VERSION 5.7 ;
  NOWIREEXTENSIONATPIN ON ;
  DIVIDERCHAR "/" ;
  BUSBITCHARS "[]" ;
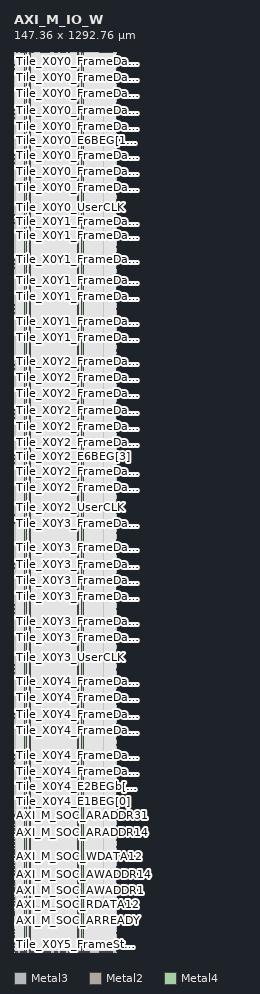
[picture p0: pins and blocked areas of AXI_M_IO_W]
MACRO AXI_M_IO_W
  CLASS BLOCK ;
  FOREIGN AXI_M_IO_W ;
  ORIGIN 0.000 0.000 ;
  SIZE 147.360 BY 1292.760 ;
  PIN AXI_M_SOC_ARADDR0
    DIRECTION OUTPUT ;
    USE SIGNAL ;
    ANTENNADIFFAREA 2.647800 ;
    PORT
      LAYER Metal3 ;
        RECT 0.000 158.980 0.400 159.380 ;
    END
  END AXI_M_SOC_ARADDR0
  PIN AXI_M_SOC_ARADDR1
    DIRECTION OUTPUT ;
    USE SIGNAL ;
    ANTENNADIFFAREA 2.647800 ;
    PORT
      LAYER Metal3 ;
        RECT 0.000 159.820 0.400 160.220 ;
    END
  END AXI_M_SOC_ARADDR1
  PIN AXI_M_SOC_ARADDR10
    DIRECTION OUTPUT ;
    USE SIGNAL ;
    ANTENNADIFFAREA 2.647800 ;
    PORT
      LAYER Metal3 ;
        RECT 0.000 167.380 0.400 167.780 ;
    END
  END AXI_M_SOC_ARADDR10
  PIN AXI_M_SOC_ARADDR11
    DIRECTION OUTPUT ;
    USE SIGNAL ;
    ANTENNADIFFAREA 2.647800 ;
    PORT
      LAYER Metal3 ;
        RECT 0.000 168.220 0.400 168.620 ;
    END
  END AXI_M_SOC_ARADDR11
  PIN AXI_M_SOC_ARADDR12
    DIRECTION OUTPUT ;
    USE SIGNAL ;
    ANTENNADIFFAREA 2.647800 ;
    PORT
      LAYER Metal3 ;
        RECT 0.000 169.060 0.400 169.460 ;
    END
  END AXI_M_SOC_ARADDR12
  PIN AXI_M_SOC_ARADDR13
    DIRECTION OUTPUT ;
    USE SIGNAL ;
    ANTENNADIFFAREA 2.647800 ;
    PORT
      LAYER Metal3 ;
        RECT 0.000 169.900 0.400 170.300 ;
    END
  END AXI_M_SOC_ARADDR13
  PIN AXI_M_SOC_ARADDR14
    DIRECTION OUTPUT ;
    USE SIGNAL ;
    ANTENNADIFFAREA 2.647800 ;
    PORT
      LAYER Metal3 ;
        RECT 0.000 170.740 0.400 171.140 ;
    END
  END AXI_M_SOC_ARADDR14
  PIN AXI_M_SOC_ARADDR15
    DIRECTION OUTPUT ;
    USE SIGNAL ;
    ANTENNADIFFAREA 2.647800 ;
    PORT
      LAYER Metal3 ;
        RECT 0.000 171.580 0.400 171.980 ;
    END
  END AXI_M_SOC_ARADDR15
  PIN AXI_M_SOC_ARADDR16
    DIRECTION OUTPUT ;
    USE SIGNAL ;
    ANTENNADIFFAREA 2.647800 ;
    PORT
      LAYER Metal3 ;
        RECT 0.000 172.420 0.400 172.820 ;
    END
  END AXI_M_SOC_ARADDR16
  PIN AXI_M_SOC_ARADDR17
    DIRECTION OUTPUT ;
    USE SIGNAL ;
    ANTENNADIFFAREA 2.647800 ;
    PORT
      LAYER Metal3 ;
        RECT 0.000 173.260 0.400 173.660 ;
    END
  END AXI_M_SOC_ARADDR17
  PIN AXI_M_SOC_ARADDR18
    DIRECTION OUTPUT ;
    USE SIGNAL ;
    ANTENNADIFFAREA 2.647800 ;
    PORT
      LAYER Metal3 ;
        RECT 0.000 174.100 0.400 174.500 ;
    END
  END AXI_M_SOC_ARADDR18
  PIN AXI_M_SOC_ARADDR19
    DIRECTION OUTPUT ;
    USE SIGNAL ;
    ANTENNADIFFAREA 2.647800 ;
    PORT
      LAYER Metal3 ;
        RECT 0.000 174.940 0.400 175.340 ;
    END
  END AXI_M_SOC_ARADDR19
  PIN AXI_M_SOC_ARADDR2
    DIRECTION OUTPUT ;
    USE SIGNAL ;
    ANTENNADIFFAREA 2.647800 ;
    PORT
      LAYER Metal3 ;
        RECT 0.000 160.660 0.400 161.060 ;
    END
  END AXI_M_SOC_ARADDR2
  PIN AXI_M_SOC_ARADDR20
    DIRECTION OUTPUT ;
    USE SIGNAL ;
    ANTENNADIFFAREA 2.647800 ;
    PORT
      LAYER Metal3 ;
        RECT 0.000 175.780 0.400 176.180 ;
    END
  END AXI_M_SOC_ARADDR20
  PIN AXI_M_SOC_ARADDR21
    DIRECTION OUTPUT ;
    USE SIGNAL ;
    ANTENNADIFFAREA 2.647800 ;
    PORT
      LAYER Metal3 ;
        RECT 0.000 176.620 0.400 177.020 ;
    END
  END AXI_M_SOC_ARADDR21
  PIN AXI_M_SOC_ARADDR22
    DIRECTION OUTPUT ;
    USE SIGNAL ;
    ANTENNADIFFAREA 2.647800 ;
    PORT
      LAYER Metal3 ;
        RECT 0.000 177.460 0.400 177.860 ;
    END
  END AXI_M_SOC_ARADDR22
  PIN AXI_M_SOC_ARADDR23
    DIRECTION OUTPUT ;
    USE SIGNAL ;
    ANTENNADIFFAREA 2.647800 ;
    PORT
      LAYER Metal3 ;
        RECT 0.000 178.300 0.400 178.700 ;
    END
  END AXI_M_SOC_ARADDR23
  PIN AXI_M_SOC_ARADDR24
    DIRECTION OUTPUT ;
    USE SIGNAL ;
    ANTENNADIFFAREA 2.647800 ;
    PORT
      LAYER Metal3 ;
        RECT 0.000 179.140 0.400 179.540 ;
    END
  END AXI_M_SOC_ARADDR24
  PIN AXI_M_SOC_ARADDR25
    DIRECTION OUTPUT ;
    USE SIGNAL ;
    ANTENNADIFFAREA 2.647800 ;
    PORT
      LAYER Metal3 ;
        RECT 0.000 179.980 0.400 180.380 ;
    END
  END AXI_M_SOC_ARADDR25
  PIN AXI_M_SOC_ARADDR26
    DIRECTION OUTPUT ;
    USE SIGNAL ;
    ANTENNADIFFAREA 2.647800 ;
    PORT
      LAYER Metal3 ;
        RECT 0.000 180.820 0.400 181.220 ;
    END
  END AXI_M_SOC_ARADDR26
  PIN AXI_M_SOC_ARADDR27
    DIRECTION OUTPUT ;
    USE SIGNAL ;
    ANTENNADIFFAREA 2.647800 ;
    PORT
      LAYER Metal3 ;
        RECT 0.000 181.660 0.400 182.060 ;
    END
  END AXI_M_SOC_ARADDR27
  PIN AXI_M_SOC_ARADDR28
    DIRECTION OUTPUT ;
    USE SIGNAL ;
    ANTENNADIFFAREA 2.647800 ;
    PORT
      LAYER Metal3 ;
        RECT 0.000 182.500 0.400 182.900 ;
    END
  END AXI_M_SOC_ARADDR28
  PIN AXI_M_SOC_ARADDR29
    DIRECTION OUTPUT ;
    USE SIGNAL ;
    ANTENNADIFFAREA 2.647800 ;
    PORT
      LAYER Metal3 ;
        RECT 0.000 183.340 0.400 183.740 ;
    END
  END AXI_M_SOC_ARADDR29
  PIN AXI_M_SOC_ARADDR3
    DIRECTION OUTPUT ;
    USE SIGNAL ;
    ANTENNADIFFAREA 2.647800 ;
    PORT
      LAYER Metal3 ;
        RECT 0.000 161.500 0.400 161.900 ;
    END
  END AXI_M_SOC_ARADDR3
  PIN AXI_M_SOC_ARADDR30
    DIRECTION OUTPUT ;
    USE SIGNAL ;
    ANTENNADIFFAREA 2.647800 ;
    PORT
      LAYER Metal3 ;
        RECT 0.000 184.180 0.400 184.580 ;
    END
  END AXI_M_SOC_ARADDR30
  PIN AXI_M_SOC_ARADDR31
    DIRECTION OUTPUT ;
    USE SIGNAL ;
    ANTENNADIFFAREA 2.647800 ;
    PORT
      LAYER Metal3 ;
        RECT 0.000 185.020 0.400 185.420 ;
    END
  END AXI_M_SOC_ARADDR31
  PIN AXI_M_SOC_ARADDR4
    DIRECTION OUTPUT ;
    USE SIGNAL ;
    ANTENNADIFFAREA 2.647800 ;
    PORT
      LAYER Metal3 ;
        RECT 0.000 162.340 0.400 162.740 ;
    END
  END AXI_M_SOC_ARADDR4
  PIN AXI_M_SOC_ARADDR5
    DIRECTION OUTPUT ;
    USE SIGNAL ;
    ANTENNADIFFAREA 2.647800 ;
    PORT
      LAYER Metal3 ;
        RECT 0.000 163.180 0.400 163.580 ;
    END
  END AXI_M_SOC_ARADDR5
  PIN AXI_M_SOC_ARADDR6
    DIRECTION OUTPUT ;
    USE SIGNAL ;
    ANTENNADIFFAREA 2.647800 ;
    PORT
      LAYER Metal3 ;
        RECT 0.000 164.020 0.400 164.420 ;
    END
  END AXI_M_SOC_ARADDR6
  PIN AXI_M_SOC_ARADDR7
    DIRECTION OUTPUT ;
    USE SIGNAL ;
    ANTENNADIFFAREA 2.647800 ;
    PORT
      LAYER Metal3 ;
        RECT 0.000 164.860 0.400 165.260 ;
    END
  END AXI_M_SOC_ARADDR7
  PIN AXI_M_SOC_ARADDR8
    DIRECTION OUTPUT ;
    USE SIGNAL ;
    ANTENNADIFFAREA 2.647800 ;
    PORT
      LAYER Metal3 ;
        RECT 0.000 165.700 0.400 166.100 ;
    END
  END AXI_M_SOC_ARADDR8
  PIN AXI_M_SOC_ARADDR9
    DIRECTION OUTPUT ;
    USE SIGNAL ;
    ANTENNADIFFAREA 2.647800 ;
    PORT
      LAYER Metal3 ;
        RECT 0.000 166.540 0.400 166.940 ;
    END
  END AXI_M_SOC_ARADDR9
  PIN AXI_M_SOC_ARBURST0
    DIRECTION OUTPUT ;
    USE SIGNAL ;
    ANTENNADIFFAREA 2.664600 ;
    PORT
      LAYER Metal3 ;
        RECT 0.000 195.100 0.400 195.500 ;
    END
  END AXI_M_SOC_ARBURST0
  PIN AXI_M_SOC_ARBURST1
    DIRECTION OUTPUT ;
    USE SIGNAL ;
    ANTENNADIFFAREA 2.677400 ;
    PORT
      LAYER Metal3 ;
        RECT 0.000 195.940 0.400 196.340 ;
    END
  END AXI_M_SOC_ARBURST1
  PIN AXI_M_SOC_ARLEN0
    DIRECTION OUTPUT ;
    USE SIGNAL ;
    ANTENNADIFFAREA 2.677400 ;
    PORT
      LAYER Metal3 ;
        RECT 0.000 185.860 0.400 186.260 ;
    END
  END AXI_M_SOC_ARLEN0
  PIN AXI_M_SOC_ARLEN1
    DIRECTION OUTPUT ;
    USE SIGNAL ;
    ANTENNADIFFAREA 3.151000 ;
    PORT
      LAYER Metal3 ;
        RECT 0.000 186.700 0.400 187.100 ;
    END
  END AXI_M_SOC_ARLEN1
  PIN AXI_M_SOC_ARLEN2
    DIRECTION OUTPUT ;
    USE SIGNAL ;
    ANTENNADIFFAREA 2.677400 ;
    PORT
      LAYER Metal3 ;
        RECT 0.000 187.540 0.400 187.940 ;
    END
  END AXI_M_SOC_ARLEN2
  PIN AXI_M_SOC_ARLEN3
    DIRECTION OUTPUT ;
    USE SIGNAL ;
    ANTENNADIFFAREA 3.151000 ;
    PORT
      LAYER Metal3 ;
        RECT 0.000 188.380 0.400 188.780 ;
    END
  END AXI_M_SOC_ARLEN3
  PIN AXI_M_SOC_ARLEN4
    DIRECTION OUTPUT ;
    USE SIGNAL ;
    ANTENNADIFFAREA 3.151000 ;
    PORT
      LAYER Metal3 ;
        RECT 0.000 189.220 0.400 189.620 ;
    END
  END AXI_M_SOC_ARLEN4
  PIN AXI_M_SOC_ARLEN5
    DIRECTION OUTPUT ;
    USE SIGNAL ;
    ANTENNADIFFAREA 3.151000 ;
    PORT
      LAYER Metal3 ;
        RECT 0.000 190.060 0.400 190.460 ;
    END
  END AXI_M_SOC_ARLEN5
  PIN AXI_M_SOC_ARLEN6
    DIRECTION OUTPUT ;
    USE SIGNAL ;
    ANTENNADIFFAREA 3.151000 ;
    PORT
      LAYER Metal3 ;
        RECT 0.000 190.900 0.400 191.300 ;
    END
  END AXI_M_SOC_ARLEN6
  PIN AXI_M_SOC_ARLEN7
    DIRECTION OUTPUT ;
    USE SIGNAL ;
    ANTENNADIFFAREA 3.151000 ;
    PORT
      LAYER Metal3 ;
        RECT 0.000 191.740 0.400 192.140 ;
    END
  END AXI_M_SOC_ARLEN7
  PIN AXI_M_SOC_ARREADY
    DIRECTION INPUT ;
    USE SIGNAL ;
    ANTENNAGATEAREA 1.279200 ;
    ANTENNADIFFAREA 12.092400 ;
    PORT
      LAYER Metal3 ;
        RECT 0.000 56.500 0.400 56.900 ;
    END
  END AXI_M_SOC_ARREADY
  PIN AXI_M_SOC_ARSIZE0
    DIRECTION OUTPUT ;
    USE SIGNAL ;
    ANTENNADIFFAREA 2.677400 ;
    PORT
      LAYER Metal3 ;
        RECT 0.000 192.580 0.400 192.980 ;
    END
  END AXI_M_SOC_ARSIZE0
  PIN AXI_M_SOC_ARSIZE1
    DIRECTION OUTPUT ;
    USE SIGNAL ;
    ANTENNADIFFAREA 2.664600 ;
    PORT
      LAYER Metal3 ;
        RECT 0.000 193.420 0.400 193.820 ;
    END
  END AXI_M_SOC_ARSIZE1
  PIN AXI_M_SOC_ARSIZE2
    DIRECTION OUTPUT ;
    USE SIGNAL ;
    ANTENNADIFFAREA 2.677400 ;
    PORT
      LAYER Metal3 ;
        RECT 0.000 194.260 0.400 194.660 ;
    END
  END AXI_M_SOC_ARSIZE2
  PIN AXI_M_SOC_ARVALID
    DIRECTION OUTPUT ;
    USE SIGNAL ;
    ANTENNADIFFAREA 2.647800 ;
    PORT
      LAYER Metal3 ;
        RECT 0.000 196.780 0.400 197.180 ;
    END
  END AXI_M_SOC_ARVALID
  PIN AXI_M_SOC_AWADDR0
    DIRECTION OUTPUT ;
    USE SIGNAL ;
    ANTENNADIFFAREA 2.647800 ;
    PORT
      LAYER Metal3 ;
        RECT 0.000 87.580 0.400 87.980 ;
    END
  END AXI_M_SOC_AWADDR0
  PIN AXI_M_SOC_AWADDR1
    DIRECTION OUTPUT ;
    USE SIGNAL ;
    ANTENNADIFFAREA 2.647800 ;
    PORT
      LAYER Metal3 ;
        RECT 0.000 88.420 0.400 88.820 ;
    END
  END AXI_M_SOC_AWADDR1
  PIN AXI_M_SOC_AWADDR10
    DIRECTION OUTPUT ;
    USE SIGNAL ;
    ANTENNADIFFAREA 2.647800 ;
    PORT
      LAYER Metal3 ;
        RECT 0.000 95.980 0.400 96.380 ;
    END
  END AXI_M_SOC_AWADDR10
  PIN AXI_M_SOC_AWADDR11
    DIRECTION OUTPUT ;
    USE SIGNAL ;
    ANTENNADIFFAREA 2.647800 ;
    PORT
      LAYER Metal3 ;
        RECT 0.000 96.820 0.400 97.220 ;
    END
  END AXI_M_SOC_AWADDR11
  PIN AXI_M_SOC_AWADDR12
    DIRECTION OUTPUT ;
    USE SIGNAL ;
    ANTENNADIFFAREA 2.647800 ;
    PORT
      LAYER Metal3 ;
        RECT 0.000 97.660 0.400 98.060 ;
    END
  END AXI_M_SOC_AWADDR12
  PIN AXI_M_SOC_AWADDR13
    DIRECTION OUTPUT ;
    USE SIGNAL ;
    ANTENNADIFFAREA 2.647800 ;
    PORT
      LAYER Metal3 ;
        RECT 0.000 98.500 0.400 98.900 ;
    END
  END AXI_M_SOC_AWADDR13
  PIN AXI_M_SOC_AWADDR14
    DIRECTION OUTPUT ;
    USE SIGNAL ;
    ANTENNADIFFAREA 2.647800 ;
    PORT
      LAYER Metal3 ;
        RECT 0.000 99.340 0.400 99.740 ;
    END
  END AXI_M_SOC_AWADDR14
  PIN AXI_M_SOC_AWADDR15
    DIRECTION OUTPUT ;
    USE SIGNAL ;
    ANTENNADIFFAREA 2.647800 ;
    PORT
      LAYER Metal3 ;
        RECT 0.000 100.180 0.400 100.580 ;
    END
  END AXI_M_SOC_AWADDR15
  PIN AXI_M_SOC_AWADDR16
    DIRECTION OUTPUT ;
    USE SIGNAL ;
    ANTENNADIFFAREA 2.647800 ;
    PORT
      LAYER Metal3 ;
        RECT 0.000 101.020 0.400 101.420 ;
    END
  END AXI_M_SOC_AWADDR16
  PIN AXI_M_SOC_AWADDR17
    DIRECTION OUTPUT ;
    USE SIGNAL ;
    ANTENNADIFFAREA 2.647800 ;
    PORT
      LAYER Metal3 ;
        RECT 0.000 101.860 0.400 102.260 ;
    END
  END AXI_M_SOC_AWADDR17
  PIN AXI_M_SOC_AWADDR18
    DIRECTION OUTPUT ;
    USE SIGNAL ;
    ANTENNADIFFAREA 2.647800 ;
    PORT
      LAYER Metal3 ;
        RECT 0.000 102.700 0.400 103.100 ;
    END
  END AXI_M_SOC_AWADDR18
  PIN AXI_M_SOC_AWADDR19
    DIRECTION OUTPUT ;
    USE SIGNAL ;
    ANTENNADIFFAREA 2.647800 ;
    PORT
      LAYER Metal3 ;
        RECT 0.000 103.540 0.400 103.940 ;
    END
  END AXI_M_SOC_AWADDR19
  PIN AXI_M_SOC_AWADDR2
    DIRECTION OUTPUT ;
    USE SIGNAL ;
    ANTENNADIFFAREA 2.647800 ;
    PORT
      LAYER Metal3 ;
        RECT 0.000 89.260 0.400 89.660 ;
    END
  END AXI_M_SOC_AWADDR2
  PIN AXI_M_SOC_AWADDR20
    DIRECTION OUTPUT ;
    USE SIGNAL ;
    ANTENNADIFFAREA 2.647800 ;
    PORT
      LAYER Metal3 ;
        RECT 0.000 104.380 0.400 104.780 ;
    END
  END AXI_M_SOC_AWADDR20
  PIN AXI_M_SOC_AWADDR21
    DIRECTION OUTPUT ;
    USE SIGNAL ;
    ANTENNADIFFAREA 2.647800 ;
    PORT
      LAYER Metal3 ;
        RECT 0.000 105.220 0.400 105.620 ;
    END
  END AXI_M_SOC_AWADDR21
  PIN AXI_M_SOC_AWADDR22
    DIRECTION OUTPUT ;
    USE SIGNAL ;
    ANTENNADIFFAREA 2.647800 ;
    PORT
      LAYER Metal3 ;
        RECT 0.000 106.060 0.400 106.460 ;
    END
  END AXI_M_SOC_AWADDR22
  PIN AXI_M_SOC_AWADDR23
    DIRECTION OUTPUT ;
    USE SIGNAL ;
    ANTENNADIFFAREA 2.647800 ;
    PORT
      LAYER Metal3 ;
        RECT 0.000 106.900 0.400 107.300 ;
    END
  END AXI_M_SOC_AWADDR23
  PIN AXI_M_SOC_AWADDR24
    DIRECTION OUTPUT ;
    USE SIGNAL ;
    ANTENNADIFFAREA 2.647800 ;
    PORT
      LAYER Metal3 ;
        RECT 0.000 107.740 0.400 108.140 ;
    END
  END AXI_M_SOC_AWADDR24
  PIN AXI_M_SOC_AWADDR25
    DIRECTION OUTPUT ;
    USE SIGNAL ;
    ANTENNADIFFAREA 2.647800 ;
    PORT
      LAYER Metal3 ;
        RECT 0.000 108.580 0.400 108.980 ;
    END
  END AXI_M_SOC_AWADDR25
  PIN AXI_M_SOC_AWADDR26
    DIRECTION OUTPUT ;
    USE SIGNAL ;
    ANTENNADIFFAREA 2.647800 ;
    PORT
      LAYER Metal3 ;
        RECT 0.000 109.420 0.400 109.820 ;
    END
  END AXI_M_SOC_AWADDR26
  PIN AXI_M_SOC_AWADDR27
    DIRECTION OUTPUT ;
    USE SIGNAL ;
    ANTENNADIFFAREA 2.647800 ;
    PORT
      LAYER Metal3 ;
        RECT 0.000 110.260 0.400 110.660 ;
    END
  END AXI_M_SOC_AWADDR27
  PIN AXI_M_SOC_AWADDR28
    DIRECTION OUTPUT ;
    USE SIGNAL ;
    ANTENNADIFFAREA 2.647800 ;
    PORT
      LAYER Metal3 ;
        RECT 0.000 111.100 0.400 111.500 ;
    END
  END AXI_M_SOC_AWADDR28
  PIN AXI_M_SOC_AWADDR29
    DIRECTION OUTPUT ;
    USE SIGNAL ;
    ANTENNADIFFAREA 2.647800 ;
    PORT
      LAYER Metal3 ;
        RECT 0.000 111.940 0.400 112.340 ;
    END
  END AXI_M_SOC_AWADDR29
  PIN AXI_M_SOC_AWADDR3
    DIRECTION OUTPUT ;
    USE SIGNAL ;
    ANTENNADIFFAREA 2.647800 ;
    PORT
      LAYER Metal3 ;
        RECT 0.000 90.100 0.400 90.500 ;
    END
  END AXI_M_SOC_AWADDR3
  PIN AXI_M_SOC_AWADDR30
    DIRECTION OUTPUT ;
    USE SIGNAL ;
    ANTENNADIFFAREA 2.647800 ;
    PORT
      LAYER Metal3 ;
        RECT 0.000 112.780 0.400 113.180 ;
    END
  END AXI_M_SOC_AWADDR30
  PIN AXI_M_SOC_AWADDR31
    DIRECTION OUTPUT ;
    USE SIGNAL ;
    ANTENNADIFFAREA 2.647800 ;
    PORT
      LAYER Metal3 ;
        RECT 0.000 113.620 0.400 114.020 ;
    END
  END AXI_M_SOC_AWADDR31
  PIN AXI_M_SOC_AWADDR4
    DIRECTION OUTPUT ;
    USE SIGNAL ;
    ANTENNADIFFAREA 2.647800 ;
    PORT
      LAYER Metal3 ;
        RECT 0.000 90.940 0.400 91.340 ;
    END
  END AXI_M_SOC_AWADDR4
  PIN AXI_M_SOC_AWADDR5
    DIRECTION OUTPUT ;
    USE SIGNAL ;
    ANTENNADIFFAREA 2.647800 ;
    PORT
      LAYER Metal3 ;
        RECT 0.000 91.780 0.400 92.180 ;
    END
  END AXI_M_SOC_AWADDR5
  PIN AXI_M_SOC_AWADDR6
    DIRECTION OUTPUT ;
    USE SIGNAL ;
    ANTENNADIFFAREA 2.647800 ;
    PORT
      LAYER Metal3 ;
        RECT 0.000 92.620 0.400 93.020 ;
    END
  END AXI_M_SOC_AWADDR6
  PIN AXI_M_SOC_AWADDR7
    DIRECTION OUTPUT ;
    USE SIGNAL ;
    ANTENNADIFFAREA 2.647800 ;
    PORT
      LAYER Metal3 ;
        RECT 0.000 93.460 0.400 93.860 ;
    END
  END AXI_M_SOC_AWADDR7
  PIN AXI_M_SOC_AWADDR8
    DIRECTION OUTPUT ;
    USE SIGNAL ;
    ANTENNADIFFAREA 2.647800 ;
    PORT
      LAYER Metal3 ;
        RECT 0.000 94.300 0.400 94.700 ;
    END
  END AXI_M_SOC_AWADDR8
  PIN AXI_M_SOC_AWADDR9
    DIRECTION OUTPUT ;
    USE SIGNAL ;
    ANTENNADIFFAREA 2.647800 ;
    PORT
      LAYER Metal3 ;
        RECT 0.000 95.140 0.400 95.540 ;
    END
  END AXI_M_SOC_AWADDR9
  PIN AXI_M_SOC_AWBURST0
    DIRECTION OUTPUT ;
    USE SIGNAL ;
    ANTENNADIFFAREA 2.664600 ;
    PORT
      LAYER Metal3 ;
        RECT 0.000 123.700 0.400 124.100 ;
    END
  END AXI_M_SOC_AWBURST0
  PIN AXI_M_SOC_AWBURST1
    DIRECTION OUTPUT ;
    USE SIGNAL ;
    ANTENNADIFFAREA 2.677400 ;
    PORT
      LAYER Metal3 ;
        RECT 0.000 124.540 0.400 124.940 ;
    END
  END AXI_M_SOC_AWBURST1
  PIN AXI_M_SOC_AWLEN0
    DIRECTION OUTPUT ;
    USE SIGNAL ;
    ANTENNADIFFAREA 2.677400 ;
    PORT
      LAYER Metal3 ;
        RECT 0.000 114.460 0.400 114.860 ;
    END
  END AXI_M_SOC_AWLEN0
  PIN AXI_M_SOC_AWLEN1
    DIRECTION OUTPUT ;
    USE SIGNAL ;
    ANTENNADIFFAREA 2.677400 ;
    PORT
      LAYER Metal3 ;
        RECT 0.000 115.300 0.400 115.700 ;
    END
  END AXI_M_SOC_AWLEN1
  PIN AXI_M_SOC_AWLEN2
    DIRECTION OUTPUT ;
    USE SIGNAL ;
    ANTENNADIFFAREA 2.677400 ;
    PORT
      LAYER Metal3 ;
        RECT 0.000 116.140 0.400 116.540 ;
    END
  END AXI_M_SOC_AWLEN2
  PIN AXI_M_SOC_AWLEN3
    DIRECTION OUTPUT ;
    USE SIGNAL ;
    ANTENNADIFFAREA 2.677400 ;
    PORT
      LAYER Metal3 ;
        RECT 0.000 116.980 0.400 117.380 ;
    END
  END AXI_M_SOC_AWLEN3
  PIN AXI_M_SOC_AWLEN4
    DIRECTION OUTPUT ;
    USE SIGNAL ;
    ANTENNADIFFAREA 2.677400 ;
    PORT
      LAYER Metal3 ;
        RECT 0.000 117.820 0.400 118.220 ;
    END
  END AXI_M_SOC_AWLEN4
  PIN AXI_M_SOC_AWLEN5
    DIRECTION OUTPUT ;
    USE SIGNAL ;
    ANTENNADIFFAREA 2.677400 ;
    PORT
      LAYER Metal3 ;
        RECT 0.000 118.660 0.400 119.060 ;
    END
  END AXI_M_SOC_AWLEN5
  PIN AXI_M_SOC_AWLEN6
    DIRECTION OUTPUT ;
    USE SIGNAL ;
    ANTENNADIFFAREA 2.677400 ;
    PORT
      LAYER Metal3 ;
        RECT 0.000 119.500 0.400 119.900 ;
    END
  END AXI_M_SOC_AWLEN6
  PIN AXI_M_SOC_AWLEN7
    DIRECTION OUTPUT ;
    USE SIGNAL ;
    ANTENNADIFFAREA 2.677400 ;
    PORT
      LAYER Metal3 ;
        RECT 0.000 120.340 0.400 120.740 ;
    END
  END AXI_M_SOC_AWLEN7
  PIN AXI_M_SOC_AWREADY
    DIRECTION INPUT ;
    USE SIGNAL ;
    ANTENNAGATEAREA 1.279200 ;
    ANTENNADIFFAREA 12.092400 ;
    PORT
      LAYER Metal3 ;
        RECT 0.000 52.300 0.400 52.700 ;
    END
  END AXI_M_SOC_AWREADY
  PIN AXI_M_SOC_AWSIZE0
    DIRECTION OUTPUT ;
    USE SIGNAL ;
    ANTENNADIFFAREA 2.677400 ;
    PORT
      LAYER Metal3 ;
        RECT 0.000 121.180 0.400 121.580 ;
    END
  END AXI_M_SOC_AWSIZE0
  PIN AXI_M_SOC_AWSIZE1
    DIRECTION OUTPUT ;
    USE SIGNAL ;
    ANTENNADIFFAREA 2.664600 ;
    PORT
      LAYER Metal3 ;
        RECT 0.000 122.020 0.400 122.420 ;
    END
  END AXI_M_SOC_AWSIZE1
  PIN AXI_M_SOC_AWSIZE2
    DIRECTION OUTPUT ;
    USE SIGNAL ;
    ANTENNADIFFAREA 2.677400 ;
    PORT
      LAYER Metal3 ;
        RECT 0.000 122.860 0.400 123.260 ;
    END
  END AXI_M_SOC_AWSIZE2
  PIN AXI_M_SOC_AWVALID
    DIRECTION OUTPUT ;
    USE SIGNAL ;
    ANTENNAGATEAREA 0.213200 ;
    ANTENNADIFFAREA 4.663200 ;
    PORT
      LAYER Metal3 ;
        RECT 0.000 125.380 0.400 125.780 ;
    END
  END AXI_M_SOC_AWVALID
  PIN AXI_M_SOC_BREADY
    DIRECTION OUTPUT ;
    USE SIGNAL ;
    ANTENNADIFFAREA 2.647800 ;
    PORT
      LAYER Metal3 ;
        RECT 0.000 158.140 0.400 158.540 ;
    END
  END AXI_M_SOC_BREADY
  PIN AXI_M_SOC_BRESP0
    DIRECTION INPUT ;
    USE SIGNAL ;
    ANTENNAGATEAREA 1.279200 ;
    ANTENNADIFFAREA 12.092400 ;
    PORT
      LAYER Metal3 ;
        RECT 0.000 53.980 0.400 54.380 ;
    END
  END AXI_M_SOC_BRESP0
  PIN AXI_M_SOC_BRESP1
    DIRECTION INPUT ;
    USE SIGNAL ;
    ANTENNAGATEAREA 1.279200 ;
    ANTENNADIFFAREA 12.092400 ;
    PORT
      LAYER Metal3 ;
        RECT 0.000 54.820 0.400 55.220 ;
    END
  END AXI_M_SOC_BRESP1
  PIN AXI_M_SOC_BVALID
    DIRECTION INPUT ;
    USE SIGNAL ;
    ANTENNAGATEAREA 1.279200 ;
    ANTENNADIFFAREA 12.092400 ;
    PORT
      LAYER Metal3 ;
        RECT 0.000 55.660 0.400 56.060 ;
    END
  END AXI_M_SOC_BVALID
  PIN AXI_M_SOC_RDATA0
    DIRECTION INPUT ;
    USE SIGNAL ;
    ANTENNAGATEAREA 1.279200 ;
    ANTENNADIFFAREA 12.092400 ;
    PORT
      LAYER Metal3 ;
        RECT 0.000 57.340 0.400 57.740 ;
    END
  END AXI_M_SOC_RDATA0
  PIN AXI_M_SOC_RDATA1
    DIRECTION INPUT ;
    USE SIGNAL ;
    ANTENNAGATEAREA 1.279200 ;
    ANTENNADIFFAREA 12.092400 ;
    PORT
      LAYER Metal3 ;
        RECT 0.000 58.180 0.400 58.580 ;
    END
  END AXI_M_SOC_RDATA1
  PIN AXI_M_SOC_RDATA10
    DIRECTION INPUT ;
    USE SIGNAL ;
    ANTENNAGATEAREA 1.279200 ;
    ANTENNADIFFAREA 12.092400 ;
    PORT
      LAYER Metal3 ;
        RECT 0.000 65.740 0.400 66.140 ;
    END
  END AXI_M_SOC_RDATA10
  PIN AXI_M_SOC_RDATA11
    DIRECTION INPUT ;
    USE SIGNAL ;
    ANTENNAGATEAREA 1.279200 ;
    ANTENNADIFFAREA 12.092400 ;
    PORT
      LAYER Metal3 ;
        RECT 0.000 66.580 0.400 66.980 ;
    END
  END AXI_M_SOC_RDATA11
  PIN AXI_M_SOC_RDATA12
    DIRECTION INPUT ;
    USE SIGNAL ;
    ANTENNAGATEAREA 1.279200 ;
    ANTENNADIFFAREA 12.092400 ;
    PORT
      LAYER Metal3 ;
        RECT 0.000 67.420 0.400 67.820 ;
    END
  END AXI_M_SOC_RDATA12
  PIN AXI_M_SOC_RDATA13
    DIRECTION INPUT ;
    USE SIGNAL ;
    ANTENNAGATEAREA 1.279200 ;
    ANTENNADIFFAREA 12.092400 ;
    PORT
      LAYER Metal3 ;
        RECT 0.000 68.260 0.400 68.660 ;
    END
  END AXI_M_SOC_RDATA13
  PIN AXI_M_SOC_RDATA14
    DIRECTION INPUT ;
    USE SIGNAL ;
    ANTENNAGATEAREA 1.279200 ;
    ANTENNADIFFAREA 12.092400 ;
    PORT
      LAYER Metal3 ;
        RECT 0.000 69.100 0.400 69.500 ;
    END
  END AXI_M_SOC_RDATA14
  PIN AXI_M_SOC_RDATA15
    DIRECTION INPUT ;
    USE SIGNAL ;
    ANTENNAGATEAREA 1.279200 ;
    ANTENNADIFFAREA 12.092400 ;
    PORT
      LAYER Metal3 ;
        RECT 0.000 69.940 0.400 70.340 ;
    END
  END AXI_M_SOC_RDATA15
  PIN AXI_M_SOC_RDATA16
    DIRECTION INPUT ;
    USE SIGNAL ;
    ANTENNAGATEAREA 1.279200 ;
    ANTENNADIFFAREA 12.092400 ;
    PORT
      LAYER Metal3 ;
        RECT 0.000 70.780 0.400 71.180 ;
    END
  END AXI_M_SOC_RDATA16
  PIN AXI_M_SOC_RDATA17
    DIRECTION INPUT ;
    USE SIGNAL ;
    ANTENNAGATEAREA 1.279200 ;
    ANTENNADIFFAREA 12.092400 ;
    PORT
      LAYER Metal3 ;
        RECT 0.000 71.620 0.400 72.020 ;
    END
  END AXI_M_SOC_RDATA17
  PIN AXI_M_SOC_RDATA18
    DIRECTION INPUT ;
    USE SIGNAL ;
    ANTENNAGATEAREA 1.279200 ;
    ANTENNADIFFAREA 12.092400 ;
    PORT
      LAYER Metal3 ;
        RECT 0.000 72.460 0.400 72.860 ;
    END
  END AXI_M_SOC_RDATA18
  PIN AXI_M_SOC_RDATA19
    DIRECTION INPUT ;
    USE SIGNAL ;
    ANTENNAGATEAREA 1.279200 ;
    ANTENNADIFFAREA 12.092400 ;
    PORT
      LAYER Metal3 ;
        RECT 0.000 73.300 0.400 73.700 ;
    END
  END AXI_M_SOC_RDATA19
  PIN AXI_M_SOC_RDATA2
    DIRECTION INPUT ;
    USE SIGNAL ;
    ANTENNAGATEAREA 1.279200 ;
    ANTENNADIFFAREA 12.092400 ;
    PORT
      LAYER Metal3 ;
        RECT 0.000 59.020 0.400 59.420 ;
    END
  END AXI_M_SOC_RDATA2
  PIN AXI_M_SOC_RDATA20
    DIRECTION INPUT ;
    USE SIGNAL ;
    ANTENNAGATEAREA 1.279200 ;
    ANTENNADIFFAREA 12.092400 ;
    PORT
      LAYER Metal3 ;
        RECT 0.000 74.140 0.400 74.540 ;
    END
  END AXI_M_SOC_RDATA20
  PIN AXI_M_SOC_RDATA21
    DIRECTION INPUT ;
    USE SIGNAL ;
    ANTENNAGATEAREA 1.279200 ;
    ANTENNADIFFAREA 12.092400 ;
    PORT
      LAYER Metal3 ;
        RECT 0.000 74.980 0.400 75.380 ;
    END
  END AXI_M_SOC_RDATA21
  PIN AXI_M_SOC_RDATA22
    DIRECTION INPUT ;
    USE SIGNAL ;
    ANTENNAGATEAREA 1.279200 ;
    ANTENNADIFFAREA 12.092400 ;
    PORT
      LAYER Metal3 ;
        RECT 0.000 75.820 0.400 76.220 ;
    END
  END AXI_M_SOC_RDATA22
  PIN AXI_M_SOC_RDATA23
    DIRECTION INPUT ;
    USE SIGNAL ;
    ANTENNAGATEAREA 1.279200 ;
    ANTENNADIFFAREA 12.092400 ;
    PORT
      LAYER Metal3 ;
        RECT 0.000 76.660 0.400 77.060 ;
    END
  END AXI_M_SOC_RDATA23
  PIN AXI_M_SOC_RDATA24
    DIRECTION INPUT ;
    USE SIGNAL ;
    ANTENNAGATEAREA 1.279200 ;
    ANTENNADIFFAREA 12.092400 ;
    PORT
      LAYER Metal3 ;
        RECT 0.000 77.500 0.400 77.900 ;
    END
  END AXI_M_SOC_RDATA24
  PIN AXI_M_SOC_RDATA25
    DIRECTION INPUT ;
    USE SIGNAL ;
    ANTENNAGATEAREA 1.279200 ;
    ANTENNADIFFAREA 12.092400 ;
    PORT
      LAYER Metal3 ;
        RECT 0.000 78.340 0.400 78.740 ;
    END
  END AXI_M_SOC_RDATA25
  PIN AXI_M_SOC_RDATA26
    DIRECTION INPUT ;
    USE SIGNAL ;
    ANTENNAGATEAREA 1.279200 ;
    ANTENNADIFFAREA 12.092400 ;
    PORT
      LAYER Metal3 ;
        RECT 0.000 79.180 0.400 79.580 ;
    END
  END AXI_M_SOC_RDATA26
  PIN AXI_M_SOC_RDATA27
    DIRECTION INPUT ;
    USE SIGNAL ;
    ANTENNAGATEAREA 1.279200 ;
    ANTENNADIFFAREA 12.092400 ;
    PORT
      LAYER Metal3 ;
        RECT 0.000 80.020 0.400 80.420 ;
    END
  END AXI_M_SOC_RDATA27
  PIN AXI_M_SOC_RDATA28
    DIRECTION INPUT ;
    USE SIGNAL ;
    ANTENNAGATEAREA 1.279200 ;
    ANTENNADIFFAREA 12.092400 ;
    PORT
      LAYER Metal3 ;
        RECT 0.000 80.860 0.400 81.260 ;
    END
  END AXI_M_SOC_RDATA28
  PIN AXI_M_SOC_RDATA29
    DIRECTION INPUT ;
    USE SIGNAL ;
    ANTENNAGATEAREA 1.279200 ;
    ANTENNADIFFAREA 12.092400 ;
    PORT
      LAYER Metal3 ;
        RECT 0.000 81.700 0.400 82.100 ;
    END
  END AXI_M_SOC_RDATA29
  PIN AXI_M_SOC_RDATA3
    DIRECTION INPUT ;
    USE SIGNAL ;
    ANTENNAGATEAREA 1.279200 ;
    ANTENNADIFFAREA 12.092400 ;
    PORT
      LAYER Metal3 ;
        RECT 0.000 59.860 0.400 60.260 ;
    END
  END AXI_M_SOC_RDATA3
  PIN AXI_M_SOC_RDATA30
    DIRECTION INPUT ;
    USE SIGNAL ;
    ANTENNAGATEAREA 1.279200 ;
    ANTENNADIFFAREA 12.092400 ;
    PORT
      LAYER Metal3 ;
        RECT 0.000 82.540 0.400 82.940 ;
    END
  END AXI_M_SOC_RDATA30
  PIN AXI_M_SOC_RDATA31
    DIRECTION INPUT ;
    USE SIGNAL ;
    ANTENNAGATEAREA 1.279200 ;
    ANTENNADIFFAREA 12.092400 ;
    PORT
      LAYER Metal3 ;
        RECT 0.000 83.380 0.400 83.780 ;
    END
  END AXI_M_SOC_RDATA31
  PIN AXI_M_SOC_RDATA4
    DIRECTION INPUT ;
    USE SIGNAL ;
    ANTENNAGATEAREA 1.279200 ;
    ANTENNADIFFAREA 12.092400 ;
    PORT
      LAYER Metal3 ;
        RECT 0.000 60.700 0.400 61.100 ;
    END
  END AXI_M_SOC_RDATA4
  PIN AXI_M_SOC_RDATA5
    DIRECTION INPUT ;
    USE SIGNAL ;
    ANTENNAGATEAREA 1.279200 ;
    ANTENNADIFFAREA 12.092400 ;
    PORT
      LAYER Metal3 ;
        RECT 0.000 61.540 0.400 61.940 ;
    END
  END AXI_M_SOC_RDATA5
  PIN AXI_M_SOC_RDATA6
    DIRECTION INPUT ;
    USE SIGNAL ;
    ANTENNAGATEAREA 1.279200 ;
    ANTENNADIFFAREA 12.092400 ;
    PORT
      LAYER Metal3 ;
        RECT 0.000 62.380 0.400 62.780 ;
    END
  END AXI_M_SOC_RDATA6
  PIN AXI_M_SOC_RDATA7
    DIRECTION INPUT ;
    USE SIGNAL ;
    ANTENNAGATEAREA 1.279200 ;
    ANTENNADIFFAREA 12.092400 ;
    PORT
      LAYER Metal3 ;
        RECT 0.000 63.220 0.400 63.620 ;
    END
  END AXI_M_SOC_RDATA7
  PIN AXI_M_SOC_RDATA8
    DIRECTION INPUT ;
    USE SIGNAL ;
    ANTENNAGATEAREA 1.279200 ;
    ANTENNADIFFAREA 12.092400 ;
    PORT
      LAYER Metal3 ;
        RECT 0.000 64.060 0.400 64.460 ;
    END
  END AXI_M_SOC_RDATA8
  PIN AXI_M_SOC_RDATA9
    DIRECTION INPUT ;
    USE SIGNAL ;
    ANTENNAGATEAREA 1.279200 ;
    ANTENNADIFFAREA 12.092400 ;
    PORT
      LAYER Metal3 ;
        RECT 0.000 64.900 0.400 65.300 ;
    END
  END AXI_M_SOC_RDATA9
  PIN AXI_M_SOC_RLAST
    DIRECTION INPUT ;
    USE SIGNAL ;
    ANTENNAGATEAREA 1.279200 ;
    ANTENNADIFFAREA 12.092400 ;
    PORT
      LAYER Metal3 ;
        RECT 0.000 85.900 0.400 86.300 ;
    END
  END AXI_M_SOC_RLAST
  PIN AXI_M_SOC_RREADY
    DIRECTION OUTPUT ;
    USE SIGNAL ;
    ANTENNADIFFAREA 2.647800 ;
    PORT
      LAYER Metal3 ;
        RECT 0.000 197.620 0.400 198.020 ;
    END
  END AXI_M_SOC_RREADY
  PIN AXI_M_SOC_RRESP0
    DIRECTION INPUT ;
    USE SIGNAL ;
    ANTENNAGATEAREA 1.279200 ;
    ANTENNADIFFAREA 12.092400 ;
    PORT
      LAYER Metal3 ;
        RECT 0.000 84.220 0.400 84.620 ;
    END
  END AXI_M_SOC_RRESP0
  PIN AXI_M_SOC_RRESP1
    DIRECTION INPUT ;
    USE SIGNAL ;
    ANTENNAGATEAREA 1.279200 ;
    ANTENNADIFFAREA 12.092400 ;
    PORT
      LAYER Metal3 ;
        RECT 0.000 85.060 0.400 85.460 ;
    END
  END AXI_M_SOC_RRESP1
  PIN AXI_M_SOC_RVALID
    DIRECTION INPUT ;
    USE SIGNAL ;
    ANTENNAGATEAREA 1.279200 ;
    ANTENNADIFFAREA 12.092400 ;
    PORT
      LAYER Metal3 ;
        RECT 0.000 86.740 0.400 87.140 ;
    END
  END AXI_M_SOC_RVALID
  PIN AXI_M_SOC_WDATA0
    DIRECTION OUTPUT ;
    USE SIGNAL ;
    ANTENNADIFFAREA 2.647800 ;
    PORT
      LAYER Metal3 ;
        RECT 0.000 126.220 0.400 126.620 ;
    END
  END AXI_M_SOC_WDATA0
  PIN AXI_M_SOC_WDATA1
    DIRECTION OUTPUT ;
    USE SIGNAL ;
    ANTENNADIFFAREA 2.647800 ;
    PORT
      LAYER Metal3 ;
        RECT 0.000 127.060 0.400 127.460 ;
    END
  END AXI_M_SOC_WDATA1
  PIN AXI_M_SOC_WDATA10
    DIRECTION OUTPUT ;
    USE SIGNAL ;
    ANTENNADIFFAREA 2.647800 ;
    PORT
      LAYER Metal3 ;
        RECT 0.000 134.620 0.400 135.020 ;
    END
  END AXI_M_SOC_WDATA10
  PIN AXI_M_SOC_WDATA11
    DIRECTION OUTPUT ;
    USE SIGNAL ;
    ANTENNADIFFAREA 2.647800 ;
    PORT
      LAYER Metal3 ;
        RECT 0.000 135.460 0.400 135.860 ;
    END
  END AXI_M_SOC_WDATA11
  PIN AXI_M_SOC_WDATA12
    DIRECTION OUTPUT ;
    USE SIGNAL ;
    ANTENNADIFFAREA 2.647800 ;
    PORT
      LAYER Metal3 ;
        RECT 0.000 136.300 0.400 136.700 ;
    END
  END AXI_M_SOC_WDATA12
  PIN AXI_M_SOC_WDATA13
    DIRECTION OUTPUT ;
    USE SIGNAL ;
    ANTENNADIFFAREA 2.647800 ;
    PORT
      LAYER Metal3 ;
        RECT 0.000 137.140 0.400 137.540 ;
    END
  END AXI_M_SOC_WDATA13
  PIN AXI_M_SOC_WDATA14
    DIRECTION OUTPUT ;
    USE SIGNAL ;
    ANTENNADIFFAREA 2.647800 ;
    PORT
      LAYER Metal3 ;
        RECT 0.000 137.980 0.400 138.380 ;
    END
  END AXI_M_SOC_WDATA14
  PIN AXI_M_SOC_WDATA15
    DIRECTION OUTPUT ;
    USE SIGNAL ;
    ANTENNADIFFAREA 2.647800 ;
    PORT
      LAYER Metal3 ;
        RECT 0.000 138.820 0.400 139.220 ;
    END
  END AXI_M_SOC_WDATA15
  PIN AXI_M_SOC_WDATA16
    DIRECTION OUTPUT ;
    USE SIGNAL ;
    ANTENNADIFFAREA 2.647800 ;
    PORT
      LAYER Metal3 ;
        RECT 0.000 139.660 0.400 140.060 ;
    END
  END AXI_M_SOC_WDATA16
  PIN AXI_M_SOC_WDATA17
    DIRECTION OUTPUT ;
    USE SIGNAL ;
    ANTENNADIFFAREA 2.647800 ;
    PORT
      LAYER Metal3 ;
        RECT 0.000 140.500 0.400 140.900 ;
    END
  END AXI_M_SOC_WDATA17
  PIN AXI_M_SOC_WDATA18
    DIRECTION OUTPUT ;
    USE SIGNAL ;
    ANTENNADIFFAREA 2.647800 ;
    PORT
      LAYER Metal3 ;
        RECT 0.000 141.340 0.400 141.740 ;
    END
  END AXI_M_SOC_WDATA18
  PIN AXI_M_SOC_WDATA19
    DIRECTION OUTPUT ;
    USE SIGNAL ;
    ANTENNADIFFAREA 2.647800 ;
    PORT
      LAYER Metal3 ;
        RECT 0.000 142.180 0.400 142.580 ;
    END
  END AXI_M_SOC_WDATA19
  PIN AXI_M_SOC_WDATA2
    DIRECTION OUTPUT ;
    USE SIGNAL ;
    ANTENNADIFFAREA 2.647800 ;
    PORT
      LAYER Metal3 ;
        RECT 0.000 127.900 0.400 128.300 ;
    END
  END AXI_M_SOC_WDATA2
  PIN AXI_M_SOC_WDATA20
    DIRECTION OUTPUT ;
    USE SIGNAL ;
    ANTENNADIFFAREA 2.647800 ;
    PORT
      LAYER Metal3 ;
        RECT 0.000 143.020 0.400 143.420 ;
    END
  END AXI_M_SOC_WDATA20
  PIN AXI_M_SOC_WDATA21
    DIRECTION OUTPUT ;
    USE SIGNAL ;
    ANTENNADIFFAREA 2.647800 ;
    PORT
      LAYER Metal3 ;
        RECT 0.000 143.860 0.400 144.260 ;
    END
  END AXI_M_SOC_WDATA21
  PIN AXI_M_SOC_WDATA22
    DIRECTION OUTPUT ;
    USE SIGNAL ;
    ANTENNADIFFAREA 2.647800 ;
    PORT
      LAYER Metal3 ;
        RECT 0.000 144.700 0.400 145.100 ;
    END
  END AXI_M_SOC_WDATA22
  PIN AXI_M_SOC_WDATA23
    DIRECTION OUTPUT ;
    USE SIGNAL ;
    ANTENNADIFFAREA 2.647800 ;
    PORT
      LAYER Metal3 ;
        RECT 0.000 145.540 0.400 145.940 ;
    END
  END AXI_M_SOC_WDATA23
  PIN AXI_M_SOC_WDATA24
    DIRECTION OUTPUT ;
    USE SIGNAL ;
    ANTENNADIFFAREA 2.647800 ;
    PORT
      LAYER Metal3 ;
        RECT 0.000 146.380 0.400 146.780 ;
    END
  END AXI_M_SOC_WDATA24
  PIN AXI_M_SOC_WDATA25
    DIRECTION OUTPUT ;
    USE SIGNAL ;
    ANTENNADIFFAREA 2.647800 ;
    PORT
      LAYER Metal3 ;
        RECT 0.000 147.220 0.400 147.620 ;
    END
  END AXI_M_SOC_WDATA25
  PIN AXI_M_SOC_WDATA26
    DIRECTION OUTPUT ;
    USE SIGNAL ;
    ANTENNADIFFAREA 2.647800 ;
    PORT
      LAYER Metal3 ;
        RECT 0.000 148.060 0.400 148.460 ;
    END
  END AXI_M_SOC_WDATA26
  PIN AXI_M_SOC_WDATA27
    DIRECTION OUTPUT ;
    USE SIGNAL ;
    ANTENNADIFFAREA 2.647800 ;
    PORT
      LAYER Metal3 ;
        RECT 0.000 148.900 0.400 149.300 ;
    END
  END AXI_M_SOC_WDATA27
  PIN AXI_M_SOC_WDATA28
    DIRECTION OUTPUT ;
    USE SIGNAL ;
    ANTENNADIFFAREA 2.647800 ;
    PORT
      LAYER Metal3 ;
        RECT 0.000 149.740 0.400 150.140 ;
    END
  END AXI_M_SOC_WDATA28
  PIN AXI_M_SOC_WDATA29
    DIRECTION OUTPUT ;
    USE SIGNAL ;
    ANTENNADIFFAREA 2.647800 ;
    PORT
      LAYER Metal3 ;
        RECT 0.000 150.580 0.400 150.980 ;
    END
  END AXI_M_SOC_WDATA29
  PIN AXI_M_SOC_WDATA3
    DIRECTION OUTPUT ;
    USE SIGNAL ;
    ANTENNADIFFAREA 2.647800 ;
    PORT
      LAYER Metal3 ;
        RECT 0.000 128.740 0.400 129.140 ;
    END
  END AXI_M_SOC_WDATA3
  PIN AXI_M_SOC_WDATA30
    DIRECTION OUTPUT ;
    USE SIGNAL ;
    ANTENNADIFFAREA 2.647800 ;
    PORT
      LAYER Metal3 ;
        RECT 0.000 151.420 0.400 151.820 ;
    END
  END AXI_M_SOC_WDATA30
  PIN AXI_M_SOC_WDATA31
    DIRECTION OUTPUT ;
    USE SIGNAL ;
    ANTENNADIFFAREA 2.647800 ;
    PORT
      LAYER Metal3 ;
        RECT 0.000 152.260 0.400 152.660 ;
    END
  END AXI_M_SOC_WDATA31
  PIN AXI_M_SOC_WDATA4
    DIRECTION OUTPUT ;
    USE SIGNAL ;
    ANTENNADIFFAREA 2.647800 ;
    PORT
      LAYER Metal3 ;
        RECT 0.000 129.580 0.400 129.980 ;
    END
  END AXI_M_SOC_WDATA4
  PIN AXI_M_SOC_WDATA5
    DIRECTION OUTPUT ;
    USE SIGNAL ;
    ANTENNADIFFAREA 2.647800 ;
    PORT
      LAYER Metal3 ;
        RECT 0.000 130.420 0.400 130.820 ;
    END
  END AXI_M_SOC_WDATA5
  PIN AXI_M_SOC_WDATA6
    DIRECTION OUTPUT ;
    USE SIGNAL ;
    ANTENNADIFFAREA 2.647800 ;
    PORT
      LAYER Metal3 ;
        RECT 0.000 131.260 0.400 131.660 ;
    END
  END AXI_M_SOC_WDATA6
  PIN AXI_M_SOC_WDATA7
    DIRECTION OUTPUT ;
    USE SIGNAL ;
    ANTENNADIFFAREA 2.647800 ;
    PORT
      LAYER Metal3 ;
        RECT 0.000 132.100 0.400 132.500 ;
    END
  END AXI_M_SOC_WDATA7
  PIN AXI_M_SOC_WDATA8
    DIRECTION OUTPUT ;
    USE SIGNAL ;
    ANTENNADIFFAREA 2.647800 ;
    PORT
      LAYER Metal3 ;
        RECT 0.000 132.940 0.400 133.340 ;
    END
  END AXI_M_SOC_WDATA8
  PIN AXI_M_SOC_WDATA9
    DIRECTION OUTPUT ;
    USE SIGNAL ;
    ANTENNADIFFAREA 2.647800 ;
    PORT
      LAYER Metal3 ;
        RECT 0.000 133.780 0.400 134.180 ;
    END
  END AXI_M_SOC_WDATA9
  PIN AXI_M_SOC_WLAST
    DIRECTION OUTPUT ;
    USE SIGNAL ;
    ANTENNADIFFAREA 2.664600 ;
    PORT
      LAYER Metal3 ;
        RECT 0.000 156.460 0.400 156.860 ;
    END
  END AXI_M_SOC_WLAST
  PIN AXI_M_SOC_WREADY
    DIRECTION INPUT ;
    USE SIGNAL ;
    ANTENNAGATEAREA 1.279200 ;
    ANTENNADIFFAREA 12.092400 ;
    PORT
      LAYER Metal3 ;
        RECT 0.000 53.140 0.400 53.540 ;
    END
  END AXI_M_SOC_WREADY
  PIN AXI_M_SOC_WSTRB0
    DIRECTION OUTPUT ;
    USE SIGNAL ;
    ANTENNADIFFAREA 2.664600 ;
    PORT
      LAYER Metal3 ;
        RECT 0.000 153.100 0.400 153.500 ;
    END
  END AXI_M_SOC_WSTRB0
  PIN AXI_M_SOC_WSTRB1
    DIRECTION OUTPUT ;
    USE SIGNAL ;
    ANTENNADIFFAREA 2.664600 ;
    PORT
      LAYER Metal3 ;
        RECT 0.000 153.940 0.400 154.340 ;
    END
  END AXI_M_SOC_WSTRB1
  PIN AXI_M_SOC_WSTRB2
    DIRECTION OUTPUT ;
    USE SIGNAL ;
    ANTENNADIFFAREA 2.664600 ;
    PORT
      LAYER Metal3 ;
        RECT 0.000 154.780 0.400 155.180 ;
    END
  END AXI_M_SOC_WSTRB2
  PIN AXI_M_SOC_WSTRB3
    DIRECTION OUTPUT ;
    USE SIGNAL ;
    ANTENNADIFFAREA 2.664600 ;
    PORT
      LAYER Metal3 ;
        RECT 0.000 155.620 0.400 156.020 ;
    END
  END AXI_M_SOC_WSTRB3
  PIN AXI_M_SOC_WVALID
    DIRECTION OUTPUT ;
    USE SIGNAL ;
    ANTENNADIFFAREA 2.647800 ;
    PORT
      LAYER Metal3 ;
        RECT 0.000 157.300 0.400 157.700 ;
    END
  END AXI_M_SOC_WVALID
  PIN Tile_X0Y0_E1BEG[0]
    DIRECTION OUTPUT ;
    USE SIGNAL ;
    ANTENNADIFFAREA 2.724000 ;
    PORT
      LAYER Metal3 ;
        RECT 146.960 1078.360 147.360 1078.760 ;
    END
  END Tile_X0Y0_E1BEG[0]
  PIN Tile_X0Y0_E1BEG[1]
    DIRECTION OUTPUT ;
    USE SIGNAL ;
    ANTENNADIFFAREA 2.724000 ;
    PORT
      LAYER Metal3 ;
        RECT 146.960 1080.040 147.360 1080.440 ;
    END
  END Tile_X0Y0_E1BEG[1]
  PIN Tile_X0Y0_E1BEG[2]
    DIRECTION OUTPUT ;
    USE SIGNAL ;
    ANTENNADIFFAREA 2.724000 ;
    PORT
      LAYER Metal3 ;
        RECT 146.960 1081.720 147.360 1082.120 ;
    END
  END Tile_X0Y0_E1BEG[2]
  PIN Tile_X0Y0_E1BEG[3]
    DIRECTION OUTPUT ;
    USE SIGNAL ;
    ANTENNADIFFAREA 2.724000 ;
    PORT
      LAYER Metal3 ;
        RECT 146.960 1083.400 147.360 1083.800 ;
    END
  END Tile_X0Y0_E1BEG[3]
  PIN Tile_X0Y0_E2BEG[0]
    DIRECTION OUTPUT ;
    USE SIGNAL ;
    ANTENNADIFFAREA 2.724000 ;
    PORT
      LAYER Metal3 ;
        RECT 146.960 1087.600 147.360 1088.000 ;
    END
  END Tile_X0Y0_E2BEG[0]
  PIN Tile_X0Y0_E2BEG[1]
    DIRECTION OUTPUT ;
    USE SIGNAL ;
    ANTENNADIFFAREA 2.724000 ;
    PORT
      LAYER Metal3 ;
        RECT 146.960 1088.440 147.360 1088.840 ;
    END
  END Tile_X0Y0_E2BEG[1]
  PIN Tile_X0Y0_E2BEG[2]
    DIRECTION OUTPUT ;
    USE SIGNAL ;
    ANTENNADIFFAREA 2.724000 ;
    PORT
      LAYER Metal3 ;
        RECT 146.960 1089.280 147.360 1089.680 ;
    END
  END Tile_X0Y0_E2BEG[2]
  PIN Tile_X0Y0_E2BEG[3]
    DIRECTION OUTPUT ;
    USE SIGNAL ;
    ANTENNADIFFAREA 2.724000 ;
    PORT
      LAYER Metal3 ;
        RECT 146.960 1090.120 147.360 1090.520 ;
    END
  END Tile_X0Y0_E2BEG[3]
  PIN Tile_X0Y0_E2BEG[4]
    DIRECTION OUTPUT ;
    USE SIGNAL ;
    ANTENNADIFFAREA 2.724000 ;
    PORT
      LAYER Metal3 ;
        RECT 146.960 1090.960 147.360 1091.360 ;
    END
  END Tile_X0Y0_E2BEG[4]
  PIN Tile_X0Y0_E2BEG[5]
    DIRECTION OUTPUT ;
    USE SIGNAL ;
    ANTENNADIFFAREA 2.724000 ;
    PORT
      LAYER Metal3 ;
        RECT 146.960 1091.800 147.360 1092.200 ;
    END
  END Tile_X0Y0_E2BEG[5]
  PIN Tile_X0Y0_E2BEG[6]
    DIRECTION OUTPUT ;
    USE SIGNAL ;
    ANTENNADIFFAREA 2.724000 ;
    PORT
      LAYER Metal3 ;
        RECT 146.960 1092.640 147.360 1093.040 ;
    END
  END Tile_X0Y0_E2BEG[6]
  PIN Tile_X0Y0_E2BEG[7]
    DIRECTION OUTPUT ;
    USE SIGNAL ;
    ANTENNADIFFAREA 2.724000 ;
    PORT
      LAYER Metal3 ;
        RECT 146.960 1093.480 147.360 1093.880 ;
    END
  END Tile_X0Y0_E2BEG[7]
  PIN Tile_X0Y0_E2BEGb[0]
    DIRECTION OUTPUT ;
    USE SIGNAL ;
    ANTENNADIFFAREA 2.724000 ;
    PORT
      LAYER Metal3 ;
        RECT 146.960 1097.680 147.360 1098.080 ;
    END
  END Tile_X0Y0_E2BEGb[0]
  PIN Tile_X0Y0_E2BEGb[1]
    DIRECTION OUTPUT ;
    USE SIGNAL ;
    ANTENNADIFFAREA 2.724000 ;
    PORT
      LAYER Metal3 ;
        RECT 146.960 1099.360 147.360 1099.760 ;
    END
  END Tile_X0Y0_E2BEGb[1]
  PIN Tile_X0Y0_E2BEGb[2]
    DIRECTION OUTPUT ;
    USE SIGNAL ;
    ANTENNADIFFAREA 2.724000 ;
    PORT
      LAYER Metal3 ;
        RECT 146.960 1101.040 147.360 1101.440 ;
    END
  END Tile_X0Y0_E2BEGb[2]
  PIN Tile_X0Y0_E2BEGb[3]
    DIRECTION OUTPUT ;
    USE SIGNAL ;
    ANTENNADIFFAREA 2.724000 ;
    PORT
      LAYER Metal3 ;
        RECT 146.960 1102.720 147.360 1103.120 ;
    END
  END Tile_X0Y0_E2BEGb[3]
  PIN Tile_X0Y0_E2BEGb[4]
    DIRECTION OUTPUT ;
    USE SIGNAL ;
    ANTENNADIFFAREA 2.724000 ;
    PORT
      LAYER Metal3 ;
        RECT 146.960 1104.400 147.360 1104.800 ;
    END
  END Tile_X0Y0_E2BEGb[4]
  PIN Tile_X0Y0_E2BEGb[5]
    DIRECTION OUTPUT ;
    USE SIGNAL ;
    ANTENNADIFFAREA 2.724000 ;
    PORT
      LAYER Metal3 ;
        RECT 146.960 1106.080 147.360 1106.480 ;
    END
  END Tile_X0Y0_E2BEGb[5]
  PIN Tile_X0Y0_E2BEGb[6]
    DIRECTION OUTPUT ;
    USE SIGNAL ;
    ANTENNADIFFAREA 2.724000 ;
    PORT
      LAYER Metal3 ;
        RECT 146.960 1107.760 147.360 1108.160 ;
    END
  END Tile_X0Y0_E2BEGb[6]
  PIN Tile_X0Y0_E2BEGb[7]
    DIRECTION OUTPUT ;
    USE SIGNAL ;
    ANTENNADIFFAREA 2.724000 ;
    PORT
      LAYER Metal3 ;
        RECT 146.960 1109.440 147.360 1109.840 ;
    END
  END Tile_X0Y0_E2BEGb[7]
  PIN Tile_X0Y0_E6BEG[0]
    DIRECTION OUTPUT ;
    USE SIGNAL ;
    ANTENNADIFFAREA 2.724000 ;
    PORT
      LAYER Metal3 ;
        RECT 146.960 1137.160 147.360 1137.560 ;
    END
  END Tile_X0Y0_E6BEG[0]
  PIN Tile_X0Y0_E6BEG[10]
    DIRECTION OUTPUT ;
    USE SIGNAL ;
    ANTENNADIFFAREA 2.724000 ;
    PORT
      LAYER Metal3 ;
        RECT 146.960 1153.960 147.360 1154.360 ;
    END
  END Tile_X0Y0_E6BEG[10]
  PIN Tile_X0Y0_E6BEG[11]
    DIRECTION OUTPUT ;
    USE SIGNAL ;
    ANTENNADIFFAREA 2.724000 ;
    PORT
      LAYER Metal3 ;
        RECT 146.960 1155.640 147.360 1156.040 ;
    END
  END Tile_X0Y0_E6BEG[11]
  PIN Tile_X0Y0_E6BEG[1]
    DIRECTION OUTPUT ;
    USE SIGNAL ;
    ANTENNADIFFAREA 2.724000 ;
    PORT
      LAYER Metal3 ;
        RECT 146.960 1138.840 147.360 1139.240 ;
    END
  END Tile_X0Y0_E6BEG[1]
  PIN Tile_X0Y0_E6BEG[2]
    DIRECTION OUTPUT ;
    USE SIGNAL ;
    ANTENNADIFFAREA 2.724000 ;
    PORT
      LAYER Metal3 ;
        RECT 146.960 1140.520 147.360 1140.920 ;
    END
  END Tile_X0Y0_E6BEG[2]
  PIN Tile_X0Y0_E6BEG[3]
    DIRECTION OUTPUT ;
    USE SIGNAL ;
    ANTENNADIFFAREA 2.724000 ;
    PORT
      LAYER Metal3 ;
        RECT 146.960 1142.200 147.360 1142.600 ;
    END
  END Tile_X0Y0_E6BEG[3]
  PIN Tile_X0Y0_E6BEG[4]
    DIRECTION OUTPUT ;
    USE SIGNAL ;
    ANTENNADIFFAREA 2.724000 ;
    PORT
      LAYER Metal3 ;
        RECT 146.960 1143.880 147.360 1144.280 ;
    END
  END Tile_X0Y0_E6BEG[4]
  PIN Tile_X0Y0_E6BEG[5]
    DIRECTION OUTPUT ;
    USE SIGNAL ;
    ANTENNADIFFAREA 2.724000 ;
    PORT
      LAYER Metal3 ;
        RECT 146.960 1145.560 147.360 1145.960 ;
    END
  END Tile_X0Y0_E6BEG[5]
  PIN Tile_X0Y0_E6BEG[6]
    DIRECTION OUTPUT ;
    USE SIGNAL ;
    ANTENNADIFFAREA 2.724000 ;
    PORT
      LAYER Metal3 ;
        RECT 146.960 1147.240 147.360 1147.640 ;
    END
  END Tile_X0Y0_E6BEG[6]
  PIN Tile_X0Y0_E6BEG[7]
    DIRECTION OUTPUT ;
    USE SIGNAL ;
    ANTENNADIFFAREA 2.724000 ;
    PORT
      LAYER Metal3 ;
        RECT 146.960 1148.920 147.360 1149.320 ;
    END
  END Tile_X0Y0_E6BEG[7]
  PIN Tile_X0Y0_E6BEG[8]
    DIRECTION OUTPUT ;
    USE SIGNAL ;
    ANTENNADIFFAREA 2.724000 ;
    PORT
      LAYER Metal3 ;
        RECT 146.960 1150.600 147.360 1151.000 ;
    END
  END Tile_X0Y0_E6BEG[8]
  PIN Tile_X0Y0_E6BEG[9]
    DIRECTION OUTPUT ;
    USE SIGNAL ;
    ANTENNADIFFAREA 2.724000 ;
    PORT
      LAYER Metal3 ;
        RECT 146.960 1152.280 147.360 1152.680 ;
    END
  END Tile_X0Y0_E6BEG[9]
  PIN Tile_X0Y0_EE4BEG[0]
    DIRECTION OUTPUT ;
    USE SIGNAL ;
    ANTENNADIFFAREA 2.724000 ;
    PORT
      LAYER Metal3 ;
        RECT 146.960 1117.000 147.360 1117.400 ;
    END
  END Tile_X0Y0_EE4BEG[0]
  PIN Tile_X0Y0_EE4BEG[10]
    DIRECTION OUTPUT ;
    USE SIGNAL ;
    ANTENNADIFFAREA 2.724000 ;
    PORT
      LAYER Metal3 ;
        RECT 146.960 1125.400 147.360 1125.800 ;
    END
  END Tile_X0Y0_EE4BEG[10]
  PIN Tile_X0Y0_EE4BEG[11]
    DIRECTION OUTPUT ;
    USE SIGNAL ;
    ANTENNADIFFAREA 2.724000 ;
    PORT
      LAYER Metal3 ;
        RECT 146.960 1126.240 147.360 1126.640 ;
    END
  END Tile_X0Y0_EE4BEG[11]
  PIN Tile_X0Y0_EE4BEG[12]
    DIRECTION OUTPUT ;
    USE SIGNAL ;
    ANTENNADIFFAREA 2.724000 ;
    PORT
      LAYER Metal3 ;
        RECT 146.960 1127.080 147.360 1127.480 ;
    END
  END Tile_X0Y0_EE4BEG[12]
  PIN Tile_X0Y0_EE4BEG[13]
    DIRECTION OUTPUT ;
    USE SIGNAL ;
    ANTENNADIFFAREA 2.724000 ;
    PORT
      LAYER Metal3 ;
        RECT 146.960 1127.920 147.360 1128.320 ;
    END
  END Tile_X0Y0_EE4BEG[13]
  PIN Tile_X0Y0_EE4BEG[14]
    DIRECTION OUTPUT ;
    USE SIGNAL ;
    ANTENNADIFFAREA 2.724000 ;
    PORT
      LAYER Metal3 ;
        RECT 146.960 1128.760 147.360 1129.160 ;
    END
  END Tile_X0Y0_EE4BEG[14]
  PIN Tile_X0Y0_EE4BEG[15]
    DIRECTION OUTPUT ;
    USE SIGNAL ;
    ANTENNADIFFAREA 2.724000 ;
    PORT
      LAYER Metal3 ;
        RECT 146.960 1129.600 147.360 1130.000 ;
    END
  END Tile_X0Y0_EE4BEG[15]
  PIN Tile_X0Y0_EE4BEG[1]
    DIRECTION OUTPUT ;
    USE SIGNAL ;
    ANTENNADIFFAREA 2.724000 ;
    PORT
      LAYER Metal3 ;
        RECT 146.960 1117.840 147.360 1118.240 ;
    END
  END Tile_X0Y0_EE4BEG[1]
  PIN Tile_X0Y0_EE4BEG[2]
    DIRECTION OUTPUT ;
    USE SIGNAL ;
    ANTENNADIFFAREA 2.724000 ;
    PORT
      LAYER Metal3 ;
        RECT 146.960 1118.680 147.360 1119.080 ;
    END
  END Tile_X0Y0_EE4BEG[2]
  PIN Tile_X0Y0_EE4BEG[3]
    DIRECTION OUTPUT ;
    USE SIGNAL ;
    ANTENNADIFFAREA 2.724000 ;
    PORT
      LAYER Metal3 ;
        RECT 146.960 1119.520 147.360 1119.920 ;
    END
  END Tile_X0Y0_EE4BEG[3]
  PIN Tile_X0Y0_EE4BEG[4]
    DIRECTION OUTPUT ;
    USE SIGNAL ;
    ANTENNADIFFAREA 2.724000 ;
    PORT
      LAYER Metal3 ;
        RECT 146.960 1120.360 147.360 1120.760 ;
    END
  END Tile_X0Y0_EE4BEG[4]
  PIN Tile_X0Y0_EE4BEG[5]
    DIRECTION OUTPUT ;
    USE SIGNAL ;
    ANTENNADIFFAREA 2.724000 ;
    PORT
      LAYER Metal3 ;
        RECT 146.960 1121.200 147.360 1121.600 ;
    END
  END Tile_X0Y0_EE4BEG[5]
  PIN Tile_X0Y0_EE4BEG[6]
    DIRECTION OUTPUT ;
    USE SIGNAL ;
    ANTENNADIFFAREA 2.724000 ;
    PORT
      LAYER Metal3 ;
        RECT 146.960 1122.040 147.360 1122.440 ;
    END
  END Tile_X0Y0_EE4BEG[6]
  PIN Tile_X0Y0_EE4BEG[7]
    DIRECTION OUTPUT ;
    USE SIGNAL ;
    ANTENNADIFFAREA 2.724000 ;
    PORT
      LAYER Metal3 ;
        RECT 146.960 1122.880 147.360 1123.280 ;
    END
  END Tile_X0Y0_EE4BEG[7]
  PIN Tile_X0Y0_EE4BEG[8]
    DIRECTION OUTPUT ;
    USE SIGNAL ;
    ANTENNADIFFAREA 2.724000 ;
    PORT
      LAYER Metal3 ;
        RECT 146.960 1123.720 147.360 1124.120 ;
    END
  END Tile_X0Y0_EE4BEG[8]
  PIN Tile_X0Y0_EE4BEG[9]
    DIRECTION OUTPUT ;
    USE SIGNAL ;
    ANTENNADIFFAREA 2.724000 ;
    PORT
      LAYER Metal3 ;
        RECT 146.960 1124.560 147.360 1124.960 ;
    END
  END Tile_X0Y0_EE4BEG[9]
  PIN Tile_X0Y0_FrameData[0]
    DIRECTION INPUT ;
    USE SIGNAL ;
    ANTENNAGATEAREA 1.626300 ;
    ANTENNADIFFAREA 18.138599 ;
    PORT
      LAYER Metal3 ;
        RECT 0.000 1097.680 0.400 1098.080 ;
    END
  END Tile_X0Y0_FrameData[0]
  PIN Tile_X0Y0_FrameData[10]
    DIRECTION INPUT ;
    USE SIGNAL ;
    ANTENNAGATEAREA 1.626300 ;
    ANTENNADIFFAREA 18.138599 ;
    PORT
      LAYER Metal3 ;
        RECT 0.000 1156.480 0.400 1156.880 ;
    END
  END Tile_X0Y0_FrameData[10]
  PIN Tile_X0Y0_FrameData[11]
    DIRECTION INPUT ;
    USE SIGNAL ;
    ANTENNAGATEAREA 1.626300 ;
    ANTENNADIFFAREA 18.138599 ;
    PORT
      LAYER Metal3 ;
        RECT 0.000 1162.360 0.400 1162.760 ;
    END
  END Tile_X0Y0_FrameData[11]
  PIN Tile_X0Y0_FrameData[12]
    DIRECTION INPUT ;
    USE SIGNAL ;
    ANTENNAGATEAREA 1.626300 ;
    ANTENNADIFFAREA 18.138599 ;
    PORT
      LAYER Metal3 ;
        RECT 0.000 1168.240 0.400 1168.640 ;
    END
  END Tile_X0Y0_FrameData[12]
  PIN Tile_X0Y0_FrameData[13]
    DIRECTION INPUT ;
    USE SIGNAL ;
    ANTENNAGATEAREA 1.626300 ;
    ANTENNADIFFAREA 18.138599 ;
    PORT
      LAYER Metal3 ;
        RECT 0.000 1174.120 0.400 1174.520 ;
    END
  END Tile_X0Y0_FrameData[13]
  PIN Tile_X0Y0_FrameData[14]
    DIRECTION INPUT ;
    USE SIGNAL ;
    ANTENNAGATEAREA 1.626300 ;
    ANTENNADIFFAREA 18.138599 ;
    PORT
      LAYER Metal3 ;
        RECT 0.000 1180.000 0.400 1180.400 ;
    END
  END Tile_X0Y0_FrameData[14]
  PIN Tile_X0Y0_FrameData[15]
    DIRECTION INPUT ;
    USE SIGNAL ;
    ANTENNAGATEAREA 1.626300 ;
    ANTENNADIFFAREA 18.138599 ;
    PORT
      LAYER Metal3 ;
        RECT 0.000 1185.880 0.400 1186.280 ;
    END
  END Tile_X0Y0_FrameData[15]
  PIN Tile_X0Y0_FrameData[16]
    DIRECTION INPUT ;
    USE SIGNAL ;
    ANTENNAGATEAREA 1.807000 ;
    ANTENNADIFFAREA 20.153999 ;
    PORT
      LAYER Metal3 ;
        RECT 0.000 1191.760 0.400 1192.160 ;
    END
  END Tile_X0Y0_FrameData[16]
  PIN Tile_X0Y0_FrameData[17]
    DIRECTION INPUT ;
    USE SIGNAL ;
    ANTENNAGATEAREA 1.807000 ;
    ANTENNADIFFAREA 20.153999 ;
    PORT
      LAYER Metal3 ;
        RECT 0.000 1197.640 0.400 1198.040 ;
    END
  END Tile_X0Y0_FrameData[17]
  PIN Tile_X0Y0_FrameData[18]
    DIRECTION INPUT ;
    USE SIGNAL ;
    ANTENNAGATEAREA 1.807000 ;
    ANTENNADIFFAREA 20.153999 ;
    PORT
      LAYER Metal3 ;
        RECT 0.000 1203.520 0.400 1203.920 ;
    END
  END Tile_X0Y0_FrameData[18]
  PIN Tile_X0Y0_FrameData[19]
    DIRECTION INPUT ;
    USE SIGNAL ;
    ANTENNAGATEAREA 1.807000 ;
    ANTENNADIFFAREA 20.153999 ;
    PORT
      LAYER Metal3 ;
        RECT 0.000 1209.400 0.400 1209.800 ;
    END
  END Tile_X0Y0_FrameData[19]
  PIN Tile_X0Y0_FrameData[1]
    DIRECTION INPUT ;
    USE SIGNAL ;
    ANTENNAGATEAREA 1.626300 ;
    ANTENNADIFFAREA 18.138599 ;
    PORT
      LAYER Metal3 ;
        RECT 0.000 1103.560 0.400 1103.960 ;
    END
  END Tile_X0Y0_FrameData[1]
  PIN Tile_X0Y0_FrameData[20]
    DIRECTION INPUT ;
    USE SIGNAL ;
    ANTENNAGATEAREA 1.807000 ;
    ANTENNADIFFAREA 20.153999 ;
    PORT
      LAYER Metal3 ;
        RECT 0.000 1215.280 0.400 1215.680 ;
    END
  END Tile_X0Y0_FrameData[20]
  PIN Tile_X0Y0_FrameData[21]
    DIRECTION INPUT ;
    USE SIGNAL ;
    ANTENNAGATEAREA 1.807000 ;
    ANTENNADIFFAREA 20.153999 ;
    PORT
      LAYER Metal3 ;
        RECT 0.000 1221.160 0.400 1221.560 ;
    END
  END Tile_X0Y0_FrameData[21]
  PIN Tile_X0Y0_FrameData[22]
    DIRECTION INPUT ;
    USE SIGNAL ;
    ANTENNAGATEAREA 1.807000 ;
    ANTENNADIFFAREA 20.153999 ;
    PORT
      LAYER Metal3 ;
        RECT 0.000 1227.040 0.400 1227.440 ;
    END
  END Tile_X0Y0_FrameData[22]
  PIN Tile_X0Y0_FrameData[23]
    DIRECTION INPUT ;
    USE SIGNAL ;
    ANTENNAGATEAREA 1.807000 ;
    ANTENNADIFFAREA 20.153999 ;
    PORT
      LAYER Metal3 ;
        RECT 0.000 1232.920 0.400 1233.320 ;
    END
  END Tile_X0Y0_FrameData[23]
  PIN Tile_X0Y0_FrameData[24]
    DIRECTION INPUT ;
    USE SIGNAL ;
    ANTENNAGATEAREA 1.807000 ;
    ANTENNADIFFAREA 20.153999 ;
    PORT
      LAYER Metal3 ;
        RECT 0.000 1238.800 0.400 1239.200 ;
    END
  END Tile_X0Y0_FrameData[24]
  PIN Tile_X0Y0_FrameData[25]
    DIRECTION INPUT ;
    USE SIGNAL ;
    ANTENNAGATEAREA 1.807000 ;
    ANTENNADIFFAREA 20.153999 ;
    PORT
      LAYER Metal3 ;
        RECT 0.000 1244.680 0.400 1245.080 ;
    END
  END Tile_X0Y0_FrameData[25]
  PIN Tile_X0Y0_FrameData[26]
    DIRECTION INPUT ;
    USE SIGNAL ;
    ANTENNAGATEAREA 1.807000 ;
    ANTENNADIFFAREA 20.153999 ;
    PORT
      LAYER Metal3 ;
        RECT 0.000 1250.560 0.400 1250.960 ;
    END
  END Tile_X0Y0_FrameData[26]
  PIN Tile_X0Y0_FrameData[27]
    DIRECTION INPUT ;
    USE SIGNAL ;
    ANTENNAGATEAREA 1.807000 ;
    ANTENNADIFFAREA 20.153999 ;
    PORT
      LAYER Metal3 ;
        RECT 0.000 1256.440 0.400 1256.840 ;
    END
  END Tile_X0Y0_FrameData[27]
  PIN Tile_X0Y0_FrameData[28]
    DIRECTION INPUT ;
    USE SIGNAL ;
    ANTENNAGATEAREA 1.807000 ;
    ANTENNADIFFAREA 20.153999 ;
    PORT
      LAYER Metal3 ;
        RECT 0.000 1262.320 0.400 1262.720 ;
    END
  END Tile_X0Y0_FrameData[28]
  PIN Tile_X0Y0_FrameData[29]
    DIRECTION INPUT ;
    USE SIGNAL ;
    ANTENNAGATEAREA 1.807000 ;
    ANTENNADIFFAREA 20.153999 ;
    PORT
      LAYER Metal3 ;
        RECT 0.000 1268.200 0.400 1268.600 ;
    END
  END Tile_X0Y0_FrameData[29]
  PIN Tile_X0Y0_FrameData[2]
    DIRECTION INPUT ;
    USE SIGNAL ;
    ANTENNAGATEAREA 1.626300 ;
    ANTENNADIFFAREA 18.138599 ;
    PORT
      LAYER Metal3 ;
        RECT 0.000 1109.440 0.400 1109.840 ;
    END
  END Tile_X0Y0_FrameData[2]
  PIN Tile_X0Y0_FrameData[30]
    DIRECTION INPUT ;
    USE SIGNAL ;
    ANTENNAGATEAREA 1.807000 ;
    ANTENNADIFFAREA 20.153999 ;
    PORT
      LAYER Metal3 ;
        RECT 0.000 1274.080 0.400 1274.480 ;
    END
  END Tile_X0Y0_FrameData[30]
  PIN Tile_X0Y0_FrameData[31]
    DIRECTION INPUT ;
    USE SIGNAL ;
    ANTENNAGATEAREA 1.807000 ;
    ANTENNADIFFAREA 20.153999 ;
    PORT
      LAYER Metal3 ;
        RECT 0.000 1279.960 0.400 1280.360 ;
    END
  END Tile_X0Y0_FrameData[31]
  PIN Tile_X0Y0_FrameData[3]
    DIRECTION INPUT ;
    USE SIGNAL ;
    ANTENNAGATEAREA 1.626300 ;
    ANTENNADIFFAREA 18.138599 ;
    PORT
      LAYER Metal3 ;
        RECT 0.000 1115.320 0.400 1115.720 ;
    END
  END Tile_X0Y0_FrameData[3]
  PIN Tile_X0Y0_FrameData[4]
    DIRECTION INPUT ;
    USE SIGNAL ;
    ANTENNAGATEAREA 1.626300 ;
    ANTENNADIFFAREA 18.138599 ;
    PORT
      LAYER Metal3 ;
        RECT 0.000 1121.200 0.400 1121.600 ;
    END
  END Tile_X0Y0_FrameData[4]
  PIN Tile_X0Y0_FrameData[5]
    DIRECTION INPUT ;
    USE SIGNAL ;
    ANTENNAGATEAREA 1.626300 ;
    ANTENNADIFFAREA 18.138599 ;
    PORT
      LAYER Metal3 ;
        RECT 0.000 1127.080 0.400 1127.480 ;
    END
  END Tile_X0Y0_FrameData[5]
  PIN Tile_X0Y0_FrameData[6]
    DIRECTION INPUT ;
    USE SIGNAL ;
    ANTENNAGATEAREA 1.626300 ;
    ANTENNADIFFAREA 18.138599 ;
    PORT
      LAYER Metal3 ;
        RECT 0.000 1132.960 0.400 1133.360 ;
    END
  END Tile_X0Y0_FrameData[6]
  PIN Tile_X0Y0_FrameData[7]
    DIRECTION INPUT ;
    USE SIGNAL ;
    ANTENNAGATEAREA 1.626300 ;
    ANTENNADIFFAREA 18.138599 ;
    PORT
      LAYER Metal3 ;
        RECT 0.000 1138.840 0.400 1139.240 ;
    END
  END Tile_X0Y0_FrameData[7]
  PIN Tile_X0Y0_FrameData[8]
    DIRECTION INPUT ;
    USE SIGNAL ;
    ANTENNAGATEAREA 1.626300 ;
    ANTENNADIFFAREA 18.138599 ;
    PORT
      LAYER Metal3 ;
        RECT 0.000 1144.720 0.400 1145.120 ;
    END
  END Tile_X0Y0_FrameData[8]
  PIN Tile_X0Y0_FrameData[9]
    DIRECTION INPUT ;
    USE SIGNAL ;
    ANTENNAGATEAREA 1.626300 ;
    ANTENNADIFFAREA 18.138599 ;
    PORT
      LAYER Metal3 ;
        RECT 0.000 1150.600 0.400 1151.000 ;
    END
  END Tile_X0Y0_FrameData[9]
  PIN Tile_X0Y0_FrameData_O[0]
    DIRECTION OUTPUT ;
    USE SIGNAL ;
    ANTENNADIFFAREA 2.724000 ;
    PORT
      LAYER Metal3 ;
        RECT 146.960 1239.640 147.360 1240.040 ;
    END
  END Tile_X0Y0_FrameData_O[0]
  PIN Tile_X0Y0_FrameData_O[10]
    DIRECTION OUTPUT ;
    USE SIGNAL ;
    ANTENNADIFFAREA 2.724000 ;
    PORT
      LAYER Metal3 ;
        RECT 146.960 1256.440 147.360 1256.840 ;
    END
  END Tile_X0Y0_FrameData_O[10]
  PIN Tile_X0Y0_FrameData_O[11]
    DIRECTION OUTPUT ;
    USE SIGNAL ;
    ANTENNADIFFAREA 2.724000 ;
    PORT
      LAYER Metal3 ;
        RECT 146.960 1258.120 147.360 1258.520 ;
    END
  END Tile_X0Y0_FrameData_O[11]
  PIN Tile_X0Y0_FrameData_O[12]
    DIRECTION OUTPUT ;
    USE SIGNAL ;
    ANTENNADIFFAREA 2.724000 ;
    PORT
      LAYER Metal3 ;
        RECT 146.960 1259.800 147.360 1260.200 ;
    END
  END Tile_X0Y0_FrameData_O[12]
  PIN Tile_X0Y0_FrameData_O[13]
    DIRECTION OUTPUT ;
    USE SIGNAL ;
    ANTENNADIFFAREA 2.724000 ;
    PORT
      LAYER Metal3 ;
        RECT 146.960 1261.480 147.360 1261.880 ;
    END
  END Tile_X0Y0_FrameData_O[13]
  PIN Tile_X0Y0_FrameData_O[14]
    DIRECTION OUTPUT ;
    USE SIGNAL ;
    ANTENNADIFFAREA 2.724000 ;
    PORT
      LAYER Metal3 ;
        RECT 146.960 1263.160 147.360 1263.560 ;
    END
  END Tile_X0Y0_FrameData_O[14]
  PIN Tile_X0Y0_FrameData_O[15]
    DIRECTION OUTPUT ;
    USE SIGNAL ;
    ANTENNADIFFAREA 2.724000 ;
    PORT
      LAYER Metal3 ;
        RECT 146.960 1264.840 147.360 1265.240 ;
    END
  END Tile_X0Y0_FrameData_O[15]
  PIN Tile_X0Y0_FrameData_O[16]
    DIRECTION OUTPUT ;
    USE SIGNAL ;
    ANTENNADIFFAREA 2.724000 ;
    PORT
      LAYER Metal3 ;
        RECT 146.960 1266.520 147.360 1266.920 ;
    END
  END Tile_X0Y0_FrameData_O[16]
  PIN Tile_X0Y0_FrameData_O[17]
    DIRECTION OUTPUT ;
    USE SIGNAL ;
    ANTENNADIFFAREA 2.724000 ;
    PORT
      LAYER Metal3 ;
        RECT 146.960 1268.200 147.360 1268.600 ;
    END
  END Tile_X0Y0_FrameData_O[17]
  PIN Tile_X0Y0_FrameData_O[18]
    DIRECTION OUTPUT ;
    USE SIGNAL ;
    ANTENNADIFFAREA 2.724000 ;
    PORT
      LAYER Metal3 ;
        RECT 146.960 1269.880 147.360 1270.280 ;
    END
  END Tile_X0Y0_FrameData_O[18]
  PIN Tile_X0Y0_FrameData_O[19]
    DIRECTION OUTPUT ;
    USE SIGNAL ;
    ANTENNADIFFAREA 2.724000 ;
    PORT
      LAYER Metal3 ;
        RECT 146.960 1271.560 147.360 1271.960 ;
    END
  END Tile_X0Y0_FrameData_O[19]
  PIN Tile_X0Y0_FrameData_O[1]
    DIRECTION OUTPUT ;
    USE SIGNAL ;
    ANTENNADIFFAREA 2.724000 ;
    PORT
      LAYER Metal3 ;
        RECT 146.960 1241.320 147.360 1241.720 ;
    END
  END Tile_X0Y0_FrameData_O[1]
  PIN Tile_X0Y0_FrameData_O[20]
    DIRECTION OUTPUT ;
    USE SIGNAL ;
    ANTENNADIFFAREA 2.724000 ;
    PORT
      LAYER Metal3 ;
        RECT 146.960 1273.240 147.360 1273.640 ;
    END
  END Tile_X0Y0_FrameData_O[20]
  PIN Tile_X0Y0_FrameData_O[21]
    DIRECTION OUTPUT ;
    USE SIGNAL ;
    ANTENNADIFFAREA 2.724000 ;
    PORT
      LAYER Metal3 ;
        RECT 146.960 1274.920 147.360 1275.320 ;
    END
  END Tile_X0Y0_FrameData_O[21]
  PIN Tile_X0Y0_FrameData_O[22]
    DIRECTION OUTPUT ;
    USE SIGNAL ;
    ANTENNADIFFAREA 2.724000 ;
    PORT
      LAYER Metal3 ;
        RECT 146.960 1276.600 147.360 1277.000 ;
    END
  END Tile_X0Y0_FrameData_O[22]
  PIN Tile_X0Y0_FrameData_O[23]
    DIRECTION OUTPUT ;
    USE SIGNAL ;
    ANTENNADIFFAREA 2.724000 ;
    PORT
      LAYER Metal3 ;
        RECT 146.960 1278.280 147.360 1278.680 ;
    END
  END Tile_X0Y0_FrameData_O[23]
  PIN Tile_X0Y0_FrameData_O[24]
    DIRECTION OUTPUT ;
    USE SIGNAL ;
    ANTENNADIFFAREA 2.724000 ;
    PORT
      LAYER Metal3 ;
        RECT 146.960 1279.960 147.360 1280.360 ;
    END
  END Tile_X0Y0_FrameData_O[24]
  PIN Tile_X0Y0_FrameData_O[25]
    DIRECTION OUTPUT ;
    USE SIGNAL ;
    ANTENNADIFFAREA 2.724000 ;
    PORT
      LAYER Metal3 ;
        RECT 146.960 1281.640 147.360 1282.040 ;
    END
  END Tile_X0Y0_FrameData_O[25]
  PIN Tile_X0Y0_FrameData_O[26]
    DIRECTION OUTPUT ;
    USE SIGNAL ;
    ANTENNADIFFAREA 2.724000 ;
    PORT
      LAYER Metal3 ;
        RECT 146.960 1283.320 147.360 1283.720 ;
    END
  END Tile_X0Y0_FrameData_O[26]
  PIN Tile_X0Y0_FrameData_O[27]
    DIRECTION OUTPUT ;
    USE SIGNAL ;
    ANTENNADIFFAREA 2.724000 ;
    PORT
      LAYER Metal3 ;
        RECT 146.960 1285.000 147.360 1285.400 ;
    END
  END Tile_X0Y0_FrameData_O[27]
  PIN Tile_X0Y0_FrameData_O[28]
    DIRECTION OUTPUT ;
    USE SIGNAL ;
    ANTENNADIFFAREA 2.724000 ;
    PORT
      LAYER Metal3 ;
        RECT 146.960 1286.680 147.360 1287.080 ;
    END
  END Tile_X0Y0_FrameData_O[28]
  PIN Tile_X0Y0_FrameData_O[29]
    DIRECTION OUTPUT ;
    USE SIGNAL ;
    ANTENNADIFFAREA 2.724000 ;
    PORT
      LAYER Metal3 ;
        RECT 146.960 1288.360 147.360 1288.760 ;
    END
  END Tile_X0Y0_FrameData_O[29]
  PIN Tile_X0Y0_FrameData_O[2]
    DIRECTION OUTPUT ;
    USE SIGNAL ;
    ANTENNADIFFAREA 2.724000 ;
    PORT
      LAYER Metal3 ;
        RECT 146.960 1243.000 147.360 1243.400 ;
    END
  END Tile_X0Y0_FrameData_O[2]
  PIN Tile_X0Y0_FrameData_O[30]
    DIRECTION OUTPUT ;
    USE SIGNAL ;
    ANTENNADIFFAREA 2.724000 ;
    PORT
      LAYER Metal3 ;
        RECT 146.960 1290.040 147.360 1290.440 ;
    END
  END Tile_X0Y0_FrameData_O[30]
  PIN Tile_X0Y0_FrameData_O[31]
    DIRECTION OUTPUT ;
    USE SIGNAL ;
    ANTENNADIFFAREA 2.724000 ;
    PORT
      LAYER Metal3 ;
        RECT 146.960 1291.720 147.360 1292.120 ;
    END
  END Tile_X0Y0_FrameData_O[31]
  PIN Tile_X0Y0_FrameData_O[3]
    DIRECTION OUTPUT ;
    USE SIGNAL ;
    ANTENNADIFFAREA 2.724000 ;
    PORT
      LAYER Metal3 ;
        RECT 146.960 1244.680 147.360 1245.080 ;
    END
  END Tile_X0Y0_FrameData_O[3]
  PIN Tile_X0Y0_FrameData_O[4]
    DIRECTION OUTPUT ;
    USE SIGNAL ;
    ANTENNADIFFAREA 2.724000 ;
    PORT
      LAYER Metal3 ;
        RECT 146.960 1246.360 147.360 1246.760 ;
    END
  END Tile_X0Y0_FrameData_O[4]
  PIN Tile_X0Y0_FrameData_O[5]
    DIRECTION OUTPUT ;
    USE SIGNAL ;
    ANTENNADIFFAREA 2.724000 ;
    PORT
      LAYER Metal3 ;
        RECT 146.960 1248.040 147.360 1248.440 ;
    END
  END Tile_X0Y0_FrameData_O[5]
  PIN Tile_X0Y0_FrameData_O[6]
    DIRECTION OUTPUT ;
    USE SIGNAL ;
    ANTENNADIFFAREA 2.724000 ;
    PORT
      LAYER Metal3 ;
        RECT 146.960 1249.720 147.360 1250.120 ;
    END
  END Tile_X0Y0_FrameData_O[6]
  PIN Tile_X0Y0_FrameData_O[7]
    DIRECTION OUTPUT ;
    USE SIGNAL ;
    ANTENNADIFFAREA 2.724000 ;
    PORT
      LAYER Metal3 ;
        RECT 146.960 1251.400 147.360 1251.800 ;
    END
  END Tile_X0Y0_FrameData_O[7]
  PIN Tile_X0Y0_FrameData_O[8]
    DIRECTION OUTPUT ;
    USE SIGNAL ;
    ANTENNADIFFAREA 2.724000 ;
    PORT
      LAYER Metal3 ;
        RECT 146.960 1253.080 147.360 1253.480 ;
    END
  END Tile_X0Y0_FrameData_O[8]
  PIN Tile_X0Y0_FrameData_O[9]
    DIRECTION OUTPUT ;
    USE SIGNAL ;
    ANTENNADIFFAREA 2.724000 ;
    PORT
      LAYER Metal3 ;
        RECT 146.960 1254.760 147.360 1255.160 ;
    END
  END Tile_X0Y0_FrameData_O[9]
  PIN Tile_X0Y0_FrameStrobe_O[0]
    DIRECTION OUTPUT ;
    USE SIGNAL ;
    ANTENNADIFFAREA 2.724000 ;
    PORT
      LAYER Metal2 ;
        RECT 122.200 1292.360 122.600 1292.760 ;
    END
  END Tile_X0Y0_FrameStrobe_O[0]
  PIN Tile_X0Y0_FrameStrobe_O[10]
    DIRECTION OUTPUT ;
    USE SIGNAL ;
    ANTENNADIFFAREA 2.724000 ;
    PORT
      LAYER Metal2 ;
        RECT 131.800 1292.360 132.200 1292.760 ;
    END
  END Tile_X0Y0_FrameStrobe_O[10]
  PIN Tile_X0Y0_FrameStrobe_O[11]
    DIRECTION OUTPUT ;
    USE SIGNAL ;
    ANTENNADIFFAREA 2.724000 ;
    PORT
      LAYER Metal2 ;
        RECT 132.760 1292.360 133.160 1292.760 ;
    END
  END Tile_X0Y0_FrameStrobe_O[11]
  PIN Tile_X0Y0_FrameStrobe_O[12]
    DIRECTION OUTPUT ;
    USE SIGNAL ;
    ANTENNADIFFAREA 2.724000 ;
    PORT
      LAYER Metal2 ;
        RECT 133.720 1292.360 134.120 1292.760 ;
    END
  END Tile_X0Y0_FrameStrobe_O[12]
  PIN Tile_X0Y0_FrameStrobe_O[13]
    DIRECTION OUTPUT ;
    USE SIGNAL ;
    ANTENNADIFFAREA 2.724000 ;
    PORT
      LAYER Metal2 ;
        RECT 134.680 1292.360 135.080 1292.760 ;
    END
  END Tile_X0Y0_FrameStrobe_O[13]
  PIN Tile_X0Y0_FrameStrobe_O[14]
    DIRECTION OUTPUT ;
    USE SIGNAL ;
    ANTENNADIFFAREA 2.724000 ;
    PORT
      LAYER Metal2 ;
        RECT 135.640 1292.360 136.040 1292.760 ;
    END
  END Tile_X0Y0_FrameStrobe_O[14]
  PIN Tile_X0Y0_FrameStrobe_O[15]
    DIRECTION OUTPUT ;
    USE SIGNAL ;
    ANTENNADIFFAREA 2.724000 ;
    PORT
      LAYER Metal2 ;
        RECT 136.600 1292.360 137.000 1292.760 ;
    END
  END Tile_X0Y0_FrameStrobe_O[15]
  PIN Tile_X0Y0_FrameStrobe_O[16]
    DIRECTION OUTPUT ;
    USE SIGNAL ;
    ANTENNADIFFAREA 2.724000 ;
    PORT
      LAYER Metal2 ;
        RECT 137.560 1292.360 137.960 1292.760 ;
    END
  END Tile_X0Y0_FrameStrobe_O[16]
  PIN Tile_X0Y0_FrameStrobe_O[17]
    DIRECTION OUTPUT ;
    USE SIGNAL ;
    ANTENNADIFFAREA 2.724000 ;
    PORT
      LAYER Metal2 ;
        RECT 138.520 1292.360 138.920 1292.760 ;
    END
  END Tile_X0Y0_FrameStrobe_O[17]
  PIN Tile_X0Y0_FrameStrobe_O[18]
    DIRECTION OUTPUT ;
    USE SIGNAL ;
    ANTENNADIFFAREA 2.724000 ;
    PORT
      LAYER Metal2 ;
        RECT 139.480 1292.360 139.880 1292.760 ;
    END
  END Tile_X0Y0_FrameStrobe_O[18]
  PIN Tile_X0Y0_FrameStrobe_O[19]
    DIRECTION OUTPUT ;
    USE SIGNAL ;
    ANTENNADIFFAREA 2.724000 ;
    PORT
      LAYER Metal2 ;
        RECT 140.440 1292.360 140.840 1292.760 ;
    END
  END Tile_X0Y0_FrameStrobe_O[19]
  PIN Tile_X0Y0_FrameStrobe_O[1]
    DIRECTION OUTPUT ;
    USE SIGNAL ;
    ANTENNADIFFAREA 2.724000 ;
    PORT
      LAYER Metal2 ;
        RECT 123.160 1292.360 123.560 1292.760 ;
    END
  END Tile_X0Y0_FrameStrobe_O[1]
  PIN Tile_X0Y0_FrameStrobe_O[2]
    DIRECTION OUTPUT ;
    USE SIGNAL ;
    ANTENNADIFFAREA 2.724000 ;
    PORT
      LAYER Metal2 ;
        RECT 124.120 1292.360 124.520 1292.760 ;
    END
  END Tile_X0Y0_FrameStrobe_O[2]
  PIN Tile_X0Y0_FrameStrobe_O[3]
    DIRECTION OUTPUT ;
    USE SIGNAL ;
    ANTENNADIFFAREA 2.724000 ;
    PORT
      LAYER Metal2 ;
        RECT 125.080 1292.360 125.480 1292.760 ;
    END
  END Tile_X0Y0_FrameStrobe_O[3]
  PIN Tile_X0Y0_FrameStrobe_O[4]
    DIRECTION OUTPUT ;
    USE SIGNAL ;
    ANTENNADIFFAREA 2.724000 ;
    PORT
      LAYER Metal2 ;
        RECT 126.040 1292.360 126.440 1292.760 ;
    END
  END Tile_X0Y0_FrameStrobe_O[4]
  PIN Tile_X0Y0_FrameStrobe_O[5]
    DIRECTION OUTPUT ;
    USE SIGNAL ;
    ANTENNADIFFAREA 2.724000 ;
    PORT
      LAYER Metal2 ;
        RECT 127.000 1292.360 127.400 1292.760 ;
    END
  END Tile_X0Y0_FrameStrobe_O[5]
  PIN Tile_X0Y0_FrameStrobe_O[6]
    DIRECTION OUTPUT ;
    USE SIGNAL ;
    ANTENNADIFFAREA 2.724000 ;
    PORT
      LAYER Metal2 ;
        RECT 127.960 1292.360 128.360 1292.760 ;
    END
  END Tile_X0Y0_FrameStrobe_O[6]
  PIN Tile_X0Y0_FrameStrobe_O[7]
    DIRECTION OUTPUT ;
    USE SIGNAL ;
    ANTENNADIFFAREA 2.724000 ;
    PORT
      LAYER Metal2 ;
        RECT 128.920 1292.360 129.320 1292.760 ;
    END
  END Tile_X0Y0_FrameStrobe_O[7]
  PIN Tile_X0Y0_FrameStrobe_O[8]
    DIRECTION OUTPUT ;
    USE SIGNAL ;
    ANTENNADIFFAREA 2.724000 ;
    PORT
      LAYER Metal2 ;
        RECT 129.880 1292.360 130.280 1292.760 ;
    END
  END Tile_X0Y0_FrameStrobe_O[8]
  PIN Tile_X0Y0_FrameStrobe_O[9]
    DIRECTION OUTPUT ;
    USE SIGNAL ;
    ANTENNADIFFAREA 2.724000 ;
    PORT
      LAYER Metal2 ;
        RECT 130.840 1292.360 131.240 1292.760 ;
    END
  END Tile_X0Y0_FrameStrobe_O[9]
  PIN Tile_X0Y0_N1BEG[0]
    DIRECTION OUTPUT ;
    USE SIGNAL ;
    ANTENNADIFFAREA 2.724000 ;
    PORT
      LAYER Metal2 ;
        RECT 2.200 1292.360 2.600 1292.760 ;
    END
  END Tile_X0Y0_N1BEG[0]
  PIN Tile_X0Y0_N1BEG[1]
    DIRECTION OUTPUT ;
    USE SIGNAL ;
    ANTENNADIFFAREA 2.724000 ;
    PORT
      LAYER Metal2 ;
        RECT 3.160 1292.360 3.560 1292.760 ;
    END
  END Tile_X0Y0_N1BEG[1]
  PIN Tile_X0Y0_N1BEG[2]
    DIRECTION OUTPUT ;
    USE SIGNAL ;
    ANTENNADIFFAREA 2.724000 ;
    PORT
      LAYER Metal2 ;
        RECT 4.120 1292.360 4.520 1292.760 ;
    END
  END Tile_X0Y0_N1BEG[2]
  PIN Tile_X0Y0_N1BEG[3]
    DIRECTION OUTPUT ;
    USE SIGNAL ;
    ANTENNADIFFAREA 2.724000 ;
    PORT
      LAYER Metal2 ;
        RECT 5.080 1292.360 5.480 1292.760 ;
    END
  END Tile_X0Y0_N1BEG[3]
  PIN Tile_X0Y0_N2BEG[0]
    DIRECTION OUTPUT ;
    USE SIGNAL ;
    ANTENNADIFFAREA 2.724000 ;
    PORT
      LAYER Metal2 ;
        RECT 9.880 1292.360 10.280 1292.760 ;
    END
  END Tile_X0Y0_N2BEG[0]
  PIN Tile_X0Y0_N2BEG[1]
    DIRECTION OUTPUT ;
    USE SIGNAL ;
    ANTENNADIFFAREA 2.724000 ;
    PORT
      LAYER Metal2 ;
        RECT 10.840 1292.360 11.240 1292.760 ;
    END
  END Tile_X0Y0_N2BEG[1]
  PIN Tile_X0Y0_N2BEG[2]
    DIRECTION OUTPUT ;
    USE SIGNAL ;
    ANTENNADIFFAREA 2.724000 ;
    PORT
      LAYER Metal2 ;
        RECT 11.800 1292.360 12.200 1292.760 ;
    END
  END Tile_X0Y0_N2BEG[2]
  PIN Tile_X0Y0_N2BEG[3]
    DIRECTION OUTPUT ;
    USE SIGNAL ;
    ANTENNADIFFAREA 2.724000 ;
    PORT
      LAYER Metal2 ;
        RECT 12.760 1292.360 13.160 1292.760 ;
    END
  END Tile_X0Y0_N2BEG[3]
  PIN Tile_X0Y0_N2BEG[4]
    DIRECTION OUTPUT ;
    USE SIGNAL ;
    ANTENNADIFFAREA 2.724000 ;
    PORT
      LAYER Metal2 ;
        RECT 13.720 1292.360 14.120 1292.760 ;
    END
  END Tile_X0Y0_N2BEG[4]
  PIN Tile_X0Y0_N2BEG[5]
    DIRECTION OUTPUT ;
    USE SIGNAL ;
    ANTENNADIFFAREA 2.724000 ;
    PORT
      LAYER Metal2 ;
        RECT 14.680 1292.360 15.080 1292.760 ;
    END
  END Tile_X0Y0_N2BEG[5]
  PIN Tile_X0Y0_N2BEG[6]
    DIRECTION OUTPUT ;
    USE SIGNAL ;
    ANTENNADIFFAREA 2.724000 ;
    PORT
      LAYER Metal2 ;
        RECT 15.640 1292.360 16.040 1292.760 ;
    END
  END Tile_X0Y0_N2BEG[6]
  PIN Tile_X0Y0_N2BEG[7]
    DIRECTION OUTPUT ;
    USE SIGNAL ;
    ANTENNADIFFAREA 2.724000 ;
    PORT
      LAYER Metal2 ;
        RECT 16.600 1292.360 17.000 1292.760 ;
    END
  END Tile_X0Y0_N2BEG[7]
  PIN Tile_X0Y0_N2BEGb[0]
    DIRECTION OUTPUT ;
    USE SIGNAL ;
    ANTENNADIFFAREA 2.724000 ;
    PORT
      LAYER Metal2 ;
        RECT 22.360 1292.360 22.760 1292.760 ;
    END
  END Tile_X0Y0_N2BEGb[0]
  PIN Tile_X0Y0_N2BEGb[1]
    DIRECTION OUTPUT ;
    USE SIGNAL ;
    ANTENNADIFFAREA 2.724000 ;
    PORT
      LAYER Metal2 ;
        RECT 23.320 1292.360 23.720 1292.760 ;
    END
  END Tile_X0Y0_N2BEGb[1]
  PIN Tile_X0Y0_N2BEGb[2]
    DIRECTION OUTPUT ;
    USE SIGNAL ;
    ANTENNADIFFAREA 2.724000 ;
    PORT
      LAYER Metal2 ;
        RECT 24.280 1292.360 24.680 1292.760 ;
    END
  END Tile_X0Y0_N2BEGb[2]
  PIN Tile_X0Y0_N2BEGb[3]
    DIRECTION OUTPUT ;
    USE SIGNAL ;
    ANTENNADIFFAREA 2.724000 ;
    PORT
      LAYER Metal2 ;
        RECT 25.240 1292.360 25.640 1292.760 ;
    END
  END Tile_X0Y0_N2BEGb[3]
  PIN Tile_X0Y0_N2BEGb[4]
    DIRECTION OUTPUT ;
    USE SIGNAL ;
    ANTENNADIFFAREA 2.724000 ;
    PORT
      LAYER Metal2 ;
        RECT 26.200 1292.360 26.600 1292.760 ;
    END
  END Tile_X0Y0_N2BEGb[4]
  PIN Tile_X0Y0_N2BEGb[5]
    DIRECTION OUTPUT ;
    USE SIGNAL ;
    ANTENNADIFFAREA 2.724000 ;
    PORT
      LAYER Metal2 ;
        RECT 27.160 1292.360 27.560 1292.760 ;
    END
  END Tile_X0Y0_N2BEGb[5]
  PIN Tile_X0Y0_N2BEGb[6]
    DIRECTION OUTPUT ;
    USE SIGNAL ;
    ANTENNADIFFAREA 2.724000 ;
    PORT
      LAYER Metal2 ;
        RECT 28.120 1292.360 28.520 1292.760 ;
    END
  END Tile_X0Y0_N2BEGb[6]
  PIN Tile_X0Y0_N2BEGb[7]
    DIRECTION OUTPUT ;
    USE SIGNAL ;
    ANTENNADIFFAREA 2.724000 ;
    PORT
      LAYER Metal2 ;
        RECT 29.080 1292.360 29.480 1292.760 ;
    END
  END Tile_X0Y0_N2BEGb[7]
  PIN Tile_X0Y0_N4BEG[0]
    DIRECTION OUTPUT ;
    USE SIGNAL ;
    ANTENNADIFFAREA 2.724000 ;
    PORT
      LAYER Metal2 ;
        RECT 37.720 1292.360 38.120 1292.760 ;
    END
  END Tile_X0Y0_N4BEG[0]
  PIN Tile_X0Y0_N4BEG[10]
    DIRECTION OUTPUT ;
    USE SIGNAL ;
    ANTENNADIFFAREA 2.724000 ;
    PORT
      LAYER Metal2 ;
        RECT 47.320 1292.360 47.720 1292.760 ;
    END
  END Tile_X0Y0_N4BEG[10]
  PIN Tile_X0Y0_N4BEG[11]
    DIRECTION OUTPUT ;
    USE SIGNAL ;
    ANTENNADIFFAREA 2.724000 ;
    PORT
      LAYER Metal2 ;
        RECT 48.280 1292.360 48.680 1292.760 ;
    END
  END Tile_X0Y0_N4BEG[11]
  PIN Tile_X0Y0_N4BEG[12]
    DIRECTION OUTPUT ;
    USE SIGNAL ;
    ANTENNADIFFAREA 2.724000 ;
    PORT
      LAYER Metal2 ;
        RECT 49.240 1292.360 49.640 1292.760 ;
    END
  END Tile_X0Y0_N4BEG[12]
  PIN Tile_X0Y0_N4BEG[13]
    DIRECTION OUTPUT ;
    USE SIGNAL ;
    ANTENNADIFFAREA 2.724000 ;
    PORT
      LAYER Metal2 ;
        RECT 50.200 1292.360 50.600 1292.760 ;
    END
  END Tile_X0Y0_N4BEG[13]
  PIN Tile_X0Y0_N4BEG[14]
    DIRECTION OUTPUT ;
    USE SIGNAL ;
    ANTENNADIFFAREA 2.724000 ;
    PORT
      LAYER Metal2 ;
        RECT 51.160 1292.360 51.560 1292.760 ;
    END
  END Tile_X0Y0_N4BEG[14]
  PIN Tile_X0Y0_N4BEG[15]
    DIRECTION OUTPUT ;
    USE SIGNAL ;
    ANTENNADIFFAREA 2.724000 ;
    PORT
      LAYER Metal2 ;
        RECT 52.120 1292.360 52.520 1292.760 ;
    END
  END Tile_X0Y0_N4BEG[15]
  PIN Tile_X0Y0_N4BEG[1]
    DIRECTION OUTPUT ;
    USE SIGNAL ;
    ANTENNADIFFAREA 2.724000 ;
    PORT
      LAYER Metal2 ;
        RECT 38.680 1292.360 39.080 1292.760 ;
    END
  END Tile_X0Y0_N4BEG[1]
  PIN Tile_X0Y0_N4BEG[2]
    DIRECTION OUTPUT ;
    USE SIGNAL ;
    ANTENNADIFFAREA 2.724000 ;
    PORT
      LAYER Metal2 ;
        RECT 39.640 1292.360 40.040 1292.760 ;
    END
  END Tile_X0Y0_N4BEG[2]
  PIN Tile_X0Y0_N4BEG[3]
    DIRECTION OUTPUT ;
    USE SIGNAL ;
    ANTENNADIFFAREA 2.724000 ;
    PORT
      LAYER Metal2 ;
        RECT 40.600 1292.360 41.000 1292.760 ;
    END
  END Tile_X0Y0_N4BEG[3]
  PIN Tile_X0Y0_N4BEG[4]
    DIRECTION OUTPUT ;
    USE SIGNAL ;
    ANTENNADIFFAREA 2.724000 ;
    PORT
      LAYER Metal2 ;
        RECT 41.560 1292.360 41.960 1292.760 ;
    END
  END Tile_X0Y0_N4BEG[4]
  PIN Tile_X0Y0_N4BEG[5]
    DIRECTION OUTPUT ;
    USE SIGNAL ;
    ANTENNADIFFAREA 2.724000 ;
    PORT
      LAYER Metal2 ;
        RECT 42.520 1292.360 42.920 1292.760 ;
    END
  END Tile_X0Y0_N4BEG[5]
  PIN Tile_X0Y0_N4BEG[6]
    DIRECTION OUTPUT ;
    USE SIGNAL ;
    ANTENNADIFFAREA 2.724000 ;
    PORT
      LAYER Metal2 ;
        RECT 43.480 1292.360 43.880 1292.760 ;
    END
  END Tile_X0Y0_N4BEG[6]
  PIN Tile_X0Y0_N4BEG[7]
    DIRECTION OUTPUT ;
    USE SIGNAL ;
    ANTENNADIFFAREA 2.724000 ;
    PORT
      LAYER Metal2 ;
        RECT 44.440 1292.360 44.840 1292.760 ;
    END
  END Tile_X0Y0_N4BEG[7]
  PIN Tile_X0Y0_N4BEG[8]
    DIRECTION OUTPUT ;
    USE SIGNAL ;
    ANTENNADIFFAREA 2.724000 ;
    PORT
      LAYER Metal2 ;
        RECT 45.400 1292.360 45.800 1292.760 ;
    END
  END Tile_X0Y0_N4BEG[8]
  PIN Tile_X0Y0_N4BEG[9]
    DIRECTION OUTPUT ;
    USE SIGNAL ;
    ANTENNADIFFAREA 2.724000 ;
    PORT
      LAYER Metal2 ;
        RECT 46.360 1292.360 46.760 1292.760 ;
    END
  END Tile_X0Y0_N4BEG[9]
  PIN Tile_X0Y0_S1END[0]
    DIRECTION INPUT ;
    USE SIGNAL ;
    ANTENNAGATEAREA 1.307800 ;
    ANTENNADIFFAREA 12.092400 ;
    PORT
      LAYER Metal2 ;
        RECT 58.840 1292.360 59.240 1292.760 ;
    END
  END Tile_X0Y0_S1END[0]
  PIN Tile_X0Y0_S1END[1]
    DIRECTION INPUT ;
    USE SIGNAL ;
    ANTENNAGATEAREA 1.307800 ;
    ANTENNADIFFAREA 12.092400 ;
    PORT
      LAYER Metal2 ;
        RECT 59.800 1292.360 60.200 1292.760 ;
    END
  END Tile_X0Y0_S1END[1]
  PIN Tile_X0Y0_S1END[2]
    DIRECTION INPUT ;
    USE SIGNAL ;
    ANTENNAGATEAREA 1.307800 ;
    ANTENNADIFFAREA 12.092400 ;
    PORT
      LAYER Metal2 ;
        RECT 60.760 1292.360 61.160 1292.760 ;
    END
  END Tile_X0Y0_S1END[2]
  PIN Tile_X0Y0_S1END[3]
    DIRECTION INPUT ;
    USE SIGNAL ;
    ANTENNAGATEAREA 1.307800 ;
    ANTENNADIFFAREA 12.092400 ;
    PORT
      LAYER Metal2 ;
        RECT 61.720 1292.360 62.120 1292.760 ;
    END
  END Tile_X0Y0_S1END[3]
  PIN Tile_X0Y0_S2END[0]
    DIRECTION INPUT ;
    USE SIGNAL ;
    ANTENNAGATEAREA 0.213200 ;
    ANTENNADIFFAREA 2.015400 ;
    PORT
      LAYER Metal2 ;
        RECT 79.000 1292.360 79.400 1292.760 ;
    END
  END Tile_X0Y0_S2END[0]
  PIN Tile_X0Y0_S2END[1]
    DIRECTION INPUT ;
    USE SIGNAL ;
    ANTENNAGATEAREA 0.213200 ;
    ANTENNADIFFAREA 2.015400 ;
    PORT
      LAYER Metal2 ;
        RECT 79.960 1292.360 80.360 1292.760 ;
    END
  END Tile_X0Y0_S2END[1]
  PIN Tile_X0Y0_S2END[2]
    DIRECTION INPUT ;
    USE SIGNAL ;
    ANTENNAGATEAREA 0.213200 ;
    ANTENNADIFFAREA 2.015400 ;
    PORT
      LAYER Metal2 ;
        RECT 80.920 1292.360 81.320 1292.760 ;
    END
  END Tile_X0Y0_S2END[2]
  PIN Tile_X0Y0_S2END[3]
    DIRECTION INPUT ;
    USE SIGNAL ;
    ANTENNAGATEAREA 0.213200 ;
    ANTENNADIFFAREA 2.015400 ;
    PORT
      LAYER Metal2 ;
        RECT 81.880 1292.360 82.280 1292.760 ;
    END
  END Tile_X0Y0_S2END[3]
  PIN Tile_X0Y0_S2END[4]
    DIRECTION INPUT ;
    USE SIGNAL ;
    ANTENNAGATEAREA 0.213200 ;
    ANTENNADIFFAREA 2.015400 ;
    PORT
      LAYER Metal2 ;
        RECT 82.840 1292.360 83.240 1292.760 ;
    END
  END Tile_X0Y0_S2END[4]
  PIN Tile_X0Y0_S2END[5]
    DIRECTION INPUT ;
    USE SIGNAL ;
    ANTENNAGATEAREA 0.213200 ;
    ANTENNADIFFAREA 2.015400 ;
    PORT
      LAYER Metal2 ;
        RECT 83.800 1292.360 84.200 1292.760 ;
    END
  END Tile_X0Y0_S2END[5]
  PIN Tile_X0Y0_S2END[6]
    DIRECTION INPUT ;
    USE SIGNAL ;
    ANTENNAGATEAREA 0.213200 ;
    ANTENNADIFFAREA 2.015400 ;
    PORT
      LAYER Metal2 ;
        RECT 84.760 1292.360 85.160 1292.760 ;
    END
  END Tile_X0Y0_S2END[6]
  PIN Tile_X0Y0_S2END[7]
    DIRECTION INPUT ;
    USE SIGNAL ;
    ANTENNAGATEAREA 0.213200 ;
    ANTENNADIFFAREA 2.015400 ;
    PORT
      LAYER Metal2 ;
        RECT 85.720 1292.360 86.120 1292.760 ;
    END
  END Tile_X0Y0_S2END[7]
  PIN Tile_X0Y0_S2MID[0]
    DIRECTION INPUT ;
    USE SIGNAL ;
    ANTENNAGATEAREA 0.426400 ;
    ANTENNADIFFAREA 4.030800 ;
    PORT
      LAYER Metal2 ;
        RECT 66.520 1292.360 66.920 1292.760 ;
    END
  END Tile_X0Y0_S2MID[0]
  PIN Tile_X0Y0_S2MID[1]
    DIRECTION INPUT ;
    USE SIGNAL ;
    ANTENNAGATEAREA 0.426400 ;
    ANTENNADIFFAREA 4.030800 ;
    PORT
      LAYER Metal2 ;
        RECT 67.480 1292.360 67.880 1292.760 ;
    END
  END Tile_X0Y0_S2MID[1]
  PIN Tile_X0Y0_S2MID[2]
    DIRECTION INPUT ;
    USE SIGNAL ;
    ANTENNAGATEAREA 0.426400 ;
    ANTENNADIFFAREA 4.030800 ;
    PORT
      LAYER Metal2 ;
        RECT 68.440 1292.360 68.840 1292.760 ;
    END
  END Tile_X0Y0_S2MID[2]
  PIN Tile_X0Y0_S2MID[3]
    DIRECTION INPUT ;
    USE SIGNAL ;
    ANTENNAGATEAREA 0.426400 ;
    ANTENNADIFFAREA 4.030800 ;
    PORT
      LAYER Metal2 ;
        RECT 69.400 1292.360 69.800 1292.760 ;
    END
  END Tile_X0Y0_S2MID[3]
  PIN Tile_X0Y0_S2MID[4]
    DIRECTION INPUT ;
    USE SIGNAL ;
    ANTENNAGATEAREA 0.426400 ;
    ANTENNADIFFAREA 4.030800 ;
    PORT
      LAYER Metal2 ;
        RECT 70.360 1292.360 70.760 1292.760 ;
    END
  END Tile_X0Y0_S2MID[4]
  PIN Tile_X0Y0_S2MID[5]
    DIRECTION INPUT ;
    USE SIGNAL ;
    ANTENNAGATEAREA 0.426400 ;
    ANTENNADIFFAREA 4.030800 ;
    PORT
      LAYER Metal2 ;
        RECT 71.320 1292.360 71.720 1292.760 ;
    END
  END Tile_X0Y0_S2MID[5]
  PIN Tile_X0Y0_S2MID[6]
    DIRECTION INPUT ;
    USE SIGNAL ;
    ANTENNAGATEAREA 0.426400 ;
    ANTENNADIFFAREA 4.030800 ;
    PORT
      LAYER Metal2 ;
        RECT 72.280 1292.360 72.680 1292.760 ;
    END
  END Tile_X0Y0_S2MID[6]
  PIN Tile_X0Y0_S2MID[7]
    DIRECTION INPUT ;
    USE SIGNAL ;
    ANTENNAGATEAREA 0.426400 ;
    ANTENNADIFFAREA 4.030800 ;
    PORT
      LAYER Metal2 ;
        RECT 73.240 1292.360 73.640 1292.760 ;
    END
  END Tile_X0Y0_S2MID[7]
  PIN Tile_X0Y0_S4END[0]
    DIRECTION INPUT ;
    USE SIGNAL ;
    ANTENNAGATEAREA 1.066000 ;
    ANTENNADIFFAREA 10.077000 ;
    PORT
      LAYER Metal2 ;
        RECT 94.360 1292.360 94.760 1292.760 ;
    END
  END Tile_X0Y0_S4END[0]
  PIN Tile_X0Y0_S4END[10]
    DIRECTION INPUT ;
    USE SIGNAL ;
    ANTENNAGATEAREA 1.066000 ;
    ANTENNADIFFAREA 10.077000 ;
    PORT
      LAYER Metal2 ;
        RECT 103.960 1292.360 104.360 1292.760 ;
    END
  END Tile_X0Y0_S4END[10]
  PIN Tile_X0Y0_S4END[11]
    DIRECTION INPUT ;
    USE SIGNAL ;
    ANTENNAGATEAREA 1.066000 ;
    ANTENNADIFFAREA 10.077000 ;
    PORT
      LAYER Metal2 ;
        RECT 104.920 1292.360 105.320 1292.760 ;
    END
  END Tile_X0Y0_S4END[11]
  PIN Tile_X0Y0_S4END[12]
    DIRECTION INPUT ;
    USE SIGNAL ;
    ANTENNAGATEAREA 1.066000 ;
    ANTENNADIFFAREA 10.077000 ;
    PORT
      LAYER Metal2 ;
        RECT 105.880 1292.360 106.280 1292.760 ;
    END
  END Tile_X0Y0_S4END[12]
  PIN Tile_X0Y0_S4END[13]
    DIRECTION INPUT ;
    USE SIGNAL ;
    ANTENNAGATEAREA 1.066000 ;
    ANTENNADIFFAREA 10.077000 ;
    PORT
      LAYER Metal2 ;
        RECT 106.840 1292.360 107.240 1292.760 ;
    END
  END Tile_X0Y0_S4END[13]
  PIN Tile_X0Y0_S4END[14]
    DIRECTION INPUT ;
    USE SIGNAL ;
    ANTENNAGATEAREA 1.066000 ;
    ANTENNADIFFAREA 10.077000 ;
    PORT
      LAYER Metal2 ;
        RECT 107.800 1292.360 108.200 1292.760 ;
    END
  END Tile_X0Y0_S4END[14]
  PIN Tile_X0Y0_S4END[15]
    DIRECTION INPUT ;
    USE SIGNAL ;
    ANTENNAGATEAREA 1.066000 ;
    ANTENNADIFFAREA 10.077000 ;
    PORT
      LAYER Metal2 ;
        RECT 108.760 1292.360 109.160 1292.760 ;
    END
  END Tile_X0Y0_S4END[15]
  PIN Tile_X0Y0_S4END[1]
    DIRECTION INPUT ;
    USE SIGNAL ;
    ANTENNAGATEAREA 1.066000 ;
    ANTENNADIFFAREA 10.077000 ;
    PORT
      LAYER Metal2 ;
        RECT 95.320 1292.360 95.720 1292.760 ;
    END
  END Tile_X0Y0_S4END[1]
  PIN Tile_X0Y0_S4END[2]
    DIRECTION INPUT ;
    USE SIGNAL ;
    ANTENNAGATEAREA 1.066000 ;
    ANTENNADIFFAREA 10.077000 ;
    PORT
      LAYER Metal2 ;
        RECT 96.280 1292.360 96.680 1292.760 ;
    END
  END Tile_X0Y0_S4END[2]
  PIN Tile_X0Y0_S4END[3]
    DIRECTION INPUT ;
    USE SIGNAL ;
    ANTENNAGATEAREA 1.066000 ;
    ANTENNADIFFAREA 10.077000 ;
    PORT
      LAYER Metal2 ;
        RECT 97.240 1292.360 97.640 1292.760 ;
    END
  END Tile_X0Y0_S4END[3]
  PIN Tile_X0Y0_S4END[4]
    DIRECTION INPUT ;
    USE SIGNAL ;
    ANTENNAGATEAREA 1.066000 ;
    ANTENNADIFFAREA 10.077000 ;
    PORT
      LAYER Metal2 ;
        RECT 98.200 1292.360 98.600 1292.760 ;
    END
  END Tile_X0Y0_S4END[4]
  PIN Tile_X0Y0_S4END[5]
    DIRECTION INPUT ;
    USE SIGNAL ;
    ANTENNAGATEAREA 1.066000 ;
    ANTENNADIFFAREA 10.077000 ;
    PORT
      LAYER Metal2 ;
        RECT 99.160 1292.360 99.560 1292.760 ;
    END
  END Tile_X0Y0_S4END[5]
  PIN Tile_X0Y0_S4END[6]
    DIRECTION INPUT ;
    USE SIGNAL ;
    ANTENNAGATEAREA 1.066000 ;
    ANTENNADIFFAREA 10.077000 ;
    PORT
      LAYER Metal2 ;
        RECT 100.120 1292.360 100.520 1292.760 ;
    END
  END Tile_X0Y0_S4END[6]
  PIN Tile_X0Y0_S4END[7]
    DIRECTION INPUT ;
    USE SIGNAL ;
    ANTENNAGATEAREA 1.066000 ;
    ANTENNADIFFAREA 10.077000 ;
    PORT
      LAYER Metal2 ;
        RECT 101.080 1292.360 101.480 1292.760 ;
    END
  END Tile_X0Y0_S4END[7]
  PIN Tile_X0Y0_S4END[8]
    DIRECTION INPUT ;
    USE SIGNAL ;
    ANTENNAGATEAREA 1.066000 ;
    ANTENNADIFFAREA 10.077000 ;
    PORT
      LAYER Metal2 ;
        RECT 102.040 1292.360 102.440 1292.760 ;
    END
  END Tile_X0Y0_S4END[8]
  PIN Tile_X0Y0_S4END[9]
    DIRECTION INPUT ;
    USE SIGNAL ;
    ANTENNAGATEAREA 1.066000 ;
    ANTENNADIFFAREA 10.077000 ;
    PORT
      LAYER Metal2 ;
        RECT 103.000 1292.360 103.400 1292.760 ;
    END
  END Tile_X0Y0_S4END[9]
  PIN Tile_X0Y0_UserCLK
    DIRECTION INPUT ;
    USE SIGNAL ;
    ANTENNAGATEAREA 0.180700 ;
    ANTENNADIFFAREA 2.015400 ;
    PORT
      LAYER Metal3 ;
        RECT 0.000 1080.880 0.400 1081.280 ;
    END
  END Tile_X0Y0_UserCLK
  PIN Tile_X0Y0_UserCLKo
    DIRECTION OUTPUT ;
    USE SIGNAL ;
    ANTENNADIFFAREA 2.724000 ;
    PORT
      LAYER Metal3 ;
        RECT 146.960 1237.960 147.360 1238.360 ;
    END
  END Tile_X0Y0_UserCLKo
  PIN Tile_X0Y0_W1END[0]
    DIRECTION INPUT ;
    USE SIGNAL ;
    ANTENNAGATEAREA 1.279200 ;
    ANTENNADIFFAREA 12.092400 ;
    PORT
      LAYER Metal3 ;
        RECT 146.960 1157.320 147.360 1157.720 ;
    END
  END Tile_X0Y0_W1END[0]
  PIN Tile_X0Y0_W1END[1]
    DIRECTION INPUT ;
    USE SIGNAL ;
    ANTENNAGATEAREA 1.279200 ;
    ANTENNADIFFAREA 12.092400 ;
    PORT
      LAYER Metal3 ;
        RECT 146.960 1159.000 147.360 1159.400 ;
    END
  END Tile_X0Y0_W1END[1]
  PIN Tile_X0Y0_W1END[2]
    DIRECTION INPUT ;
    USE SIGNAL ;
    ANTENNAGATEAREA 1.279200 ;
    ANTENNADIFFAREA 12.092400 ;
    PORT
      LAYER Metal3 ;
        RECT 146.960 1160.680 147.360 1161.080 ;
    END
  END Tile_X0Y0_W1END[2]
  PIN Tile_X0Y0_W1END[3]
    DIRECTION INPUT ;
    USE SIGNAL ;
    ANTENNAGATEAREA 1.279200 ;
    ANTENNADIFFAREA 12.092400 ;
    PORT
      LAYER Metal3 ;
        RECT 146.960 1162.360 147.360 1162.760 ;
    END
  END Tile_X0Y0_W1END[3]
  PIN Tile_X0Y0_W2END[0]
    DIRECTION INPUT ;
    USE SIGNAL ;
    ANTENNAGATEAREA 0.852800 ;
    ANTENNADIFFAREA 8.061600 ;
    PORT
      LAYER Metal3 ;
        RECT 146.960 1177.480 147.360 1177.880 ;
    END
  END Tile_X0Y0_W2END[0]
  PIN Tile_X0Y0_W2END[1]
    DIRECTION INPUT ;
    USE SIGNAL ;
    ANTENNAGATEAREA 0.852800 ;
    ANTENNADIFFAREA 8.061600 ;
    PORT
      LAYER Metal3 ;
        RECT 146.960 1179.160 147.360 1179.560 ;
    END
  END Tile_X0Y0_W2END[1]
  PIN Tile_X0Y0_W2END[2]
    DIRECTION INPUT ;
    USE SIGNAL ;
    ANTENNAGATEAREA 0.852800 ;
    ANTENNADIFFAREA 8.061600 ;
    PORT
      LAYER Metal3 ;
        RECT 146.960 1180.840 147.360 1181.240 ;
    END
  END Tile_X0Y0_W2END[2]
  PIN Tile_X0Y0_W2END[3]
    DIRECTION INPUT ;
    USE SIGNAL ;
    ANTENNAGATEAREA 0.852800 ;
    ANTENNADIFFAREA 8.061600 ;
    PORT
      LAYER Metal3 ;
        RECT 146.960 1182.520 147.360 1182.920 ;
    END
  END Tile_X0Y0_W2END[3]
  PIN Tile_X0Y0_W2END[4]
    DIRECTION INPUT ;
    USE SIGNAL ;
    ANTENNAGATEAREA 0.852800 ;
    ANTENNADIFFAREA 8.061600 ;
    PORT
      LAYER Metal3 ;
        RECT 146.960 1184.200 147.360 1184.600 ;
    END
  END Tile_X0Y0_W2END[4]
  PIN Tile_X0Y0_W2END[5]
    DIRECTION INPUT ;
    USE SIGNAL ;
    ANTENNAGATEAREA 0.852800 ;
    ANTENNADIFFAREA 8.061600 ;
    PORT
      LAYER Metal3 ;
        RECT 146.960 1185.880 147.360 1186.280 ;
    END
  END Tile_X0Y0_W2END[5]
  PIN Tile_X0Y0_W2END[6]
    DIRECTION INPUT ;
    USE SIGNAL ;
    ANTENNAGATEAREA 0.852800 ;
    ANTENNADIFFAREA 8.061600 ;
    PORT
      LAYER Metal3 ;
        RECT 146.960 1187.560 147.360 1187.960 ;
    END
  END Tile_X0Y0_W2END[6]
  PIN Tile_X0Y0_W2END[7]
    DIRECTION INPUT ;
    USE SIGNAL ;
    ANTENNAGATEAREA 0.852800 ;
    ANTENNADIFFAREA 8.061600 ;
    PORT
      LAYER Metal3 ;
        RECT 146.960 1189.240 147.360 1189.640 ;
    END
  END Tile_X0Y0_W2END[7]
  PIN Tile_X0Y0_W2MID[0]
    DIRECTION INPUT ;
    USE SIGNAL ;
    ANTENNAGATEAREA 0.852800 ;
    ANTENNADIFFAREA 8.061600 ;
    PORT
      LAYER Metal3 ;
        RECT 146.960 1164.040 147.360 1164.440 ;
    END
  END Tile_X0Y0_W2MID[0]
  PIN Tile_X0Y0_W2MID[1]
    DIRECTION INPUT ;
    USE SIGNAL ;
    ANTENNAGATEAREA 0.852800 ;
    ANTENNADIFFAREA 8.061600 ;
    PORT
      LAYER Metal3 ;
        RECT 146.960 1165.720 147.360 1166.120 ;
    END
  END Tile_X0Y0_W2MID[1]
  PIN Tile_X0Y0_W2MID[2]
    DIRECTION INPUT ;
    USE SIGNAL ;
    ANTENNAGATEAREA 0.852800 ;
    ANTENNADIFFAREA 8.061600 ;
    PORT
      LAYER Metal3 ;
        RECT 146.960 1167.400 147.360 1167.800 ;
    END
  END Tile_X0Y0_W2MID[2]
  PIN Tile_X0Y0_W2MID[3]
    DIRECTION INPUT ;
    USE SIGNAL ;
    ANTENNAGATEAREA 0.852800 ;
    ANTENNADIFFAREA 8.061600 ;
    PORT
      LAYER Metal3 ;
        RECT 146.960 1169.080 147.360 1169.480 ;
    END
  END Tile_X0Y0_W2MID[3]
  PIN Tile_X0Y0_W2MID[4]
    DIRECTION INPUT ;
    USE SIGNAL ;
    ANTENNAGATEAREA 0.852800 ;
    ANTENNADIFFAREA 8.061600 ;
    PORT
      LAYER Metal3 ;
        RECT 146.960 1170.760 147.360 1171.160 ;
    END
  END Tile_X0Y0_W2MID[4]
  PIN Tile_X0Y0_W2MID[5]
    DIRECTION INPUT ;
    USE SIGNAL ;
    ANTENNAGATEAREA 0.852800 ;
    ANTENNADIFFAREA 8.061600 ;
    PORT
      LAYER Metal3 ;
        RECT 146.960 1172.440 147.360 1172.840 ;
    END
  END Tile_X0Y0_W2MID[5]
  PIN Tile_X0Y0_W2MID[6]
    DIRECTION INPUT ;
    USE SIGNAL ;
    ANTENNAGATEAREA 0.852800 ;
    ANTENNADIFFAREA 8.061600 ;
    PORT
      LAYER Metal3 ;
        RECT 146.960 1174.120 147.360 1174.520 ;
    END
  END Tile_X0Y0_W2MID[6]
  PIN Tile_X0Y0_W2MID[7]
    DIRECTION INPUT ;
    USE SIGNAL ;
    ANTENNAGATEAREA 0.852800 ;
    ANTENNADIFFAREA 8.061600 ;
    PORT
      LAYER Metal3 ;
        RECT 146.960 1175.800 147.360 1176.200 ;
    END
  END Tile_X0Y0_W2MID[7]
  PIN Tile_X0Y0_W6END[0]
    DIRECTION INPUT ;
    USE SIGNAL ;
    ANTENNAGATEAREA 0.881400 ;
    ANTENNADIFFAREA 8.061600 ;
    PORT
      LAYER Metal3 ;
        RECT 146.960 1217.800 147.360 1218.200 ;
    END
  END Tile_X0Y0_W6END[0]
  PIN Tile_X0Y0_W6END[10]
    DIRECTION INPUT ;
    USE SIGNAL ;
    ANTENNAGATEAREA 0.852800 ;
    ANTENNADIFFAREA 8.061600 ;
    PORT
      LAYER Metal3 ;
        RECT 146.960 1234.600 147.360 1235.000 ;
    END
  END Tile_X0Y0_W6END[10]
  PIN Tile_X0Y0_W6END[11]
    DIRECTION INPUT ;
    USE SIGNAL ;
    ANTENNAGATEAREA 0.852800 ;
    ANTENNADIFFAREA 8.061600 ;
    PORT
      LAYER Metal3 ;
        RECT 146.960 1236.280 147.360 1236.680 ;
    END
  END Tile_X0Y0_W6END[11]
  PIN Tile_X0Y0_W6END[1]
    DIRECTION INPUT ;
    USE SIGNAL ;
    ANTENNAGATEAREA 0.881400 ;
    ANTENNADIFFAREA 8.061600 ;
    PORT
      LAYER Metal3 ;
        RECT 146.960 1219.480 147.360 1219.880 ;
    END
  END Tile_X0Y0_W6END[1]
  PIN Tile_X0Y0_W6END[2]
    DIRECTION INPUT ;
    USE SIGNAL ;
    ANTENNAGATEAREA 0.881400 ;
    ANTENNADIFFAREA 8.061600 ;
    PORT
      LAYER Metal3 ;
        RECT 146.960 1221.160 147.360 1221.560 ;
    END
  END Tile_X0Y0_W6END[2]
  PIN Tile_X0Y0_W6END[3]
    DIRECTION INPUT ;
    USE SIGNAL ;
    ANTENNAGATEAREA 0.881400 ;
    ANTENNADIFFAREA 8.061600 ;
    PORT
      LAYER Metal3 ;
        RECT 146.960 1222.840 147.360 1223.240 ;
    END
  END Tile_X0Y0_W6END[3]
  PIN Tile_X0Y0_W6END[4]
    DIRECTION INPUT ;
    USE SIGNAL ;
    ANTENNAGATEAREA 1.066000 ;
    ANTENNADIFFAREA 10.077000 ;
    PORT
      LAYER Metal3 ;
        RECT 146.960 1224.520 147.360 1224.920 ;
    END
  END Tile_X0Y0_W6END[4]
  PIN Tile_X0Y0_W6END[5]
    DIRECTION INPUT ;
    USE SIGNAL ;
    ANTENNAGATEAREA 1.066000 ;
    ANTENNADIFFAREA 10.077000 ;
    PORT
      LAYER Metal3 ;
        RECT 146.960 1226.200 147.360 1226.600 ;
    END
  END Tile_X0Y0_W6END[5]
  PIN Tile_X0Y0_W6END[6]
    DIRECTION INPUT ;
    USE SIGNAL ;
    ANTENNAGATEAREA 1.066000 ;
    ANTENNADIFFAREA 10.077000 ;
    PORT
      LAYER Metal3 ;
        RECT 146.960 1227.880 147.360 1228.280 ;
    END
  END Tile_X0Y0_W6END[6]
  PIN Tile_X0Y0_W6END[7]
    DIRECTION INPUT ;
    USE SIGNAL ;
    ANTENNAGATEAREA 1.066000 ;
    ANTENNADIFFAREA 10.077000 ;
    PORT
      LAYER Metal3 ;
        RECT 146.960 1229.560 147.360 1229.960 ;
    END
  END Tile_X0Y0_W6END[7]
  PIN Tile_X0Y0_W6END[8]
    DIRECTION INPUT ;
    USE SIGNAL ;
    ANTENNAGATEAREA 0.852800 ;
    ANTENNADIFFAREA 8.061600 ;
    PORT
      LAYER Metal3 ;
        RECT 146.960 1231.240 147.360 1231.640 ;
    END
  END Tile_X0Y0_W6END[8]
  PIN Tile_X0Y0_W6END[9]
    DIRECTION INPUT ;
    USE SIGNAL ;
    ANTENNAGATEAREA 0.852800 ;
    ANTENNADIFFAREA 8.061600 ;
    PORT
      LAYER Metal3 ;
        RECT 146.960 1232.920 147.360 1233.320 ;
    END
  END Tile_X0Y0_W6END[9]
  PIN Tile_X0Y0_WW4END[0]
    DIRECTION INPUT ;
    USE SIGNAL ;
    ANTENNAGATEAREA 0.852800 ;
    ANTENNADIFFAREA 8.061600 ;
    PORT
      LAYER Metal3 ;
        RECT 146.960 1190.920 147.360 1191.320 ;
    END
  END Tile_X0Y0_WW4END[0]
  PIN Tile_X0Y0_WW4END[10]
    DIRECTION INPUT ;
    USE SIGNAL ;
    ANTENNAGATEAREA 0.639600 ;
    ANTENNADIFFAREA 6.046200 ;
    PORT
      LAYER Metal3 ;
        RECT 146.960 1207.720 147.360 1208.120 ;
    END
  END Tile_X0Y0_WW4END[10]
  PIN Tile_X0Y0_WW4END[11]
    DIRECTION INPUT ;
    USE SIGNAL ;
    ANTENNAGATEAREA 0.639600 ;
    ANTENNADIFFAREA 6.046200 ;
    PORT
      LAYER Metal3 ;
        RECT 146.960 1209.400 147.360 1209.800 ;
    END
  END Tile_X0Y0_WW4END[11]
  PIN Tile_X0Y0_WW4END[12]
    DIRECTION INPUT ;
    USE SIGNAL ;
    ANTENNAGATEAREA 0.852800 ;
    ANTENNADIFFAREA 8.061600 ;
    PORT
      LAYER Metal3 ;
        RECT 146.960 1211.080 147.360 1211.480 ;
    END
  END Tile_X0Y0_WW4END[12]
  PIN Tile_X0Y0_WW4END[13]
    DIRECTION INPUT ;
    USE SIGNAL ;
    ANTENNAGATEAREA 0.852800 ;
    ANTENNADIFFAREA 8.061600 ;
    PORT
      LAYER Metal3 ;
        RECT 146.960 1212.760 147.360 1213.160 ;
    END
  END Tile_X0Y0_WW4END[13]
  PIN Tile_X0Y0_WW4END[14]
    DIRECTION INPUT ;
    USE SIGNAL ;
    ANTENNAGATEAREA 0.852800 ;
    ANTENNADIFFAREA 8.061600 ;
    PORT
      LAYER Metal3 ;
        RECT 146.960 1214.440 147.360 1214.840 ;
    END
  END Tile_X0Y0_WW4END[14]
  PIN Tile_X0Y0_WW4END[15]
    DIRECTION INPUT ;
    USE SIGNAL ;
    ANTENNAGATEAREA 0.852800 ;
    ANTENNADIFFAREA 8.061600 ;
    PORT
      LAYER Metal3 ;
        RECT 146.960 1216.120 147.360 1216.520 ;
    END
  END Tile_X0Y0_WW4END[15]
  PIN Tile_X0Y0_WW4END[1]
    DIRECTION INPUT ;
    USE SIGNAL ;
    ANTENNAGATEAREA 0.852800 ;
    ANTENNADIFFAREA 8.061600 ;
    PORT
      LAYER Metal3 ;
        RECT 146.960 1192.600 147.360 1193.000 ;
    END
  END Tile_X0Y0_WW4END[1]
  PIN Tile_X0Y0_WW4END[2]
    DIRECTION INPUT ;
    USE SIGNAL ;
    ANTENNAGATEAREA 0.852800 ;
    ANTENNADIFFAREA 8.061600 ;
    PORT
      LAYER Metal3 ;
        RECT 146.960 1194.280 147.360 1194.680 ;
    END
  END Tile_X0Y0_WW4END[2]
  PIN Tile_X0Y0_WW4END[3]
    DIRECTION INPUT ;
    USE SIGNAL ;
    ANTENNAGATEAREA 0.852800 ;
    ANTENNADIFFAREA 8.061600 ;
    PORT
      LAYER Metal3 ;
        RECT 146.960 1195.960 147.360 1196.360 ;
    END
  END Tile_X0Y0_WW4END[3]
  PIN Tile_X0Y0_WW4END[4]
    DIRECTION INPUT ;
    USE SIGNAL ;
    ANTENNAGATEAREA 0.639600 ;
    ANTENNADIFFAREA 6.046200 ;
    PORT
      LAYER Metal3 ;
        RECT 146.960 1197.640 147.360 1198.040 ;
    END
  END Tile_X0Y0_WW4END[4]
  PIN Tile_X0Y0_WW4END[5]
    DIRECTION INPUT ;
    USE SIGNAL ;
    ANTENNAGATEAREA 0.639600 ;
    ANTENNADIFFAREA 6.046200 ;
    PORT
      LAYER Metal3 ;
        RECT 146.960 1199.320 147.360 1199.720 ;
    END
  END Tile_X0Y0_WW4END[5]
  PIN Tile_X0Y0_WW4END[6]
    DIRECTION INPUT ;
    USE SIGNAL ;
    ANTENNAGATEAREA 0.639600 ;
    ANTENNADIFFAREA 6.046200 ;
    PORT
      LAYER Metal3 ;
        RECT 146.960 1201.000 147.360 1201.400 ;
    END
  END Tile_X0Y0_WW4END[6]
  PIN Tile_X0Y0_WW4END[7]
    DIRECTION INPUT ;
    USE SIGNAL ;
    ANTENNAGATEAREA 0.639600 ;
    ANTENNADIFFAREA 6.046200 ;
    PORT
      LAYER Metal3 ;
        RECT 146.960 1202.680 147.360 1203.080 ;
    END
  END Tile_X0Y0_WW4END[7]
  PIN Tile_X0Y0_WW4END[8]
    DIRECTION INPUT ;
    USE SIGNAL ;
    ANTENNAGATEAREA 0.639600 ;
    ANTENNADIFFAREA 6.046200 ;
    PORT
      LAYER Metal3 ;
        RECT 146.960 1204.360 147.360 1204.760 ;
    END
  END Tile_X0Y0_WW4END[8]
  PIN Tile_X0Y0_WW4END[9]
    DIRECTION INPUT ;
    USE SIGNAL ;
    ANTENNAGATEAREA 0.639600 ;
    ANTENNADIFFAREA 6.046200 ;
    PORT
      LAYER Metal3 ;
        RECT 146.960 1206.040 147.360 1206.440 ;
    END
  END Tile_X0Y0_WW4END[9]
  PIN Tile_X0Y1_E1BEG[0]
    DIRECTION OUTPUT ;
    USE SIGNAL ;
    ANTENNADIFFAREA 2.724000 ;
    PORT
      LAYER Metal3 ;
        RECT 146.960 862.900 147.360 863.300 ;
    END
  END Tile_X0Y1_E1BEG[0]
  PIN Tile_X0Y1_E1BEG[1]
    DIRECTION OUTPUT ;
    USE SIGNAL ;
    ANTENNADIFFAREA 2.724000 ;
    PORT
      LAYER Metal3 ;
        RECT 146.960 864.580 147.360 864.980 ;
    END
  END Tile_X0Y1_E1BEG[1]
  PIN Tile_X0Y1_E1BEG[2]
    DIRECTION OUTPUT ;
    USE SIGNAL ;
    ANTENNADIFFAREA 2.724000 ;
    PORT
      LAYER Metal3 ;
        RECT 146.960 866.260 147.360 866.660 ;
    END
  END Tile_X0Y1_E1BEG[2]
  PIN Tile_X0Y1_E1BEG[3]
    DIRECTION OUTPUT ;
    USE SIGNAL ;
    ANTENNADIFFAREA 2.724000 ;
    PORT
      LAYER Metal3 ;
        RECT 146.960 867.940 147.360 868.340 ;
    END
  END Tile_X0Y1_E1BEG[3]
  PIN Tile_X0Y1_E2BEG[0]
    DIRECTION OUTPUT ;
    USE SIGNAL ;
    ANTENNADIFFAREA 2.724000 ;
    PORT
      LAYER Metal3 ;
        RECT 146.960 872.140 147.360 872.540 ;
    END
  END Tile_X0Y1_E2BEG[0]
  PIN Tile_X0Y1_E2BEG[1]
    DIRECTION OUTPUT ;
    USE SIGNAL ;
    ANTENNADIFFAREA 2.724000 ;
    PORT
      LAYER Metal3 ;
        RECT 146.960 872.980 147.360 873.380 ;
    END
  END Tile_X0Y1_E2BEG[1]
  PIN Tile_X0Y1_E2BEG[2]
    DIRECTION OUTPUT ;
    USE SIGNAL ;
    ANTENNADIFFAREA 2.724000 ;
    PORT
      LAYER Metal3 ;
        RECT 146.960 873.820 147.360 874.220 ;
    END
  END Tile_X0Y1_E2BEG[2]
  PIN Tile_X0Y1_E2BEG[3]
    DIRECTION OUTPUT ;
    USE SIGNAL ;
    ANTENNADIFFAREA 2.724000 ;
    PORT
      LAYER Metal3 ;
        RECT 146.960 874.660 147.360 875.060 ;
    END
  END Tile_X0Y1_E2BEG[3]
  PIN Tile_X0Y1_E2BEG[4]
    DIRECTION OUTPUT ;
    USE SIGNAL ;
    ANTENNADIFFAREA 2.724000 ;
    PORT
      LAYER Metal3 ;
        RECT 146.960 875.500 147.360 875.900 ;
    END
  END Tile_X0Y1_E2BEG[4]
  PIN Tile_X0Y1_E2BEG[5]
    DIRECTION OUTPUT ;
    USE SIGNAL ;
    ANTENNADIFFAREA 2.724000 ;
    PORT
      LAYER Metal3 ;
        RECT 146.960 876.340 147.360 876.740 ;
    END
  END Tile_X0Y1_E2BEG[5]
  PIN Tile_X0Y1_E2BEG[6]
    DIRECTION OUTPUT ;
    USE SIGNAL ;
    ANTENNADIFFAREA 2.724000 ;
    PORT
      LAYER Metal3 ;
        RECT 146.960 877.180 147.360 877.580 ;
    END
  END Tile_X0Y1_E2BEG[6]
  PIN Tile_X0Y1_E2BEG[7]
    DIRECTION OUTPUT ;
    USE SIGNAL ;
    ANTENNADIFFAREA 2.724000 ;
    PORT
      LAYER Metal3 ;
        RECT 146.960 878.020 147.360 878.420 ;
    END
  END Tile_X0Y1_E2BEG[7]
  PIN Tile_X0Y1_E2BEGb[0]
    DIRECTION OUTPUT ;
    USE SIGNAL ;
    ANTENNADIFFAREA 2.724000 ;
    PORT
      LAYER Metal3 ;
        RECT 146.960 882.220 147.360 882.620 ;
    END
  END Tile_X0Y1_E2BEGb[0]
  PIN Tile_X0Y1_E2BEGb[1]
    DIRECTION OUTPUT ;
    USE SIGNAL ;
    ANTENNADIFFAREA 2.724000 ;
    PORT
      LAYER Metal3 ;
        RECT 146.960 883.900 147.360 884.300 ;
    END
  END Tile_X0Y1_E2BEGb[1]
  PIN Tile_X0Y1_E2BEGb[2]
    DIRECTION OUTPUT ;
    USE SIGNAL ;
    ANTENNADIFFAREA 2.724000 ;
    PORT
      LAYER Metal3 ;
        RECT 146.960 885.580 147.360 885.980 ;
    END
  END Tile_X0Y1_E2BEGb[2]
  PIN Tile_X0Y1_E2BEGb[3]
    DIRECTION OUTPUT ;
    USE SIGNAL ;
    ANTENNADIFFAREA 2.724000 ;
    PORT
      LAYER Metal3 ;
        RECT 146.960 887.260 147.360 887.660 ;
    END
  END Tile_X0Y1_E2BEGb[3]
  PIN Tile_X0Y1_E2BEGb[4]
    DIRECTION OUTPUT ;
    USE SIGNAL ;
    ANTENNADIFFAREA 2.724000 ;
    PORT
      LAYER Metal3 ;
        RECT 146.960 888.940 147.360 889.340 ;
    END
  END Tile_X0Y1_E2BEGb[4]
  PIN Tile_X0Y1_E2BEGb[5]
    DIRECTION OUTPUT ;
    USE SIGNAL ;
    ANTENNADIFFAREA 2.724000 ;
    PORT
      LAYER Metal3 ;
        RECT 146.960 890.620 147.360 891.020 ;
    END
  END Tile_X0Y1_E2BEGb[5]
  PIN Tile_X0Y1_E2BEGb[6]
    DIRECTION OUTPUT ;
    USE SIGNAL ;
    ANTENNADIFFAREA 2.724000 ;
    PORT
      LAYER Metal3 ;
        RECT 146.960 892.300 147.360 892.700 ;
    END
  END Tile_X0Y1_E2BEGb[6]
  PIN Tile_X0Y1_E2BEGb[7]
    DIRECTION OUTPUT ;
    USE SIGNAL ;
    ANTENNADIFFAREA 2.724000 ;
    PORT
      LAYER Metal3 ;
        RECT 146.960 893.980 147.360 894.380 ;
    END
  END Tile_X0Y1_E2BEGb[7]
  PIN Tile_X0Y1_E6BEG[0]
    DIRECTION OUTPUT ;
    USE SIGNAL ;
    ANTENNADIFFAREA 2.724000 ;
    PORT
      LAYER Metal3 ;
        RECT 146.960 921.700 147.360 922.100 ;
    END
  END Tile_X0Y1_E6BEG[0]
  PIN Tile_X0Y1_E6BEG[10]
    DIRECTION OUTPUT ;
    USE SIGNAL ;
    ANTENNADIFFAREA 2.724000 ;
    PORT
      LAYER Metal3 ;
        RECT 146.960 938.500 147.360 938.900 ;
    END
  END Tile_X0Y1_E6BEG[10]
  PIN Tile_X0Y1_E6BEG[11]
    DIRECTION OUTPUT ;
    USE SIGNAL ;
    ANTENNADIFFAREA 2.724000 ;
    PORT
      LAYER Metal3 ;
        RECT 146.960 940.180 147.360 940.580 ;
    END
  END Tile_X0Y1_E6BEG[11]
  PIN Tile_X0Y1_E6BEG[1]
    DIRECTION OUTPUT ;
    USE SIGNAL ;
    ANTENNADIFFAREA 2.724000 ;
    PORT
      LAYER Metal3 ;
        RECT 146.960 923.380 147.360 923.780 ;
    END
  END Tile_X0Y1_E6BEG[1]
  PIN Tile_X0Y1_E6BEG[2]
    DIRECTION OUTPUT ;
    USE SIGNAL ;
    ANTENNADIFFAREA 2.724000 ;
    PORT
      LAYER Metal3 ;
        RECT 146.960 925.060 147.360 925.460 ;
    END
  END Tile_X0Y1_E6BEG[2]
  PIN Tile_X0Y1_E6BEG[3]
    DIRECTION OUTPUT ;
    USE SIGNAL ;
    ANTENNADIFFAREA 2.724000 ;
    PORT
      LAYER Metal3 ;
        RECT 146.960 926.740 147.360 927.140 ;
    END
  END Tile_X0Y1_E6BEG[3]
  PIN Tile_X0Y1_E6BEG[4]
    DIRECTION OUTPUT ;
    USE SIGNAL ;
    ANTENNADIFFAREA 2.724000 ;
    PORT
      LAYER Metal3 ;
        RECT 146.960 928.420 147.360 928.820 ;
    END
  END Tile_X0Y1_E6BEG[4]
  PIN Tile_X0Y1_E6BEG[5]
    DIRECTION OUTPUT ;
    USE SIGNAL ;
    ANTENNADIFFAREA 2.724000 ;
    PORT
      LAYER Metal3 ;
        RECT 146.960 930.100 147.360 930.500 ;
    END
  END Tile_X0Y1_E6BEG[5]
  PIN Tile_X0Y1_E6BEG[6]
    DIRECTION OUTPUT ;
    USE SIGNAL ;
    ANTENNADIFFAREA 2.724000 ;
    PORT
      LAYER Metal3 ;
        RECT 146.960 931.780 147.360 932.180 ;
    END
  END Tile_X0Y1_E6BEG[6]
  PIN Tile_X0Y1_E6BEG[7]
    DIRECTION OUTPUT ;
    USE SIGNAL ;
    ANTENNADIFFAREA 2.724000 ;
    PORT
      LAYER Metal3 ;
        RECT 146.960 933.460 147.360 933.860 ;
    END
  END Tile_X0Y1_E6BEG[7]
  PIN Tile_X0Y1_E6BEG[8]
    DIRECTION OUTPUT ;
    USE SIGNAL ;
    ANTENNADIFFAREA 2.724000 ;
    PORT
      LAYER Metal3 ;
        RECT 146.960 935.140 147.360 935.540 ;
    END
  END Tile_X0Y1_E6BEG[8]
  PIN Tile_X0Y1_E6BEG[9]
    DIRECTION OUTPUT ;
    USE SIGNAL ;
    ANTENNADIFFAREA 2.724000 ;
    PORT
      LAYER Metal3 ;
        RECT 146.960 936.820 147.360 937.220 ;
    END
  END Tile_X0Y1_E6BEG[9]
  PIN Tile_X0Y1_EE4BEG[0]
    DIRECTION OUTPUT ;
    USE SIGNAL ;
    ANTENNADIFFAREA 2.724000 ;
    PORT
      LAYER Metal3 ;
        RECT 146.960 901.540 147.360 901.940 ;
    END
  END Tile_X0Y1_EE4BEG[0]
  PIN Tile_X0Y1_EE4BEG[10]
    DIRECTION OUTPUT ;
    USE SIGNAL ;
    ANTENNADIFFAREA 2.724000 ;
    PORT
      LAYER Metal3 ;
        RECT 146.960 909.940 147.360 910.340 ;
    END
  END Tile_X0Y1_EE4BEG[10]
  PIN Tile_X0Y1_EE4BEG[11]
    DIRECTION OUTPUT ;
    USE SIGNAL ;
    ANTENNADIFFAREA 2.724000 ;
    PORT
      LAYER Metal3 ;
        RECT 146.960 910.780 147.360 911.180 ;
    END
  END Tile_X0Y1_EE4BEG[11]
  PIN Tile_X0Y1_EE4BEG[12]
    DIRECTION OUTPUT ;
    USE SIGNAL ;
    ANTENNADIFFAREA 2.724000 ;
    PORT
      LAYER Metal3 ;
        RECT 146.960 911.620 147.360 912.020 ;
    END
  END Tile_X0Y1_EE4BEG[12]
  PIN Tile_X0Y1_EE4BEG[13]
    DIRECTION OUTPUT ;
    USE SIGNAL ;
    ANTENNADIFFAREA 2.724000 ;
    PORT
      LAYER Metal3 ;
        RECT 146.960 912.460 147.360 912.860 ;
    END
  END Tile_X0Y1_EE4BEG[13]
  PIN Tile_X0Y1_EE4BEG[14]
    DIRECTION OUTPUT ;
    USE SIGNAL ;
    ANTENNADIFFAREA 2.724000 ;
    PORT
      LAYER Metal3 ;
        RECT 146.960 913.300 147.360 913.700 ;
    END
  END Tile_X0Y1_EE4BEG[14]
  PIN Tile_X0Y1_EE4BEG[15]
    DIRECTION OUTPUT ;
    USE SIGNAL ;
    ANTENNADIFFAREA 2.724000 ;
    PORT
      LAYER Metal3 ;
        RECT 146.960 914.140 147.360 914.540 ;
    END
  END Tile_X0Y1_EE4BEG[15]
  PIN Tile_X0Y1_EE4BEG[1]
    DIRECTION OUTPUT ;
    USE SIGNAL ;
    ANTENNADIFFAREA 2.724000 ;
    PORT
      LAYER Metal3 ;
        RECT 146.960 902.380 147.360 902.780 ;
    END
  END Tile_X0Y1_EE4BEG[1]
  PIN Tile_X0Y1_EE4BEG[2]
    DIRECTION OUTPUT ;
    USE SIGNAL ;
    ANTENNADIFFAREA 2.724000 ;
    PORT
      LAYER Metal3 ;
        RECT 146.960 903.220 147.360 903.620 ;
    END
  END Tile_X0Y1_EE4BEG[2]
  PIN Tile_X0Y1_EE4BEG[3]
    DIRECTION OUTPUT ;
    USE SIGNAL ;
    ANTENNADIFFAREA 2.724000 ;
    PORT
      LAYER Metal3 ;
        RECT 146.960 904.060 147.360 904.460 ;
    END
  END Tile_X0Y1_EE4BEG[3]
  PIN Tile_X0Y1_EE4BEG[4]
    DIRECTION OUTPUT ;
    USE SIGNAL ;
    ANTENNADIFFAREA 2.724000 ;
    PORT
      LAYER Metal3 ;
        RECT 146.960 904.900 147.360 905.300 ;
    END
  END Tile_X0Y1_EE4BEG[4]
  PIN Tile_X0Y1_EE4BEG[5]
    DIRECTION OUTPUT ;
    USE SIGNAL ;
    ANTENNADIFFAREA 2.724000 ;
    PORT
      LAYER Metal3 ;
        RECT 146.960 905.740 147.360 906.140 ;
    END
  END Tile_X0Y1_EE4BEG[5]
  PIN Tile_X0Y1_EE4BEG[6]
    DIRECTION OUTPUT ;
    USE SIGNAL ;
    ANTENNADIFFAREA 2.724000 ;
    PORT
      LAYER Metal3 ;
        RECT 146.960 906.580 147.360 906.980 ;
    END
  END Tile_X0Y1_EE4BEG[6]
  PIN Tile_X0Y1_EE4BEG[7]
    DIRECTION OUTPUT ;
    USE SIGNAL ;
    ANTENNADIFFAREA 2.724000 ;
    PORT
      LAYER Metal3 ;
        RECT 146.960 907.420 147.360 907.820 ;
    END
  END Tile_X0Y1_EE4BEG[7]
  PIN Tile_X0Y1_EE4BEG[8]
    DIRECTION OUTPUT ;
    USE SIGNAL ;
    ANTENNADIFFAREA 2.724000 ;
    PORT
      LAYER Metal3 ;
        RECT 146.960 908.260 147.360 908.660 ;
    END
  END Tile_X0Y1_EE4BEG[8]
  PIN Tile_X0Y1_EE4BEG[9]
    DIRECTION OUTPUT ;
    USE SIGNAL ;
    ANTENNADIFFAREA 2.724000 ;
    PORT
      LAYER Metal3 ;
        RECT 146.960 909.100 147.360 909.500 ;
    END
  END Tile_X0Y1_EE4BEG[9]
  PIN Tile_X0Y1_FrameData[0]
    DIRECTION INPUT ;
    USE SIGNAL ;
    ANTENNAGATEAREA 1.626300 ;
    ANTENNADIFFAREA 18.138599 ;
    PORT
      LAYER Metal3 ;
        RECT 0.000 882.220 0.400 882.620 ;
    END
  END Tile_X0Y1_FrameData[0]
  PIN Tile_X0Y1_FrameData[10]
    DIRECTION INPUT ;
    USE SIGNAL ;
    ANTENNAGATEAREA 1.626300 ;
    ANTENNADIFFAREA 18.138599 ;
    PORT
      LAYER Metal3 ;
        RECT 0.000 941.020 0.400 941.420 ;
    END
  END Tile_X0Y1_FrameData[10]
  PIN Tile_X0Y1_FrameData[11]
    DIRECTION INPUT ;
    USE SIGNAL ;
    ANTENNAGATEAREA 1.626300 ;
    ANTENNADIFFAREA 18.138599 ;
    PORT
      LAYER Metal3 ;
        RECT 0.000 946.900 0.400 947.300 ;
    END
  END Tile_X0Y1_FrameData[11]
  PIN Tile_X0Y1_FrameData[12]
    DIRECTION INPUT ;
    USE SIGNAL ;
    ANTENNAGATEAREA 1.626300 ;
    ANTENNADIFFAREA 18.138599 ;
    PORT
      LAYER Metal3 ;
        RECT 0.000 952.780 0.400 953.180 ;
    END
  END Tile_X0Y1_FrameData[12]
  PIN Tile_X0Y1_FrameData[13]
    DIRECTION INPUT ;
    USE SIGNAL ;
    ANTENNAGATEAREA 1.626300 ;
    ANTENNADIFFAREA 18.138599 ;
    PORT
      LAYER Metal3 ;
        RECT 0.000 958.660 0.400 959.060 ;
    END
  END Tile_X0Y1_FrameData[13]
  PIN Tile_X0Y1_FrameData[14]
    DIRECTION INPUT ;
    USE SIGNAL ;
    ANTENNAGATEAREA 1.626300 ;
    ANTENNADIFFAREA 18.138599 ;
    PORT
      LAYER Metal3 ;
        RECT 0.000 964.540 0.400 964.940 ;
    END
  END Tile_X0Y1_FrameData[14]
  PIN Tile_X0Y1_FrameData[15]
    DIRECTION INPUT ;
    USE SIGNAL ;
    ANTENNAGATEAREA 1.626300 ;
    ANTENNADIFFAREA 18.138599 ;
    PORT
      LAYER Metal3 ;
        RECT 0.000 970.420 0.400 970.820 ;
    END
  END Tile_X0Y1_FrameData[15]
  PIN Tile_X0Y1_FrameData[16]
    DIRECTION INPUT ;
    USE SIGNAL ;
    ANTENNAGATEAREA 1.807000 ;
    ANTENNADIFFAREA 20.153999 ;
    PORT
      LAYER Metal3 ;
        RECT 0.000 976.300 0.400 976.700 ;
    END
  END Tile_X0Y1_FrameData[16]
  PIN Tile_X0Y1_FrameData[17]
    DIRECTION INPUT ;
    USE SIGNAL ;
    ANTENNAGATEAREA 1.807000 ;
    ANTENNADIFFAREA 20.153999 ;
    PORT
      LAYER Metal3 ;
        RECT 0.000 982.180 0.400 982.580 ;
    END
  END Tile_X0Y1_FrameData[17]
  PIN Tile_X0Y1_FrameData[18]
    DIRECTION INPUT ;
    USE SIGNAL ;
    ANTENNAGATEAREA 1.807000 ;
    ANTENNADIFFAREA 20.153999 ;
    PORT
      LAYER Metal3 ;
        RECT 0.000 988.060 0.400 988.460 ;
    END
  END Tile_X0Y1_FrameData[18]
  PIN Tile_X0Y1_FrameData[19]
    DIRECTION INPUT ;
    USE SIGNAL ;
    ANTENNAGATEAREA 1.807000 ;
    ANTENNADIFFAREA 20.153999 ;
    PORT
      LAYER Metal3 ;
        RECT 0.000 993.940 0.400 994.340 ;
    END
  END Tile_X0Y1_FrameData[19]
  PIN Tile_X0Y1_FrameData[1]
    DIRECTION INPUT ;
    USE SIGNAL ;
    ANTENNAGATEAREA 1.626300 ;
    ANTENNADIFFAREA 18.138599 ;
    PORT
      LAYER Metal3 ;
        RECT 0.000 888.100 0.400 888.500 ;
    END
  END Tile_X0Y1_FrameData[1]
  PIN Tile_X0Y1_FrameData[20]
    DIRECTION INPUT ;
    USE SIGNAL ;
    ANTENNAGATEAREA 1.807000 ;
    ANTENNADIFFAREA 20.153999 ;
    PORT
      LAYER Metal3 ;
        RECT 0.000 999.820 0.400 1000.220 ;
    END
  END Tile_X0Y1_FrameData[20]
  PIN Tile_X0Y1_FrameData[21]
    DIRECTION INPUT ;
    USE SIGNAL ;
    ANTENNAGATEAREA 1.807000 ;
    ANTENNADIFFAREA 20.153999 ;
    PORT
      LAYER Metal3 ;
        RECT 0.000 1005.700 0.400 1006.100 ;
    END
  END Tile_X0Y1_FrameData[21]
  PIN Tile_X0Y1_FrameData[22]
    DIRECTION INPUT ;
    USE SIGNAL ;
    ANTENNAGATEAREA 1.807000 ;
    ANTENNADIFFAREA 20.153999 ;
    PORT
      LAYER Metal3 ;
        RECT 0.000 1011.580 0.400 1011.980 ;
    END
  END Tile_X0Y1_FrameData[22]
  PIN Tile_X0Y1_FrameData[23]
    DIRECTION INPUT ;
    USE SIGNAL ;
    ANTENNAGATEAREA 1.807000 ;
    ANTENNADIFFAREA 20.153999 ;
    PORT
      LAYER Metal3 ;
        RECT 0.000 1017.460 0.400 1017.860 ;
    END
  END Tile_X0Y1_FrameData[23]
  PIN Tile_X0Y1_FrameData[24]
    DIRECTION INPUT ;
    USE SIGNAL ;
    ANTENNAGATEAREA 1.807000 ;
    ANTENNADIFFAREA 20.153999 ;
    PORT
      LAYER Metal3 ;
        RECT 0.000 1023.340 0.400 1023.740 ;
    END
  END Tile_X0Y1_FrameData[24]
  PIN Tile_X0Y1_FrameData[25]
    DIRECTION INPUT ;
    USE SIGNAL ;
    ANTENNAGATEAREA 1.807000 ;
    ANTENNADIFFAREA 20.153999 ;
    PORT
      LAYER Metal3 ;
        RECT 0.000 1029.220 0.400 1029.620 ;
    END
  END Tile_X0Y1_FrameData[25]
  PIN Tile_X0Y1_FrameData[26]
    DIRECTION INPUT ;
    USE SIGNAL ;
    ANTENNAGATEAREA 1.807000 ;
    ANTENNADIFFAREA 20.153999 ;
    PORT
      LAYER Metal3 ;
        RECT 0.000 1035.100 0.400 1035.500 ;
    END
  END Tile_X0Y1_FrameData[26]
  PIN Tile_X0Y1_FrameData[27]
    DIRECTION INPUT ;
    USE SIGNAL ;
    ANTENNAGATEAREA 1.807000 ;
    ANTENNADIFFAREA 20.153999 ;
    PORT
      LAYER Metal3 ;
        RECT 0.000 1040.980 0.400 1041.380 ;
    END
  END Tile_X0Y1_FrameData[27]
  PIN Tile_X0Y1_FrameData[28]
    DIRECTION INPUT ;
    USE SIGNAL ;
    ANTENNAGATEAREA 1.807000 ;
    ANTENNADIFFAREA 20.153999 ;
    PORT
      LAYER Metal3 ;
        RECT 0.000 1046.860 0.400 1047.260 ;
    END
  END Tile_X0Y1_FrameData[28]
  PIN Tile_X0Y1_FrameData[29]
    DIRECTION INPUT ;
    USE SIGNAL ;
    ANTENNAGATEAREA 1.807000 ;
    ANTENNADIFFAREA 20.153999 ;
    PORT
      LAYER Metal3 ;
        RECT 0.000 1052.740 0.400 1053.140 ;
    END
  END Tile_X0Y1_FrameData[29]
  PIN Tile_X0Y1_FrameData[2]
    DIRECTION INPUT ;
    USE SIGNAL ;
    ANTENNAGATEAREA 1.626300 ;
    ANTENNADIFFAREA 18.138599 ;
    PORT
      LAYER Metal3 ;
        RECT 0.000 893.980 0.400 894.380 ;
    END
  END Tile_X0Y1_FrameData[2]
  PIN Tile_X0Y1_FrameData[30]
    DIRECTION INPUT ;
    USE SIGNAL ;
    ANTENNAGATEAREA 1.807000 ;
    ANTENNADIFFAREA 20.153999 ;
    PORT
      LAYER Metal3 ;
        RECT 0.000 1058.620 0.400 1059.020 ;
    END
  END Tile_X0Y1_FrameData[30]
  PIN Tile_X0Y1_FrameData[31]
    DIRECTION INPUT ;
    USE SIGNAL ;
    ANTENNAGATEAREA 1.807000 ;
    ANTENNADIFFAREA 20.153999 ;
    PORT
      LAYER Metal3 ;
        RECT 0.000 1064.500 0.400 1064.900 ;
    END
  END Tile_X0Y1_FrameData[31]
  PIN Tile_X0Y1_FrameData[3]
    DIRECTION INPUT ;
    USE SIGNAL ;
    ANTENNAGATEAREA 1.626300 ;
    ANTENNADIFFAREA 18.138599 ;
    PORT
      LAYER Metal3 ;
        RECT 0.000 899.860 0.400 900.260 ;
    END
  END Tile_X0Y1_FrameData[3]
  PIN Tile_X0Y1_FrameData[4]
    DIRECTION INPUT ;
    USE SIGNAL ;
    ANTENNAGATEAREA 1.626300 ;
    ANTENNADIFFAREA 18.138599 ;
    PORT
      LAYER Metal3 ;
        RECT 0.000 905.740 0.400 906.140 ;
    END
  END Tile_X0Y1_FrameData[4]
  PIN Tile_X0Y1_FrameData[5]
    DIRECTION INPUT ;
    USE SIGNAL ;
    ANTENNAGATEAREA 1.626300 ;
    ANTENNADIFFAREA 18.138599 ;
    PORT
      LAYER Metal3 ;
        RECT 0.000 911.620 0.400 912.020 ;
    END
  END Tile_X0Y1_FrameData[5]
  PIN Tile_X0Y1_FrameData[6]
    DIRECTION INPUT ;
    USE SIGNAL ;
    ANTENNAGATEAREA 1.626300 ;
    ANTENNADIFFAREA 18.138599 ;
    PORT
      LAYER Metal3 ;
        RECT 0.000 917.500 0.400 917.900 ;
    END
  END Tile_X0Y1_FrameData[6]
  PIN Tile_X0Y1_FrameData[7]
    DIRECTION INPUT ;
    USE SIGNAL ;
    ANTENNAGATEAREA 1.626300 ;
    ANTENNADIFFAREA 18.138599 ;
    PORT
      LAYER Metal3 ;
        RECT 0.000 923.380 0.400 923.780 ;
    END
  END Tile_X0Y1_FrameData[7]
  PIN Tile_X0Y1_FrameData[8]
    DIRECTION INPUT ;
    USE SIGNAL ;
    ANTENNAGATEAREA 1.626300 ;
    ANTENNADIFFAREA 18.138599 ;
    PORT
      LAYER Metal3 ;
        RECT 0.000 929.260 0.400 929.660 ;
    END
  END Tile_X0Y1_FrameData[8]
  PIN Tile_X0Y1_FrameData[9]
    DIRECTION INPUT ;
    USE SIGNAL ;
    ANTENNAGATEAREA 1.626300 ;
    ANTENNADIFFAREA 18.138599 ;
    PORT
      LAYER Metal3 ;
        RECT 0.000 935.140 0.400 935.540 ;
    END
  END Tile_X0Y1_FrameData[9]
  PIN Tile_X0Y1_FrameData_O[0]
    DIRECTION OUTPUT ;
    USE SIGNAL ;
    ANTENNADIFFAREA 2.724000 ;
    PORT
      LAYER Metal3 ;
        RECT 146.960 1024.180 147.360 1024.580 ;
    END
  END Tile_X0Y1_FrameData_O[0]
  PIN Tile_X0Y1_FrameData_O[10]
    DIRECTION OUTPUT ;
    USE SIGNAL ;
    ANTENNADIFFAREA 2.724000 ;
    PORT
      LAYER Metal3 ;
        RECT 146.960 1040.980 147.360 1041.380 ;
    END
  END Tile_X0Y1_FrameData_O[10]
  PIN Tile_X0Y1_FrameData_O[11]
    DIRECTION OUTPUT ;
    USE SIGNAL ;
    ANTENNADIFFAREA 2.724000 ;
    PORT
      LAYER Metal3 ;
        RECT 146.960 1042.660 147.360 1043.060 ;
    END
  END Tile_X0Y1_FrameData_O[11]
  PIN Tile_X0Y1_FrameData_O[12]
    DIRECTION OUTPUT ;
    USE SIGNAL ;
    ANTENNADIFFAREA 2.724000 ;
    PORT
      LAYER Metal3 ;
        RECT 146.960 1044.340 147.360 1044.740 ;
    END
  END Tile_X0Y1_FrameData_O[12]
  PIN Tile_X0Y1_FrameData_O[13]
    DIRECTION OUTPUT ;
    USE SIGNAL ;
    ANTENNADIFFAREA 2.724000 ;
    PORT
      LAYER Metal3 ;
        RECT 146.960 1046.020 147.360 1046.420 ;
    END
  END Tile_X0Y1_FrameData_O[13]
  PIN Tile_X0Y1_FrameData_O[14]
    DIRECTION OUTPUT ;
    USE SIGNAL ;
    ANTENNADIFFAREA 2.724000 ;
    PORT
      LAYER Metal3 ;
        RECT 146.960 1047.700 147.360 1048.100 ;
    END
  END Tile_X0Y1_FrameData_O[14]
  PIN Tile_X0Y1_FrameData_O[15]
    DIRECTION OUTPUT ;
    USE SIGNAL ;
    ANTENNADIFFAREA 2.724000 ;
    PORT
      LAYER Metal3 ;
        RECT 146.960 1049.380 147.360 1049.780 ;
    END
  END Tile_X0Y1_FrameData_O[15]
  PIN Tile_X0Y1_FrameData_O[16]
    DIRECTION OUTPUT ;
    USE SIGNAL ;
    ANTENNADIFFAREA 2.724000 ;
    PORT
      LAYER Metal3 ;
        RECT 146.960 1051.060 147.360 1051.460 ;
    END
  END Tile_X0Y1_FrameData_O[16]
  PIN Tile_X0Y1_FrameData_O[17]
    DIRECTION OUTPUT ;
    USE SIGNAL ;
    ANTENNADIFFAREA 2.724000 ;
    PORT
      LAYER Metal3 ;
        RECT 146.960 1052.740 147.360 1053.140 ;
    END
  END Tile_X0Y1_FrameData_O[17]
  PIN Tile_X0Y1_FrameData_O[18]
    DIRECTION OUTPUT ;
    USE SIGNAL ;
    ANTENNADIFFAREA 2.724000 ;
    PORT
      LAYER Metal3 ;
        RECT 146.960 1054.420 147.360 1054.820 ;
    END
  END Tile_X0Y1_FrameData_O[18]
  PIN Tile_X0Y1_FrameData_O[19]
    DIRECTION OUTPUT ;
    USE SIGNAL ;
    ANTENNADIFFAREA 2.724000 ;
    PORT
      LAYER Metal3 ;
        RECT 146.960 1056.100 147.360 1056.500 ;
    END
  END Tile_X0Y1_FrameData_O[19]
  PIN Tile_X0Y1_FrameData_O[1]
    DIRECTION OUTPUT ;
    USE SIGNAL ;
    ANTENNADIFFAREA 2.724000 ;
    PORT
      LAYER Metal3 ;
        RECT 146.960 1025.860 147.360 1026.260 ;
    END
  END Tile_X0Y1_FrameData_O[1]
  PIN Tile_X0Y1_FrameData_O[20]
    DIRECTION OUTPUT ;
    USE SIGNAL ;
    ANTENNADIFFAREA 2.724000 ;
    PORT
      LAYER Metal3 ;
        RECT 146.960 1057.780 147.360 1058.180 ;
    END
  END Tile_X0Y1_FrameData_O[20]
  PIN Tile_X0Y1_FrameData_O[21]
    DIRECTION OUTPUT ;
    USE SIGNAL ;
    ANTENNADIFFAREA 2.724000 ;
    PORT
      LAYER Metal3 ;
        RECT 146.960 1059.460 147.360 1059.860 ;
    END
  END Tile_X0Y1_FrameData_O[21]
  PIN Tile_X0Y1_FrameData_O[22]
    DIRECTION OUTPUT ;
    USE SIGNAL ;
    ANTENNADIFFAREA 2.724000 ;
    PORT
      LAYER Metal3 ;
        RECT 146.960 1061.140 147.360 1061.540 ;
    END
  END Tile_X0Y1_FrameData_O[22]
  PIN Tile_X0Y1_FrameData_O[23]
    DIRECTION OUTPUT ;
    USE SIGNAL ;
    ANTENNADIFFAREA 2.724000 ;
    PORT
      LAYER Metal3 ;
        RECT 146.960 1062.820 147.360 1063.220 ;
    END
  END Tile_X0Y1_FrameData_O[23]
  PIN Tile_X0Y1_FrameData_O[24]
    DIRECTION OUTPUT ;
    USE SIGNAL ;
    ANTENNADIFFAREA 2.724000 ;
    PORT
      LAYER Metal3 ;
        RECT 146.960 1064.500 147.360 1064.900 ;
    END
  END Tile_X0Y1_FrameData_O[24]
  PIN Tile_X0Y1_FrameData_O[25]
    DIRECTION OUTPUT ;
    USE SIGNAL ;
    ANTENNADIFFAREA 2.724000 ;
    PORT
      LAYER Metal3 ;
        RECT 146.960 1066.180 147.360 1066.580 ;
    END
  END Tile_X0Y1_FrameData_O[25]
  PIN Tile_X0Y1_FrameData_O[26]
    DIRECTION OUTPUT ;
    USE SIGNAL ;
    ANTENNADIFFAREA 2.724000 ;
    PORT
      LAYER Metal3 ;
        RECT 146.960 1067.860 147.360 1068.260 ;
    END
  END Tile_X0Y1_FrameData_O[26]
  PIN Tile_X0Y1_FrameData_O[27]
    DIRECTION OUTPUT ;
    USE SIGNAL ;
    ANTENNADIFFAREA 2.724000 ;
    PORT
      LAYER Metal3 ;
        RECT 146.960 1069.540 147.360 1069.940 ;
    END
  END Tile_X0Y1_FrameData_O[27]
  PIN Tile_X0Y1_FrameData_O[28]
    DIRECTION OUTPUT ;
    USE SIGNAL ;
    ANTENNADIFFAREA 2.724000 ;
    PORT
      LAYER Metal3 ;
        RECT 146.960 1071.220 147.360 1071.620 ;
    END
  END Tile_X0Y1_FrameData_O[28]
  PIN Tile_X0Y1_FrameData_O[29]
    DIRECTION OUTPUT ;
    USE SIGNAL ;
    ANTENNADIFFAREA 2.724000 ;
    PORT
      LAYER Metal3 ;
        RECT 146.960 1072.900 147.360 1073.300 ;
    END
  END Tile_X0Y1_FrameData_O[29]
  PIN Tile_X0Y1_FrameData_O[2]
    DIRECTION OUTPUT ;
    USE SIGNAL ;
    ANTENNADIFFAREA 2.724000 ;
    PORT
      LAYER Metal3 ;
        RECT 146.960 1027.540 147.360 1027.940 ;
    END
  END Tile_X0Y1_FrameData_O[2]
  PIN Tile_X0Y1_FrameData_O[30]
    DIRECTION OUTPUT ;
    USE SIGNAL ;
    ANTENNADIFFAREA 2.724000 ;
    PORT
      LAYER Metal3 ;
        RECT 146.960 1074.580 147.360 1074.980 ;
    END
  END Tile_X0Y1_FrameData_O[30]
  PIN Tile_X0Y1_FrameData_O[31]
    DIRECTION OUTPUT ;
    USE SIGNAL ;
    ANTENNADIFFAREA 2.724000 ;
    PORT
      LAYER Metal3 ;
        RECT 146.960 1076.260 147.360 1076.660 ;
    END
  END Tile_X0Y1_FrameData_O[31]
  PIN Tile_X0Y1_FrameData_O[3]
    DIRECTION OUTPUT ;
    USE SIGNAL ;
    ANTENNADIFFAREA 2.724000 ;
    PORT
      LAYER Metal3 ;
        RECT 146.960 1029.220 147.360 1029.620 ;
    END
  END Tile_X0Y1_FrameData_O[3]
  PIN Tile_X0Y1_FrameData_O[4]
    DIRECTION OUTPUT ;
    USE SIGNAL ;
    ANTENNADIFFAREA 2.724000 ;
    PORT
      LAYER Metal3 ;
        RECT 146.960 1030.900 147.360 1031.300 ;
    END
  END Tile_X0Y1_FrameData_O[4]
  PIN Tile_X0Y1_FrameData_O[5]
    DIRECTION OUTPUT ;
    USE SIGNAL ;
    ANTENNADIFFAREA 2.724000 ;
    PORT
      LAYER Metal3 ;
        RECT 146.960 1032.580 147.360 1032.980 ;
    END
  END Tile_X0Y1_FrameData_O[5]
  PIN Tile_X0Y1_FrameData_O[6]
    DIRECTION OUTPUT ;
    USE SIGNAL ;
    ANTENNADIFFAREA 2.724000 ;
    PORT
      LAYER Metal3 ;
        RECT 146.960 1034.260 147.360 1034.660 ;
    END
  END Tile_X0Y1_FrameData_O[6]
  PIN Tile_X0Y1_FrameData_O[7]
    DIRECTION OUTPUT ;
    USE SIGNAL ;
    ANTENNADIFFAREA 2.724000 ;
    PORT
      LAYER Metal3 ;
        RECT 146.960 1035.940 147.360 1036.340 ;
    END
  END Tile_X0Y1_FrameData_O[7]
  PIN Tile_X0Y1_FrameData_O[8]
    DIRECTION OUTPUT ;
    USE SIGNAL ;
    ANTENNADIFFAREA 2.724000 ;
    PORT
      LAYER Metal3 ;
        RECT 146.960 1037.620 147.360 1038.020 ;
    END
  END Tile_X0Y1_FrameData_O[8]
  PIN Tile_X0Y1_FrameData_O[9]
    DIRECTION OUTPUT ;
    USE SIGNAL ;
    ANTENNADIFFAREA 2.724000 ;
    PORT
      LAYER Metal3 ;
        RECT 146.960 1039.300 147.360 1039.700 ;
    END
  END Tile_X0Y1_FrameData_O[9]
  PIN Tile_X0Y1_UserCLK
    DIRECTION INPUT ;
    USE SIGNAL ;
    ANTENNAGATEAREA 0.180700 ;
    ANTENNADIFFAREA 2.015400 ;
    PORT
      LAYER Metal3 ;
        RECT 0.000 865.420 0.400 865.820 ;
    END
  END Tile_X0Y1_UserCLK
  PIN Tile_X0Y1_UserCLKo
    DIRECTION OUTPUT ;
    USE SIGNAL ;
    ANTENNADIFFAREA 2.724000 ;
    PORT
      LAYER Metal3 ;
        RECT 146.960 1022.500 147.360 1022.900 ;
    END
  END Tile_X0Y1_UserCLKo
  PIN Tile_X0Y1_W1END[0]
    DIRECTION INPUT ;
    USE SIGNAL ;
    ANTENNAGATEAREA 1.279200 ;
    ANTENNADIFFAREA 12.092400 ;
    PORT
      LAYER Metal3 ;
        RECT 146.960 941.860 147.360 942.260 ;
    END
  END Tile_X0Y1_W1END[0]
  PIN Tile_X0Y1_W1END[1]
    DIRECTION INPUT ;
    USE SIGNAL ;
    ANTENNAGATEAREA 1.279200 ;
    ANTENNADIFFAREA 12.092400 ;
    PORT
      LAYER Metal3 ;
        RECT 146.960 943.540 147.360 943.940 ;
    END
  END Tile_X0Y1_W1END[1]
  PIN Tile_X0Y1_W1END[2]
    DIRECTION INPUT ;
    USE SIGNAL ;
    ANTENNAGATEAREA 1.279200 ;
    ANTENNADIFFAREA 12.092400 ;
    PORT
      LAYER Metal3 ;
        RECT 146.960 945.220 147.360 945.620 ;
    END
  END Tile_X0Y1_W1END[2]
  PIN Tile_X0Y1_W1END[3]
    DIRECTION INPUT ;
    USE SIGNAL ;
    ANTENNAGATEAREA 1.279200 ;
    ANTENNADIFFAREA 12.092400 ;
    PORT
      LAYER Metal3 ;
        RECT 146.960 946.900 147.360 947.300 ;
    END
  END Tile_X0Y1_W1END[3]
  PIN Tile_X0Y1_W2END[0]
    DIRECTION INPUT ;
    USE SIGNAL ;
    ANTENNAGATEAREA 0.852800 ;
    ANTENNADIFFAREA 8.061600 ;
    PORT
      LAYER Metal3 ;
        RECT 146.960 962.020 147.360 962.420 ;
    END
  END Tile_X0Y1_W2END[0]
  PIN Tile_X0Y1_W2END[1]
    DIRECTION INPUT ;
    USE SIGNAL ;
    ANTENNAGATEAREA 0.852800 ;
    ANTENNADIFFAREA 8.061600 ;
    PORT
      LAYER Metal3 ;
        RECT 146.960 963.700 147.360 964.100 ;
    END
  END Tile_X0Y1_W2END[1]
  PIN Tile_X0Y1_W2END[2]
    DIRECTION INPUT ;
    USE SIGNAL ;
    ANTENNAGATEAREA 0.852800 ;
    ANTENNADIFFAREA 8.061600 ;
    PORT
      LAYER Metal3 ;
        RECT 146.960 965.380 147.360 965.780 ;
    END
  END Tile_X0Y1_W2END[2]
  PIN Tile_X0Y1_W2END[3]
    DIRECTION INPUT ;
    USE SIGNAL ;
    ANTENNAGATEAREA 0.852800 ;
    ANTENNADIFFAREA 8.061600 ;
    PORT
      LAYER Metal3 ;
        RECT 146.960 967.060 147.360 967.460 ;
    END
  END Tile_X0Y1_W2END[3]
  PIN Tile_X0Y1_W2END[4]
    DIRECTION INPUT ;
    USE SIGNAL ;
    ANTENNAGATEAREA 0.852800 ;
    ANTENNADIFFAREA 8.061600 ;
    PORT
      LAYER Metal3 ;
        RECT 146.960 968.740 147.360 969.140 ;
    END
  END Tile_X0Y1_W2END[4]
  PIN Tile_X0Y1_W2END[5]
    DIRECTION INPUT ;
    USE SIGNAL ;
    ANTENNAGATEAREA 0.852800 ;
    ANTENNADIFFAREA 8.061600 ;
    PORT
      LAYER Metal3 ;
        RECT 146.960 970.420 147.360 970.820 ;
    END
  END Tile_X0Y1_W2END[5]
  PIN Tile_X0Y1_W2END[6]
    DIRECTION INPUT ;
    USE SIGNAL ;
    ANTENNAGATEAREA 0.852800 ;
    ANTENNADIFFAREA 8.061600 ;
    PORT
      LAYER Metal3 ;
        RECT 146.960 972.100 147.360 972.500 ;
    END
  END Tile_X0Y1_W2END[6]
  PIN Tile_X0Y1_W2END[7]
    DIRECTION INPUT ;
    USE SIGNAL ;
    ANTENNAGATEAREA 0.852800 ;
    ANTENNADIFFAREA 8.061600 ;
    PORT
      LAYER Metal3 ;
        RECT 146.960 973.780 147.360 974.180 ;
    END
  END Tile_X0Y1_W2END[7]
  PIN Tile_X0Y1_W2MID[0]
    DIRECTION INPUT ;
    USE SIGNAL ;
    ANTENNAGATEAREA 0.852800 ;
    ANTENNADIFFAREA 8.061600 ;
    PORT
      LAYER Metal3 ;
        RECT 146.960 948.580 147.360 948.980 ;
    END
  END Tile_X0Y1_W2MID[0]
  PIN Tile_X0Y1_W2MID[1]
    DIRECTION INPUT ;
    USE SIGNAL ;
    ANTENNAGATEAREA 0.852800 ;
    ANTENNADIFFAREA 8.061600 ;
    PORT
      LAYER Metal3 ;
        RECT 146.960 950.260 147.360 950.660 ;
    END
  END Tile_X0Y1_W2MID[1]
  PIN Tile_X0Y1_W2MID[2]
    DIRECTION INPUT ;
    USE SIGNAL ;
    ANTENNAGATEAREA 0.852800 ;
    ANTENNADIFFAREA 8.061600 ;
    PORT
      LAYER Metal3 ;
        RECT 146.960 951.940 147.360 952.340 ;
    END
  END Tile_X0Y1_W2MID[2]
  PIN Tile_X0Y1_W2MID[3]
    DIRECTION INPUT ;
    USE SIGNAL ;
    ANTENNAGATEAREA 0.852800 ;
    ANTENNADIFFAREA 8.061600 ;
    PORT
      LAYER Metal3 ;
        RECT 146.960 953.620 147.360 954.020 ;
    END
  END Tile_X0Y1_W2MID[3]
  PIN Tile_X0Y1_W2MID[4]
    DIRECTION INPUT ;
    USE SIGNAL ;
    ANTENNAGATEAREA 0.852800 ;
    ANTENNADIFFAREA 8.061600 ;
    PORT
      LAYER Metal3 ;
        RECT 146.960 955.300 147.360 955.700 ;
    END
  END Tile_X0Y1_W2MID[4]
  PIN Tile_X0Y1_W2MID[5]
    DIRECTION INPUT ;
    USE SIGNAL ;
    ANTENNAGATEAREA 0.852800 ;
    ANTENNADIFFAREA 8.061600 ;
    PORT
      LAYER Metal3 ;
        RECT 146.960 956.980 147.360 957.380 ;
    END
  END Tile_X0Y1_W2MID[5]
  PIN Tile_X0Y1_W2MID[6]
    DIRECTION INPUT ;
    USE SIGNAL ;
    ANTENNAGATEAREA 0.852800 ;
    ANTENNADIFFAREA 8.061600 ;
    PORT
      LAYER Metal3 ;
        RECT 146.960 958.660 147.360 959.060 ;
    END
  END Tile_X0Y1_W2MID[6]
  PIN Tile_X0Y1_W2MID[7]
    DIRECTION INPUT ;
    USE SIGNAL ;
    ANTENNAGATEAREA 0.852800 ;
    ANTENNADIFFAREA 8.061600 ;
    PORT
      LAYER Metal3 ;
        RECT 146.960 960.340 147.360 960.740 ;
    END
  END Tile_X0Y1_W2MID[7]
  PIN Tile_X0Y1_W6END[0]
    DIRECTION INPUT ;
    USE SIGNAL ;
    ANTENNAGATEAREA 0.881400 ;
    ANTENNADIFFAREA 8.061600 ;
    PORT
      LAYER Metal3 ;
        RECT 146.960 1002.340 147.360 1002.740 ;
    END
  END Tile_X0Y1_W6END[0]
  PIN Tile_X0Y1_W6END[10]
    DIRECTION INPUT ;
    USE SIGNAL ;
    ANTENNAGATEAREA 0.852800 ;
    ANTENNADIFFAREA 8.061600 ;
    PORT
      LAYER Metal3 ;
        RECT 146.960 1019.140 147.360 1019.540 ;
    END
  END Tile_X0Y1_W6END[10]
  PIN Tile_X0Y1_W6END[11]
    DIRECTION INPUT ;
    USE SIGNAL ;
    ANTENNAGATEAREA 0.852800 ;
    ANTENNADIFFAREA 8.061600 ;
    PORT
      LAYER Metal3 ;
        RECT 146.960 1020.820 147.360 1021.220 ;
    END
  END Tile_X0Y1_W6END[11]
  PIN Tile_X0Y1_W6END[1]
    DIRECTION INPUT ;
    USE SIGNAL ;
    ANTENNAGATEAREA 0.881400 ;
    ANTENNADIFFAREA 8.061600 ;
    PORT
      LAYER Metal3 ;
        RECT 146.960 1004.020 147.360 1004.420 ;
    END
  END Tile_X0Y1_W6END[1]
  PIN Tile_X0Y1_W6END[2]
    DIRECTION INPUT ;
    USE SIGNAL ;
    ANTENNAGATEAREA 0.881400 ;
    ANTENNADIFFAREA 8.061600 ;
    PORT
      LAYER Metal3 ;
        RECT 146.960 1005.700 147.360 1006.100 ;
    END
  END Tile_X0Y1_W6END[2]
  PIN Tile_X0Y1_W6END[3]
    DIRECTION INPUT ;
    USE SIGNAL ;
    ANTENNAGATEAREA 0.881400 ;
    ANTENNADIFFAREA 8.061600 ;
    PORT
      LAYER Metal3 ;
        RECT 146.960 1007.380 147.360 1007.780 ;
    END
  END Tile_X0Y1_W6END[3]
  PIN Tile_X0Y1_W6END[4]
    DIRECTION INPUT ;
    USE SIGNAL ;
    ANTENNAGATEAREA 1.066000 ;
    ANTENNADIFFAREA 10.077000 ;
    PORT
      LAYER Metal3 ;
        RECT 146.960 1009.060 147.360 1009.460 ;
    END
  END Tile_X0Y1_W6END[4]
  PIN Tile_X0Y1_W6END[5]
    DIRECTION INPUT ;
    USE SIGNAL ;
    ANTENNAGATEAREA 1.066000 ;
    ANTENNADIFFAREA 10.077000 ;
    PORT
      LAYER Metal3 ;
        RECT 146.960 1010.740 147.360 1011.140 ;
    END
  END Tile_X0Y1_W6END[5]
  PIN Tile_X0Y1_W6END[6]
    DIRECTION INPUT ;
    USE SIGNAL ;
    ANTENNAGATEAREA 1.066000 ;
    ANTENNADIFFAREA 10.077000 ;
    PORT
      LAYER Metal3 ;
        RECT 146.960 1012.420 147.360 1012.820 ;
    END
  END Tile_X0Y1_W6END[6]
  PIN Tile_X0Y1_W6END[7]
    DIRECTION INPUT ;
    USE SIGNAL ;
    ANTENNAGATEAREA 1.066000 ;
    ANTENNADIFFAREA 10.077000 ;
    PORT
      LAYER Metal3 ;
        RECT 146.960 1014.100 147.360 1014.500 ;
    END
  END Tile_X0Y1_W6END[7]
  PIN Tile_X0Y1_W6END[8]
    DIRECTION INPUT ;
    USE SIGNAL ;
    ANTENNAGATEAREA 0.852800 ;
    ANTENNADIFFAREA 8.061600 ;
    PORT
      LAYER Metal3 ;
        RECT 146.960 1015.780 147.360 1016.180 ;
    END
  END Tile_X0Y1_W6END[8]
  PIN Tile_X0Y1_W6END[9]
    DIRECTION INPUT ;
    USE SIGNAL ;
    ANTENNAGATEAREA 0.852800 ;
    ANTENNADIFFAREA 8.061600 ;
    PORT
      LAYER Metal3 ;
        RECT 146.960 1017.460 147.360 1017.860 ;
    END
  END Tile_X0Y1_W6END[9]
  PIN Tile_X0Y1_WW4END[0]
    DIRECTION INPUT ;
    USE SIGNAL ;
    ANTENNAGATEAREA 0.852800 ;
    ANTENNADIFFAREA 8.061600 ;
    PORT
      LAYER Metal3 ;
        RECT 146.960 975.460 147.360 975.860 ;
    END
  END Tile_X0Y1_WW4END[0]
  PIN Tile_X0Y1_WW4END[10]
    DIRECTION INPUT ;
    USE SIGNAL ;
    ANTENNAGATEAREA 0.639600 ;
    ANTENNADIFFAREA 6.046200 ;
    PORT
      LAYER Metal3 ;
        RECT 146.960 992.260 147.360 992.660 ;
    END
  END Tile_X0Y1_WW4END[10]
  PIN Tile_X0Y1_WW4END[11]
    DIRECTION INPUT ;
    USE SIGNAL ;
    ANTENNAGATEAREA 0.639600 ;
    ANTENNADIFFAREA 6.046200 ;
    PORT
      LAYER Metal3 ;
        RECT 146.960 993.940 147.360 994.340 ;
    END
  END Tile_X0Y1_WW4END[11]
  PIN Tile_X0Y1_WW4END[12]
    DIRECTION INPUT ;
    USE SIGNAL ;
    ANTENNAGATEAREA 0.852800 ;
    ANTENNADIFFAREA 8.061600 ;
    PORT
      LAYER Metal3 ;
        RECT 146.960 995.620 147.360 996.020 ;
    END
  END Tile_X0Y1_WW4END[12]
  PIN Tile_X0Y1_WW4END[13]
    DIRECTION INPUT ;
    USE SIGNAL ;
    ANTENNAGATEAREA 0.852800 ;
    ANTENNADIFFAREA 8.061600 ;
    PORT
      LAYER Metal3 ;
        RECT 146.960 997.300 147.360 997.700 ;
    END
  END Tile_X0Y1_WW4END[13]
  PIN Tile_X0Y1_WW4END[14]
    DIRECTION INPUT ;
    USE SIGNAL ;
    ANTENNAGATEAREA 0.852800 ;
    ANTENNADIFFAREA 8.061600 ;
    PORT
      LAYER Metal3 ;
        RECT 146.960 998.980 147.360 999.380 ;
    END
  END Tile_X0Y1_WW4END[14]
  PIN Tile_X0Y1_WW4END[15]
    DIRECTION INPUT ;
    USE SIGNAL ;
    ANTENNAGATEAREA 0.852800 ;
    ANTENNADIFFAREA 8.061600 ;
    PORT
      LAYER Metal3 ;
        RECT 146.960 1000.660 147.360 1001.060 ;
    END
  END Tile_X0Y1_WW4END[15]
  PIN Tile_X0Y1_WW4END[1]
    DIRECTION INPUT ;
    USE SIGNAL ;
    ANTENNAGATEAREA 0.852800 ;
    ANTENNADIFFAREA 8.061600 ;
    PORT
      LAYER Metal3 ;
        RECT 146.960 977.140 147.360 977.540 ;
    END
  END Tile_X0Y1_WW4END[1]
  PIN Tile_X0Y1_WW4END[2]
    DIRECTION INPUT ;
    USE SIGNAL ;
    ANTENNAGATEAREA 0.852800 ;
    ANTENNADIFFAREA 8.061600 ;
    PORT
      LAYER Metal3 ;
        RECT 146.960 978.820 147.360 979.220 ;
    END
  END Tile_X0Y1_WW4END[2]
  PIN Tile_X0Y1_WW4END[3]
    DIRECTION INPUT ;
    USE SIGNAL ;
    ANTENNAGATEAREA 0.852800 ;
    ANTENNADIFFAREA 8.061600 ;
    PORT
      LAYER Metal3 ;
        RECT 146.960 980.500 147.360 980.900 ;
    END
  END Tile_X0Y1_WW4END[3]
  PIN Tile_X0Y1_WW4END[4]
    DIRECTION INPUT ;
    USE SIGNAL ;
    ANTENNAGATEAREA 0.639600 ;
    ANTENNADIFFAREA 6.046200 ;
    PORT
      LAYER Metal3 ;
        RECT 146.960 982.180 147.360 982.580 ;
    END
  END Tile_X0Y1_WW4END[4]
  PIN Tile_X0Y1_WW4END[5]
    DIRECTION INPUT ;
    USE SIGNAL ;
    ANTENNAGATEAREA 0.639600 ;
    ANTENNADIFFAREA 6.046200 ;
    PORT
      LAYER Metal3 ;
        RECT 146.960 983.860 147.360 984.260 ;
    END
  END Tile_X0Y1_WW4END[5]
  PIN Tile_X0Y1_WW4END[6]
    DIRECTION INPUT ;
    USE SIGNAL ;
    ANTENNAGATEAREA 0.639600 ;
    ANTENNADIFFAREA 6.046200 ;
    PORT
      LAYER Metal3 ;
        RECT 146.960 985.540 147.360 985.940 ;
    END
  END Tile_X0Y1_WW4END[6]
  PIN Tile_X0Y1_WW4END[7]
    DIRECTION INPUT ;
    USE SIGNAL ;
    ANTENNAGATEAREA 0.639600 ;
    ANTENNADIFFAREA 6.046200 ;
    PORT
      LAYER Metal3 ;
        RECT 146.960 987.220 147.360 987.620 ;
    END
  END Tile_X0Y1_WW4END[7]
  PIN Tile_X0Y1_WW4END[8]
    DIRECTION INPUT ;
    USE SIGNAL ;
    ANTENNAGATEAREA 0.639600 ;
    ANTENNADIFFAREA 6.046200 ;
    PORT
      LAYER Metal3 ;
        RECT 146.960 988.900 147.360 989.300 ;
    END
  END Tile_X0Y1_WW4END[8]
  PIN Tile_X0Y1_WW4END[9]
    DIRECTION INPUT ;
    USE SIGNAL ;
    ANTENNAGATEAREA 0.639600 ;
    ANTENNADIFFAREA 6.046200 ;
    PORT
      LAYER Metal3 ;
        RECT 146.960 990.580 147.360 990.980 ;
    END
  END Tile_X0Y1_WW4END[9]
  PIN Tile_X0Y2_E1BEG[0]
    DIRECTION OUTPUT ;
    USE SIGNAL ;
    ANTENNADIFFAREA 2.724000 ;
    PORT
      LAYER Metal3 ;
        RECT 146.960 647.440 147.360 647.840 ;
    END
  END Tile_X0Y2_E1BEG[0]
  PIN Tile_X0Y2_E1BEG[1]
    DIRECTION OUTPUT ;
    USE SIGNAL ;
    ANTENNADIFFAREA 2.724000 ;
    PORT
      LAYER Metal3 ;
        RECT 146.960 649.120 147.360 649.520 ;
    END
  END Tile_X0Y2_E1BEG[1]
  PIN Tile_X0Y2_E1BEG[2]
    DIRECTION OUTPUT ;
    USE SIGNAL ;
    ANTENNADIFFAREA 2.724000 ;
    PORT
      LAYER Metal3 ;
        RECT 146.960 650.800 147.360 651.200 ;
    END
  END Tile_X0Y2_E1BEG[2]
  PIN Tile_X0Y2_E1BEG[3]
    DIRECTION OUTPUT ;
    USE SIGNAL ;
    ANTENNADIFFAREA 2.724000 ;
    PORT
      LAYER Metal3 ;
        RECT 146.960 652.480 147.360 652.880 ;
    END
  END Tile_X0Y2_E1BEG[3]
  PIN Tile_X0Y2_E2BEG[0]
    DIRECTION OUTPUT ;
    USE SIGNAL ;
    ANTENNADIFFAREA 2.724000 ;
    PORT
      LAYER Metal3 ;
        RECT 146.960 656.680 147.360 657.080 ;
    END
  END Tile_X0Y2_E2BEG[0]
  PIN Tile_X0Y2_E2BEG[1]
    DIRECTION OUTPUT ;
    USE SIGNAL ;
    ANTENNADIFFAREA 2.724000 ;
    PORT
      LAYER Metal3 ;
        RECT 146.960 657.520 147.360 657.920 ;
    END
  END Tile_X0Y2_E2BEG[1]
  PIN Tile_X0Y2_E2BEG[2]
    DIRECTION OUTPUT ;
    USE SIGNAL ;
    ANTENNADIFFAREA 2.724000 ;
    PORT
      LAYER Metal3 ;
        RECT 146.960 658.360 147.360 658.760 ;
    END
  END Tile_X0Y2_E2BEG[2]
  PIN Tile_X0Y2_E2BEG[3]
    DIRECTION OUTPUT ;
    USE SIGNAL ;
    ANTENNADIFFAREA 2.724000 ;
    PORT
      LAYER Metal3 ;
        RECT 146.960 659.200 147.360 659.600 ;
    END
  END Tile_X0Y2_E2BEG[3]
  PIN Tile_X0Y2_E2BEG[4]
    DIRECTION OUTPUT ;
    USE SIGNAL ;
    ANTENNADIFFAREA 2.724000 ;
    PORT
      LAYER Metal3 ;
        RECT 146.960 660.040 147.360 660.440 ;
    END
  END Tile_X0Y2_E2BEG[4]
  PIN Tile_X0Y2_E2BEG[5]
    DIRECTION OUTPUT ;
    USE SIGNAL ;
    ANTENNADIFFAREA 2.724000 ;
    PORT
      LAYER Metal3 ;
        RECT 146.960 660.880 147.360 661.280 ;
    END
  END Tile_X0Y2_E2BEG[5]
  PIN Tile_X0Y2_E2BEG[6]
    DIRECTION OUTPUT ;
    USE SIGNAL ;
    ANTENNADIFFAREA 2.724000 ;
    PORT
      LAYER Metal3 ;
        RECT 146.960 661.720 147.360 662.120 ;
    END
  END Tile_X0Y2_E2BEG[6]
  PIN Tile_X0Y2_E2BEG[7]
    DIRECTION OUTPUT ;
    USE SIGNAL ;
    ANTENNADIFFAREA 2.724000 ;
    PORT
      LAYER Metal3 ;
        RECT 146.960 662.560 147.360 662.960 ;
    END
  END Tile_X0Y2_E2BEG[7]
  PIN Tile_X0Y2_E2BEGb[0]
    DIRECTION OUTPUT ;
    USE SIGNAL ;
    ANTENNADIFFAREA 2.724000 ;
    PORT
      LAYER Metal3 ;
        RECT 146.960 666.760 147.360 667.160 ;
    END
  END Tile_X0Y2_E2BEGb[0]
  PIN Tile_X0Y2_E2BEGb[1]
    DIRECTION OUTPUT ;
    USE SIGNAL ;
    ANTENNADIFFAREA 2.724000 ;
    PORT
      LAYER Metal3 ;
        RECT 146.960 668.440 147.360 668.840 ;
    END
  END Tile_X0Y2_E2BEGb[1]
  PIN Tile_X0Y2_E2BEGb[2]
    DIRECTION OUTPUT ;
    USE SIGNAL ;
    ANTENNADIFFAREA 2.724000 ;
    PORT
      LAYER Metal3 ;
        RECT 146.960 670.120 147.360 670.520 ;
    END
  END Tile_X0Y2_E2BEGb[2]
  PIN Tile_X0Y2_E2BEGb[3]
    DIRECTION OUTPUT ;
    USE SIGNAL ;
    ANTENNADIFFAREA 2.724000 ;
    PORT
      LAYER Metal3 ;
        RECT 146.960 671.800 147.360 672.200 ;
    END
  END Tile_X0Y2_E2BEGb[3]
  PIN Tile_X0Y2_E2BEGb[4]
    DIRECTION OUTPUT ;
    USE SIGNAL ;
    ANTENNADIFFAREA 2.724000 ;
    PORT
      LAYER Metal3 ;
        RECT 146.960 673.480 147.360 673.880 ;
    END
  END Tile_X0Y2_E2BEGb[4]
  PIN Tile_X0Y2_E2BEGb[5]
    DIRECTION OUTPUT ;
    USE SIGNAL ;
    ANTENNADIFFAREA 2.724000 ;
    PORT
      LAYER Metal3 ;
        RECT 146.960 675.160 147.360 675.560 ;
    END
  END Tile_X0Y2_E2BEGb[5]
  PIN Tile_X0Y2_E2BEGb[6]
    DIRECTION OUTPUT ;
    USE SIGNAL ;
    ANTENNADIFFAREA 2.724000 ;
    PORT
      LAYER Metal3 ;
        RECT 146.960 676.840 147.360 677.240 ;
    END
  END Tile_X0Y2_E2BEGb[6]
  PIN Tile_X0Y2_E2BEGb[7]
    DIRECTION OUTPUT ;
    USE SIGNAL ;
    ANTENNADIFFAREA 2.724000 ;
    PORT
      LAYER Metal3 ;
        RECT 146.960 678.520 147.360 678.920 ;
    END
  END Tile_X0Y2_E2BEGb[7]
  PIN Tile_X0Y2_E6BEG[0]
    DIRECTION OUTPUT ;
    USE SIGNAL ;
    ANTENNADIFFAREA 2.724000 ;
    PORT
      LAYER Metal3 ;
        RECT 146.960 706.240 147.360 706.640 ;
    END
  END Tile_X0Y2_E6BEG[0]
  PIN Tile_X0Y2_E6BEG[10]
    DIRECTION OUTPUT ;
    USE SIGNAL ;
    ANTENNADIFFAREA 2.724000 ;
    PORT
      LAYER Metal3 ;
        RECT 146.960 723.040 147.360 723.440 ;
    END
  END Tile_X0Y2_E6BEG[10]
  PIN Tile_X0Y2_E6BEG[11]
    DIRECTION OUTPUT ;
    USE SIGNAL ;
    ANTENNADIFFAREA 2.724000 ;
    PORT
      LAYER Metal3 ;
        RECT 146.960 724.720 147.360 725.120 ;
    END
  END Tile_X0Y2_E6BEG[11]
  PIN Tile_X0Y2_E6BEG[1]
    DIRECTION OUTPUT ;
    USE SIGNAL ;
    ANTENNADIFFAREA 2.724000 ;
    PORT
      LAYER Metal3 ;
        RECT 146.960 707.920 147.360 708.320 ;
    END
  END Tile_X0Y2_E6BEG[1]
  PIN Tile_X0Y2_E6BEG[2]
    DIRECTION OUTPUT ;
    USE SIGNAL ;
    ANTENNADIFFAREA 2.724000 ;
    PORT
      LAYER Metal3 ;
        RECT 146.960 709.600 147.360 710.000 ;
    END
  END Tile_X0Y2_E6BEG[2]
  PIN Tile_X0Y2_E6BEG[3]
    DIRECTION OUTPUT ;
    USE SIGNAL ;
    ANTENNADIFFAREA 2.724000 ;
    PORT
      LAYER Metal3 ;
        RECT 146.960 711.280 147.360 711.680 ;
    END
  END Tile_X0Y2_E6BEG[3]
  PIN Tile_X0Y2_E6BEG[4]
    DIRECTION OUTPUT ;
    USE SIGNAL ;
    ANTENNADIFFAREA 2.724000 ;
    PORT
      LAYER Metal3 ;
        RECT 146.960 712.960 147.360 713.360 ;
    END
  END Tile_X0Y2_E6BEG[4]
  PIN Tile_X0Y2_E6BEG[5]
    DIRECTION OUTPUT ;
    USE SIGNAL ;
    ANTENNADIFFAREA 2.724000 ;
    PORT
      LAYER Metal3 ;
        RECT 146.960 714.640 147.360 715.040 ;
    END
  END Tile_X0Y2_E6BEG[5]
  PIN Tile_X0Y2_E6BEG[6]
    DIRECTION OUTPUT ;
    USE SIGNAL ;
    ANTENNADIFFAREA 2.724000 ;
    PORT
      LAYER Metal3 ;
        RECT 146.960 716.320 147.360 716.720 ;
    END
  END Tile_X0Y2_E6BEG[6]
  PIN Tile_X0Y2_E6BEG[7]
    DIRECTION OUTPUT ;
    USE SIGNAL ;
    ANTENNADIFFAREA 2.724000 ;
    PORT
      LAYER Metal3 ;
        RECT 146.960 718.000 147.360 718.400 ;
    END
  END Tile_X0Y2_E6BEG[7]
  PIN Tile_X0Y2_E6BEG[8]
    DIRECTION OUTPUT ;
    USE SIGNAL ;
    ANTENNADIFFAREA 2.724000 ;
    PORT
      LAYER Metal3 ;
        RECT 146.960 719.680 147.360 720.080 ;
    END
  END Tile_X0Y2_E6BEG[8]
  PIN Tile_X0Y2_E6BEG[9]
    DIRECTION OUTPUT ;
    USE SIGNAL ;
    ANTENNADIFFAREA 2.724000 ;
    PORT
      LAYER Metal3 ;
        RECT 146.960 721.360 147.360 721.760 ;
    END
  END Tile_X0Y2_E6BEG[9]
  PIN Tile_X0Y2_EE4BEG[0]
    DIRECTION OUTPUT ;
    USE SIGNAL ;
    ANTENNADIFFAREA 2.724000 ;
    PORT
      LAYER Metal3 ;
        RECT 146.960 686.080 147.360 686.480 ;
    END
  END Tile_X0Y2_EE4BEG[0]
  PIN Tile_X0Y2_EE4BEG[10]
    DIRECTION OUTPUT ;
    USE SIGNAL ;
    ANTENNADIFFAREA 2.724000 ;
    PORT
      LAYER Metal3 ;
        RECT 146.960 694.480 147.360 694.880 ;
    END
  END Tile_X0Y2_EE4BEG[10]
  PIN Tile_X0Y2_EE4BEG[11]
    DIRECTION OUTPUT ;
    USE SIGNAL ;
    ANTENNADIFFAREA 2.724000 ;
    PORT
      LAYER Metal3 ;
        RECT 146.960 695.320 147.360 695.720 ;
    END
  END Tile_X0Y2_EE4BEG[11]
  PIN Tile_X0Y2_EE4BEG[12]
    DIRECTION OUTPUT ;
    USE SIGNAL ;
    ANTENNADIFFAREA 2.724000 ;
    PORT
      LAYER Metal3 ;
        RECT 146.960 696.160 147.360 696.560 ;
    END
  END Tile_X0Y2_EE4BEG[12]
  PIN Tile_X0Y2_EE4BEG[13]
    DIRECTION OUTPUT ;
    USE SIGNAL ;
    ANTENNADIFFAREA 2.724000 ;
    PORT
      LAYER Metal3 ;
        RECT 146.960 697.000 147.360 697.400 ;
    END
  END Tile_X0Y2_EE4BEG[13]
  PIN Tile_X0Y2_EE4BEG[14]
    DIRECTION OUTPUT ;
    USE SIGNAL ;
    ANTENNADIFFAREA 2.724000 ;
    PORT
      LAYER Metal3 ;
        RECT 146.960 697.840 147.360 698.240 ;
    END
  END Tile_X0Y2_EE4BEG[14]
  PIN Tile_X0Y2_EE4BEG[15]
    DIRECTION OUTPUT ;
    USE SIGNAL ;
    ANTENNADIFFAREA 2.724000 ;
    PORT
      LAYER Metal3 ;
        RECT 146.960 698.680 147.360 699.080 ;
    END
  END Tile_X0Y2_EE4BEG[15]
  PIN Tile_X0Y2_EE4BEG[1]
    DIRECTION OUTPUT ;
    USE SIGNAL ;
    ANTENNADIFFAREA 2.724000 ;
    PORT
      LAYER Metal3 ;
        RECT 146.960 686.920 147.360 687.320 ;
    END
  END Tile_X0Y2_EE4BEG[1]
  PIN Tile_X0Y2_EE4BEG[2]
    DIRECTION OUTPUT ;
    USE SIGNAL ;
    ANTENNADIFFAREA 2.724000 ;
    PORT
      LAYER Metal3 ;
        RECT 146.960 687.760 147.360 688.160 ;
    END
  END Tile_X0Y2_EE4BEG[2]
  PIN Tile_X0Y2_EE4BEG[3]
    DIRECTION OUTPUT ;
    USE SIGNAL ;
    ANTENNADIFFAREA 2.724000 ;
    PORT
      LAYER Metal3 ;
        RECT 146.960 688.600 147.360 689.000 ;
    END
  END Tile_X0Y2_EE4BEG[3]
  PIN Tile_X0Y2_EE4BEG[4]
    DIRECTION OUTPUT ;
    USE SIGNAL ;
    ANTENNADIFFAREA 2.724000 ;
    PORT
      LAYER Metal3 ;
        RECT 146.960 689.440 147.360 689.840 ;
    END
  END Tile_X0Y2_EE4BEG[4]
  PIN Tile_X0Y2_EE4BEG[5]
    DIRECTION OUTPUT ;
    USE SIGNAL ;
    ANTENNADIFFAREA 2.724000 ;
    PORT
      LAYER Metal3 ;
        RECT 146.960 690.280 147.360 690.680 ;
    END
  END Tile_X0Y2_EE4BEG[5]
  PIN Tile_X0Y2_EE4BEG[6]
    DIRECTION OUTPUT ;
    USE SIGNAL ;
    ANTENNADIFFAREA 2.724000 ;
    PORT
      LAYER Metal3 ;
        RECT 146.960 691.120 147.360 691.520 ;
    END
  END Tile_X0Y2_EE4BEG[6]
  PIN Tile_X0Y2_EE4BEG[7]
    DIRECTION OUTPUT ;
    USE SIGNAL ;
    ANTENNADIFFAREA 2.724000 ;
    PORT
      LAYER Metal3 ;
        RECT 146.960 691.960 147.360 692.360 ;
    END
  END Tile_X0Y2_EE4BEG[7]
  PIN Tile_X0Y2_EE4BEG[8]
    DIRECTION OUTPUT ;
    USE SIGNAL ;
    ANTENNADIFFAREA 2.724000 ;
    PORT
      LAYER Metal3 ;
        RECT 146.960 692.800 147.360 693.200 ;
    END
  END Tile_X0Y2_EE4BEG[8]
  PIN Tile_X0Y2_EE4BEG[9]
    DIRECTION OUTPUT ;
    USE SIGNAL ;
    ANTENNADIFFAREA 2.724000 ;
    PORT
      LAYER Metal3 ;
        RECT 146.960 693.640 147.360 694.040 ;
    END
  END Tile_X0Y2_EE4BEG[9]
  PIN Tile_X0Y2_FrameData[0]
    DIRECTION INPUT ;
    USE SIGNAL ;
    ANTENNAGATEAREA 1.626300 ;
    ANTENNADIFFAREA 18.138599 ;
    PORT
      LAYER Metal3 ;
        RECT 0.000 666.760 0.400 667.160 ;
    END
  END Tile_X0Y2_FrameData[0]
  PIN Tile_X0Y2_FrameData[10]
    DIRECTION INPUT ;
    USE SIGNAL ;
    ANTENNAGATEAREA 1.626300 ;
    ANTENNADIFFAREA 18.138599 ;
    PORT
      LAYER Metal3 ;
        RECT 0.000 725.560 0.400 725.960 ;
    END
  END Tile_X0Y2_FrameData[10]
  PIN Tile_X0Y2_FrameData[11]
    DIRECTION INPUT ;
    USE SIGNAL ;
    ANTENNAGATEAREA 1.626300 ;
    ANTENNADIFFAREA 18.138599 ;
    PORT
      LAYER Metal3 ;
        RECT 0.000 731.440 0.400 731.840 ;
    END
  END Tile_X0Y2_FrameData[11]
  PIN Tile_X0Y2_FrameData[12]
    DIRECTION INPUT ;
    USE SIGNAL ;
    ANTENNAGATEAREA 1.626300 ;
    ANTENNADIFFAREA 18.138599 ;
    PORT
      LAYER Metal3 ;
        RECT 0.000 737.320 0.400 737.720 ;
    END
  END Tile_X0Y2_FrameData[12]
  PIN Tile_X0Y2_FrameData[13]
    DIRECTION INPUT ;
    USE SIGNAL ;
    ANTENNAGATEAREA 1.626300 ;
    ANTENNADIFFAREA 18.138599 ;
    PORT
      LAYER Metal3 ;
        RECT 0.000 743.200 0.400 743.600 ;
    END
  END Tile_X0Y2_FrameData[13]
  PIN Tile_X0Y2_FrameData[14]
    DIRECTION INPUT ;
    USE SIGNAL ;
    ANTENNAGATEAREA 1.626300 ;
    ANTENNADIFFAREA 18.138599 ;
    PORT
      LAYER Metal3 ;
        RECT 0.000 749.080 0.400 749.480 ;
    END
  END Tile_X0Y2_FrameData[14]
  PIN Tile_X0Y2_FrameData[15]
    DIRECTION INPUT ;
    USE SIGNAL ;
    ANTENNAGATEAREA 1.626300 ;
    ANTENNADIFFAREA 18.138599 ;
    PORT
      LAYER Metal3 ;
        RECT 0.000 754.960 0.400 755.360 ;
    END
  END Tile_X0Y2_FrameData[15]
  PIN Tile_X0Y2_FrameData[16]
    DIRECTION INPUT ;
    USE SIGNAL ;
    ANTENNAGATEAREA 1.807000 ;
    ANTENNADIFFAREA 20.153999 ;
    PORT
      LAYER Metal3 ;
        RECT 0.000 760.840 0.400 761.240 ;
    END
  END Tile_X0Y2_FrameData[16]
  PIN Tile_X0Y2_FrameData[17]
    DIRECTION INPUT ;
    USE SIGNAL ;
    ANTENNAGATEAREA 1.807000 ;
    ANTENNADIFFAREA 20.153999 ;
    PORT
      LAYER Metal3 ;
        RECT 0.000 766.720 0.400 767.120 ;
    END
  END Tile_X0Y2_FrameData[17]
  PIN Tile_X0Y2_FrameData[18]
    DIRECTION INPUT ;
    USE SIGNAL ;
    ANTENNAGATEAREA 1.807000 ;
    ANTENNADIFFAREA 20.153999 ;
    PORT
      LAYER Metal3 ;
        RECT 0.000 772.600 0.400 773.000 ;
    END
  END Tile_X0Y2_FrameData[18]
  PIN Tile_X0Y2_FrameData[19]
    DIRECTION INPUT ;
    USE SIGNAL ;
    ANTENNAGATEAREA 1.807000 ;
    ANTENNADIFFAREA 20.153999 ;
    PORT
      LAYER Metal3 ;
        RECT 0.000 778.480 0.400 778.880 ;
    END
  END Tile_X0Y2_FrameData[19]
  PIN Tile_X0Y2_FrameData[1]
    DIRECTION INPUT ;
    USE SIGNAL ;
    ANTENNAGATEAREA 1.626300 ;
    ANTENNADIFFAREA 18.138599 ;
    PORT
      LAYER Metal3 ;
        RECT 0.000 672.640 0.400 673.040 ;
    END
  END Tile_X0Y2_FrameData[1]
  PIN Tile_X0Y2_FrameData[20]
    DIRECTION INPUT ;
    USE SIGNAL ;
    ANTENNAGATEAREA 1.807000 ;
    ANTENNADIFFAREA 20.153999 ;
    PORT
      LAYER Metal3 ;
        RECT 0.000 784.360 0.400 784.760 ;
    END
  END Tile_X0Y2_FrameData[20]
  PIN Tile_X0Y2_FrameData[21]
    DIRECTION INPUT ;
    USE SIGNAL ;
    ANTENNAGATEAREA 1.807000 ;
    ANTENNADIFFAREA 20.153999 ;
    PORT
      LAYER Metal3 ;
        RECT 0.000 790.240 0.400 790.640 ;
    END
  END Tile_X0Y2_FrameData[21]
  PIN Tile_X0Y2_FrameData[22]
    DIRECTION INPUT ;
    USE SIGNAL ;
    ANTENNAGATEAREA 1.807000 ;
    ANTENNADIFFAREA 20.153999 ;
    PORT
      LAYER Metal3 ;
        RECT 0.000 796.120 0.400 796.520 ;
    END
  END Tile_X0Y2_FrameData[22]
  PIN Tile_X0Y2_FrameData[23]
    DIRECTION INPUT ;
    USE SIGNAL ;
    ANTENNAGATEAREA 1.807000 ;
    ANTENNADIFFAREA 20.153999 ;
    PORT
      LAYER Metal3 ;
        RECT 0.000 802.000 0.400 802.400 ;
    END
  END Tile_X0Y2_FrameData[23]
  PIN Tile_X0Y2_FrameData[24]
    DIRECTION INPUT ;
    USE SIGNAL ;
    ANTENNAGATEAREA 1.807000 ;
    ANTENNADIFFAREA 20.153999 ;
    PORT
      LAYER Metal3 ;
        RECT 0.000 807.880 0.400 808.280 ;
    END
  END Tile_X0Y2_FrameData[24]
  PIN Tile_X0Y2_FrameData[25]
    DIRECTION INPUT ;
    USE SIGNAL ;
    ANTENNAGATEAREA 1.807000 ;
    ANTENNADIFFAREA 20.153999 ;
    PORT
      LAYER Metal3 ;
        RECT 0.000 813.760 0.400 814.160 ;
    END
  END Tile_X0Y2_FrameData[25]
  PIN Tile_X0Y2_FrameData[26]
    DIRECTION INPUT ;
    USE SIGNAL ;
    ANTENNAGATEAREA 1.807000 ;
    ANTENNADIFFAREA 20.153999 ;
    PORT
      LAYER Metal3 ;
        RECT 0.000 819.640 0.400 820.040 ;
    END
  END Tile_X0Y2_FrameData[26]
  PIN Tile_X0Y2_FrameData[27]
    DIRECTION INPUT ;
    USE SIGNAL ;
    ANTENNAGATEAREA 1.807000 ;
    ANTENNADIFFAREA 20.153999 ;
    PORT
      LAYER Metal3 ;
        RECT 0.000 825.520 0.400 825.920 ;
    END
  END Tile_X0Y2_FrameData[27]
  PIN Tile_X0Y2_FrameData[28]
    DIRECTION INPUT ;
    USE SIGNAL ;
    ANTENNAGATEAREA 1.807000 ;
    ANTENNADIFFAREA 20.153999 ;
    PORT
      LAYER Metal3 ;
        RECT 0.000 831.400 0.400 831.800 ;
    END
  END Tile_X0Y2_FrameData[28]
  PIN Tile_X0Y2_FrameData[29]
    DIRECTION INPUT ;
    USE SIGNAL ;
    ANTENNAGATEAREA 1.807000 ;
    ANTENNADIFFAREA 20.153999 ;
    PORT
      LAYER Metal3 ;
        RECT 0.000 837.280 0.400 837.680 ;
    END
  END Tile_X0Y2_FrameData[29]
  PIN Tile_X0Y2_FrameData[2]
    DIRECTION INPUT ;
    USE SIGNAL ;
    ANTENNAGATEAREA 1.626300 ;
    ANTENNADIFFAREA 18.138599 ;
    PORT
      LAYER Metal3 ;
        RECT 0.000 678.520 0.400 678.920 ;
    END
  END Tile_X0Y2_FrameData[2]
  PIN Tile_X0Y2_FrameData[30]
    DIRECTION INPUT ;
    USE SIGNAL ;
    ANTENNAGATEAREA 1.807000 ;
    ANTENNADIFFAREA 20.153999 ;
    PORT
      LAYER Metal3 ;
        RECT 0.000 843.160 0.400 843.560 ;
    END
  END Tile_X0Y2_FrameData[30]
  PIN Tile_X0Y2_FrameData[31]
    DIRECTION INPUT ;
    USE SIGNAL ;
    ANTENNAGATEAREA 1.807000 ;
    ANTENNADIFFAREA 20.153999 ;
    PORT
      LAYER Metal3 ;
        RECT 0.000 849.040 0.400 849.440 ;
    END
  END Tile_X0Y2_FrameData[31]
  PIN Tile_X0Y2_FrameData[3]
    DIRECTION INPUT ;
    USE SIGNAL ;
    ANTENNAGATEAREA 1.626300 ;
    ANTENNADIFFAREA 18.138599 ;
    PORT
      LAYER Metal3 ;
        RECT 0.000 684.400 0.400 684.800 ;
    END
  END Tile_X0Y2_FrameData[3]
  PIN Tile_X0Y2_FrameData[4]
    DIRECTION INPUT ;
    USE SIGNAL ;
    ANTENNAGATEAREA 1.626300 ;
    ANTENNADIFFAREA 18.138599 ;
    PORT
      LAYER Metal3 ;
        RECT 0.000 690.280 0.400 690.680 ;
    END
  END Tile_X0Y2_FrameData[4]
  PIN Tile_X0Y2_FrameData[5]
    DIRECTION INPUT ;
    USE SIGNAL ;
    ANTENNAGATEAREA 1.626300 ;
    ANTENNADIFFAREA 18.138599 ;
    PORT
      LAYER Metal3 ;
        RECT 0.000 696.160 0.400 696.560 ;
    END
  END Tile_X0Y2_FrameData[5]
  PIN Tile_X0Y2_FrameData[6]
    DIRECTION INPUT ;
    USE SIGNAL ;
    ANTENNAGATEAREA 1.626300 ;
    ANTENNADIFFAREA 18.138599 ;
    PORT
      LAYER Metal3 ;
        RECT 0.000 702.040 0.400 702.440 ;
    END
  END Tile_X0Y2_FrameData[6]
  PIN Tile_X0Y2_FrameData[7]
    DIRECTION INPUT ;
    USE SIGNAL ;
    ANTENNAGATEAREA 1.626300 ;
    ANTENNADIFFAREA 18.138599 ;
    PORT
      LAYER Metal3 ;
        RECT 0.000 707.920 0.400 708.320 ;
    END
  END Tile_X0Y2_FrameData[7]
  PIN Tile_X0Y2_FrameData[8]
    DIRECTION INPUT ;
    USE SIGNAL ;
    ANTENNAGATEAREA 1.626300 ;
    ANTENNADIFFAREA 18.138599 ;
    PORT
      LAYER Metal3 ;
        RECT 0.000 713.800 0.400 714.200 ;
    END
  END Tile_X0Y2_FrameData[8]
  PIN Tile_X0Y2_FrameData[9]
    DIRECTION INPUT ;
    USE SIGNAL ;
    ANTENNAGATEAREA 1.626300 ;
    ANTENNADIFFAREA 18.138599 ;
    PORT
      LAYER Metal3 ;
        RECT 0.000 719.680 0.400 720.080 ;
    END
  END Tile_X0Y2_FrameData[9]
  PIN Tile_X0Y2_FrameData_O[0]
    DIRECTION OUTPUT ;
    USE SIGNAL ;
    ANTENNADIFFAREA 2.724000 ;
    PORT
      LAYER Metal3 ;
        RECT 146.960 808.720 147.360 809.120 ;
    END
  END Tile_X0Y2_FrameData_O[0]
  PIN Tile_X0Y2_FrameData_O[10]
    DIRECTION OUTPUT ;
    USE SIGNAL ;
    ANTENNADIFFAREA 2.724000 ;
    PORT
      LAYER Metal3 ;
        RECT 146.960 825.520 147.360 825.920 ;
    END
  END Tile_X0Y2_FrameData_O[10]
  PIN Tile_X0Y2_FrameData_O[11]
    DIRECTION OUTPUT ;
    USE SIGNAL ;
    ANTENNADIFFAREA 2.724000 ;
    PORT
      LAYER Metal3 ;
        RECT 146.960 827.200 147.360 827.600 ;
    END
  END Tile_X0Y2_FrameData_O[11]
  PIN Tile_X0Y2_FrameData_O[12]
    DIRECTION OUTPUT ;
    USE SIGNAL ;
    ANTENNADIFFAREA 2.724000 ;
    PORT
      LAYER Metal3 ;
        RECT 146.960 828.880 147.360 829.280 ;
    END
  END Tile_X0Y2_FrameData_O[12]
  PIN Tile_X0Y2_FrameData_O[13]
    DIRECTION OUTPUT ;
    USE SIGNAL ;
    ANTENNADIFFAREA 2.724000 ;
    PORT
      LAYER Metal3 ;
        RECT 146.960 830.560 147.360 830.960 ;
    END
  END Tile_X0Y2_FrameData_O[13]
  PIN Tile_X0Y2_FrameData_O[14]
    DIRECTION OUTPUT ;
    USE SIGNAL ;
    ANTENNADIFFAREA 2.724000 ;
    PORT
      LAYER Metal3 ;
        RECT 146.960 832.240 147.360 832.640 ;
    END
  END Tile_X0Y2_FrameData_O[14]
  PIN Tile_X0Y2_FrameData_O[15]
    DIRECTION OUTPUT ;
    USE SIGNAL ;
    ANTENNADIFFAREA 2.724000 ;
    PORT
      LAYER Metal3 ;
        RECT 146.960 833.920 147.360 834.320 ;
    END
  END Tile_X0Y2_FrameData_O[15]
  PIN Tile_X0Y2_FrameData_O[16]
    DIRECTION OUTPUT ;
    USE SIGNAL ;
    ANTENNADIFFAREA 2.724000 ;
    PORT
      LAYER Metal3 ;
        RECT 146.960 835.600 147.360 836.000 ;
    END
  END Tile_X0Y2_FrameData_O[16]
  PIN Tile_X0Y2_FrameData_O[17]
    DIRECTION OUTPUT ;
    USE SIGNAL ;
    ANTENNADIFFAREA 2.724000 ;
    PORT
      LAYER Metal3 ;
        RECT 146.960 837.280 147.360 837.680 ;
    END
  END Tile_X0Y2_FrameData_O[17]
  PIN Tile_X0Y2_FrameData_O[18]
    DIRECTION OUTPUT ;
    USE SIGNAL ;
    ANTENNADIFFAREA 2.724000 ;
    PORT
      LAYER Metal3 ;
        RECT 146.960 838.960 147.360 839.360 ;
    END
  END Tile_X0Y2_FrameData_O[18]
  PIN Tile_X0Y2_FrameData_O[19]
    DIRECTION OUTPUT ;
    USE SIGNAL ;
    ANTENNADIFFAREA 2.724000 ;
    PORT
      LAYER Metal3 ;
        RECT 146.960 840.640 147.360 841.040 ;
    END
  END Tile_X0Y2_FrameData_O[19]
  PIN Tile_X0Y2_FrameData_O[1]
    DIRECTION OUTPUT ;
    USE SIGNAL ;
    ANTENNADIFFAREA 2.724000 ;
    PORT
      LAYER Metal3 ;
        RECT 146.960 810.400 147.360 810.800 ;
    END
  END Tile_X0Y2_FrameData_O[1]
  PIN Tile_X0Y2_FrameData_O[20]
    DIRECTION OUTPUT ;
    USE SIGNAL ;
    ANTENNADIFFAREA 2.724000 ;
    PORT
      LAYER Metal3 ;
        RECT 146.960 842.320 147.360 842.720 ;
    END
  END Tile_X0Y2_FrameData_O[20]
  PIN Tile_X0Y2_FrameData_O[21]
    DIRECTION OUTPUT ;
    USE SIGNAL ;
    ANTENNADIFFAREA 2.724000 ;
    PORT
      LAYER Metal3 ;
        RECT 146.960 844.000 147.360 844.400 ;
    END
  END Tile_X0Y2_FrameData_O[21]
  PIN Tile_X0Y2_FrameData_O[22]
    DIRECTION OUTPUT ;
    USE SIGNAL ;
    ANTENNADIFFAREA 2.724000 ;
    PORT
      LAYER Metal3 ;
        RECT 146.960 845.680 147.360 846.080 ;
    END
  END Tile_X0Y2_FrameData_O[22]
  PIN Tile_X0Y2_FrameData_O[23]
    DIRECTION OUTPUT ;
    USE SIGNAL ;
    ANTENNADIFFAREA 2.724000 ;
    PORT
      LAYER Metal3 ;
        RECT 146.960 847.360 147.360 847.760 ;
    END
  END Tile_X0Y2_FrameData_O[23]
  PIN Tile_X0Y2_FrameData_O[24]
    DIRECTION OUTPUT ;
    USE SIGNAL ;
    ANTENNADIFFAREA 2.724000 ;
    PORT
      LAYER Metal3 ;
        RECT 146.960 849.040 147.360 849.440 ;
    END
  END Tile_X0Y2_FrameData_O[24]
  PIN Tile_X0Y2_FrameData_O[25]
    DIRECTION OUTPUT ;
    USE SIGNAL ;
    ANTENNADIFFAREA 2.724000 ;
    PORT
      LAYER Metal3 ;
        RECT 146.960 850.720 147.360 851.120 ;
    END
  END Tile_X0Y2_FrameData_O[25]
  PIN Tile_X0Y2_FrameData_O[26]
    DIRECTION OUTPUT ;
    USE SIGNAL ;
    ANTENNADIFFAREA 2.724000 ;
    PORT
      LAYER Metal3 ;
        RECT 146.960 852.400 147.360 852.800 ;
    END
  END Tile_X0Y2_FrameData_O[26]
  PIN Tile_X0Y2_FrameData_O[27]
    DIRECTION OUTPUT ;
    USE SIGNAL ;
    ANTENNADIFFAREA 2.724000 ;
    PORT
      LAYER Metal3 ;
        RECT 146.960 854.080 147.360 854.480 ;
    END
  END Tile_X0Y2_FrameData_O[27]
  PIN Tile_X0Y2_FrameData_O[28]
    DIRECTION OUTPUT ;
    USE SIGNAL ;
    ANTENNADIFFAREA 2.724000 ;
    PORT
      LAYER Metal3 ;
        RECT 146.960 855.760 147.360 856.160 ;
    END
  END Tile_X0Y2_FrameData_O[28]
  PIN Tile_X0Y2_FrameData_O[29]
    DIRECTION OUTPUT ;
    USE SIGNAL ;
    ANTENNADIFFAREA 2.724000 ;
    PORT
      LAYER Metal3 ;
        RECT 146.960 857.440 147.360 857.840 ;
    END
  END Tile_X0Y2_FrameData_O[29]
  PIN Tile_X0Y2_FrameData_O[2]
    DIRECTION OUTPUT ;
    USE SIGNAL ;
    ANTENNADIFFAREA 2.724000 ;
    PORT
      LAYER Metal3 ;
        RECT 146.960 812.080 147.360 812.480 ;
    END
  END Tile_X0Y2_FrameData_O[2]
  PIN Tile_X0Y2_FrameData_O[30]
    DIRECTION OUTPUT ;
    USE SIGNAL ;
    ANTENNADIFFAREA 2.724000 ;
    PORT
      LAYER Metal3 ;
        RECT 146.960 859.120 147.360 859.520 ;
    END
  END Tile_X0Y2_FrameData_O[30]
  PIN Tile_X0Y2_FrameData_O[31]
    DIRECTION OUTPUT ;
    USE SIGNAL ;
    ANTENNADIFFAREA 2.724000 ;
    PORT
      LAYER Metal3 ;
        RECT 146.960 860.800 147.360 861.200 ;
    END
  END Tile_X0Y2_FrameData_O[31]
  PIN Tile_X0Y2_FrameData_O[3]
    DIRECTION OUTPUT ;
    USE SIGNAL ;
    ANTENNADIFFAREA 2.724000 ;
    PORT
      LAYER Metal3 ;
        RECT 146.960 813.760 147.360 814.160 ;
    END
  END Tile_X0Y2_FrameData_O[3]
  PIN Tile_X0Y2_FrameData_O[4]
    DIRECTION OUTPUT ;
    USE SIGNAL ;
    ANTENNADIFFAREA 2.724000 ;
    PORT
      LAYER Metal3 ;
        RECT 146.960 815.440 147.360 815.840 ;
    END
  END Tile_X0Y2_FrameData_O[4]
  PIN Tile_X0Y2_FrameData_O[5]
    DIRECTION OUTPUT ;
    USE SIGNAL ;
    ANTENNADIFFAREA 2.724000 ;
    PORT
      LAYER Metal3 ;
        RECT 146.960 817.120 147.360 817.520 ;
    END
  END Tile_X0Y2_FrameData_O[5]
  PIN Tile_X0Y2_FrameData_O[6]
    DIRECTION OUTPUT ;
    USE SIGNAL ;
    ANTENNADIFFAREA 2.724000 ;
    PORT
      LAYER Metal3 ;
        RECT 146.960 818.800 147.360 819.200 ;
    END
  END Tile_X0Y2_FrameData_O[6]
  PIN Tile_X0Y2_FrameData_O[7]
    DIRECTION OUTPUT ;
    USE SIGNAL ;
    ANTENNADIFFAREA 2.724000 ;
    PORT
      LAYER Metal3 ;
        RECT 146.960 820.480 147.360 820.880 ;
    END
  END Tile_X0Y2_FrameData_O[7]
  PIN Tile_X0Y2_FrameData_O[8]
    DIRECTION OUTPUT ;
    USE SIGNAL ;
    ANTENNADIFFAREA 2.724000 ;
    PORT
      LAYER Metal3 ;
        RECT 146.960 822.160 147.360 822.560 ;
    END
  END Tile_X0Y2_FrameData_O[8]
  PIN Tile_X0Y2_FrameData_O[9]
    DIRECTION OUTPUT ;
    USE SIGNAL ;
    ANTENNADIFFAREA 2.724000 ;
    PORT
      LAYER Metal3 ;
        RECT 146.960 823.840 147.360 824.240 ;
    END
  END Tile_X0Y2_FrameData_O[9]
  PIN Tile_X0Y2_UserCLK
    DIRECTION INPUT ;
    USE SIGNAL ;
    ANTENNAGATEAREA 0.180700 ;
    ANTENNADIFFAREA 2.015400 ;
    PORT
      LAYER Metal3 ;
        RECT 0.000 649.960 0.400 650.360 ;
    END
  END Tile_X0Y2_UserCLK
  PIN Tile_X0Y2_UserCLKo
    DIRECTION OUTPUT ;
    USE SIGNAL ;
    ANTENNADIFFAREA 2.724000 ;
    PORT
      LAYER Metal3 ;
        RECT 146.960 807.040 147.360 807.440 ;
    END
  END Tile_X0Y2_UserCLKo
  PIN Tile_X0Y2_W1END[0]
    DIRECTION INPUT ;
    USE SIGNAL ;
    ANTENNAGATEAREA 1.279200 ;
    ANTENNADIFFAREA 12.092400 ;
    PORT
      LAYER Metal3 ;
        RECT 146.960 726.400 147.360 726.800 ;
    END
  END Tile_X0Y2_W1END[0]
  PIN Tile_X0Y2_W1END[1]
    DIRECTION INPUT ;
    USE SIGNAL ;
    ANTENNAGATEAREA 1.279200 ;
    ANTENNADIFFAREA 12.092400 ;
    PORT
      LAYER Metal3 ;
        RECT 146.960 728.080 147.360 728.480 ;
    END
  END Tile_X0Y2_W1END[1]
  PIN Tile_X0Y2_W1END[2]
    DIRECTION INPUT ;
    USE SIGNAL ;
    ANTENNAGATEAREA 1.279200 ;
    ANTENNADIFFAREA 12.092400 ;
    PORT
      LAYER Metal3 ;
        RECT 146.960 729.760 147.360 730.160 ;
    END
  END Tile_X0Y2_W1END[2]
  PIN Tile_X0Y2_W1END[3]
    DIRECTION INPUT ;
    USE SIGNAL ;
    ANTENNAGATEAREA 1.279200 ;
    ANTENNADIFFAREA 12.092400 ;
    PORT
      LAYER Metal3 ;
        RECT 146.960 731.440 147.360 731.840 ;
    END
  END Tile_X0Y2_W1END[3]
  PIN Tile_X0Y2_W2END[0]
    DIRECTION INPUT ;
    USE SIGNAL ;
    ANTENNAGATEAREA 0.852800 ;
    ANTENNADIFFAREA 8.061600 ;
    PORT
      LAYER Metal3 ;
        RECT 146.960 746.560 147.360 746.960 ;
    END
  END Tile_X0Y2_W2END[0]
  PIN Tile_X0Y2_W2END[1]
    DIRECTION INPUT ;
    USE SIGNAL ;
    ANTENNAGATEAREA 0.852800 ;
    ANTENNADIFFAREA 8.061600 ;
    PORT
      LAYER Metal3 ;
        RECT 146.960 748.240 147.360 748.640 ;
    END
  END Tile_X0Y2_W2END[1]
  PIN Tile_X0Y2_W2END[2]
    DIRECTION INPUT ;
    USE SIGNAL ;
    ANTENNAGATEAREA 0.852800 ;
    ANTENNADIFFAREA 8.061600 ;
    PORT
      LAYER Metal3 ;
        RECT 146.960 749.920 147.360 750.320 ;
    END
  END Tile_X0Y2_W2END[2]
  PIN Tile_X0Y2_W2END[3]
    DIRECTION INPUT ;
    USE SIGNAL ;
    ANTENNAGATEAREA 0.852800 ;
    ANTENNADIFFAREA 8.061600 ;
    PORT
      LAYER Metal3 ;
        RECT 146.960 751.600 147.360 752.000 ;
    END
  END Tile_X0Y2_W2END[3]
  PIN Tile_X0Y2_W2END[4]
    DIRECTION INPUT ;
    USE SIGNAL ;
    ANTENNAGATEAREA 0.852800 ;
    ANTENNADIFFAREA 8.061600 ;
    PORT
      LAYER Metal3 ;
        RECT 146.960 753.280 147.360 753.680 ;
    END
  END Tile_X0Y2_W2END[4]
  PIN Tile_X0Y2_W2END[5]
    DIRECTION INPUT ;
    USE SIGNAL ;
    ANTENNAGATEAREA 0.852800 ;
    ANTENNADIFFAREA 8.061600 ;
    PORT
      LAYER Metal3 ;
        RECT 146.960 754.960 147.360 755.360 ;
    END
  END Tile_X0Y2_W2END[5]
  PIN Tile_X0Y2_W2END[6]
    DIRECTION INPUT ;
    USE SIGNAL ;
    ANTENNAGATEAREA 0.852800 ;
    ANTENNADIFFAREA 8.061600 ;
    PORT
      LAYER Metal3 ;
        RECT 146.960 756.640 147.360 757.040 ;
    END
  END Tile_X0Y2_W2END[6]
  PIN Tile_X0Y2_W2END[7]
    DIRECTION INPUT ;
    USE SIGNAL ;
    ANTENNAGATEAREA 0.852800 ;
    ANTENNADIFFAREA 8.061600 ;
    PORT
      LAYER Metal3 ;
        RECT 146.960 758.320 147.360 758.720 ;
    END
  END Tile_X0Y2_W2END[7]
  PIN Tile_X0Y2_W2MID[0]
    DIRECTION INPUT ;
    USE SIGNAL ;
    ANTENNAGATEAREA 0.852800 ;
    ANTENNADIFFAREA 8.061600 ;
    PORT
      LAYER Metal3 ;
        RECT 146.960 733.120 147.360 733.520 ;
    END
  END Tile_X0Y2_W2MID[0]
  PIN Tile_X0Y2_W2MID[1]
    DIRECTION INPUT ;
    USE SIGNAL ;
    ANTENNAGATEAREA 0.852800 ;
    ANTENNADIFFAREA 8.061600 ;
    PORT
      LAYER Metal3 ;
        RECT 146.960 734.800 147.360 735.200 ;
    END
  END Tile_X0Y2_W2MID[1]
  PIN Tile_X0Y2_W2MID[2]
    DIRECTION INPUT ;
    USE SIGNAL ;
    ANTENNAGATEAREA 0.852800 ;
    ANTENNADIFFAREA 8.061600 ;
    PORT
      LAYER Metal3 ;
        RECT 146.960 736.480 147.360 736.880 ;
    END
  END Tile_X0Y2_W2MID[2]
  PIN Tile_X0Y2_W2MID[3]
    DIRECTION INPUT ;
    USE SIGNAL ;
    ANTENNAGATEAREA 0.852800 ;
    ANTENNADIFFAREA 8.061600 ;
    PORT
      LAYER Metal3 ;
        RECT 146.960 738.160 147.360 738.560 ;
    END
  END Tile_X0Y2_W2MID[3]
  PIN Tile_X0Y2_W2MID[4]
    DIRECTION INPUT ;
    USE SIGNAL ;
    ANTENNAGATEAREA 0.852800 ;
    ANTENNADIFFAREA 8.061600 ;
    PORT
      LAYER Metal3 ;
        RECT 146.960 739.840 147.360 740.240 ;
    END
  END Tile_X0Y2_W2MID[4]
  PIN Tile_X0Y2_W2MID[5]
    DIRECTION INPUT ;
    USE SIGNAL ;
    ANTENNAGATEAREA 0.852800 ;
    ANTENNADIFFAREA 8.061600 ;
    PORT
      LAYER Metal3 ;
        RECT 146.960 741.520 147.360 741.920 ;
    END
  END Tile_X0Y2_W2MID[5]
  PIN Tile_X0Y2_W2MID[6]
    DIRECTION INPUT ;
    USE SIGNAL ;
    ANTENNAGATEAREA 0.852800 ;
    ANTENNADIFFAREA 8.061600 ;
    PORT
      LAYER Metal3 ;
        RECT 146.960 743.200 147.360 743.600 ;
    END
  END Tile_X0Y2_W2MID[6]
  PIN Tile_X0Y2_W2MID[7]
    DIRECTION INPUT ;
    USE SIGNAL ;
    ANTENNAGATEAREA 0.852800 ;
    ANTENNADIFFAREA 8.061600 ;
    PORT
      LAYER Metal3 ;
        RECT 146.960 744.880 147.360 745.280 ;
    END
  END Tile_X0Y2_W2MID[7]
  PIN Tile_X0Y2_W6END[0]
    DIRECTION INPUT ;
    USE SIGNAL ;
    ANTENNAGATEAREA 0.881400 ;
    ANTENNADIFFAREA 8.061600 ;
    PORT
      LAYER Metal3 ;
        RECT 146.960 786.880 147.360 787.280 ;
    END
  END Tile_X0Y2_W6END[0]
  PIN Tile_X0Y2_W6END[10]
    DIRECTION INPUT ;
    USE SIGNAL ;
    ANTENNAGATEAREA 0.852800 ;
    ANTENNADIFFAREA 8.061600 ;
    PORT
      LAYER Metal3 ;
        RECT 146.960 803.680 147.360 804.080 ;
    END
  END Tile_X0Y2_W6END[10]
  PIN Tile_X0Y2_W6END[11]
    DIRECTION INPUT ;
    USE SIGNAL ;
    ANTENNAGATEAREA 0.852800 ;
    ANTENNADIFFAREA 8.061600 ;
    PORT
      LAYER Metal3 ;
        RECT 146.960 805.360 147.360 805.760 ;
    END
  END Tile_X0Y2_W6END[11]
  PIN Tile_X0Y2_W6END[1]
    DIRECTION INPUT ;
    USE SIGNAL ;
    ANTENNAGATEAREA 0.881400 ;
    ANTENNADIFFAREA 8.061600 ;
    PORT
      LAYER Metal3 ;
        RECT 146.960 788.560 147.360 788.960 ;
    END
  END Tile_X0Y2_W6END[1]
  PIN Tile_X0Y2_W6END[2]
    DIRECTION INPUT ;
    USE SIGNAL ;
    ANTENNAGATEAREA 0.881400 ;
    ANTENNADIFFAREA 8.061600 ;
    PORT
      LAYER Metal3 ;
        RECT 146.960 790.240 147.360 790.640 ;
    END
  END Tile_X0Y2_W6END[2]
  PIN Tile_X0Y2_W6END[3]
    DIRECTION INPUT ;
    USE SIGNAL ;
    ANTENNAGATEAREA 0.881400 ;
    ANTENNADIFFAREA 8.061600 ;
    PORT
      LAYER Metal3 ;
        RECT 146.960 791.920 147.360 792.320 ;
    END
  END Tile_X0Y2_W6END[3]
  PIN Tile_X0Y2_W6END[4]
    DIRECTION INPUT ;
    USE SIGNAL ;
    ANTENNAGATEAREA 1.066000 ;
    ANTENNADIFFAREA 10.077000 ;
    PORT
      LAYER Metal3 ;
        RECT 146.960 793.600 147.360 794.000 ;
    END
  END Tile_X0Y2_W6END[4]
  PIN Tile_X0Y2_W6END[5]
    DIRECTION INPUT ;
    USE SIGNAL ;
    ANTENNAGATEAREA 1.066000 ;
    ANTENNADIFFAREA 10.077000 ;
    PORT
      LAYER Metal3 ;
        RECT 146.960 795.280 147.360 795.680 ;
    END
  END Tile_X0Y2_W6END[5]
  PIN Tile_X0Y2_W6END[6]
    DIRECTION INPUT ;
    USE SIGNAL ;
    ANTENNAGATEAREA 1.066000 ;
    ANTENNADIFFAREA 10.077000 ;
    PORT
      LAYER Metal3 ;
        RECT 146.960 796.960 147.360 797.360 ;
    END
  END Tile_X0Y2_W6END[6]
  PIN Tile_X0Y2_W6END[7]
    DIRECTION INPUT ;
    USE SIGNAL ;
    ANTENNAGATEAREA 1.066000 ;
    ANTENNADIFFAREA 10.077000 ;
    PORT
      LAYER Metal3 ;
        RECT 146.960 798.640 147.360 799.040 ;
    END
  END Tile_X0Y2_W6END[7]
  PIN Tile_X0Y2_W6END[8]
    DIRECTION INPUT ;
    USE SIGNAL ;
    ANTENNAGATEAREA 0.852800 ;
    ANTENNADIFFAREA 8.061600 ;
    PORT
      LAYER Metal3 ;
        RECT 146.960 800.320 147.360 800.720 ;
    END
  END Tile_X0Y2_W6END[8]
  PIN Tile_X0Y2_W6END[9]
    DIRECTION INPUT ;
    USE SIGNAL ;
    ANTENNAGATEAREA 0.852800 ;
    ANTENNADIFFAREA 8.061600 ;
    PORT
      LAYER Metal3 ;
        RECT 146.960 802.000 147.360 802.400 ;
    END
  END Tile_X0Y2_W6END[9]
  PIN Tile_X0Y2_WW4END[0]
    DIRECTION INPUT ;
    USE SIGNAL ;
    ANTENNAGATEAREA 0.852800 ;
    ANTENNADIFFAREA 8.061600 ;
    PORT
      LAYER Metal3 ;
        RECT 146.960 760.000 147.360 760.400 ;
    END
  END Tile_X0Y2_WW4END[0]
  PIN Tile_X0Y2_WW4END[10]
    DIRECTION INPUT ;
    USE SIGNAL ;
    ANTENNAGATEAREA 0.639600 ;
    ANTENNADIFFAREA 6.046200 ;
    PORT
      LAYER Metal3 ;
        RECT 146.960 776.800 147.360 777.200 ;
    END
  END Tile_X0Y2_WW4END[10]
  PIN Tile_X0Y2_WW4END[11]
    DIRECTION INPUT ;
    USE SIGNAL ;
    ANTENNAGATEAREA 0.639600 ;
    ANTENNADIFFAREA 6.046200 ;
    PORT
      LAYER Metal3 ;
        RECT 146.960 778.480 147.360 778.880 ;
    END
  END Tile_X0Y2_WW4END[11]
  PIN Tile_X0Y2_WW4END[12]
    DIRECTION INPUT ;
    USE SIGNAL ;
    ANTENNAGATEAREA 0.852800 ;
    ANTENNADIFFAREA 8.061600 ;
    PORT
      LAYER Metal3 ;
        RECT 146.960 780.160 147.360 780.560 ;
    END
  END Tile_X0Y2_WW4END[12]
  PIN Tile_X0Y2_WW4END[13]
    DIRECTION INPUT ;
    USE SIGNAL ;
    ANTENNAGATEAREA 0.852800 ;
    ANTENNADIFFAREA 8.061600 ;
    PORT
      LAYER Metal3 ;
        RECT 146.960 781.840 147.360 782.240 ;
    END
  END Tile_X0Y2_WW4END[13]
  PIN Tile_X0Y2_WW4END[14]
    DIRECTION INPUT ;
    USE SIGNAL ;
    ANTENNAGATEAREA 0.852800 ;
    ANTENNADIFFAREA 8.061600 ;
    PORT
      LAYER Metal3 ;
        RECT 146.960 783.520 147.360 783.920 ;
    END
  END Tile_X0Y2_WW4END[14]
  PIN Tile_X0Y2_WW4END[15]
    DIRECTION INPUT ;
    USE SIGNAL ;
    ANTENNAGATEAREA 0.852800 ;
    ANTENNADIFFAREA 8.061600 ;
    PORT
      LAYER Metal3 ;
        RECT 146.960 785.200 147.360 785.600 ;
    END
  END Tile_X0Y2_WW4END[15]
  PIN Tile_X0Y2_WW4END[1]
    DIRECTION INPUT ;
    USE SIGNAL ;
    ANTENNAGATEAREA 0.852800 ;
    ANTENNADIFFAREA 8.061600 ;
    PORT
      LAYER Metal3 ;
        RECT 146.960 761.680 147.360 762.080 ;
    END
  END Tile_X0Y2_WW4END[1]
  PIN Tile_X0Y2_WW4END[2]
    DIRECTION INPUT ;
    USE SIGNAL ;
    ANTENNAGATEAREA 0.852800 ;
    ANTENNADIFFAREA 8.061600 ;
    PORT
      LAYER Metal3 ;
        RECT 146.960 763.360 147.360 763.760 ;
    END
  END Tile_X0Y2_WW4END[2]
  PIN Tile_X0Y2_WW4END[3]
    DIRECTION INPUT ;
    USE SIGNAL ;
    ANTENNAGATEAREA 0.852800 ;
    ANTENNADIFFAREA 8.061600 ;
    PORT
      LAYER Metal3 ;
        RECT 146.960 765.040 147.360 765.440 ;
    END
  END Tile_X0Y2_WW4END[3]
  PIN Tile_X0Y2_WW4END[4]
    DIRECTION INPUT ;
    USE SIGNAL ;
    ANTENNAGATEAREA 0.639600 ;
    ANTENNADIFFAREA 6.046200 ;
    PORT
      LAYER Metal3 ;
        RECT 146.960 766.720 147.360 767.120 ;
    END
  END Tile_X0Y2_WW4END[4]
  PIN Tile_X0Y2_WW4END[5]
    DIRECTION INPUT ;
    USE SIGNAL ;
    ANTENNAGATEAREA 0.639600 ;
    ANTENNADIFFAREA 6.046200 ;
    PORT
      LAYER Metal3 ;
        RECT 146.960 768.400 147.360 768.800 ;
    END
  END Tile_X0Y2_WW4END[5]
  PIN Tile_X0Y2_WW4END[6]
    DIRECTION INPUT ;
    USE SIGNAL ;
    ANTENNAGATEAREA 0.639600 ;
    ANTENNADIFFAREA 6.046200 ;
    PORT
      LAYER Metal3 ;
        RECT 146.960 770.080 147.360 770.480 ;
    END
  END Tile_X0Y2_WW4END[6]
  PIN Tile_X0Y2_WW4END[7]
    DIRECTION INPUT ;
    USE SIGNAL ;
    ANTENNAGATEAREA 0.639600 ;
    ANTENNADIFFAREA 6.046200 ;
    PORT
      LAYER Metal3 ;
        RECT 146.960 771.760 147.360 772.160 ;
    END
  END Tile_X0Y2_WW4END[7]
  PIN Tile_X0Y2_WW4END[8]
    DIRECTION INPUT ;
    USE SIGNAL ;
    ANTENNAGATEAREA 0.639600 ;
    ANTENNADIFFAREA 6.046200 ;
    PORT
      LAYER Metal3 ;
        RECT 146.960 773.440 147.360 773.840 ;
    END
  END Tile_X0Y2_WW4END[8]
  PIN Tile_X0Y2_WW4END[9]
    DIRECTION INPUT ;
    USE SIGNAL ;
    ANTENNAGATEAREA 0.639600 ;
    ANTENNADIFFAREA 6.046200 ;
    PORT
      LAYER Metal3 ;
        RECT 146.960 775.120 147.360 775.520 ;
    END
  END Tile_X0Y2_WW4END[9]
  PIN Tile_X0Y3_E1BEG[0]
    DIRECTION OUTPUT ;
    USE SIGNAL ;
    ANTENNADIFFAREA 2.724000 ;
    PORT
      LAYER Metal3 ;
        RECT 146.960 431.980 147.360 432.380 ;
    END
  END Tile_X0Y3_E1BEG[0]
  PIN Tile_X0Y3_E1BEG[1]
    DIRECTION OUTPUT ;
    USE SIGNAL ;
    ANTENNADIFFAREA 2.724000 ;
    PORT
      LAYER Metal3 ;
        RECT 146.960 433.660 147.360 434.060 ;
    END
  END Tile_X0Y3_E1BEG[1]
  PIN Tile_X0Y3_E1BEG[2]
    DIRECTION OUTPUT ;
    USE SIGNAL ;
    ANTENNADIFFAREA 2.724000 ;
    PORT
      LAYER Metal3 ;
        RECT 146.960 435.340 147.360 435.740 ;
    END
  END Tile_X0Y3_E1BEG[2]
  PIN Tile_X0Y3_E1BEG[3]
    DIRECTION OUTPUT ;
    USE SIGNAL ;
    ANTENNADIFFAREA 2.724000 ;
    PORT
      LAYER Metal3 ;
        RECT 146.960 437.020 147.360 437.420 ;
    END
  END Tile_X0Y3_E1BEG[3]
  PIN Tile_X0Y3_E2BEG[0]
    DIRECTION OUTPUT ;
    USE SIGNAL ;
    ANTENNADIFFAREA 2.724000 ;
    PORT
      LAYER Metal3 ;
        RECT 146.960 441.220 147.360 441.620 ;
    END
  END Tile_X0Y3_E2BEG[0]
  PIN Tile_X0Y3_E2BEG[1]
    DIRECTION OUTPUT ;
    USE SIGNAL ;
    ANTENNADIFFAREA 2.724000 ;
    PORT
      LAYER Metal3 ;
        RECT 146.960 442.060 147.360 442.460 ;
    END
  END Tile_X0Y3_E2BEG[1]
  PIN Tile_X0Y3_E2BEG[2]
    DIRECTION OUTPUT ;
    USE SIGNAL ;
    ANTENNADIFFAREA 2.724000 ;
    PORT
      LAYER Metal3 ;
        RECT 146.960 442.900 147.360 443.300 ;
    END
  END Tile_X0Y3_E2BEG[2]
  PIN Tile_X0Y3_E2BEG[3]
    DIRECTION OUTPUT ;
    USE SIGNAL ;
    ANTENNADIFFAREA 2.724000 ;
    PORT
      LAYER Metal3 ;
        RECT 146.960 443.740 147.360 444.140 ;
    END
  END Tile_X0Y3_E2BEG[3]
  PIN Tile_X0Y3_E2BEG[4]
    DIRECTION OUTPUT ;
    USE SIGNAL ;
    ANTENNADIFFAREA 2.724000 ;
    PORT
      LAYER Metal3 ;
        RECT 146.960 444.580 147.360 444.980 ;
    END
  END Tile_X0Y3_E2BEG[4]
  PIN Tile_X0Y3_E2BEG[5]
    DIRECTION OUTPUT ;
    USE SIGNAL ;
    ANTENNADIFFAREA 2.724000 ;
    PORT
      LAYER Metal3 ;
        RECT 146.960 445.420 147.360 445.820 ;
    END
  END Tile_X0Y3_E2BEG[5]
  PIN Tile_X0Y3_E2BEG[6]
    DIRECTION OUTPUT ;
    USE SIGNAL ;
    ANTENNADIFFAREA 2.724000 ;
    PORT
      LAYER Metal3 ;
        RECT 146.960 446.260 147.360 446.660 ;
    END
  END Tile_X0Y3_E2BEG[6]
  PIN Tile_X0Y3_E2BEG[7]
    DIRECTION OUTPUT ;
    USE SIGNAL ;
    ANTENNADIFFAREA 2.724000 ;
    PORT
      LAYER Metal3 ;
        RECT 146.960 447.100 147.360 447.500 ;
    END
  END Tile_X0Y3_E2BEG[7]
  PIN Tile_X0Y3_E2BEGb[0]
    DIRECTION OUTPUT ;
    USE SIGNAL ;
    ANTENNADIFFAREA 2.724000 ;
    PORT
      LAYER Metal3 ;
        RECT 146.960 451.300 147.360 451.700 ;
    END
  END Tile_X0Y3_E2BEGb[0]
  PIN Tile_X0Y3_E2BEGb[1]
    DIRECTION OUTPUT ;
    USE SIGNAL ;
    ANTENNADIFFAREA 2.724000 ;
    PORT
      LAYER Metal3 ;
        RECT 146.960 452.980 147.360 453.380 ;
    END
  END Tile_X0Y3_E2BEGb[1]
  PIN Tile_X0Y3_E2BEGb[2]
    DIRECTION OUTPUT ;
    USE SIGNAL ;
    ANTENNADIFFAREA 2.724000 ;
    PORT
      LAYER Metal3 ;
        RECT 146.960 454.660 147.360 455.060 ;
    END
  END Tile_X0Y3_E2BEGb[2]
  PIN Tile_X0Y3_E2BEGb[3]
    DIRECTION OUTPUT ;
    USE SIGNAL ;
    ANTENNADIFFAREA 2.724000 ;
    PORT
      LAYER Metal3 ;
        RECT 146.960 456.340 147.360 456.740 ;
    END
  END Tile_X0Y3_E2BEGb[3]
  PIN Tile_X0Y3_E2BEGb[4]
    DIRECTION OUTPUT ;
    USE SIGNAL ;
    ANTENNADIFFAREA 2.724000 ;
    PORT
      LAYER Metal3 ;
        RECT 146.960 458.020 147.360 458.420 ;
    END
  END Tile_X0Y3_E2BEGb[4]
  PIN Tile_X0Y3_E2BEGb[5]
    DIRECTION OUTPUT ;
    USE SIGNAL ;
    ANTENNADIFFAREA 2.724000 ;
    PORT
      LAYER Metal3 ;
        RECT 146.960 459.700 147.360 460.100 ;
    END
  END Tile_X0Y3_E2BEGb[5]
  PIN Tile_X0Y3_E2BEGb[6]
    DIRECTION OUTPUT ;
    USE SIGNAL ;
    ANTENNADIFFAREA 2.724000 ;
    PORT
      LAYER Metal3 ;
        RECT 146.960 461.380 147.360 461.780 ;
    END
  END Tile_X0Y3_E2BEGb[6]
  PIN Tile_X0Y3_E2BEGb[7]
    DIRECTION OUTPUT ;
    USE SIGNAL ;
    ANTENNADIFFAREA 2.724000 ;
    PORT
      LAYER Metal3 ;
        RECT 146.960 463.060 147.360 463.460 ;
    END
  END Tile_X0Y3_E2BEGb[7]
  PIN Tile_X0Y3_E6BEG[0]
    DIRECTION OUTPUT ;
    USE SIGNAL ;
    ANTENNADIFFAREA 2.724000 ;
    PORT
      LAYER Metal3 ;
        RECT 146.960 490.780 147.360 491.180 ;
    END
  END Tile_X0Y3_E6BEG[0]
  PIN Tile_X0Y3_E6BEG[10]
    DIRECTION OUTPUT ;
    USE SIGNAL ;
    ANTENNADIFFAREA 2.724000 ;
    PORT
      LAYER Metal3 ;
        RECT 146.960 507.580 147.360 507.980 ;
    END
  END Tile_X0Y3_E6BEG[10]
  PIN Tile_X0Y3_E6BEG[11]
    DIRECTION OUTPUT ;
    USE SIGNAL ;
    ANTENNADIFFAREA 2.724000 ;
    PORT
      LAYER Metal3 ;
        RECT 146.960 509.260 147.360 509.660 ;
    END
  END Tile_X0Y3_E6BEG[11]
  PIN Tile_X0Y3_E6BEG[1]
    DIRECTION OUTPUT ;
    USE SIGNAL ;
    ANTENNADIFFAREA 2.724000 ;
    PORT
      LAYER Metal3 ;
        RECT 146.960 492.460 147.360 492.860 ;
    END
  END Tile_X0Y3_E6BEG[1]
  PIN Tile_X0Y3_E6BEG[2]
    DIRECTION OUTPUT ;
    USE SIGNAL ;
    ANTENNADIFFAREA 2.724000 ;
    PORT
      LAYER Metal3 ;
        RECT 146.960 494.140 147.360 494.540 ;
    END
  END Tile_X0Y3_E6BEG[2]
  PIN Tile_X0Y3_E6BEG[3]
    DIRECTION OUTPUT ;
    USE SIGNAL ;
    ANTENNADIFFAREA 2.724000 ;
    PORT
      LAYER Metal3 ;
        RECT 146.960 495.820 147.360 496.220 ;
    END
  END Tile_X0Y3_E6BEG[3]
  PIN Tile_X0Y3_E6BEG[4]
    DIRECTION OUTPUT ;
    USE SIGNAL ;
    ANTENNADIFFAREA 2.724000 ;
    PORT
      LAYER Metal3 ;
        RECT 146.960 497.500 147.360 497.900 ;
    END
  END Tile_X0Y3_E6BEG[4]
  PIN Tile_X0Y3_E6BEG[5]
    DIRECTION OUTPUT ;
    USE SIGNAL ;
    ANTENNADIFFAREA 2.724000 ;
    PORT
      LAYER Metal3 ;
        RECT 146.960 499.180 147.360 499.580 ;
    END
  END Tile_X0Y3_E6BEG[5]
  PIN Tile_X0Y3_E6BEG[6]
    DIRECTION OUTPUT ;
    USE SIGNAL ;
    ANTENNADIFFAREA 2.724000 ;
    PORT
      LAYER Metal3 ;
        RECT 146.960 500.860 147.360 501.260 ;
    END
  END Tile_X0Y3_E6BEG[6]
  PIN Tile_X0Y3_E6BEG[7]
    DIRECTION OUTPUT ;
    USE SIGNAL ;
    ANTENNADIFFAREA 2.724000 ;
    PORT
      LAYER Metal3 ;
        RECT 146.960 502.540 147.360 502.940 ;
    END
  END Tile_X0Y3_E6BEG[7]
  PIN Tile_X0Y3_E6BEG[8]
    DIRECTION OUTPUT ;
    USE SIGNAL ;
    ANTENNADIFFAREA 2.724000 ;
    PORT
      LAYER Metal3 ;
        RECT 146.960 504.220 147.360 504.620 ;
    END
  END Tile_X0Y3_E6BEG[8]
  PIN Tile_X0Y3_E6BEG[9]
    DIRECTION OUTPUT ;
    USE SIGNAL ;
    ANTENNADIFFAREA 2.724000 ;
    PORT
      LAYER Metal3 ;
        RECT 146.960 505.900 147.360 506.300 ;
    END
  END Tile_X0Y3_E6BEG[9]
  PIN Tile_X0Y3_EE4BEG[0]
    DIRECTION OUTPUT ;
    USE SIGNAL ;
    ANTENNADIFFAREA 2.724000 ;
    PORT
      LAYER Metal3 ;
        RECT 146.960 470.620 147.360 471.020 ;
    END
  END Tile_X0Y3_EE4BEG[0]
  PIN Tile_X0Y3_EE4BEG[10]
    DIRECTION OUTPUT ;
    USE SIGNAL ;
    ANTENNADIFFAREA 2.724000 ;
    PORT
      LAYER Metal3 ;
        RECT 146.960 479.020 147.360 479.420 ;
    END
  END Tile_X0Y3_EE4BEG[10]
  PIN Tile_X0Y3_EE4BEG[11]
    DIRECTION OUTPUT ;
    USE SIGNAL ;
    ANTENNADIFFAREA 2.724000 ;
    PORT
      LAYER Metal3 ;
        RECT 146.960 479.860 147.360 480.260 ;
    END
  END Tile_X0Y3_EE4BEG[11]
  PIN Tile_X0Y3_EE4BEG[12]
    DIRECTION OUTPUT ;
    USE SIGNAL ;
    ANTENNADIFFAREA 2.724000 ;
    PORT
      LAYER Metal3 ;
        RECT 146.960 480.700 147.360 481.100 ;
    END
  END Tile_X0Y3_EE4BEG[12]
  PIN Tile_X0Y3_EE4BEG[13]
    DIRECTION OUTPUT ;
    USE SIGNAL ;
    ANTENNADIFFAREA 2.724000 ;
    PORT
      LAYER Metal3 ;
        RECT 146.960 481.540 147.360 481.940 ;
    END
  END Tile_X0Y3_EE4BEG[13]
  PIN Tile_X0Y3_EE4BEG[14]
    DIRECTION OUTPUT ;
    USE SIGNAL ;
    ANTENNADIFFAREA 2.724000 ;
    PORT
      LAYER Metal3 ;
        RECT 146.960 482.380 147.360 482.780 ;
    END
  END Tile_X0Y3_EE4BEG[14]
  PIN Tile_X0Y3_EE4BEG[15]
    DIRECTION OUTPUT ;
    USE SIGNAL ;
    ANTENNADIFFAREA 2.724000 ;
    PORT
      LAYER Metal3 ;
        RECT 146.960 483.220 147.360 483.620 ;
    END
  END Tile_X0Y3_EE4BEG[15]
  PIN Tile_X0Y3_EE4BEG[1]
    DIRECTION OUTPUT ;
    USE SIGNAL ;
    ANTENNADIFFAREA 2.724000 ;
    PORT
      LAYER Metal3 ;
        RECT 146.960 471.460 147.360 471.860 ;
    END
  END Tile_X0Y3_EE4BEG[1]
  PIN Tile_X0Y3_EE4BEG[2]
    DIRECTION OUTPUT ;
    USE SIGNAL ;
    ANTENNADIFFAREA 2.724000 ;
    PORT
      LAYER Metal3 ;
        RECT 146.960 472.300 147.360 472.700 ;
    END
  END Tile_X0Y3_EE4BEG[2]
  PIN Tile_X0Y3_EE4BEG[3]
    DIRECTION OUTPUT ;
    USE SIGNAL ;
    ANTENNADIFFAREA 2.724000 ;
    PORT
      LAYER Metal3 ;
        RECT 146.960 473.140 147.360 473.540 ;
    END
  END Tile_X0Y3_EE4BEG[3]
  PIN Tile_X0Y3_EE4BEG[4]
    DIRECTION OUTPUT ;
    USE SIGNAL ;
    ANTENNADIFFAREA 2.724000 ;
    PORT
      LAYER Metal3 ;
        RECT 146.960 473.980 147.360 474.380 ;
    END
  END Tile_X0Y3_EE4BEG[4]
  PIN Tile_X0Y3_EE4BEG[5]
    DIRECTION OUTPUT ;
    USE SIGNAL ;
    ANTENNADIFFAREA 2.724000 ;
    PORT
      LAYER Metal3 ;
        RECT 146.960 474.820 147.360 475.220 ;
    END
  END Tile_X0Y3_EE4BEG[5]
  PIN Tile_X0Y3_EE4BEG[6]
    DIRECTION OUTPUT ;
    USE SIGNAL ;
    ANTENNADIFFAREA 2.724000 ;
    PORT
      LAYER Metal3 ;
        RECT 146.960 475.660 147.360 476.060 ;
    END
  END Tile_X0Y3_EE4BEG[6]
  PIN Tile_X0Y3_EE4BEG[7]
    DIRECTION OUTPUT ;
    USE SIGNAL ;
    ANTENNADIFFAREA 2.724000 ;
    PORT
      LAYER Metal3 ;
        RECT 146.960 476.500 147.360 476.900 ;
    END
  END Tile_X0Y3_EE4BEG[7]
  PIN Tile_X0Y3_EE4BEG[8]
    DIRECTION OUTPUT ;
    USE SIGNAL ;
    ANTENNADIFFAREA 2.724000 ;
    PORT
      LAYER Metal3 ;
        RECT 146.960 477.340 147.360 477.740 ;
    END
  END Tile_X0Y3_EE4BEG[8]
  PIN Tile_X0Y3_EE4BEG[9]
    DIRECTION OUTPUT ;
    USE SIGNAL ;
    ANTENNADIFFAREA 2.724000 ;
    PORT
      LAYER Metal3 ;
        RECT 146.960 478.180 147.360 478.580 ;
    END
  END Tile_X0Y3_EE4BEG[9]
  PIN Tile_X0Y3_FrameData[0]
    DIRECTION INPUT ;
    USE SIGNAL ;
    ANTENNAGATEAREA 1.626300 ;
    ANTENNADIFFAREA 18.138599 ;
    PORT
      LAYER Metal3 ;
        RECT 0.000 451.300 0.400 451.700 ;
    END
  END Tile_X0Y3_FrameData[0]
  PIN Tile_X0Y3_FrameData[10]
    DIRECTION INPUT ;
    USE SIGNAL ;
    ANTENNAGATEAREA 1.626300 ;
    ANTENNADIFFAREA 18.138599 ;
    PORT
      LAYER Metal3 ;
        RECT 0.000 510.100 0.400 510.500 ;
    END
  END Tile_X0Y3_FrameData[10]
  PIN Tile_X0Y3_FrameData[11]
    DIRECTION INPUT ;
    USE SIGNAL ;
    ANTENNAGATEAREA 1.626300 ;
    ANTENNADIFFAREA 18.138599 ;
    PORT
      LAYER Metal3 ;
        RECT 0.000 515.980 0.400 516.380 ;
    END
  END Tile_X0Y3_FrameData[11]
  PIN Tile_X0Y3_FrameData[12]
    DIRECTION INPUT ;
    USE SIGNAL ;
    ANTENNAGATEAREA 1.626300 ;
    ANTENNADIFFAREA 18.138599 ;
    PORT
      LAYER Metal3 ;
        RECT 0.000 521.860 0.400 522.260 ;
    END
  END Tile_X0Y3_FrameData[12]
  PIN Tile_X0Y3_FrameData[13]
    DIRECTION INPUT ;
    USE SIGNAL ;
    ANTENNAGATEAREA 1.626300 ;
    ANTENNADIFFAREA 18.138599 ;
    PORT
      LAYER Metal3 ;
        RECT 0.000 527.740 0.400 528.140 ;
    END
  END Tile_X0Y3_FrameData[13]
  PIN Tile_X0Y3_FrameData[14]
    DIRECTION INPUT ;
    USE SIGNAL ;
    ANTENNAGATEAREA 1.626300 ;
    ANTENNADIFFAREA 18.138599 ;
    PORT
      LAYER Metal3 ;
        RECT 0.000 533.620 0.400 534.020 ;
    END
  END Tile_X0Y3_FrameData[14]
  PIN Tile_X0Y3_FrameData[15]
    DIRECTION INPUT ;
    USE SIGNAL ;
    ANTENNAGATEAREA 1.626300 ;
    ANTENNADIFFAREA 18.138599 ;
    PORT
      LAYER Metal3 ;
        RECT 0.000 539.500 0.400 539.900 ;
    END
  END Tile_X0Y3_FrameData[15]
  PIN Tile_X0Y3_FrameData[16]
    DIRECTION INPUT ;
    USE SIGNAL ;
    ANTENNAGATEAREA 1.807000 ;
    ANTENNADIFFAREA 20.153999 ;
    PORT
      LAYER Metal3 ;
        RECT 0.000 545.380 0.400 545.780 ;
    END
  END Tile_X0Y3_FrameData[16]
  PIN Tile_X0Y3_FrameData[17]
    DIRECTION INPUT ;
    USE SIGNAL ;
    ANTENNAGATEAREA 1.807000 ;
    ANTENNADIFFAREA 20.153999 ;
    PORT
      LAYER Metal3 ;
        RECT 0.000 551.260 0.400 551.660 ;
    END
  END Tile_X0Y3_FrameData[17]
  PIN Tile_X0Y3_FrameData[18]
    DIRECTION INPUT ;
    USE SIGNAL ;
    ANTENNAGATEAREA 1.807000 ;
    ANTENNADIFFAREA 20.153999 ;
    PORT
      LAYER Metal3 ;
        RECT 0.000 557.140 0.400 557.540 ;
    END
  END Tile_X0Y3_FrameData[18]
  PIN Tile_X0Y3_FrameData[19]
    DIRECTION INPUT ;
    USE SIGNAL ;
    ANTENNAGATEAREA 1.807000 ;
    ANTENNADIFFAREA 20.153999 ;
    PORT
      LAYER Metal3 ;
        RECT 0.000 563.020 0.400 563.420 ;
    END
  END Tile_X0Y3_FrameData[19]
  PIN Tile_X0Y3_FrameData[1]
    DIRECTION INPUT ;
    USE SIGNAL ;
    ANTENNAGATEAREA 1.626300 ;
    ANTENNADIFFAREA 18.138599 ;
    PORT
      LAYER Metal3 ;
        RECT 0.000 457.180 0.400 457.580 ;
    END
  END Tile_X0Y3_FrameData[1]
  PIN Tile_X0Y3_FrameData[20]
    DIRECTION INPUT ;
    USE SIGNAL ;
    ANTENNAGATEAREA 1.807000 ;
    ANTENNADIFFAREA 20.153999 ;
    PORT
      LAYER Metal3 ;
        RECT 0.000 568.900 0.400 569.300 ;
    END
  END Tile_X0Y3_FrameData[20]
  PIN Tile_X0Y3_FrameData[21]
    DIRECTION INPUT ;
    USE SIGNAL ;
    ANTENNAGATEAREA 1.807000 ;
    ANTENNADIFFAREA 20.153999 ;
    PORT
      LAYER Metal3 ;
        RECT 0.000 574.780 0.400 575.180 ;
    END
  END Tile_X0Y3_FrameData[21]
  PIN Tile_X0Y3_FrameData[22]
    DIRECTION INPUT ;
    USE SIGNAL ;
    ANTENNAGATEAREA 1.807000 ;
    ANTENNADIFFAREA 20.153999 ;
    PORT
      LAYER Metal3 ;
        RECT 0.000 580.660 0.400 581.060 ;
    END
  END Tile_X0Y3_FrameData[22]
  PIN Tile_X0Y3_FrameData[23]
    DIRECTION INPUT ;
    USE SIGNAL ;
    ANTENNAGATEAREA 1.807000 ;
    ANTENNADIFFAREA 20.153999 ;
    PORT
      LAYER Metal3 ;
        RECT 0.000 586.540 0.400 586.940 ;
    END
  END Tile_X0Y3_FrameData[23]
  PIN Tile_X0Y3_FrameData[24]
    DIRECTION INPUT ;
    USE SIGNAL ;
    ANTENNAGATEAREA 1.807000 ;
    ANTENNADIFFAREA 20.153999 ;
    PORT
      LAYER Metal3 ;
        RECT 0.000 592.420 0.400 592.820 ;
    END
  END Tile_X0Y3_FrameData[24]
  PIN Tile_X0Y3_FrameData[25]
    DIRECTION INPUT ;
    USE SIGNAL ;
    ANTENNAGATEAREA 1.807000 ;
    ANTENNADIFFAREA 20.153999 ;
    PORT
      LAYER Metal3 ;
        RECT 0.000 598.300 0.400 598.700 ;
    END
  END Tile_X0Y3_FrameData[25]
  PIN Tile_X0Y3_FrameData[26]
    DIRECTION INPUT ;
    USE SIGNAL ;
    ANTENNAGATEAREA 1.807000 ;
    ANTENNADIFFAREA 20.153999 ;
    PORT
      LAYER Metal3 ;
        RECT 0.000 604.180 0.400 604.580 ;
    END
  END Tile_X0Y3_FrameData[26]
  PIN Tile_X0Y3_FrameData[27]
    DIRECTION INPUT ;
    USE SIGNAL ;
    ANTENNAGATEAREA 1.807000 ;
    ANTENNADIFFAREA 20.153999 ;
    PORT
      LAYER Metal3 ;
        RECT 0.000 610.060 0.400 610.460 ;
    END
  END Tile_X0Y3_FrameData[27]
  PIN Tile_X0Y3_FrameData[28]
    DIRECTION INPUT ;
    USE SIGNAL ;
    ANTENNAGATEAREA 1.807000 ;
    ANTENNADIFFAREA 20.153999 ;
    PORT
      LAYER Metal3 ;
        RECT 0.000 615.940 0.400 616.340 ;
    END
  END Tile_X0Y3_FrameData[28]
  PIN Tile_X0Y3_FrameData[29]
    DIRECTION INPUT ;
    USE SIGNAL ;
    ANTENNAGATEAREA 1.807000 ;
    ANTENNADIFFAREA 20.153999 ;
    PORT
      LAYER Metal3 ;
        RECT 0.000 621.820 0.400 622.220 ;
    END
  END Tile_X0Y3_FrameData[29]
  PIN Tile_X0Y3_FrameData[2]
    DIRECTION INPUT ;
    USE SIGNAL ;
    ANTENNAGATEAREA 1.626300 ;
    ANTENNADIFFAREA 18.138599 ;
    PORT
      LAYER Metal3 ;
        RECT 0.000 463.060 0.400 463.460 ;
    END
  END Tile_X0Y3_FrameData[2]
  PIN Tile_X0Y3_FrameData[30]
    DIRECTION INPUT ;
    USE SIGNAL ;
    ANTENNAGATEAREA 1.807000 ;
    ANTENNADIFFAREA 20.153999 ;
    PORT
      LAYER Metal3 ;
        RECT 0.000 627.700 0.400 628.100 ;
    END
  END Tile_X0Y3_FrameData[30]
  PIN Tile_X0Y3_FrameData[31]
    DIRECTION INPUT ;
    USE SIGNAL ;
    ANTENNAGATEAREA 1.807000 ;
    ANTENNADIFFAREA 20.153999 ;
    PORT
      LAYER Metal3 ;
        RECT 0.000 633.580 0.400 633.980 ;
    END
  END Tile_X0Y3_FrameData[31]
  PIN Tile_X0Y3_FrameData[3]
    DIRECTION INPUT ;
    USE SIGNAL ;
    ANTENNAGATEAREA 1.626300 ;
    ANTENNADIFFAREA 18.138599 ;
    PORT
      LAYER Metal3 ;
        RECT 0.000 468.940 0.400 469.340 ;
    END
  END Tile_X0Y3_FrameData[3]
  PIN Tile_X0Y3_FrameData[4]
    DIRECTION INPUT ;
    USE SIGNAL ;
    ANTENNAGATEAREA 1.626300 ;
    ANTENNADIFFAREA 18.138599 ;
    PORT
      LAYER Metal3 ;
        RECT 0.000 474.820 0.400 475.220 ;
    END
  END Tile_X0Y3_FrameData[4]
  PIN Tile_X0Y3_FrameData[5]
    DIRECTION INPUT ;
    USE SIGNAL ;
    ANTENNAGATEAREA 1.626300 ;
    ANTENNADIFFAREA 18.138599 ;
    PORT
      LAYER Metal3 ;
        RECT 0.000 480.700 0.400 481.100 ;
    END
  END Tile_X0Y3_FrameData[5]
  PIN Tile_X0Y3_FrameData[6]
    DIRECTION INPUT ;
    USE SIGNAL ;
    ANTENNAGATEAREA 1.626300 ;
    ANTENNADIFFAREA 18.138599 ;
    PORT
      LAYER Metal3 ;
        RECT 0.000 486.580 0.400 486.980 ;
    END
  END Tile_X0Y3_FrameData[6]
  PIN Tile_X0Y3_FrameData[7]
    DIRECTION INPUT ;
    USE SIGNAL ;
    ANTENNAGATEAREA 1.626300 ;
    ANTENNADIFFAREA 18.138599 ;
    PORT
      LAYER Metal3 ;
        RECT 0.000 492.460 0.400 492.860 ;
    END
  END Tile_X0Y3_FrameData[7]
  PIN Tile_X0Y3_FrameData[8]
    DIRECTION INPUT ;
    USE SIGNAL ;
    ANTENNAGATEAREA 1.626300 ;
    ANTENNADIFFAREA 18.138599 ;
    PORT
      LAYER Metal3 ;
        RECT 0.000 498.340 0.400 498.740 ;
    END
  END Tile_X0Y3_FrameData[8]
  PIN Tile_X0Y3_FrameData[9]
    DIRECTION INPUT ;
    USE SIGNAL ;
    ANTENNAGATEAREA 1.626300 ;
    ANTENNADIFFAREA 18.138599 ;
    PORT
      LAYER Metal3 ;
        RECT 0.000 504.220 0.400 504.620 ;
    END
  END Tile_X0Y3_FrameData[9]
  PIN Tile_X0Y3_FrameData_O[0]
    DIRECTION OUTPUT ;
    USE SIGNAL ;
    ANTENNADIFFAREA 2.724000 ;
    PORT
      LAYER Metal3 ;
        RECT 146.960 593.260 147.360 593.660 ;
    END
  END Tile_X0Y3_FrameData_O[0]
  PIN Tile_X0Y3_FrameData_O[10]
    DIRECTION OUTPUT ;
    USE SIGNAL ;
    ANTENNADIFFAREA 2.724000 ;
    PORT
      LAYER Metal3 ;
        RECT 146.960 610.060 147.360 610.460 ;
    END
  END Tile_X0Y3_FrameData_O[10]
  PIN Tile_X0Y3_FrameData_O[11]
    DIRECTION OUTPUT ;
    USE SIGNAL ;
    ANTENNADIFFAREA 2.724000 ;
    PORT
      LAYER Metal3 ;
        RECT 146.960 611.740 147.360 612.140 ;
    END
  END Tile_X0Y3_FrameData_O[11]
  PIN Tile_X0Y3_FrameData_O[12]
    DIRECTION OUTPUT ;
    USE SIGNAL ;
    ANTENNADIFFAREA 2.724000 ;
    PORT
      LAYER Metal3 ;
        RECT 146.960 613.420 147.360 613.820 ;
    END
  END Tile_X0Y3_FrameData_O[12]
  PIN Tile_X0Y3_FrameData_O[13]
    DIRECTION OUTPUT ;
    USE SIGNAL ;
    ANTENNADIFFAREA 2.724000 ;
    PORT
      LAYER Metal3 ;
        RECT 146.960 615.100 147.360 615.500 ;
    END
  END Tile_X0Y3_FrameData_O[13]
  PIN Tile_X0Y3_FrameData_O[14]
    DIRECTION OUTPUT ;
    USE SIGNAL ;
    ANTENNADIFFAREA 2.724000 ;
    PORT
      LAYER Metal3 ;
        RECT 146.960 616.780 147.360 617.180 ;
    END
  END Tile_X0Y3_FrameData_O[14]
  PIN Tile_X0Y3_FrameData_O[15]
    DIRECTION OUTPUT ;
    USE SIGNAL ;
    ANTENNADIFFAREA 2.724000 ;
    PORT
      LAYER Metal3 ;
        RECT 146.960 618.460 147.360 618.860 ;
    END
  END Tile_X0Y3_FrameData_O[15]
  PIN Tile_X0Y3_FrameData_O[16]
    DIRECTION OUTPUT ;
    USE SIGNAL ;
    ANTENNADIFFAREA 2.724000 ;
    PORT
      LAYER Metal3 ;
        RECT 146.960 620.140 147.360 620.540 ;
    END
  END Tile_X0Y3_FrameData_O[16]
  PIN Tile_X0Y3_FrameData_O[17]
    DIRECTION OUTPUT ;
    USE SIGNAL ;
    ANTENNADIFFAREA 2.724000 ;
    PORT
      LAYER Metal3 ;
        RECT 146.960 621.820 147.360 622.220 ;
    END
  END Tile_X0Y3_FrameData_O[17]
  PIN Tile_X0Y3_FrameData_O[18]
    DIRECTION OUTPUT ;
    USE SIGNAL ;
    ANTENNADIFFAREA 2.724000 ;
    PORT
      LAYER Metal3 ;
        RECT 146.960 623.500 147.360 623.900 ;
    END
  END Tile_X0Y3_FrameData_O[18]
  PIN Tile_X0Y3_FrameData_O[19]
    DIRECTION OUTPUT ;
    USE SIGNAL ;
    ANTENNADIFFAREA 2.724000 ;
    PORT
      LAYER Metal3 ;
        RECT 146.960 625.180 147.360 625.580 ;
    END
  END Tile_X0Y3_FrameData_O[19]
  PIN Tile_X0Y3_FrameData_O[1]
    DIRECTION OUTPUT ;
    USE SIGNAL ;
    ANTENNADIFFAREA 2.724000 ;
    PORT
      LAYER Metal3 ;
        RECT 146.960 594.940 147.360 595.340 ;
    END
  END Tile_X0Y3_FrameData_O[1]
  PIN Tile_X0Y3_FrameData_O[20]
    DIRECTION OUTPUT ;
    USE SIGNAL ;
    ANTENNADIFFAREA 2.724000 ;
    PORT
      LAYER Metal3 ;
        RECT 146.960 626.860 147.360 627.260 ;
    END
  END Tile_X0Y3_FrameData_O[20]
  PIN Tile_X0Y3_FrameData_O[21]
    DIRECTION OUTPUT ;
    USE SIGNAL ;
    ANTENNADIFFAREA 2.724000 ;
    PORT
      LAYER Metal3 ;
        RECT 146.960 628.540 147.360 628.940 ;
    END
  END Tile_X0Y3_FrameData_O[21]
  PIN Tile_X0Y3_FrameData_O[22]
    DIRECTION OUTPUT ;
    USE SIGNAL ;
    ANTENNADIFFAREA 2.724000 ;
    PORT
      LAYER Metal3 ;
        RECT 146.960 630.220 147.360 630.620 ;
    END
  END Tile_X0Y3_FrameData_O[22]
  PIN Tile_X0Y3_FrameData_O[23]
    DIRECTION OUTPUT ;
    USE SIGNAL ;
    ANTENNADIFFAREA 2.724000 ;
    PORT
      LAYER Metal3 ;
        RECT 146.960 631.900 147.360 632.300 ;
    END
  END Tile_X0Y3_FrameData_O[23]
  PIN Tile_X0Y3_FrameData_O[24]
    DIRECTION OUTPUT ;
    USE SIGNAL ;
    ANTENNADIFFAREA 2.724000 ;
    PORT
      LAYER Metal3 ;
        RECT 146.960 633.580 147.360 633.980 ;
    END
  END Tile_X0Y3_FrameData_O[24]
  PIN Tile_X0Y3_FrameData_O[25]
    DIRECTION OUTPUT ;
    USE SIGNAL ;
    ANTENNADIFFAREA 2.724000 ;
    PORT
      LAYER Metal3 ;
        RECT 146.960 635.260 147.360 635.660 ;
    END
  END Tile_X0Y3_FrameData_O[25]
  PIN Tile_X0Y3_FrameData_O[26]
    DIRECTION OUTPUT ;
    USE SIGNAL ;
    ANTENNADIFFAREA 2.724000 ;
    PORT
      LAYER Metal3 ;
        RECT 146.960 636.940 147.360 637.340 ;
    END
  END Tile_X0Y3_FrameData_O[26]
  PIN Tile_X0Y3_FrameData_O[27]
    DIRECTION OUTPUT ;
    USE SIGNAL ;
    ANTENNADIFFAREA 2.724000 ;
    PORT
      LAYER Metal3 ;
        RECT 146.960 638.620 147.360 639.020 ;
    END
  END Tile_X0Y3_FrameData_O[27]
  PIN Tile_X0Y3_FrameData_O[28]
    DIRECTION OUTPUT ;
    USE SIGNAL ;
    ANTENNADIFFAREA 2.724000 ;
    PORT
      LAYER Metal3 ;
        RECT 146.960 640.300 147.360 640.700 ;
    END
  END Tile_X0Y3_FrameData_O[28]
  PIN Tile_X0Y3_FrameData_O[29]
    DIRECTION OUTPUT ;
    USE SIGNAL ;
    ANTENNADIFFAREA 2.724000 ;
    PORT
      LAYER Metal3 ;
        RECT 146.960 641.980 147.360 642.380 ;
    END
  END Tile_X0Y3_FrameData_O[29]
  PIN Tile_X0Y3_FrameData_O[2]
    DIRECTION OUTPUT ;
    USE SIGNAL ;
    ANTENNADIFFAREA 2.724000 ;
    PORT
      LAYER Metal3 ;
        RECT 146.960 596.620 147.360 597.020 ;
    END
  END Tile_X0Y3_FrameData_O[2]
  PIN Tile_X0Y3_FrameData_O[30]
    DIRECTION OUTPUT ;
    USE SIGNAL ;
    ANTENNADIFFAREA 2.724000 ;
    PORT
      LAYER Metal3 ;
        RECT 146.960 643.660 147.360 644.060 ;
    END
  END Tile_X0Y3_FrameData_O[30]
  PIN Tile_X0Y3_FrameData_O[31]
    DIRECTION OUTPUT ;
    USE SIGNAL ;
    ANTENNADIFFAREA 2.724000 ;
    PORT
      LAYER Metal3 ;
        RECT 146.960 645.340 147.360 645.740 ;
    END
  END Tile_X0Y3_FrameData_O[31]
  PIN Tile_X0Y3_FrameData_O[3]
    DIRECTION OUTPUT ;
    USE SIGNAL ;
    ANTENNADIFFAREA 2.724000 ;
    PORT
      LAYER Metal3 ;
        RECT 146.960 598.300 147.360 598.700 ;
    END
  END Tile_X0Y3_FrameData_O[3]
  PIN Tile_X0Y3_FrameData_O[4]
    DIRECTION OUTPUT ;
    USE SIGNAL ;
    ANTENNADIFFAREA 2.724000 ;
    PORT
      LAYER Metal3 ;
        RECT 146.960 599.980 147.360 600.380 ;
    END
  END Tile_X0Y3_FrameData_O[4]
  PIN Tile_X0Y3_FrameData_O[5]
    DIRECTION OUTPUT ;
    USE SIGNAL ;
    ANTENNADIFFAREA 2.724000 ;
    PORT
      LAYER Metal3 ;
        RECT 146.960 601.660 147.360 602.060 ;
    END
  END Tile_X0Y3_FrameData_O[5]
  PIN Tile_X0Y3_FrameData_O[6]
    DIRECTION OUTPUT ;
    USE SIGNAL ;
    ANTENNADIFFAREA 2.724000 ;
    PORT
      LAYER Metal3 ;
        RECT 146.960 603.340 147.360 603.740 ;
    END
  END Tile_X0Y3_FrameData_O[6]
  PIN Tile_X0Y3_FrameData_O[7]
    DIRECTION OUTPUT ;
    USE SIGNAL ;
    ANTENNADIFFAREA 2.724000 ;
    PORT
      LAYER Metal3 ;
        RECT 146.960 605.020 147.360 605.420 ;
    END
  END Tile_X0Y3_FrameData_O[7]
  PIN Tile_X0Y3_FrameData_O[8]
    DIRECTION OUTPUT ;
    USE SIGNAL ;
    ANTENNADIFFAREA 2.724000 ;
    PORT
      LAYER Metal3 ;
        RECT 146.960 606.700 147.360 607.100 ;
    END
  END Tile_X0Y3_FrameData_O[8]
  PIN Tile_X0Y3_FrameData_O[9]
    DIRECTION OUTPUT ;
    USE SIGNAL ;
    ANTENNADIFFAREA 2.724000 ;
    PORT
      LAYER Metal3 ;
        RECT 146.960 608.380 147.360 608.780 ;
    END
  END Tile_X0Y3_FrameData_O[9]
  PIN Tile_X0Y3_UserCLK
    DIRECTION INPUT ;
    USE SIGNAL ;
    ANTENNAGATEAREA 0.180700 ;
    ANTENNADIFFAREA 2.015400 ;
    PORT
      LAYER Metal3 ;
        RECT 0.000 434.500 0.400 434.900 ;
    END
  END Tile_X0Y3_UserCLK
  PIN Tile_X0Y3_UserCLKo
    DIRECTION OUTPUT ;
    USE SIGNAL ;
    ANTENNADIFFAREA 2.724000 ;
    PORT
      LAYER Metal3 ;
        RECT 146.960 591.580 147.360 591.980 ;
    END
  END Tile_X0Y3_UserCLKo
  PIN Tile_X0Y3_W1END[0]
    DIRECTION INPUT ;
    USE SIGNAL ;
    ANTENNAGATEAREA 1.279200 ;
    ANTENNADIFFAREA 12.092400 ;
    PORT
      LAYER Metal3 ;
        RECT 146.960 510.940 147.360 511.340 ;
    END
  END Tile_X0Y3_W1END[0]
  PIN Tile_X0Y3_W1END[1]
    DIRECTION INPUT ;
    USE SIGNAL ;
    ANTENNAGATEAREA 1.279200 ;
    ANTENNADIFFAREA 12.092400 ;
    PORT
      LAYER Metal3 ;
        RECT 146.960 512.620 147.360 513.020 ;
    END
  END Tile_X0Y3_W1END[1]
  PIN Tile_X0Y3_W1END[2]
    DIRECTION INPUT ;
    USE SIGNAL ;
    ANTENNAGATEAREA 1.279200 ;
    ANTENNADIFFAREA 12.092400 ;
    PORT
      LAYER Metal3 ;
        RECT 146.960 514.300 147.360 514.700 ;
    END
  END Tile_X0Y3_W1END[2]
  PIN Tile_X0Y3_W1END[3]
    DIRECTION INPUT ;
    USE SIGNAL ;
    ANTENNAGATEAREA 1.279200 ;
    ANTENNADIFFAREA 12.092400 ;
    PORT
      LAYER Metal3 ;
        RECT 146.960 515.980 147.360 516.380 ;
    END
  END Tile_X0Y3_W1END[3]
  PIN Tile_X0Y3_W2END[0]
    DIRECTION INPUT ;
    USE SIGNAL ;
    ANTENNAGATEAREA 0.852800 ;
    ANTENNADIFFAREA 8.061600 ;
    PORT
      LAYER Metal3 ;
        RECT 146.960 531.100 147.360 531.500 ;
    END
  END Tile_X0Y3_W2END[0]
  PIN Tile_X0Y3_W2END[1]
    DIRECTION INPUT ;
    USE SIGNAL ;
    ANTENNAGATEAREA 0.852800 ;
    ANTENNADIFFAREA 8.061600 ;
    PORT
      LAYER Metal3 ;
        RECT 146.960 532.780 147.360 533.180 ;
    END
  END Tile_X0Y3_W2END[1]
  PIN Tile_X0Y3_W2END[2]
    DIRECTION INPUT ;
    USE SIGNAL ;
    ANTENNAGATEAREA 0.852800 ;
    ANTENNADIFFAREA 8.061600 ;
    PORT
      LAYER Metal3 ;
        RECT 146.960 534.460 147.360 534.860 ;
    END
  END Tile_X0Y3_W2END[2]
  PIN Tile_X0Y3_W2END[3]
    DIRECTION INPUT ;
    USE SIGNAL ;
    ANTENNAGATEAREA 0.852800 ;
    ANTENNADIFFAREA 8.061600 ;
    PORT
      LAYER Metal3 ;
        RECT 146.960 536.140 147.360 536.540 ;
    END
  END Tile_X0Y3_W2END[3]
  PIN Tile_X0Y3_W2END[4]
    DIRECTION INPUT ;
    USE SIGNAL ;
    ANTENNAGATEAREA 0.852800 ;
    ANTENNADIFFAREA 8.061600 ;
    PORT
      LAYER Metal3 ;
        RECT 146.960 537.820 147.360 538.220 ;
    END
  END Tile_X0Y3_W2END[4]
  PIN Tile_X0Y3_W2END[5]
    DIRECTION INPUT ;
    USE SIGNAL ;
    ANTENNAGATEAREA 0.852800 ;
    ANTENNADIFFAREA 8.061600 ;
    PORT
      LAYER Metal3 ;
        RECT 146.960 539.500 147.360 539.900 ;
    END
  END Tile_X0Y3_W2END[5]
  PIN Tile_X0Y3_W2END[6]
    DIRECTION INPUT ;
    USE SIGNAL ;
    ANTENNAGATEAREA 0.852800 ;
    ANTENNADIFFAREA 8.061600 ;
    PORT
      LAYER Metal3 ;
        RECT 146.960 541.180 147.360 541.580 ;
    END
  END Tile_X0Y3_W2END[6]
  PIN Tile_X0Y3_W2END[7]
    DIRECTION INPUT ;
    USE SIGNAL ;
    ANTENNAGATEAREA 0.852800 ;
    ANTENNADIFFAREA 8.061600 ;
    PORT
      LAYER Metal3 ;
        RECT 146.960 542.860 147.360 543.260 ;
    END
  END Tile_X0Y3_W2END[7]
  PIN Tile_X0Y3_W2MID[0]
    DIRECTION INPUT ;
    USE SIGNAL ;
    ANTENNAGATEAREA 0.852800 ;
    ANTENNADIFFAREA 8.061600 ;
    PORT
      LAYER Metal3 ;
        RECT 146.960 517.660 147.360 518.060 ;
    END
  END Tile_X0Y3_W2MID[0]
  PIN Tile_X0Y3_W2MID[1]
    DIRECTION INPUT ;
    USE SIGNAL ;
    ANTENNAGATEAREA 0.852800 ;
    ANTENNADIFFAREA 8.061600 ;
    PORT
      LAYER Metal3 ;
        RECT 146.960 519.340 147.360 519.740 ;
    END
  END Tile_X0Y3_W2MID[1]
  PIN Tile_X0Y3_W2MID[2]
    DIRECTION INPUT ;
    USE SIGNAL ;
    ANTENNAGATEAREA 0.852800 ;
    ANTENNADIFFAREA 8.061600 ;
    PORT
      LAYER Metal3 ;
        RECT 146.960 521.020 147.360 521.420 ;
    END
  END Tile_X0Y3_W2MID[2]
  PIN Tile_X0Y3_W2MID[3]
    DIRECTION INPUT ;
    USE SIGNAL ;
    ANTENNAGATEAREA 0.852800 ;
    ANTENNADIFFAREA 8.061600 ;
    PORT
      LAYER Metal3 ;
        RECT 146.960 522.700 147.360 523.100 ;
    END
  END Tile_X0Y3_W2MID[3]
  PIN Tile_X0Y3_W2MID[4]
    DIRECTION INPUT ;
    USE SIGNAL ;
    ANTENNAGATEAREA 0.852800 ;
    ANTENNADIFFAREA 8.061600 ;
    PORT
      LAYER Metal3 ;
        RECT 146.960 524.380 147.360 524.780 ;
    END
  END Tile_X0Y3_W2MID[4]
  PIN Tile_X0Y3_W2MID[5]
    DIRECTION INPUT ;
    USE SIGNAL ;
    ANTENNAGATEAREA 0.852800 ;
    ANTENNADIFFAREA 8.061600 ;
    PORT
      LAYER Metal3 ;
        RECT 146.960 526.060 147.360 526.460 ;
    END
  END Tile_X0Y3_W2MID[5]
  PIN Tile_X0Y3_W2MID[6]
    DIRECTION INPUT ;
    USE SIGNAL ;
    ANTENNAGATEAREA 0.852800 ;
    ANTENNADIFFAREA 8.061600 ;
    PORT
      LAYER Metal3 ;
        RECT 146.960 527.740 147.360 528.140 ;
    END
  END Tile_X0Y3_W2MID[6]
  PIN Tile_X0Y3_W2MID[7]
    DIRECTION INPUT ;
    USE SIGNAL ;
    ANTENNAGATEAREA 0.852800 ;
    ANTENNADIFFAREA 8.061600 ;
    PORT
      LAYER Metal3 ;
        RECT 146.960 529.420 147.360 529.820 ;
    END
  END Tile_X0Y3_W2MID[7]
  PIN Tile_X0Y3_W6END[0]
    DIRECTION INPUT ;
    USE SIGNAL ;
    ANTENNAGATEAREA 0.881400 ;
    ANTENNADIFFAREA 8.061600 ;
    PORT
      LAYER Metal3 ;
        RECT 146.960 571.420 147.360 571.820 ;
    END
  END Tile_X0Y3_W6END[0]
  PIN Tile_X0Y3_W6END[10]
    DIRECTION INPUT ;
    USE SIGNAL ;
    ANTENNAGATEAREA 0.852800 ;
    ANTENNADIFFAREA 8.061600 ;
    PORT
      LAYER Metal3 ;
        RECT 146.960 588.220 147.360 588.620 ;
    END
  END Tile_X0Y3_W6END[10]
  PIN Tile_X0Y3_W6END[11]
    DIRECTION INPUT ;
    USE SIGNAL ;
    ANTENNAGATEAREA 0.852800 ;
    ANTENNADIFFAREA 8.061600 ;
    PORT
      LAYER Metal3 ;
        RECT 146.960 589.900 147.360 590.300 ;
    END
  END Tile_X0Y3_W6END[11]
  PIN Tile_X0Y3_W6END[1]
    DIRECTION INPUT ;
    USE SIGNAL ;
    ANTENNAGATEAREA 0.881400 ;
    ANTENNADIFFAREA 8.061600 ;
    PORT
      LAYER Metal3 ;
        RECT 146.960 573.100 147.360 573.500 ;
    END
  END Tile_X0Y3_W6END[1]
  PIN Tile_X0Y3_W6END[2]
    DIRECTION INPUT ;
    USE SIGNAL ;
    ANTENNAGATEAREA 0.881400 ;
    ANTENNADIFFAREA 8.061600 ;
    PORT
      LAYER Metal3 ;
        RECT 146.960 574.780 147.360 575.180 ;
    END
  END Tile_X0Y3_W6END[2]
  PIN Tile_X0Y3_W6END[3]
    DIRECTION INPUT ;
    USE SIGNAL ;
    ANTENNAGATEAREA 0.881400 ;
    ANTENNADIFFAREA 8.061600 ;
    PORT
      LAYER Metal3 ;
        RECT 146.960 576.460 147.360 576.860 ;
    END
  END Tile_X0Y3_W6END[3]
  PIN Tile_X0Y3_W6END[4]
    DIRECTION INPUT ;
    USE SIGNAL ;
    ANTENNAGATEAREA 1.066000 ;
    ANTENNADIFFAREA 10.077000 ;
    PORT
      LAYER Metal3 ;
        RECT 146.960 578.140 147.360 578.540 ;
    END
  END Tile_X0Y3_W6END[4]
  PIN Tile_X0Y3_W6END[5]
    DIRECTION INPUT ;
    USE SIGNAL ;
    ANTENNAGATEAREA 1.066000 ;
    ANTENNADIFFAREA 10.077000 ;
    PORT
      LAYER Metal3 ;
        RECT 146.960 579.820 147.360 580.220 ;
    END
  END Tile_X0Y3_W6END[5]
  PIN Tile_X0Y3_W6END[6]
    DIRECTION INPUT ;
    USE SIGNAL ;
    ANTENNAGATEAREA 1.066000 ;
    ANTENNADIFFAREA 10.077000 ;
    PORT
      LAYER Metal3 ;
        RECT 146.960 581.500 147.360 581.900 ;
    END
  END Tile_X0Y3_W6END[6]
  PIN Tile_X0Y3_W6END[7]
    DIRECTION INPUT ;
    USE SIGNAL ;
    ANTENNAGATEAREA 1.066000 ;
    ANTENNADIFFAREA 10.077000 ;
    PORT
      LAYER Metal3 ;
        RECT 146.960 583.180 147.360 583.580 ;
    END
  END Tile_X0Y3_W6END[7]
  PIN Tile_X0Y3_W6END[8]
    DIRECTION INPUT ;
    USE SIGNAL ;
    ANTENNAGATEAREA 0.852800 ;
    ANTENNADIFFAREA 8.061600 ;
    PORT
      LAYER Metal3 ;
        RECT 146.960 584.860 147.360 585.260 ;
    END
  END Tile_X0Y3_W6END[8]
  PIN Tile_X0Y3_W6END[9]
    DIRECTION INPUT ;
    USE SIGNAL ;
    ANTENNAGATEAREA 0.852800 ;
    ANTENNADIFFAREA 8.061600 ;
    PORT
      LAYER Metal3 ;
        RECT 146.960 586.540 147.360 586.940 ;
    END
  END Tile_X0Y3_W6END[9]
  PIN Tile_X0Y3_WW4END[0]
    DIRECTION INPUT ;
    USE SIGNAL ;
    ANTENNAGATEAREA 0.852800 ;
    ANTENNADIFFAREA 8.061600 ;
    PORT
      LAYER Metal3 ;
        RECT 146.960 544.540 147.360 544.940 ;
    END
  END Tile_X0Y3_WW4END[0]
  PIN Tile_X0Y3_WW4END[10]
    DIRECTION INPUT ;
    USE SIGNAL ;
    ANTENNAGATEAREA 0.639600 ;
    ANTENNADIFFAREA 6.046200 ;
    PORT
      LAYER Metal3 ;
        RECT 146.960 561.340 147.360 561.740 ;
    END
  END Tile_X0Y3_WW4END[10]
  PIN Tile_X0Y3_WW4END[11]
    DIRECTION INPUT ;
    USE SIGNAL ;
    ANTENNAGATEAREA 0.639600 ;
    ANTENNADIFFAREA 6.046200 ;
    PORT
      LAYER Metal3 ;
        RECT 146.960 563.020 147.360 563.420 ;
    END
  END Tile_X0Y3_WW4END[11]
  PIN Tile_X0Y3_WW4END[12]
    DIRECTION INPUT ;
    USE SIGNAL ;
    ANTENNAGATEAREA 0.852800 ;
    ANTENNADIFFAREA 8.061600 ;
    PORT
      LAYER Metal3 ;
        RECT 146.960 564.700 147.360 565.100 ;
    END
  END Tile_X0Y3_WW4END[12]
  PIN Tile_X0Y3_WW4END[13]
    DIRECTION INPUT ;
    USE SIGNAL ;
    ANTENNAGATEAREA 0.852800 ;
    ANTENNADIFFAREA 8.061600 ;
    PORT
      LAYER Metal3 ;
        RECT 146.960 566.380 147.360 566.780 ;
    END
  END Tile_X0Y3_WW4END[13]
  PIN Tile_X0Y3_WW4END[14]
    DIRECTION INPUT ;
    USE SIGNAL ;
    ANTENNAGATEAREA 0.852800 ;
    ANTENNADIFFAREA 8.061600 ;
    PORT
      LAYER Metal3 ;
        RECT 146.960 568.060 147.360 568.460 ;
    END
  END Tile_X0Y3_WW4END[14]
  PIN Tile_X0Y3_WW4END[15]
    DIRECTION INPUT ;
    USE SIGNAL ;
    ANTENNAGATEAREA 0.852800 ;
    ANTENNADIFFAREA 8.061600 ;
    PORT
      LAYER Metal3 ;
        RECT 146.960 569.740 147.360 570.140 ;
    END
  END Tile_X0Y3_WW4END[15]
  PIN Tile_X0Y3_WW4END[1]
    DIRECTION INPUT ;
    USE SIGNAL ;
    ANTENNAGATEAREA 0.852800 ;
    ANTENNADIFFAREA 8.061600 ;
    PORT
      LAYER Metal3 ;
        RECT 146.960 546.220 147.360 546.620 ;
    END
  END Tile_X0Y3_WW4END[1]
  PIN Tile_X0Y3_WW4END[2]
    DIRECTION INPUT ;
    USE SIGNAL ;
    ANTENNAGATEAREA 0.852800 ;
    ANTENNADIFFAREA 8.061600 ;
    PORT
      LAYER Metal3 ;
        RECT 146.960 547.900 147.360 548.300 ;
    END
  END Tile_X0Y3_WW4END[2]
  PIN Tile_X0Y3_WW4END[3]
    DIRECTION INPUT ;
    USE SIGNAL ;
    ANTENNAGATEAREA 0.852800 ;
    ANTENNADIFFAREA 8.061600 ;
    PORT
      LAYER Metal3 ;
        RECT 146.960 549.580 147.360 549.980 ;
    END
  END Tile_X0Y3_WW4END[3]
  PIN Tile_X0Y3_WW4END[4]
    DIRECTION INPUT ;
    USE SIGNAL ;
    ANTENNAGATEAREA 0.639600 ;
    ANTENNADIFFAREA 6.046200 ;
    PORT
      LAYER Metal3 ;
        RECT 146.960 551.260 147.360 551.660 ;
    END
  END Tile_X0Y3_WW4END[4]
  PIN Tile_X0Y3_WW4END[5]
    DIRECTION INPUT ;
    USE SIGNAL ;
    ANTENNAGATEAREA 0.639600 ;
    ANTENNADIFFAREA 6.046200 ;
    PORT
      LAYER Metal3 ;
        RECT 146.960 552.940 147.360 553.340 ;
    END
  END Tile_X0Y3_WW4END[5]
  PIN Tile_X0Y3_WW4END[6]
    DIRECTION INPUT ;
    USE SIGNAL ;
    ANTENNAGATEAREA 0.639600 ;
    ANTENNADIFFAREA 6.046200 ;
    PORT
      LAYER Metal3 ;
        RECT 146.960 554.620 147.360 555.020 ;
    END
  END Tile_X0Y3_WW4END[6]
  PIN Tile_X0Y3_WW4END[7]
    DIRECTION INPUT ;
    USE SIGNAL ;
    ANTENNAGATEAREA 0.639600 ;
    ANTENNADIFFAREA 6.046200 ;
    PORT
      LAYER Metal3 ;
        RECT 146.960 556.300 147.360 556.700 ;
    END
  END Tile_X0Y3_WW4END[7]
  PIN Tile_X0Y3_WW4END[8]
    DIRECTION INPUT ;
    USE SIGNAL ;
    ANTENNAGATEAREA 0.639600 ;
    ANTENNADIFFAREA 6.046200 ;
    PORT
      LAYER Metal3 ;
        RECT 146.960 557.980 147.360 558.380 ;
    END
  END Tile_X0Y3_WW4END[8]
  PIN Tile_X0Y3_WW4END[9]
    DIRECTION INPUT ;
    USE SIGNAL ;
    ANTENNAGATEAREA 0.639600 ;
    ANTENNADIFFAREA 6.046200 ;
    PORT
      LAYER Metal3 ;
        RECT 146.960 559.660 147.360 560.060 ;
    END
  END Tile_X0Y3_WW4END[9]
  PIN Tile_X0Y4_E1BEG[0]
    DIRECTION OUTPUT ;
    USE SIGNAL ;
    ANTENNADIFFAREA 2.724000 ;
    PORT
      LAYER Metal3 ;
        RECT 146.960 216.520 147.360 216.920 ;
    END
  END Tile_X0Y4_E1BEG[0]
  PIN Tile_X0Y4_E1BEG[1]
    DIRECTION OUTPUT ;
    USE SIGNAL ;
    ANTENNADIFFAREA 2.724000 ;
    PORT
      LAYER Metal3 ;
        RECT 146.960 218.200 147.360 218.600 ;
    END
  END Tile_X0Y4_E1BEG[1]
  PIN Tile_X0Y4_E1BEG[2]
    DIRECTION OUTPUT ;
    USE SIGNAL ;
    ANTENNADIFFAREA 2.724000 ;
    PORT
      LAYER Metal3 ;
        RECT 146.960 219.880 147.360 220.280 ;
    END
  END Tile_X0Y4_E1BEG[2]
  PIN Tile_X0Y4_E1BEG[3]
    DIRECTION OUTPUT ;
    USE SIGNAL ;
    ANTENNADIFFAREA 2.724000 ;
    PORT
      LAYER Metal3 ;
        RECT 146.960 221.560 147.360 221.960 ;
    END
  END Tile_X0Y4_E1BEG[3]
  PIN Tile_X0Y4_E2BEG[0]
    DIRECTION OUTPUT ;
    USE SIGNAL ;
    ANTENNADIFFAREA 2.724000 ;
    PORT
      LAYER Metal3 ;
        RECT 146.960 225.760 147.360 226.160 ;
    END
  END Tile_X0Y4_E2BEG[0]
  PIN Tile_X0Y4_E2BEG[1]
    DIRECTION OUTPUT ;
    USE SIGNAL ;
    ANTENNADIFFAREA 2.724000 ;
    PORT
      LAYER Metal3 ;
        RECT 146.960 226.600 147.360 227.000 ;
    END
  END Tile_X0Y4_E2BEG[1]
  PIN Tile_X0Y4_E2BEG[2]
    DIRECTION OUTPUT ;
    USE SIGNAL ;
    ANTENNADIFFAREA 2.724000 ;
    PORT
      LAYER Metal3 ;
        RECT 146.960 227.440 147.360 227.840 ;
    END
  END Tile_X0Y4_E2BEG[2]
  PIN Tile_X0Y4_E2BEG[3]
    DIRECTION OUTPUT ;
    USE SIGNAL ;
    ANTENNADIFFAREA 2.724000 ;
    PORT
      LAYER Metal3 ;
        RECT 146.960 228.280 147.360 228.680 ;
    END
  END Tile_X0Y4_E2BEG[3]
  PIN Tile_X0Y4_E2BEG[4]
    DIRECTION OUTPUT ;
    USE SIGNAL ;
    ANTENNADIFFAREA 2.724000 ;
    PORT
      LAYER Metal3 ;
        RECT 146.960 229.120 147.360 229.520 ;
    END
  END Tile_X0Y4_E2BEG[4]
  PIN Tile_X0Y4_E2BEG[5]
    DIRECTION OUTPUT ;
    USE SIGNAL ;
    ANTENNADIFFAREA 2.724000 ;
    PORT
      LAYER Metal3 ;
        RECT 146.960 229.960 147.360 230.360 ;
    END
  END Tile_X0Y4_E2BEG[5]
  PIN Tile_X0Y4_E2BEG[6]
    DIRECTION OUTPUT ;
    USE SIGNAL ;
    ANTENNADIFFAREA 2.724000 ;
    PORT
      LAYER Metal3 ;
        RECT 146.960 230.800 147.360 231.200 ;
    END
  END Tile_X0Y4_E2BEG[6]
  PIN Tile_X0Y4_E2BEG[7]
    DIRECTION OUTPUT ;
    USE SIGNAL ;
    ANTENNADIFFAREA 2.724000 ;
    PORT
      LAYER Metal3 ;
        RECT 146.960 231.640 147.360 232.040 ;
    END
  END Tile_X0Y4_E2BEG[7]
  PIN Tile_X0Y4_E2BEGb[0]
    DIRECTION OUTPUT ;
    USE SIGNAL ;
    ANTENNADIFFAREA 2.724000 ;
    PORT
      LAYER Metal3 ;
        RECT 146.960 235.840 147.360 236.240 ;
    END
  END Tile_X0Y4_E2BEGb[0]
  PIN Tile_X0Y4_E2BEGb[1]
    DIRECTION OUTPUT ;
    USE SIGNAL ;
    ANTENNADIFFAREA 2.724000 ;
    PORT
      LAYER Metal3 ;
        RECT 146.960 237.520 147.360 237.920 ;
    END
  END Tile_X0Y4_E2BEGb[1]
  PIN Tile_X0Y4_E2BEGb[2]
    DIRECTION OUTPUT ;
    USE SIGNAL ;
    ANTENNADIFFAREA 2.724000 ;
    PORT
      LAYER Metal3 ;
        RECT 146.960 239.200 147.360 239.600 ;
    END
  END Tile_X0Y4_E2BEGb[2]
  PIN Tile_X0Y4_E2BEGb[3]
    DIRECTION OUTPUT ;
    USE SIGNAL ;
    ANTENNADIFFAREA 2.724000 ;
    PORT
      LAYER Metal3 ;
        RECT 146.960 240.880 147.360 241.280 ;
    END
  END Tile_X0Y4_E2BEGb[3]
  PIN Tile_X0Y4_E2BEGb[4]
    DIRECTION OUTPUT ;
    USE SIGNAL ;
    ANTENNADIFFAREA 2.724000 ;
    PORT
      LAYER Metal3 ;
        RECT 146.960 242.560 147.360 242.960 ;
    END
  END Tile_X0Y4_E2BEGb[4]
  PIN Tile_X0Y4_E2BEGb[5]
    DIRECTION OUTPUT ;
    USE SIGNAL ;
    ANTENNADIFFAREA 2.724000 ;
    PORT
      LAYER Metal3 ;
        RECT 146.960 244.240 147.360 244.640 ;
    END
  END Tile_X0Y4_E2BEGb[5]
  PIN Tile_X0Y4_E2BEGb[6]
    DIRECTION OUTPUT ;
    USE SIGNAL ;
    ANTENNADIFFAREA 2.724000 ;
    PORT
      LAYER Metal3 ;
        RECT 146.960 245.920 147.360 246.320 ;
    END
  END Tile_X0Y4_E2BEGb[6]
  PIN Tile_X0Y4_E2BEGb[7]
    DIRECTION OUTPUT ;
    USE SIGNAL ;
    ANTENNADIFFAREA 2.724000 ;
    PORT
      LAYER Metal3 ;
        RECT 146.960 247.600 147.360 248.000 ;
    END
  END Tile_X0Y4_E2BEGb[7]
  PIN Tile_X0Y4_E6BEG[0]
    DIRECTION OUTPUT ;
    USE SIGNAL ;
    ANTENNADIFFAREA 2.724000 ;
    PORT
      LAYER Metal3 ;
        RECT 146.960 275.320 147.360 275.720 ;
    END
  END Tile_X0Y4_E6BEG[0]
  PIN Tile_X0Y4_E6BEG[10]
    DIRECTION OUTPUT ;
    USE SIGNAL ;
    ANTENNADIFFAREA 2.724000 ;
    PORT
      LAYER Metal3 ;
        RECT 146.960 292.120 147.360 292.520 ;
    END
  END Tile_X0Y4_E6BEG[10]
  PIN Tile_X0Y4_E6BEG[11]
    DIRECTION OUTPUT ;
    USE SIGNAL ;
    ANTENNADIFFAREA 2.724000 ;
    PORT
      LAYER Metal3 ;
        RECT 146.960 293.800 147.360 294.200 ;
    END
  END Tile_X0Y4_E6BEG[11]
  PIN Tile_X0Y4_E6BEG[1]
    DIRECTION OUTPUT ;
    USE SIGNAL ;
    ANTENNADIFFAREA 2.724000 ;
    PORT
      LAYER Metal3 ;
        RECT 146.960 277.000 147.360 277.400 ;
    END
  END Tile_X0Y4_E6BEG[1]
  PIN Tile_X0Y4_E6BEG[2]
    DIRECTION OUTPUT ;
    USE SIGNAL ;
    ANTENNADIFFAREA 2.724000 ;
    PORT
      LAYER Metal3 ;
        RECT 146.960 278.680 147.360 279.080 ;
    END
  END Tile_X0Y4_E6BEG[2]
  PIN Tile_X0Y4_E6BEG[3]
    DIRECTION OUTPUT ;
    USE SIGNAL ;
    ANTENNADIFFAREA 2.724000 ;
    PORT
      LAYER Metal3 ;
        RECT 146.960 280.360 147.360 280.760 ;
    END
  END Tile_X0Y4_E6BEG[3]
  PIN Tile_X0Y4_E6BEG[4]
    DIRECTION OUTPUT ;
    USE SIGNAL ;
    ANTENNADIFFAREA 2.724000 ;
    PORT
      LAYER Metal3 ;
        RECT 146.960 282.040 147.360 282.440 ;
    END
  END Tile_X0Y4_E6BEG[4]
  PIN Tile_X0Y4_E6BEG[5]
    DIRECTION OUTPUT ;
    USE SIGNAL ;
    ANTENNADIFFAREA 2.724000 ;
    PORT
      LAYER Metal3 ;
        RECT 146.960 283.720 147.360 284.120 ;
    END
  END Tile_X0Y4_E6BEG[5]
  PIN Tile_X0Y4_E6BEG[6]
    DIRECTION OUTPUT ;
    USE SIGNAL ;
    ANTENNADIFFAREA 2.724000 ;
    PORT
      LAYER Metal3 ;
        RECT 146.960 285.400 147.360 285.800 ;
    END
  END Tile_X0Y4_E6BEG[6]
  PIN Tile_X0Y4_E6BEG[7]
    DIRECTION OUTPUT ;
    USE SIGNAL ;
    ANTENNADIFFAREA 2.724000 ;
    PORT
      LAYER Metal3 ;
        RECT 146.960 287.080 147.360 287.480 ;
    END
  END Tile_X0Y4_E6BEG[7]
  PIN Tile_X0Y4_E6BEG[8]
    DIRECTION OUTPUT ;
    USE SIGNAL ;
    ANTENNADIFFAREA 2.724000 ;
    PORT
      LAYER Metal3 ;
        RECT 146.960 288.760 147.360 289.160 ;
    END
  END Tile_X0Y4_E6BEG[8]
  PIN Tile_X0Y4_E6BEG[9]
    DIRECTION OUTPUT ;
    USE SIGNAL ;
    ANTENNADIFFAREA 2.724000 ;
    PORT
      LAYER Metal3 ;
        RECT 146.960 290.440 147.360 290.840 ;
    END
  END Tile_X0Y4_E6BEG[9]
  PIN Tile_X0Y4_EE4BEG[0]
    DIRECTION OUTPUT ;
    USE SIGNAL ;
    ANTENNADIFFAREA 2.724000 ;
    PORT
      LAYER Metal3 ;
        RECT 146.960 255.160 147.360 255.560 ;
    END
  END Tile_X0Y4_EE4BEG[0]
  PIN Tile_X0Y4_EE4BEG[10]
    DIRECTION OUTPUT ;
    USE SIGNAL ;
    ANTENNADIFFAREA 2.724000 ;
    PORT
      LAYER Metal3 ;
        RECT 146.960 263.560 147.360 263.960 ;
    END
  END Tile_X0Y4_EE4BEG[10]
  PIN Tile_X0Y4_EE4BEG[11]
    DIRECTION OUTPUT ;
    USE SIGNAL ;
    ANTENNADIFFAREA 2.724000 ;
    PORT
      LAYER Metal3 ;
        RECT 146.960 264.400 147.360 264.800 ;
    END
  END Tile_X0Y4_EE4BEG[11]
  PIN Tile_X0Y4_EE4BEG[12]
    DIRECTION OUTPUT ;
    USE SIGNAL ;
    ANTENNADIFFAREA 2.724000 ;
    PORT
      LAYER Metal3 ;
        RECT 146.960 265.240 147.360 265.640 ;
    END
  END Tile_X0Y4_EE4BEG[12]
  PIN Tile_X0Y4_EE4BEG[13]
    DIRECTION OUTPUT ;
    USE SIGNAL ;
    ANTENNADIFFAREA 2.724000 ;
    PORT
      LAYER Metal3 ;
        RECT 146.960 266.080 147.360 266.480 ;
    END
  END Tile_X0Y4_EE4BEG[13]
  PIN Tile_X0Y4_EE4BEG[14]
    DIRECTION OUTPUT ;
    USE SIGNAL ;
    ANTENNADIFFAREA 2.724000 ;
    PORT
      LAYER Metal3 ;
        RECT 146.960 266.920 147.360 267.320 ;
    END
  END Tile_X0Y4_EE4BEG[14]
  PIN Tile_X0Y4_EE4BEG[15]
    DIRECTION OUTPUT ;
    USE SIGNAL ;
    ANTENNADIFFAREA 2.724000 ;
    PORT
      LAYER Metal3 ;
        RECT 146.960 267.760 147.360 268.160 ;
    END
  END Tile_X0Y4_EE4BEG[15]
  PIN Tile_X0Y4_EE4BEG[1]
    DIRECTION OUTPUT ;
    USE SIGNAL ;
    ANTENNADIFFAREA 2.724000 ;
    PORT
      LAYER Metal3 ;
        RECT 146.960 256.000 147.360 256.400 ;
    END
  END Tile_X0Y4_EE4BEG[1]
  PIN Tile_X0Y4_EE4BEG[2]
    DIRECTION OUTPUT ;
    USE SIGNAL ;
    ANTENNADIFFAREA 2.724000 ;
    PORT
      LAYER Metal3 ;
        RECT 146.960 256.840 147.360 257.240 ;
    END
  END Tile_X0Y4_EE4BEG[2]
  PIN Tile_X0Y4_EE4BEG[3]
    DIRECTION OUTPUT ;
    USE SIGNAL ;
    ANTENNADIFFAREA 2.724000 ;
    PORT
      LAYER Metal3 ;
        RECT 146.960 257.680 147.360 258.080 ;
    END
  END Tile_X0Y4_EE4BEG[3]
  PIN Tile_X0Y4_EE4BEG[4]
    DIRECTION OUTPUT ;
    USE SIGNAL ;
    ANTENNADIFFAREA 2.724000 ;
    PORT
      LAYER Metal3 ;
        RECT 146.960 258.520 147.360 258.920 ;
    END
  END Tile_X0Y4_EE4BEG[4]
  PIN Tile_X0Y4_EE4BEG[5]
    DIRECTION OUTPUT ;
    USE SIGNAL ;
    ANTENNADIFFAREA 2.724000 ;
    PORT
      LAYER Metal3 ;
        RECT 146.960 259.360 147.360 259.760 ;
    END
  END Tile_X0Y4_EE4BEG[5]
  PIN Tile_X0Y4_EE4BEG[6]
    DIRECTION OUTPUT ;
    USE SIGNAL ;
    ANTENNADIFFAREA 2.724000 ;
    PORT
      LAYER Metal3 ;
        RECT 146.960 260.200 147.360 260.600 ;
    END
  END Tile_X0Y4_EE4BEG[6]
  PIN Tile_X0Y4_EE4BEG[7]
    DIRECTION OUTPUT ;
    USE SIGNAL ;
    ANTENNADIFFAREA 2.724000 ;
    PORT
      LAYER Metal3 ;
        RECT 146.960 261.040 147.360 261.440 ;
    END
  END Tile_X0Y4_EE4BEG[7]
  PIN Tile_X0Y4_EE4BEG[8]
    DIRECTION OUTPUT ;
    USE SIGNAL ;
    ANTENNADIFFAREA 2.724000 ;
    PORT
      LAYER Metal3 ;
        RECT 146.960 261.880 147.360 262.280 ;
    END
  END Tile_X0Y4_EE4BEG[8]
  PIN Tile_X0Y4_EE4BEG[9]
    DIRECTION OUTPUT ;
    USE SIGNAL ;
    ANTENNADIFFAREA 2.724000 ;
    PORT
      LAYER Metal3 ;
        RECT 146.960 262.720 147.360 263.120 ;
    END
  END Tile_X0Y4_EE4BEG[9]
  PIN Tile_X0Y4_FrameData[0]
    DIRECTION INPUT ;
    USE SIGNAL ;
    ANTENNAGATEAREA 1.626300 ;
    ANTENNADIFFAREA 18.138599 ;
    PORT
      LAYER Metal3 ;
        RECT 0.000 235.840 0.400 236.240 ;
    END
  END Tile_X0Y4_FrameData[0]
  PIN Tile_X0Y4_FrameData[10]
    DIRECTION INPUT ;
    USE SIGNAL ;
    ANTENNAGATEAREA 1.626300 ;
    ANTENNADIFFAREA 18.138599 ;
    PORT
      LAYER Metal3 ;
        RECT 0.000 294.640 0.400 295.040 ;
    END
  END Tile_X0Y4_FrameData[10]
  PIN Tile_X0Y4_FrameData[11]
    DIRECTION INPUT ;
    USE SIGNAL ;
    ANTENNAGATEAREA 1.626300 ;
    ANTENNADIFFAREA 18.138599 ;
    PORT
      LAYER Metal3 ;
        RECT 0.000 300.520 0.400 300.920 ;
    END
  END Tile_X0Y4_FrameData[11]
  PIN Tile_X0Y4_FrameData[12]
    DIRECTION INPUT ;
    USE SIGNAL ;
    ANTENNAGATEAREA 1.626300 ;
    ANTENNADIFFAREA 18.138599 ;
    PORT
      LAYER Metal3 ;
        RECT 0.000 306.400 0.400 306.800 ;
    END
  END Tile_X0Y4_FrameData[12]
  PIN Tile_X0Y4_FrameData[13]
    DIRECTION INPUT ;
    USE SIGNAL ;
    ANTENNAGATEAREA 1.626300 ;
    ANTENNADIFFAREA 18.138599 ;
    PORT
      LAYER Metal3 ;
        RECT 0.000 312.280 0.400 312.680 ;
    END
  END Tile_X0Y4_FrameData[13]
  PIN Tile_X0Y4_FrameData[14]
    DIRECTION INPUT ;
    USE SIGNAL ;
    ANTENNAGATEAREA 1.626300 ;
    ANTENNADIFFAREA 18.138599 ;
    PORT
      LAYER Metal3 ;
        RECT 0.000 318.160 0.400 318.560 ;
    END
  END Tile_X0Y4_FrameData[14]
  PIN Tile_X0Y4_FrameData[15]
    DIRECTION INPUT ;
    USE SIGNAL ;
    ANTENNAGATEAREA 1.626300 ;
    ANTENNADIFFAREA 18.138599 ;
    PORT
      LAYER Metal3 ;
        RECT 0.000 324.040 0.400 324.440 ;
    END
  END Tile_X0Y4_FrameData[15]
  PIN Tile_X0Y4_FrameData[16]
    DIRECTION INPUT ;
    USE SIGNAL ;
    ANTENNAGATEAREA 1.807000 ;
    ANTENNADIFFAREA 20.153999 ;
    PORT
      LAYER Metal3 ;
        RECT 0.000 329.920 0.400 330.320 ;
    END
  END Tile_X0Y4_FrameData[16]
  PIN Tile_X0Y4_FrameData[17]
    DIRECTION INPUT ;
    USE SIGNAL ;
    ANTENNAGATEAREA 1.807000 ;
    ANTENNADIFFAREA 20.153999 ;
    PORT
      LAYER Metal3 ;
        RECT 0.000 335.800 0.400 336.200 ;
    END
  END Tile_X0Y4_FrameData[17]
  PIN Tile_X0Y4_FrameData[18]
    DIRECTION INPUT ;
    USE SIGNAL ;
    ANTENNAGATEAREA 1.807000 ;
    ANTENNADIFFAREA 20.153999 ;
    PORT
      LAYER Metal3 ;
        RECT 0.000 341.680 0.400 342.080 ;
    END
  END Tile_X0Y4_FrameData[18]
  PIN Tile_X0Y4_FrameData[19]
    DIRECTION INPUT ;
    USE SIGNAL ;
    ANTENNAGATEAREA 1.807000 ;
    ANTENNADIFFAREA 20.153999 ;
    PORT
      LAYER Metal3 ;
        RECT 0.000 347.560 0.400 347.960 ;
    END
  END Tile_X0Y4_FrameData[19]
  PIN Tile_X0Y4_FrameData[1]
    DIRECTION INPUT ;
    USE SIGNAL ;
    ANTENNAGATEAREA 1.626300 ;
    ANTENNADIFFAREA 18.138599 ;
    PORT
      LAYER Metal3 ;
        RECT 0.000 241.720 0.400 242.120 ;
    END
  END Tile_X0Y4_FrameData[1]
  PIN Tile_X0Y4_FrameData[20]
    DIRECTION INPUT ;
    USE SIGNAL ;
    ANTENNAGATEAREA 1.807000 ;
    ANTENNADIFFAREA 20.153999 ;
    PORT
      LAYER Metal3 ;
        RECT 0.000 353.440 0.400 353.840 ;
    END
  END Tile_X0Y4_FrameData[20]
  PIN Tile_X0Y4_FrameData[21]
    DIRECTION INPUT ;
    USE SIGNAL ;
    ANTENNAGATEAREA 1.807000 ;
    ANTENNADIFFAREA 20.153999 ;
    PORT
      LAYER Metal3 ;
        RECT 0.000 359.320 0.400 359.720 ;
    END
  END Tile_X0Y4_FrameData[21]
  PIN Tile_X0Y4_FrameData[22]
    DIRECTION INPUT ;
    USE SIGNAL ;
    ANTENNAGATEAREA 1.807000 ;
    ANTENNADIFFAREA 20.153999 ;
    PORT
      LAYER Metal3 ;
        RECT 0.000 365.200 0.400 365.600 ;
    END
  END Tile_X0Y4_FrameData[22]
  PIN Tile_X0Y4_FrameData[23]
    DIRECTION INPUT ;
    USE SIGNAL ;
    ANTENNAGATEAREA 1.807000 ;
    ANTENNADIFFAREA 20.153999 ;
    PORT
      LAYER Metal3 ;
        RECT 0.000 371.080 0.400 371.480 ;
    END
  END Tile_X0Y4_FrameData[23]
  PIN Tile_X0Y4_FrameData[24]
    DIRECTION INPUT ;
    USE SIGNAL ;
    ANTENNAGATEAREA 1.807000 ;
    ANTENNADIFFAREA 20.153999 ;
    PORT
      LAYER Metal3 ;
        RECT 0.000 376.960 0.400 377.360 ;
    END
  END Tile_X0Y4_FrameData[24]
  PIN Tile_X0Y4_FrameData[25]
    DIRECTION INPUT ;
    USE SIGNAL ;
    ANTENNAGATEAREA 1.807000 ;
    ANTENNADIFFAREA 20.153999 ;
    PORT
      LAYER Metal3 ;
        RECT 0.000 382.840 0.400 383.240 ;
    END
  END Tile_X0Y4_FrameData[25]
  PIN Tile_X0Y4_FrameData[26]
    DIRECTION INPUT ;
    USE SIGNAL ;
    ANTENNAGATEAREA 1.807000 ;
    ANTENNADIFFAREA 20.153999 ;
    PORT
      LAYER Metal3 ;
        RECT 0.000 388.720 0.400 389.120 ;
    END
  END Tile_X0Y4_FrameData[26]
  PIN Tile_X0Y4_FrameData[27]
    DIRECTION INPUT ;
    USE SIGNAL ;
    ANTENNAGATEAREA 1.807000 ;
    ANTENNADIFFAREA 20.153999 ;
    PORT
      LAYER Metal3 ;
        RECT 0.000 394.600 0.400 395.000 ;
    END
  END Tile_X0Y4_FrameData[27]
  PIN Tile_X0Y4_FrameData[28]
    DIRECTION INPUT ;
    USE SIGNAL ;
    ANTENNAGATEAREA 1.807000 ;
    ANTENNADIFFAREA 20.153999 ;
    PORT
      LAYER Metal3 ;
        RECT 0.000 400.480 0.400 400.880 ;
    END
  END Tile_X0Y4_FrameData[28]
  PIN Tile_X0Y4_FrameData[29]
    DIRECTION INPUT ;
    USE SIGNAL ;
    ANTENNAGATEAREA 1.807000 ;
    ANTENNADIFFAREA 20.153999 ;
    PORT
      LAYER Metal3 ;
        RECT 0.000 406.360 0.400 406.760 ;
    END
  END Tile_X0Y4_FrameData[29]
  PIN Tile_X0Y4_FrameData[2]
    DIRECTION INPUT ;
    USE SIGNAL ;
    ANTENNAGATEAREA 1.626300 ;
    ANTENNADIFFAREA 18.138599 ;
    PORT
      LAYER Metal3 ;
        RECT 0.000 247.600 0.400 248.000 ;
    END
  END Tile_X0Y4_FrameData[2]
  PIN Tile_X0Y4_FrameData[30]
    DIRECTION INPUT ;
    USE SIGNAL ;
    ANTENNAGATEAREA 1.807000 ;
    ANTENNADIFFAREA 20.153999 ;
    PORT
      LAYER Metal3 ;
        RECT 0.000 412.240 0.400 412.640 ;
    END
  END Tile_X0Y4_FrameData[30]
  PIN Tile_X0Y4_FrameData[31]
    DIRECTION INPUT ;
    USE SIGNAL ;
    ANTENNAGATEAREA 1.807000 ;
    ANTENNADIFFAREA 20.153999 ;
    PORT
      LAYER Metal3 ;
        RECT 0.000 418.120 0.400 418.520 ;
    END
  END Tile_X0Y4_FrameData[31]
  PIN Tile_X0Y4_FrameData[3]
    DIRECTION INPUT ;
    USE SIGNAL ;
    ANTENNAGATEAREA 1.626300 ;
    ANTENNADIFFAREA 18.138599 ;
    PORT
      LAYER Metal3 ;
        RECT 0.000 253.480 0.400 253.880 ;
    END
  END Tile_X0Y4_FrameData[3]
  PIN Tile_X0Y4_FrameData[4]
    DIRECTION INPUT ;
    USE SIGNAL ;
    ANTENNAGATEAREA 1.626300 ;
    ANTENNADIFFAREA 18.138599 ;
    PORT
      LAYER Metal3 ;
        RECT 0.000 259.360 0.400 259.760 ;
    END
  END Tile_X0Y4_FrameData[4]
  PIN Tile_X0Y4_FrameData[5]
    DIRECTION INPUT ;
    USE SIGNAL ;
    ANTENNAGATEAREA 1.626300 ;
    ANTENNADIFFAREA 18.138599 ;
    PORT
      LAYER Metal3 ;
        RECT 0.000 265.240 0.400 265.640 ;
    END
  END Tile_X0Y4_FrameData[5]
  PIN Tile_X0Y4_FrameData[6]
    DIRECTION INPUT ;
    USE SIGNAL ;
    ANTENNAGATEAREA 1.626300 ;
    ANTENNADIFFAREA 18.138599 ;
    PORT
      LAYER Metal3 ;
        RECT 0.000 271.120 0.400 271.520 ;
    END
  END Tile_X0Y4_FrameData[6]
  PIN Tile_X0Y4_FrameData[7]
    DIRECTION INPUT ;
    USE SIGNAL ;
    ANTENNAGATEAREA 1.626300 ;
    ANTENNADIFFAREA 18.138599 ;
    PORT
      LAYER Metal3 ;
        RECT 0.000 277.000 0.400 277.400 ;
    END
  END Tile_X0Y4_FrameData[7]
  PIN Tile_X0Y4_FrameData[8]
    DIRECTION INPUT ;
    USE SIGNAL ;
    ANTENNAGATEAREA 1.626300 ;
    ANTENNADIFFAREA 18.138599 ;
    PORT
      LAYER Metal3 ;
        RECT 0.000 282.880 0.400 283.280 ;
    END
  END Tile_X0Y4_FrameData[8]
  PIN Tile_X0Y4_FrameData[9]
    DIRECTION INPUT ;
    USE SIGNAL ;
    ANTENNAGATEAREA 1.626300 ;
    ANTENNADIFFAREA 18.138599 ;
    PORT
      LAYER Metal3 ;
        RECT 0.000 288.760 0.400 289.160 ;
    END
  END Tile_X0Y4_FrameData[9]
  PIN Tile_X0Y4_FrameData_O[0]
    DIRECTION OUTPUT ;
    USE SIGNAL ;
    ANTENNADIFFAREA 2.724000 ;
    PORT
      LAYER Metal3 ;
        RECT 146.960 377.800 147.360 378.200 ;
    END
  END Tile_X0Y4_FrameData_O[0]
  PIN Tile_X0Y4_FrameData_O[10]
    DIRECTION OUTPUT ;
    USE SIGNAL ;
    ANTENNADIFFAREA 2.724000 ;
    PORT
      LAYER Metal3 ;
        RECT 146.960 394.600 147.360 395.000 ;
    END
  END Tile_X0Y4_FrameData_O[10]
  PIN Tile_X0Y4_FrameData_O[11]
    DIRECTION OUTPUT ;
    USE SIGNAL ;
    ANTENNADIFFAREA 2.724000 ;
    PORT
      LAYER Metal3 ;
        RECT 146.960 396.280 147.360 396.680 ;
    END
  END Tile_X0Y4_FrameData_O[11]
  PIN Tile_X0Y4_FrameData_O[12]
    DIRECTION OUTPUT ;
    USE SIGNAL ;
    ANTENNADIFFAREA 2.724000 ;
    PORT
      LAYER Metal3 ;
        RECT 146.960 397.960 147.360 398.360 ;
    END
  END Tile_X0Y4_FrameData_O[12]
  PIN Tile_X0Y4_FrameData_O[13]
    DIRECTION OUTPUT ;
    USE SIGNAL ;
    ANTENNADIFFAREA 2.724000 ;
    PORT
      LAYER Metal3 ;
        RECT 146.960 399.640 147.360 400.040 ;
    END
  END Tile_X0Y4_FrameData_O[13]
  PIN Tile_X0Y4_FrameData_O[14]
    DIRECTION OUTPUT ;
    USE SIGNAL ;
    ANTENNADIFFAREA 2.724000 ;
    PORT
      LAYER Metal3 ;
        RECT 146.960 401.320 147.360 401.720 ;
    END
  END Tile_X0Y4_FrameData_O[14]
  PIN Tile_X0Y4_FrameData_O[15]
    DIRECTION OUTPUT ;
    USE SIGNAL ;
    ANTENNADIFFAREA 2.724000 ;
    PORT
      LAYER Metal3 ;
        RECT 146.960 403.000 147.360 403.400 ;
    END
  END Tile_X0Y4_FrameData_O[15]
  PIN Tile_X0Y4_FrameData_O[16]
    DIRECTION OUTPUT ;
    USE SIGNAL ;
    ANTENNADIFFAREA 2.724000 ;
    PORT
      LAYER Metal3 ;
        RECT 146.960 404.680 147.360 405.080 ;
    END
  END Tile_X0Y4_FrameData_O[16]
  PIN Tile_X0Y4_FrameData_O[17]
    DIRECTION OUTPUT ;
    USE SIGNAL ;
    ANTENNADIFFAREA 2.724000 ;
    PORT
      LAYER Metal3 ;
        RECT 146.960 406.360 147.360 406.760 ;
    END
  END Tile_X0Y4_FrameData_O[17]
  PIN Tile_X0Y4_FrameData_O[18]
    DIRECTION OUTPUT ;
    USE SIGNAL ;
    ANTENNADIFFAREA 2.724000 ;
    PORT
      LAYER Metal3 ;
        RECT 146.960 408.040 147.360 408.440 ;
    END
  END Tile_X0Y4_FrameData_O[18]
  PIN Tile_X0Y4_FrameData_O[19]
    DIRECTION OUTPUT ;
    USE SIGNAL ;
    ANTENNADIFFAREA 2.724000 ;
    PORT
      LAYER Metal3 ;
        RECT 146.960 409.720 147.360 410.120 ;
    END
  END Tile_X0Y4_FrameData_O[19]
  PIN Tile_X0Y4_FrameData_O[1]
    DIRECTION OUTPUT ;
    USE SIGNAL ;
    ANTENNADIFFAREA 2.724000 ;
    PORT
      LAYER Metal3 ;
        RECT 146.960 379.480 147.360 379.880 ;
    END
  END Tile_X0Y4_FrameData_O[1]
  PIN Tile_X0Y4_FrameData_O[20]
    DIRECTION OUTPUT ;
    USE SIGNAL ;
    ANTENNADIFFAREA 2.724000 ;
    PORT
      LAYER Metal3 ;
        RECT 146.960 411.400 147.360 411.800 ;
    END
  END Tile_X0Y4_FrameData_O[20]
  PIN Tile_X0Y4_FrameData_O[21]
    DIRECTION OUTPUT ;
    USE SIGNAL ;
    ANTENNADIFFAREA 2.724000 ;
    PORT
      LAYER Metal3 ;
        RECT 146.960 413.080 147.360 413.480 ;
    END
  END Tile_X0Y4_FrameData_O[21]
  PIN Tile_X0Y4_FrameData_O[22]
    DIRECTION OUTPUT ;
    USE SIGNAL ;
    ANTENNADIFFAREA 2.724000 ;
    PORT
      LAYER Metal3 ;
        RECT 146.960 414.760 147.360 415.160 ;
    END
  END Tile_X0Y4_FrameData_O[22]
  PIN Tile_X0Y4_FrameData_O[23]
    DIRECTION OUTPUT ;
    USE SIGNAL ;
    ANTENNADIFFAREA 2.724000 ;
    PORT
      LAYER Metal3 ;
        RECT 146.960 416.440 147.360 416.840 ;
    END
  END Tile_X0Y4_FrameData_O[23]
  PIN Tile_X0Y4_FrameData_O[24]
    DIRECTION OUTPUT ;
    USE SIGNAL ;
    ANTENNADIFFAREA 2.724000 ;
    PORT
      LAYER Metal3 ;
        RECT 146.960 418.120 147.360 418.520 ;
    END
  END Tile_X0Y4_FrameData_O[24]
  PIN Tile_X0Y4_FrameData_O[25]
    DIRECTION OUTPUT ;
    USE SIGNAL ;
    ANTENNADIFFAREA 2.724000 ;
    PORT
      LAYER Metal3 ;
        RECT 146.960 419.800 147.360 420.200 ;
    END
  END Tile_X0Y4_FrameData_O[25]
  PIN Tile_X0Y4_FrameData_O[26]
    DIRECTION OUTPUT ;
    USE SIGNAL ;
    ANTENNADIFFAREA 2.724000 ;
    PORT
      LAYER Metal3 ;
        RECT 146.960 421.480 147.360 421.880 ;
    END
  END Tile_X0Y4_FrameData_O[26]
  PIN Tile_X0Y4_FrameData_O[27]
    DIRECTION OUTPUT ;
    USE SIGNAL ;
    ANTENNADIFFAREA 2.724000 ;
    PORT
      LAYER Metal3 ;
        RECT 146.960 423.160 147.360 423.560 ;
    END
  END Tile_X0Y4_FrameData_O[27]
  PIN Tile_X0Y4_FrameData_O[28]
    DIRECTION OUTPUT ;
    USE SIGNAL ;
    ANTENNADIFFAREA 2.724000 ;
    PORT
      LAYER Metal3 ;
        RECT 146.960 424.840 147.360 425.240 ;
    END
  END Tile_X0Y4_FrameData_O[28]
  PIN Tile_X0Y4_FrameData_O[29]
    DIRECTION OUTPUT ;
    USE SIGNAL ;
    ANTENNADIFFAREA 2.724000 ;
    PORT
      LAYER Metal3 ;
        RECT 146.960 426.520 147.360 426.920 ;
    END
  END Tile_X0Y4_FrameData_O[29]
  PIN Tile_X0Y4_FrameData_O[2]
    DIRECTION OUTPUT ;
    USE SIGNAL ;
    ANTENNADIFFAREA 2.724000 ;
    PORT
      LAYER Metal3 ;
        RECT 146.960 381.160 147.360 381.560 ;
    END
  END Tile_X0Y4_FrameData_O[2]
  PIN Tile_X0Y4_FrameData_O[30]
    DIRECTION OUTPUT ;
    USE SIGNAL ;
    ANTENNADIFFAREA 2.724000 ;
    PORT
      LAYER Metal3 ;
        RECT 146.960 428.200 147.360 428.600 ;
    END
  END Tile_X0Y4_FrameData_O[30]
  PIN Tile_X0Y4_FrameData_O[31]
    DIRECTION OUTPUT ;
    USE SIGNAL ;
    ANTENNADIFFAREA 2.724000 ;
    PORT
      LAYER Metal3 ;
        RECT 146.960 429.880 147.360 430.280 ;
    END
  END Tile_X0Y4_FrameData_O[31]
  PIN Tile_X0Y4_FrameData_O[3]
    DIRECTION OUTPUT ;
    USE SIGNAL ;
    ANTENNADIFFAREA 2.724000 ;
    PORT
      LAYER Metal3 ;
        RECT 146.960 382.840 147.360 383.240 ;
    END
  END Tile_X0Y4_FrameData_O[3]
  PIN Tile_X0Y4_FrameData_O[4]
    DIRECTION OUTPUT ;
    USE SIGNAL ;
    ANTENNADIFFAREA 2.724000 ;
    PORT
      LAYER Metal3 ;
        RECT 146.960 384.520 147.360 384.920 ;
    END
  END Tile_X0Y4_FrameData_O[4]
  PIN Tile_X0Y4_FrameData_O[5]
    DIRECTION OUTPUT ;
    USE SIGNAL ;
    ANTENNADIFFAREA 2.724000 ;
    PORT
      LAYER Metal3 ;
        RECT 146.960 386.200 147.360 386.600 ;
    END
  END Tile_X0Y4_FrameData_O[5]
  PIN Tile_X0Y4_FrameData_O[6]
    DIRECTION OUTPUT ;
    USE SIGNAL ;
    ANTENNADIFFAREA 2.724000 ;
    PORT
      LAYER Metal3 ;
        RECT 146.960 387.880 147.360 388.280 ;
    END
  END Tile_X0Y4_FrameData_O[6]
  PIN Tile_X0Y4_FrameData_O[7]
    DIRECTION OUTPUT ;
    USE SIGNAL ;
    ANTENNADIFFAREA 2.724000 ;
    PORT
      LAYER Metal3 ;
        RECT 146.960 389.560 147.360 389.960 ;
    END
  END Tile_X0Y4_FrameData_O[7]
  PIN Tile_X0Y4_FrameData_O[8]
    DIRECTION OUTPUT ;
    USE SIGNAL ;
    ANTENNADIFFAREA 2.724000 ;
    PORT
      LAYER Metal3 ;
        RECT 146.960 391.240 147.360 391.640 ;
    END
  END Tile_X0Y4_FrameData_O[8]
  PIN Tile_X0Y4_FrameData_O[9]
    DIRECTION OUTPUT ;
    USE SIGNAL ;
    ANTENNADIFFAREA 2.724000 ;
    PORT
      LAYER Metal3 ;
        RECT 146.960 392.920 147.360 393.320 ;
    END
  END Tile_X0Y4_FrameData_O[9]
  PIN Tile_X0Y4_UserCLK
    DIRECTION INPUT ;
    USE SIGNAL ;
    ANTENNAGATEAREA 0.180700 ;
    ANTENNADIFFAREA 2.015400 ;
    PORT
      LAYER Metal3 ;
        RECT 0.000 219.040 0.400 219.440 ;
    END
  END Tile_X0Y4_UserCLK
  PIN Tile_X0Y4_UserCLKo
    DIRECTION OUTPUT ;
    USE SIGNAL ;
    ANTENNADIFFAREA 2.724000 ;
    PORT
      LAYER Metal3 ;
        RECT 146.960 376.120 147.360 376.520 ;
    END
  END Tile_X0Y4_UserCLKo
  PIN Tile_X0Y4_W1END[0]
    DIRECTION INPUT ;
    USE SIGNAL ;
    ANTENNAGATEAREA 1.279200 ;
    ANTENNADIFFAREA 12.092400 ;
    PORT
      LAYER Metal3 ;
        RECT 146.960 295.480 147.360 295.880 ;
    END
  END Tile_X0Y4_W1END[0]
  PIN Tile_X0Y4_W1END[1]
    DIRECTION INPUT ;
    USE SIGNAL ;
    ANTENNAGATEAREA 1.279200 ;
    ANTENNADIFFAREA 12.092400 ;
    PORT
      LAYER Metal3 ;
        RECT 146.960 297.160 147.360 297.560 ;
    END
  END Tile_X0Y4_W1END[1]
  PIN Tile_X0Y4_W1END[2]
    DIRECTION INPUT ;
    USE SIGNAL ;
    ANTENNAGATEAREA 1.279200 ;
    ANTENNADIFFAREA 12.092400 ;
    PORT
      LAYER Metal3 ;
        RECT 146.960 298.840 147.360 299.240 ;
    END
  END Tile_X0Y4_W1END[2]
  PIN Tile_X0Y4_W1END[3]
    DIRECTION INPUT ;
    USE SIGNAL ;
    ANTENNAGATEAREA 1.279200 ;
    ANTENNADIFFAREA 12.092400 ;
    PORT
      LAYER Metal3 ;
        RECT 146.960 300.520 147.360 300.920 ;
    END
  END Tile_X0Y4_W1END[3]
  PIN Tile_X0Y4_W2END[0]
    DIRECTION INPUT ;
    USE SIGNAL ;
    ANTENNAGATEAREA 0.852800 ;
    ANTENNADIFFAREA 8.061600 ;
    PORT
      LAYER Metal3 ;
        RECT 146.960 315.640 147.360 316.040 ;
    END
  END Tile_X0Y4_W2END[0]
  PIN Tile_X0Y4_W2END[1]
    DIRECTION INPUT ;
    USE SIGNAL ;
    ANTENNAGATEAREA 0.852800 ;
    ANTENNADIFFAREA 8.061600 ;
    PORT
      LAYER Metal3 ;
        RECT 146.960 317.320 147.360 317.720 ;
    END
  END Tile_X0Y4_W2END[1]
  PIN Tile_X0Y4_W2END[2]
    DIRECTION INPUT ;
    USE SIGNAL ;
    ANTENNAGATEAREA 0.852800 ;
    ANTENNADIFFAREA 8.061600 ;
    PORT
      LAYER Metal3 ;
        RECT 146.960 319.000 147.360 319.400 ;
    END
  END Tile_X0Y4_W2END[2]
  PIN Tile_X0Y4_W2END[3]
    DIRECTION INPUT ;
    USE SIGNAL ;
    ANTENNAGATEAREA 0.852800 ;
    ANTENNADIFFAREA 8.061600 ;
    PORT
      LAYER Metal3 ;
        RECT 146.960 320.680 147.360 321.080 ;
    END
  END Tile_X0Y4_W2END[3]
  PIN Tile_X0Y4_W2END[4]
    DIRECTION INPUT ;
    USE SIGNAL ;
    ANTENNAGATEAREA 0.852800 ;
    ANTENNADIFFAREA 8.061600 ;
    PORT
      LAYER Metal3 ;
        RECT 146.960 322.360 147.360 322.760 ;
    END
  END Tile_X0Y4_W2END[4]
  PIN Tile_X0Y4_W2END[5]
    DIRECTION INPUT ;
    USE SIGNAL ;
    ANTENNAGATEAREA 0.852800 ;
    ANTENNADIFFAREA 8.061600 ;
    PORT
      LAYER Metal3 ;
        RECT 146.960 324.040 147.360 324.440 ;
    END
  END Tile_X0Y4_W2END[5]
  PIN Tile_X0Y4_W2END[6]
    DIRECTION INPUT ;
    USE SIGNAL ;
    ANTENNAGATEAREA 0.852800 ;
    ANTENNADIFFAREA 8.061600 ;
    PORT
      LAYER Metal3 ;
        RECT 146.960 325.720 147.360 326.120 ;
    END
  END Tile_X0Y4_W2END[6]
  PIN Tile_X0Y4_W2END[7]
    DIRECTION INPUT ;
    USE SIGNAL ;
    ANTENNAGATEAREA 0.852800 ;
    ANTENNADIFFAREA 8.061600 ;
    PORT
      LAYER Metal3 ;
        RECT 146.960 327.400 147.360 327.800 ;
    END
  END Tile_X0Y4_W2END[7]
  PIN Tile_X0Y4_W2MID[0]
    DIRECTION INPUT ;
    USE SIGNAL ;
    ANTENNAGATEAREA 0.852800 ;
    ANTENNADIFFAREA 8.061600 ;
    PORT
      LAYER Metal3 ;
        RECT 146.960 302.200 147.360 302.600 ;
    END
  END Tile_X0Y4_W2MID[0]
  PIN Tile_X0Y4_W2MID[1]
    DIRECTION INPUT ;
    USE SIGNAL ;
    ANTENNAGATEAREA 0.852800 ;
    ANTENNADIFFAREA 8.061600 ;
    PORT
      LAYER Metal3 ;
        RECT 146.960 303.880 147.360 304.280 ;
    END
  END Tile_X0Y4_W2MID[1]
  PIN Tile_X0Y4_W2MID[2]
    DIRECTION INPUT ;
    USE SIGNAL ;
    ANTENNAGATEAREA 0.852800 ;
    ANTENNADIFFAREA 8.061600 ;
    PORT
      LAYER Metal3 ;
        RECT 146.960 305.560 147.360 305.960 ;
    END
  END Tile_X0Y4_W2MID[2]
  PIN Tile_X0Y4_W2MID[3]
    DIRECTION INPUT ;
    USE SIGNAL ;
    ANTENNAGATEAREA 0.852800 ;
    ANTENNADIFFAREA 8.061600 ;
    PORT
      LAYER Metal3 ;
        RECT 146.960 307.240 147.360 307.640 ;
    END
  END Tile_X0Y4_W2MID[3]
  PIN Tile_X0Y4_W2MID[4]
    DIRECTION INPUT ;
    USE SIGNAL ;
    ANTENNAGATEAREA 0.852800 ;
    ANTENNADIFFAREA 8.061600 ;
    PORT
      LAYER Metal3 ;
        RECT 146.960 308.920 147.360 309.320 ;
    END
  END Tile_X0Y4_W2MID[4]
  PIN Tile_X0Y4_W2MID[5]
    DIRECTION INPUT ;
    USE SIGNAL ;
    ANTENNAGATEAREA 0.852800 ;
    ANTENNADIFFAREA 8.061600 ;
    PORT
      LAYER Metal3 ;
        RECT 146.960 310.600 147.360 311.000 ;
    END
  END Tile_X0Y4_W2MID[5]
  PIN Tile_X0Y4_W2MID[6]
    DIRECTION INPUT ;
    USE SIGNAL ;
    ANTENNAGATEAREA 0.852800 ;
    ANTENNADIFFAREA 8.061600 ;
    PORT
      LAYER Metal3 ;
        RECT 146.960 312.280 147.360 312.680 ;
    END
  END Tile_X0Y4_W2MID[6]
  PIN Tile_X0Y4_W2MID[7]
    DIRECTION INPUT ;
    USE SIGNAL ;
    ANTENNAGATEAREA 0.852800 ;
    ANTENNADIFFAREA 8.061600 ;
    PORT
      LAYER Metal3 ;
        RECT 146.960 313.960 147.360 314.360 ;
    END
  END Tile_X0Y4_W2MID[7]
  PIN Tile_X0Y4_W6END[0]
    DIRECTION INPUT ;
    USE SIGNAL ;
    ANTENNAGATEAREA 0.881400 ;
    ANTENNADIFFAREA 8.061600 ;
    PORT
      LAYER Metal3 ;
        RECT 146.960 355.960 147.360 356.360 ;
    END
  END Tile_X0Y4_W6END[0]
  PIN Tile_X0Y4_W6END[10]
    DIRECTION INPUT ;
    USE SIGNAL ;
    ANTENNAGATEAREA 0.852800 ;
    ANTENNADIFFAREA 8.061600 ;
    PORT
      LAYER Metal3 ;
        RECT 146.960 372.760 147.360 373.160 ;
    END
  END Tile_X0Y4_W6END[10]
  PIN Tile_X0Y4_W6END[11]
    DIRECTION INPUT ;
    USE SIGNAL ;
    ANTENNAGATEAREA 0.852800 ;
    ANTENNADIFFAREA 8.061600 ;
    PORT
      LAYER Metal3 ;
        RECT 146.960 374.440 147.360 374.840 ;
    END
  END Tile_X0Y4_W6END[11]
  PIN Tile_X0Y4_W6END[1]
    DIRECTION INPUT ;
    USE SIGNAL ;
    ANTENNAGATEAREA 0.881400 ;
    ANTENNADIFFAREA 8.061600 ;
    PORT
      LAYER Metal3 ;
        RECT 146.960 357.640 147.360 358.040 ;
    END
  END Tile_X0Y4_W6END[1]
  PIN Tile_X0Y4_W6END[2]
    DIRECTION INPUT ;
    USE SIGNAL ;
    ANTENNAGATEAREA 0.881400 ;
    ANTENNADIFFAREA 8.061600 ;
    PORT
      LAYER Metal3 ;
        RECT 146.960 359.320 147.360 359.720 ;
    END
  END Tile_X0Y4_W6END[2]
  PIN Tile_X0Y4_W6END[3]
    DIRECTION INPUT ;
    USE SIGNAL ;
    ANTENNAGATEAREA 0.881400 ;
    ANTENNADIFFAREA 8.061600 ;
    PORT
      LAYER Metal3 ;
        RECT 146.960 361.000 147.360 361.400 ;
    END
  END Tile_X0Y4_W6END[3]
  PIN Tile_X0Y4_W6END[4]
    DIRECTION INPUT ;
    USE SIGNAL ;
    ANTENNAGATEAREA 1.066000 ;
    ANTENNADIFFAREA 10.077000 ;
    PORT
      LAYER Metal3 ;
        RECT 146.960 362.680 147.360 363.080 ;
    END
  END Tile_X0Y4_W6END[4]
  PIN Tile_X0Y4_W6END[5]
    DIRECTION INPUT ;
    USE SIGNAL ;
    ANTENNAGATEAREA 1.066000 ;
    ANTENNADIFFAREA 10.077000 ;
    PORT
      LAYER Metal3 ;
        RECT 146.960 364.360 147.360 364.760 ;
    END
  END Tile_X0Y4_W6END[5]
  PIN Tile_X0Y4_W6END[6]
    DIRECTION INPUT ;
    USE SIGNAL ;
    ANTENNAGATEAREA 1.066000 ;
    ANTENNADIFFAREA 10.077000 ;
    PORT
      LAYER Metal3 ;
        RECT 146.960 366.040 147.360 366.440 ;
    END
  END Tile_X0Y4_W6END[6]
  PIN Tile_X0Y4_W6END[7]
    DIRECTION INPUT ;
    USE SIGNAL ;
    ANTENNAGATEAREA 1.066000 ;
    ANTENNADIFFAREA 10.077000 ;
    PORT
      LAYER Metal3 ;
        RECT 146.960 367.720 147.360 368.120 ;
    END
  END Tile_X0Y4_W6END[7]
  PIN Tile_X0Y4_W6END[8]
    DIRECTION INPUT ;
    USE SIGNAL ;
    ANTENNAGATEAREA 0.852800 ;
    ANTENNADIFFAREA 8.061600 ;
    PORT
      LAYER Metal3 ;
        RECT 146.960 369.400 147.360 369.800 ;
    END
  END Tile_X0Y4_W6END[8]
  PIN Tile_X0Y4_W6END[9]
    DIRECTION INPUT ;
    USE SIGNAL ;
    ANTENNAGATEAREA 0.852800 ;
    ANTENNADIFFAREA 8.061600 ;
    PORT
      LAYER Metal3 ;
        RECT 146.960 371.080 147.360 371.480 ;
    END
  END Tile_X0Y4_W6END[9]
  PIN Tile_X0Y4_WW4END[0]
    DIRECTION INPUT ;
    USE SIGNAL ;
    ANTENNAGATEAREA 0.852800 ;
    ANTENNADIFFAREA 8.061600 ;
    PORT
      LAYER Metal3 ;
        RECT 146.960 329.080 147.360 329.480 ;
    END
  END Tile_X0Y4_WW4END[0]
  PIN Tile_X0Y4_WW4END[10]
    DIRECTION INPUT ;
    USE SIGNAL ;
    ANTENNAGATEAREA 0.639600 ;
    ANTENNADIFFAREA 6.046200 ;
    PORT
      LAYER Metal3 ;
        RECT 146.960 345.880 147.360 346.280 ;
    END
  END Tile_X0Y4_WW4END[10]
  PIN Tile_X0Y4_WW4END[11]
    DIRECTION INPUT ;
    USE SIGNAL ;
    ANTENNAGATEAREA 0.639600 ;
    ANTENNADIFFAREA 6.046200 ;
    PORT
      LAYER Metal3 ;
        RECT 146.960 347.560 147.360 347.960 ;
    END
  END Tile_X0Y4_WW4END[11]
  PIN Tile_X0Y4_WW4END[12]
    DIRECTION INPUT ;
    USE SIGNAL ;
    ANTENNAGATEAREA 0.852800 ;
    ANTENNADIFFAREA 8.061600 ;
    PORT
      LAYER Metal3 ;
        RECT 146.960 349.240 147.360 349.640 ;
    END
  END Tile_X0Y4_WW4END[12]
  PIN Tile_X0Y4_WW4END[13]
    DIRECTION INPUT ;
    USE SIGNAL ;
    ANTENNAGATEAREA 0.852800 ;
    ANTENNADIFFAREA 8.061600 ;
    PORT
      LAYER Metal3 ;
        RECT 146.960 350.920 147.360 351.320 ;
    END
  END Tile_X0Y4_WW4END[13]
  PIN Tile_X0Y4_WW4END[14]
    DIRECTION INPUT ;
    USE SIGNAL ;
    ANTENNAGATEAREA 0.852800 ;
    ANTENNADIFFAREA 8.061600 ;
    PORT
      LAYER Metal3 ;
        RECT 146.960 352.600 147.360 353.000 ;
    END
  END Tile_X0Y4_WW4END[14]
  PIN Tile_X0Y4_WW4END[15]
    DIRECTION INPUT ;
    USE SIGNAL ;
    ANTENNAGATEAREA 0.852800 ;
    ANTENNADIFFAREA 8.061600 ;
    PORT
      LAYER Metal3 ;
        RECT 146.960 354.280 147.360 354.680 ;
    END
  END Tile_X0Y4_WW4END[15]
  PIN Tile_X0Y4_WW4END[1]
    DIRECTION INPUT ;
    USE SIGNAL ;
    ANTENNAGATEAREA 0.852800 ;
    ANTENNADIFFAREA 8.061600 ;
    PORT
      LAYER Metal3 ;
        RECT 146.960 330.760 147.360 331.160 ;
    END
  END Tile_X0Y4_WW4END[1]
  PIN Tile_X0Y4_WW4END[2]
    DIRECTION INPUT ;
    USE SIGNAL ;
    ANTENNAGATEAREA 0.852800 ;
    ANTENNADIFFAREA 8.061600 ;
    PORT
      LAYER Metal3 ;
        RECT 146.960 332.440 147.360 332.840 ;
    END
  END Tile_X0Y4_WW4END[2]
  PIN Tile_X0Y4_WW4END[3]
    DIRECTION INPUT ;
    USE SIGNAL ;
    ANTENNAGATEAREA 0.852800 ;
    ANTENNADIFFAREA 8.061600 ;
    PORT
      LAYER Metal3 ;
        RECT 146.960 334.120 147.360 334.520 ;
    END
  END Tile_X0Y4_WW4END[3]
  PIN Tile_X0Y4_WW4END[4]
    DIRECTION INPUT ;
    USE SIGNAL ;
    ANTENNAGATEAREA 0.639600 ;
    ANTENNADIFFAREA 6.046200 ;
    PORT
      LAYER Metal3 ;
        RECT 146.960 335.800 147.360 336.200 ;
    END
  END Tile_X0Y4_WW4END[4]
  PIN Tile_X0Y4_WW4END[5]
    DIRECTION INPUT ;
    USE SIGNAL ;
    ANTENNAGATEAREA 0.639600 ;
    ANTENNADIFFAREA 6.046200 ;
    PORT
      LAYER Metal3 ;
        RECT 146.960 337.480 147.360 337.880 ;
    END
  END Tile_X0Y4_WW4END[5]
  PIN Tile_X0Y4_WW4END[6]
    DIRECTION INPUT ;
    USE SIGNAL ;
    ANTENNAGATEAREA 0.639600 ;
    ANTENNADIFFAREA 6.046200 ;
    PORT
      LAYER Metal3 ;
        RECT 146.960 339.160 147.360 339.560 ;
    END
  END Tile_X0Y4_WW4END[6]
  PIN Tile_X0Y4_WW4END[7]
    DIRECTION INPUT ;
    USE SIGNAL ;
    ANTENNAGATEAREA 0.639600 ;
    ANTENNADIFFAREA 6.046200 ;
    PORT
      LAYER Metal3 ;
        RECT 146.960 340.840 147.360 341.240 ;
    END
  END Tile_X0Y4_WW4END[7]
  PIN Tile_X0Y4_WW4END[8]
    DIRECTION INPUT ;
    USE SIGNAL ;
    ANTENNAGATEAREA 0.639600 ;
    ANTENNADIFFAREA 6.046200 ;
    PORT
      LAYER Metal3 ;
        RECT 146.960 342.520 147.360 342.920 ;
    END
  END Tile_X0Y4_WW4END[8]
  PIN Tile_X0Y4_WW4END[9]
    DIRECTION INPUT ;
    USE SIGNAL ;
    ANTENNAGATEAREA 0.639600 ;
    ANTENNADIFFAREA 6.046200 ;
    PORT
      LAYER Metal3 ;
        RECT 146.960 344.200 147.360 344.600 ;
    END
  END Tile_X0Y4_WW4END[9]
  PIN Tile_X0Y5_E1BEG[0]
    DIRECTION OUTPUT ;
    USE SIGNAL ;
    ANTENNADIFFAREA 2.724000 ;
    PORT
      LAYER Metal3 ;
        RECT 146.960 1.060 147.360 1.460 ;
    END
  END Tile_X0Y5_E1BEG[0]
  PIN Tile_X0Y5_E1BEG[1]
    DIRECTION OUTPUT ;
    USE SIGNAL ;
    ANTENNADIFFAREA 2.724000 ;
    PORT
      LAYER Metal3 ;
        RECT 146.960 2.740 147.360 3.140 ;
    END
  END Tile_X0Y5_E1BEG[1]
  PIN Tile_X0Y5_E1BEG[2]
    DIRECTION OUTPUT ;
    USE SIGNAL ;
    ANTENNADIFFAREA 2.724000 ;
    PORT
      LAYER Metal3 ;
        RECT 146.960 4.420 147.360 4.820 ;
    END
  END Tile_X0Y5_E1BEG[2]
  PIN Tile_X0Y5_E1BEG[3]
    DIRECTION OUTPUT ;
    USE SIGNAL ;
    ANTENNADIFFAREA 2.724000 ;
    PORT
      LAYER Metal3 ;
        RECT 146.960 6.100 147.360 6.500 ;
    END
  END Tile_X0Y5_E1BEG[3]
  PIN Tile_X0Y5_E2BEG[0]
    DIRECTION OUTPUT ;
    USE SIGNAL ;
    ANTENNADIFFAREA 2.724000 ;
    PORT
      LAYER Metal3 ;
        RECT 146.960 10.300 147.360 10.700 ;
    END
  END Tile_X0Y5_E2BEG[0]
  PIN Tile_X0Y5_E2BEG[1]
    DIRECTION OUTPUT ;
    USE SIGNAL ;
    ANTENNADIFFAREA 2.724000 ;
    PORT
      LAYER Metal3 ;
        RECT 146.960 11.140 147.360 11.540 ;
    END
  END Tile_X0Y5_E2BEG[1]
  PIN Tile_X0Y5_E2BEG[2]
    DIRECTION OUTPUT ;
    USE SIGNAL ;
    ANTENNADIFFAREA 2.724000 ;
    PORT
      LAYER Metal3 ;
        RECT 146.960 11.980 147.360 12.380 ;
    END
  END Tile_X0Y5_E2BEG[2]
  PIN Tile_X0Y5_E2BEG[3]
    DIRECTION OUTPUT ;
    USE SIGNAL ;
    ANTENNADIFFAREA 2.724000 ;
    PORT
      LAYER Metal3 ;
        RECT 146.960 12.820 147.360 13.220 ;
    END
  END Tile_X0Y5_E2BEG[3]
  PIN Tile_X0Y5_E2BEG[4]
    DIRECTION OUTPUT ;
    USE SIGNAL ;
    ANTENNADIFFAREA 2.724000 ;
    PORT
      LAYER Metal3 ;
        RECT 146.960 13.660 147.360 14.060 ;
    END
  END Tile_X0Y5_E2BEG[4]
  PIN Tile_X0Y5_E2BEG[5]
    DIRECTION OUTPUT ;
    USE SIGNAL ;
    ANTENNADIFFAREA 2.724000 ;
    PORT
      LAYER Metal3 ;
        RECT 146.960 14.500 147.360 14.900 ;
    END
  END Tile_X0Y5_E2BEG[5]
  PIN Tile_X0Y5_E2BEG[6]
    DIRECTION OUTPUT ;
    USE SIGNAL ;
    ANTENNADIFFAREA 2.724000 ;
    PORT
      LAYER Metal3 ;
        RECT 146.960 15.340 147.360 15.740 ;
    END
  END Tile_X0Y5_E2BEG[6]
  PIN Tile_X0Y5_E2BEG[7]
    DIRECTION OUTPUT ;
    USE SIGNAL ;
    ANTENNADIFFAREA 2.724000 ;
    PORT
      LAYER Metal3 ;
        RECT 146.960 16.180 147.360 16.580 ;
    END
  END Tile_X0Y5_E2BEG[7]
  PIN Tile_X0Y5_E2BEGb[0]
    DIRECTION OUTPUT ;
    USE SIGNAL ;
    ANTENNADIFFAREA 2.724000 ;
    PORT
      LAYER Metal3 ;
        RECT 146.960 20.380 147.360 20.780 ;
    END
  END Tile_X0Y5_E2BEGb[0]
  PIN Tile_X0Y5_E2BEGb[1]
    DIRECTION OUTPUT ;
    USE SIGNAL ;
    ANTENNADIFFAREA 2.724000 ;
    PORT
      LAYER Metal3 ;
        RECT 146.960 22.060 147.360 22.460 ;
    END
  END Tile_X0Y5_E2BEGb[1]
  PIN Tile_X0Y5_E2BEGb[2]
    DIRECTION OUTPUT ;
    USE SIGNAL ;
    ANTENNADIFFAREA 2.724000 ;
    PORT
      LAYER Metal3 ;
        RECT 146.960 23.740 147.360 24.140 ;
    END
  END Tile_X0Y5_E2BEGb[2]
  PIN Tile_X0Y5_E2BEGb[3]
    DIRECTION OUTPUT ;
    USE SIGNAL ;
    ANTENNADIFFAREA 2.724000 ;
    PORT
      LAYER Metal3 ;
        RECT 146.960 25.420 147.360 25.820 ;
    END
  END Tile_X0Y5_E2BEGb[3]
  PIN Tile_X0Y5_E2BEGb[4]
    DIRECTION OUTPUT ;
    USE SIGNAL ;
    ANTENNADIFFAREA 2.724000 ;
    PORT
      LAYER Metal3 ;
        RECT 146.960 27.100 147.360 27.500 ;
    END
  END Tile_X0Y5_E2BEGb[4]
  PIN Tile_X0Y5_E2BEGb[5]
    DIRECTION OUTPUT ;
    USE SIGNAL ;
    ANTENNADIFFAREA 2.724000 ;
    PORT
      LAYER Metal3 ;
        RECT 146.960 28.780 147.360 29.180 ;
    END
  END Tile_X0Y5_E2BEGb[5]
  PIN Tile_X0Y5_E2BEGb[6]
    DIRECTION OUTPUT ;
    USE SIGNAL ;
    ANTENNADIFFAREA 2.724000 ;
    PORT
      LAYER Metal3 ;
        RECT 146.960 30.460 147.360 30.860 ;
    END
  END Tile_X0Y5_E2BEGb[6]
  PIN Tile_X0Y5_E2BEGb[7]
    DIRECTION OUTPUT ;
    USE SIGNAL ;
    ANTENNADIFFAREA 2.724000 ;
    PORT
      LAYER Metal3 ;
        RECT 146.960 32.140 147.360 32.540 ;
    END
  END Tile_X0Y5_E2BEGb[7]
  PIN Tile_X0Y5_E6BEG[0]
    DIRECTION OUTPUT ;
    USE SIGNAL ;
    ANTENNADIFFAREA 2.724000 ;
    PORT
      LAYER Metal3 ;
        RECT 146.960 59.860 147.360 60.260 ;
    END
  END Tile_X0Y5_E6BEG[0]
  PIN Tile_X0Y5_E6BEG[10]
    DIRECTION OUTPUT ;
    USE SIGNAL ;
    ANTENNADIFFAREA 2.724000 ;
    PORT
      LAYER Metal3 ;
        RECT 146.960 76.660 147.360 77.060 ;
    END
  END Tile_X0Y5_E6BEG[10]
  PIN Tile_X0Y5_E6BEG[11]
    DIRECTION OUTPUT ;
    USE SIGNAL ;
    ANTENNADIFFAREA 2.724000 ;
    PORT
      LAYER Metal3 ;
        RECT 146.960 78.340 147.360 78.740 ;
    END
  END Tile_X0Y5_E6BEG[11]
  PIN Tile_X0Y5_E6BEG[1]
    DIRECTION OUTPUT ;
    USE SIGNAL ;
    ANTENNADIFFAREA 2.724000 ;
    PORT
      LAYER Metal3 ;
        RECT 146.960 61.540 147.360 61.940 ;
    END
  END Tile_X0Y5_E6BEG[1]
  PIN Tile_X0Y5_E6BEG[2]
    DIRECTION OUTPUT ;
    USE SIGNAL ;
    ANTENNADIFFAREA 2.724000 ;
    PORT
      LAYER Metal3 ;
        RECT 146.960 63.220 147.360 63.620 ;
    END
  END Tile_X0Y5_E6BEG[2]
  PIN Tile_X0Y5_E6BEG[3]
    DIRECTION OUTPUT ;
    USE SIGNAL ;
    ANTENNADIFFAREA 2.724000 ;
    PORT
      LAYER Metal3 ;
        RECT 146.960 64.900 147.360 65.300 ;
    END
  END Tile_X0Y5_E6BEG[3]
  PIN Tile_X0Y5_E6BEG[4]
    DIRECTION OUTPUT ;
    USE SIGNAL ;
    ANTENNADIFFAREA 2.724000 ;
    PORT
      LAYER Metal3 ;
        RECT 146.960 66.580 147.360 66.980 ;
    END
  END Tile_X0Y5_E6BEG[4]
  PIN Tile_X0Y5_E6BEG[5]
    DIRECTION OUTPUT ;
    USE SIGNAL ;
    ANTENNADIFFAREA 2.724000 ;
    PORT
      LAYER Metal3 ;
        RECT 146.960 68.260 147.360 68.660 ;
    END
  END Tile_X0Y5_E6BEG[5]
  PIN Tile_X0Y5_E6BEG[6]
    DIRECTION OUTPUT ;
    USE SIGNAL ;
    ANTENNADIFFAREA 2.724000 ;
    PORT
      LAYER Metal3 ;
        RECT 146.960 69.940 147.360 70.340 ;
    END
  END Tile_X0Y5_E6BEG[6]
  PIN Tile_X0Y5_E6BEG[7]
    DIRECTION OUTPUT ;
    USE SIGNAL ;
    ANTENNADIFFAREA 2.724000 ;
    PORT
      LAYER Metal3 ;
        RECT 146.960 71.620 147.360 72.020 ;
    END
  END Tile_X0Y5_E6BEG[7]
  PIN Tile_X0Y5_E6BEG[8]
    DIRECTION OUTPUT ;
    USE SIGNAL ;
    ANTENNADIFFAREA 2.724000 ;
    PORT
      LAYER Metal3 ;
        RECT 146.960 73.300 147.360 73.700 ;
    END
  END Tile_X0Y5_E6BEG[8]
  PIN Tile_X0Y5_E6BEG[9]
    DIRECTION OUTPUT ;
    USE SIGNAL ;
    ANTENNADIFFAREA 2.724000 ;
    PORT
      LAYER Metal3 ;
        RECT 146.960 74.980 147.360 75.380 ;
    END
  END Tile_X0Y5_E6BEG[9]
  PIN Tile_X0Y5_EE4BEG[0]
    DIRECTION OUTPUT ;
    USE SIGNAL ;
    ANTENNADIFFAREA 2.724000 ;
    PORT
      LAYER Metal3 ;
        RECT 146.960 39.700 147.360 40.100 ;
    END
  END Tile_X0Y5_EE4BEG[0]
  PIN Tile_X0Y5_EE4BEG[10]
    DIRECTION OUTPUT ;
    USE SIGNAL ;
    ANTENNADIFFAREA 2.724000 ;
    PORT
      LAYER Metal3 ;
        RECT 146.960 48.100 147.360 48.500 ;
    END
  END Tile_X0Y5_EE4BEG[10]
  PIN Tile_X0Y5_EE4BEG[11]
    DIRECTION OUTPUT ;
    USE SIGNAL ;
    ANTENNADIFFAREA 2.724000 ;
    PORT
      LAYER Metal3 ;
        RECT 146.960 48.940 147.360 49.340 ;
    END
  END Tile_X0Y5_EE4BEG[11]
  PIN Tile_X0Y5_EE4BEG[12]
    DIRECTION OUTPUT ;
    USE SIGNAL ;
    ANTENNADIFFAREA 2.724000 ;
    PORT
      LAYER Metal3 ;
        RECT 146.960 49.780 147.360 50.180 ;
    END
  END Tile_X0Y5_EE4BEG[12]
  PIN Tile_X0Y5_EE4BEG[13]
    DIRECTION OUTPUT ;
    USE SIGNAL ;
    ANTENNADIFFAREA 2.724000 ;
    PORT
      LAYER Metal3 ;
        RECT 146.960 50.620 147.360 51.020 ;
    END
  END Tile_X0Y5_EE4BEG[13]
  PIN Tile_X0Y5_EE4BEG[14]
    DIRECTION OUTPUT ;
    USE SIGNAL ;
    ANTENNADIFFAREA 2.724000 ;
    PORT
      LAYER Metal3 ;
        RECT 146.960 51.460 147.360 51.860 ;
    END
  END Tile_X0Y5_EE4BEG[14]
  PIN Tile_X0Y5_EE4BEG[15]
    DIRECTION OUTPUT ;
    USE SIGNAL ;
    ANTENNADIFFAREA 2.724000 ;
    PORT
      LAYER Metal3 ;
        RECT 146.960 52.300 147.360 52.700 ;
    END
  END Tile_X0Y5_EE4BEG[15]
  PIN Tile_X0Y5_EE4BEG[1]
    DIRECTION OUTPUT ;
    USE SIGNAL ;
    ANTENNADIFFAREA 2.724000 ;
    PORT
      LAYER Metal3 ;
        RECT 146.960 40.540 147.360 40.940 ;
    END
  END Tile_X0Y5_EE4BEG[1]
  PIN Tile_X0Y5_EE4BEG[2]
    DIRECTION OUTPUT ;
    USE SIGNAL ;
    ANTENNADIFFAREA 2.724000 ;
    PORT
      LAYER Metal3 ;
        RECT 146.960 41.380 147.360 41.780 ;
    END
  END Tile_X0Y5_EE4BEG[2]
  PIN Tile_X0Y5_EE4BEG[3]
    DIRECTION OUTPUT ;
    USE SIGNAL ;
    ANTENNADIFFAREA 2.724000 ;
    PORT
      LAYER Metal3 ;
        RECT 146.960 42.220 147.360 42.620 ;
    END
  END Tile_X0Y5_EE4BEG[3]
  PIN Tile_X0Y5_EE4BEG[4]
    DIRECTION OUTPUT ;
    USE SIGNAL ;
    ANTENNADIFFAREA 2.724000 ;
    PORT
      LAYER Metal3 ;
        RECT 146.960 43.060 147.360 43.460 ;
    END
  END Tile_X0Y5_EE4BEG[4]
  PIN Tile_X0Y5_EE4BEG[5]
    DIRECTION OUTPUT ;
    USE SIGNAL ;
    ANTENNADIFFAREA 2.724000 ;
    PORT
      LAYER Metal3 ;
        RECT 146.960 43.900 147.360 44.300 ;
    END
  END Tile_X0Y5_EE4BEG[5]
  PIN Tile_X0Y5_EE4BEG[6]
    DIRECTION OUTPUT ;
    USE SIGNAL ;
    ANTENNADIFFAREA 2.724000 ;
    PORT
      LAYER Metal3 ;
        RECT 146.960 44.740 147.360 45.140 ;
    END
  END Tile_X0Y5_EE4BEG[6]
  PIN Tile_X0Y5_EE4BEG[7]
    DIRECTION OUTPUT ;
    USE SIGNAL ;
    ANTENNADIFFAREA 2.724000 ;
    PORT
      LAYER Metal3 ;
        RECT 146.960 45.580 147.360 45.980 ;
    END
  END Tile_X0Y5_EE4BEG[7]
  PIN Tile_X0Y5_EE4BEG[8]
    DIRECTION OUTPUT ;
    USE SIGNAL ;
    ANTENNADIFFAREA 2.724000 ;
    PORT
      LAYER Metal3 ;
        RECT 146.960 46.420 147.360 46.820 ;
    END
  END Tile_X0Y5_EE4BEG[8]
  PIN Tile_X0Y5_EE4BEG[9]
    DIRECTION OUTPUT ;
    USE SIGNAL ;
    ANTENNADIFFAREA 2.724000 ;
    PORT
      LAYER Metal3 ;
        RECT 146.960 47.260 147.360 47.660 ;
    END
  END Tile_X0Y5_EE4BEG[9]
  PIN Tile_X0Y5_FrameData[0]
    DIRECTION INPUT ;
    USE SIGNAL ;
    ANTENNAGATEAREA 1.807000 ;
    ANTENNADIFFAREA 20.153999 ;
    PORT
      LAYER Metal3 ;
        RECT 0.000 5.260 0.400 5.660 ;
    END
  END Tile_X0Y5_FrameData[0]
  PIN Tile_X0Y5_FrameData[10]
    DIRECTION INPUT ;
    USE SIGNAL ;
    ANTENNAGATEAREA 1.807000 ;
    ANTENNADIFFAREA 20.153999 ;
    PORT
      LAYER Metal3 ;
        RECT 0.000 13.660 0.400 14.060 ;
    END
  END Tile_X0Y5_FrameData[10]
  PIN Tile_X0Y5_FrameData[11]
    DIRECTION INPUT ;
    USE SIGNAL ;
    ANTENNAGATEAREA 1.807000 ;
    ANTENNADIFFAREA 20.153999 ;
    PORT
      LAYER Metal3 ;
        RECT 0.000 14.500 0.400 14.900 ;
    END
  END Tile_X0Y5_FrameData[11]
  PIN Tile_X0Y5_FrameData[12]
    DIRECTION INPUT ;
    USE SIGNAL ;
    ANTENNAGATEAREA 1.807000 ;
    ANTENNADIFFAREA 20.153999 ;
    PORT
      LAYER Metal3 ;
        RECT 0.000 15.340 0.400 15.740 ;
    END
  END Tile_X0Y5_FrameData[12]
  PIN Tile_X0Y5_FrameData[13]
    DIRECTION INPUT ;
    USE SIGNAL ;
    ANTENNAGATEAREA 1.807000 ;
    ANTENNADIFFAREA 20.153999 ;
    PORT
      LAYER Metal3 ;
        RECT 0.000 16.180 0.400 16.580 ;
    END
  END Tile_X0Y5_FrameData[13]
  PIN Tile_X0Y5_FrameData[14]
    DIRECTION INPUT ;
    USE SIGNAL ;
    ANTENNAGATEAREA 1.807000 ;
    ANTENNADIFFAREA 20.153999 ;
    PORT
      LAYER Metal3 ;
        RECT 0.000 17.020 0.400 17.420 ;
    END
  END Tile_X0Y5_FrameData[14]
  PIN Tile_X0Y5_FrameData[15]
    DIRECTION INPUT ;
    USE SIGNAL ;
    ANTENNAGATEAREA 1.807000 ;
    ANTENNADIFFAREA 20.153999 ;
    PORT
      LAYER Metal3 ;
        RECT 0.000 17.860 0.400 18.260 ;
    END
  END Tile_X0Y5_FrameData[15]
  PIN Tile_X0Y5_FrameData[16]
    DIRECTION INPUT ;
    USE SIGNAL ;
    ANTENNAGATEAREA 1.807000 ;
    ANTENNADIFFAREA 20.153999 ;
    PORT
      LAYER Metal3 ;
        RECT 0.000 18.700 0.400 19.100 ;
    END
  END Tile_X0Y5_FrameData[16]
  PIN Tile_X0Y5_FrameData[17]
    DIRECTION INPUT ;
    USE SIGNAL ;
    ANTENNAGATEAREA 1.807000 ;
    ANTENNADIFFAREA 20.153999 ;
    PORT
      LAYER Metal3 ;
        RECT 0.000 19.540 0.400 19.940 ;
    END
  END Tile_X0Y5_FrameData[17]
  PIN Tile_X0Y5_FrameData[18]
    DIRECTION INPUT ;
    USE SIGNAL ;
    ANTENNAGATEAREA 1.807000 ;
    ANTENNADIFFAREA 20.153999 ;
    PORT
      LAYER Metal3 ;
        RECT 0.000 20.380 0.400 20.780 ;
    END
  END Tile_X0Y5_FrameData[18]
  PIN Tile_X0Y5_FrameData[19]
    DIRECTION INPUT ;
    USE SIGNAL ;
    ANTENNAGATEAREA 1.807000 ;
    ANTENNADIFFAREA 20.153999 ;
    PORT
      LAYER Metal3 ;
        RECT 0.000 21.220 0.400 21.620 ;
    END
  END Tile_X0Y5_FrameData[19]
  PIN Tile_X0Y5_FrameData[1]
    DIRECTION INPUT ;
    USE SIGNAL ;
    ANTENNAGATEAREA 1.807000 ;
    ANTENNADIFFAREA 20.153999 ;
    PORT
      LAYER Metal3 ;
        RECT 0.000 6.100 0.400 6.500 ;
    END
  END Tile_X0Y5_FrameData[1]
  PIN Tile_X0Y5_FrameData[20]
    DIRECTION INPUT ;
    USE SIGNAL ;
    ANTENNAGATEAREA 1.807000 ;
    ANTENNADIFFAREA 20.153999 ;
    PORT
      LAYER Metal3 ;
        RECT 0.000 22.060 0.400 22.460 ;
    END
  END Tile_X0Y5_FrameData[20]
  PIN Tile_X0Y5_FrameData[21]
    DIRECTION INPUT ;
    USE SIGNAL ;
    ANTENNAGATEAREA 1.807000 ;
    ANTENNADIFFAREA 20.153999 ;
    PORT
      LAYER Metal3 ;
        RECT 0.000 22.900 0.400 23.300 ;
    END
  END Tile_X0Y5_FrameData[21]
  PIN Tile_X0Y5_FrameData[22]
    DIRECTION INPUT ;
    USE SIGNAL ;
    ANTENNAGATEAREA 1.807000 ;
    ANTENNADIFFAREA 20.153999 ;
    PORT
      LAYER Metal3 ;
        RECT 0.000 23.740 0.400 24.140 ;
    END
  END Tile_X0Y5_FrameData[22]
  PIN Tile_X0Y5_FrameData[23]
    DIRECTION INPUT ;
    USE SIGNAL ;
    ANTENNAGATEAREA 1.807000 ;
    ANTENNADIFFAREA 20.153999 ;
    PORT
      LAYER Metal3 ;
        RECT 0.000 24.580 0.400 24.980 ;
    END
  END Tile_X0Y5_FrameData[23]
  PIN Tile_X0Y5_FrameData[24]
    DIRECTION INPUT ;
    USE SIGNAL ;
    ANTENNAGATEAREA 1.807000 ;
    ANTENNADIFFAREA 20.153999 ;
    PORT
      LAYER Metal3 ;
        RECT 0.000 25.420 0.400 25.820 ;
    END
  END Tile_X0Y5_FrameData[24]
  PIN Tile_X0Y5_FrameData[25]
    DIRECTION INPUT ;
    USE SIGNAL ;
    ANTENNAGATEAREA 1.807000 ;
    ANTENNADIFFAREA 20.153999 ;
    PORT
      LAYER Metal3 ;
        RECT 0.000 26.260 0.400 26.660 ;
    END
  END Tile_X0Y5_FrameData[25]
  PIN Tile_X0Y5_FrameData[26]
    DIRECTION INPUT ;
    USE SIGNAL ;
    ANTENNAGATEAREA 1.807000 ;
    ANTENNADIFFAREA 20.153999 ;
    PORT
      LAYER Metal3 ;
        RECT 0.000 27.100 0.400 27.500 ;
    END
  END Tile_X0Y5_FrameData[26]
  PIN Tile_X0Y5_FrameData[27]
    DIRECTION INPUT ;
    USE SIGNAL ;
    ANTENNAGATEAREA 1.807000 ;
    ANTENNADIFFAREA 20.153999 ;
    PORT
      LAYER Metal3 ;
        RECT 0.000 27.940 0.400 28.340 ;
    END
  END Tile_X0Y5_FrameData[27]
  PIN Tile_X0Y5_FrameData[28]
    DIRECTION INPUT ;
    USE SIGNAL ;
    ANTENNAGATEAREA 1.987700 ;
    ANTENNADIFFAREA 22.169399 ;
    PORT
      LAYER Metal3 ;
        RECT 0.000 28.780 0.400 29.180 ;
    END
  END Tile_X0Y5_FrameData[28]
  PIN Tile_X0Y5_FrameData[29]
    DIRECTION INPUT ;
    USE SIGNAL ;
    ANTENNAGATEAREA 1.987700 ;
    ANTENNADIFFAREA 22.169399 ;
    PORT
      LAYER Metal3 ;
        RECT 0.000 29.620 0.400 30.020 ;
    END
  END Tile_X0Y5_FrameData[29]
  PIN Tile_X0Y5_FrameData[2]
    DIRECTION INPUT ;
    USE SIGNAL ;
    ANTENNAGATEAREA 1.807000 ;
    ANTENNADIFFAREA 20.153999 ;
    PORT
      LAYER Metal3 ;
        RECT 0.000 6.940 0.400 7.340 ;
    END
  END Tile_X0Y5_FrameData[2]
  PIN Tile_X0Y5_FrameData[30]
    DIRECTION INPUT ;
    USE SIGNAL ;
    ANTENNAGATEAREA 1.987700 ;
    ANTENNADIFFAREA 22.169399 ;
    PORT
      LAYER Metal3 ;
        RECT 0.000 30.460 0.400 30.860 ;
    END
  END Tile_X0Y5_FrameData[30]
  PIN Tile_X0Y5_FrameData[31]
    DIRECTION INPUT ;
    USE SIGNAL ;
    ANTENNAGATEAREA 1.987700 ;
    ANTENNADIFFAREA 22.169399 ;
    PORT
      LAYER Metal3 ;
        RECT 0.000 31.300 0.400 31.700 ;
    END
  END Tile_X0Y5_FrameData[31]
  PIN Tile_X0Y5_FrameData[3]
    DIRECTION INPUT ;
    USE SIGNAL ;
    ANTENNAGATEAREA 1.807000 ;
    ANTENNADIFFAREA 20.153999 ;
    PORT
      LAYER Metal3 ;
        RECT 0.000 7.780 0.400 8.180 ;
    END
  END Tile_X0Y5_FrameData[3]
  PIN Tile_X0Y5_FrameData[4]
    DIRECTION INPUT ;
    USE SIGNAL ;
    ANTENNAGATEAREA 1.807000 ;
    ANTENNADIFFAREA 20.153999 ;
    PORT
      LAYER Metal3 ;
        RECT 0.000 8.620 0.400 9.020 ;
    END
  END Tile_X0Y5_FrameData[4]
  PIN Tile_X0Y5_FrameData[5]
    DIRECTION INPUT ;
    USE SIGNAL ;
    ANTENNAGATEAREA 1.807000 ;
    ANTENNADIFFAREA 20.153999 ;
    PORT
      LAYER Metal3 ;
        RECT 0.000 9.460 0.400 9.860 ;
    END
  END Tile_X0Y5_FrameData[5]
  PIN Tile_X0Y5_FrameData[6]
    DIRECTION INPUT ;
    USE SIGNAL ;
    ANTENNAGATEAREA 1.807000 ;
    ANTENNADIFFAREA 20.153999 ;
    PORT
      LAYER Metal3 ;
        RECT 0.000 10.300 0.400 10.700 ;
    END
  END Tile_X0Y5_FrameData[6]
  PIN Tile_X0Y5_FrameData[7]
    DIRECTION INPUT ;
    USE SIGNAL ;
    ANTENNAGATEAREA 1.807000 ;
    ANTENNADIFFAREA 20.153999 ;
    PORT
      LAYER Metal3 ;
        RECT 0.000 11.140 0.400 11.540 ;
    END
  END Tile_X0Y5_FrameData[7]
  PIN Tile_X0Y5_FrameData[8]
    DIRECTION INPUT ;
    USE SIGNAL ;
    ANTENNAGATEAREA 1.807000 ;
    ANTENNADIFFAREA 20.153999 ;
    PORT
      LAYER Metal3 ;
        RECT 0.000 11.980 0.400 12.380 ;
    END
  END Tile_X0Y5_FrameData[8]
  PIN Tile_X0Y5_FrameData[9]
    DIRECTION INPUT ;
    USE SIGNAL ;
    ANTENNAGATEAREA 1.807000 ;
    ANTENNADIFFAREA 20.153999 ;
    PORT
      LAYER Metal3 ;
        RECT 0.000 12.820 0.400 13.220 ;
    END
  END Tile_X0Y5_FrameData[9]
  PIN Tile_X0Y5_FrameData_O[0]
    DIRECTION OUTPUT ;
    USE SIGNAL ;
    ANTENNADIFFAREA 2.724000 ;
    PORT
      LAYER Metal3 ;
        RECT 146.960 162.340 147.360 162.740 ;
    END
  END Tile_X0Y5_FrameData_O[0]
  PIN Tile_X0Y5_FrameData_O[10]
    DIRECTION OUTPUT ;
    USE SIGNAL ;
    ANTENNADIFFAREA 2.724000 ;
    PORT
      LAYER Metal3 ;
        RECT 146.960 179.140 147.360 179.540 ;
    END
  END Tile_X0Y5_FrameData_O[10]
  PIN Tile_X0Y5_FrameData_O[11]
    DIRECTION OUTPUT ;
    USE SIGNAL ;
    ANTENNADIFFAREA 2.724000 ;
    PORT
      LAYER Metal3 ;
        RECT 146.960 180.820 147.360 181.220 ;
    END
  END Tile_X0Y5_FrameData_O[11]
  PIN Tile_X0Y5_FrameData_O[12]
    DIRECTION OUTPUT ;
    USE SIGNAL ;
    ANTENNADIFFAREA 2.724000 ;
    PORT
      LAYER Metal3 ;
        RECT 146.960 182.500 147.360 182.900 ;
    END
  END Tile_X0Y5_FrameData_O[12]
  PIN Tile_X0Y5_FrameData_O[13]
    DIRECTION OUTPUT ;
    USE SIGNAL ;
    ANTENNADIFFAREA 2.724000 ;
    PORT
      LAYER Metal3 ;
        RECT 146.960 184.180 147.360 184.580 ;
    END
  END Tile_X0Y5_FrameData_O[13]
  PIN Tile_X0Y5_FrameData_O[14]
    DIRECTION OUTPUT ;
    USE SIGNAL ;
    ANTENNADIFFAREA 2.724000 ;
    PORT
      LAYER Metal3 ;
        RECT 146.960 185.860 147.360 186.260 ;
    END
  END Tile_X0Y5_FrameData_O[14]
  PIN Tile_X0Y5_FrameData_O[15]
    DIRECTION OUTPUT ;
    USE SIGNAL ;
    ANTENNADIFFAREA 2.724000 ;
    PORT
      LAYER Metal3 ;
        RECT 146.960 187.540 147.360 187.940 ;
    END
  END Tile_X0Y5_FrameData_O[15]
  PIN Tile_X0Y5_FrameData_O[16]
    DIRECTION OUTPUT ;
    USE SIGNAL ;
    ANTENNADIFFAREA 2.724000 ;
    PORT
      LAYER Metal3 ;
        RECT 146.960 189.220 147.360 189.620 ;
    END
  END Tile_X0Y5_FrameData_O[16]
  PIN Tile_X0Y5_FrameData_O[17]
    DIRECTION OUTPUT ;
    USE SIGNAL ;
    ANTENNADIFFAREA 2.724000 ;
    PORT
      LAYER Metal3 ;
        RECT 146.960 190.900 147.360 191.300 ;
    END
  END Tile_X0Y5_FrameData_O[17]
  PIN Tile_X0Y5_FrameData_O[18]
    DIRECTION OUTPUT ;
    USE SIGNAL ;
    ANTENNADIFFAREA 2.724000 ;
    PORT
      LAYER Metal3 ;
        RECT 146.960 192.580 147.360 192.980 ;
    END
  END Tile_X0Y5_FrameData_O[18]
  PIN Tile_X0Y5_FrameData_O[19]
    DIRECTION OUTPUT ;
    USE SIGNAL ;
    ANTENNADIFFAREA 2.724000 ;
    PORT
      LAYER Metal3 ;
        RECT 146.960 194.260 147.360 194.660 ;
    END
  END Tile_X0Y5_FrameData_O[19]
  PIN Tile_X0Y5_FrameData_O[1]
    DIRECTION OUTPUT ;
    USE SIGNAL ;
    ANTENNADIFFAREA 2.724000 ;
    PORT
      LAYER Metal3 ;
        RECT 146.960 164.020 147.360 164.420 ;
    END
  END Tile_X0Y5_FrameData_O[1]
  PIN Tile_X0Y5_FrameData_O[20]
    DIRECTION OUTPUT ;
    USE SIGNAL ;
    ANTENNADIFFAREA 2.724000 ;
    PORT
      LAYER Metal3 ;
        RECT 146.960 195.940 147.360 196.340 ;
    END
  END Tile_X0Y5_FrameData_O[20]
  PIN Tile_X0Y5_FrameData_O[21]
    DIRECTION OUTPUT ;
    USE SIGNAL ;
    ANTENNADIFFAREA 2.724000 ;
    PORT
      LAYER Metal3 ;
        RECT 146.960 197.620 147.360 198.020 ;
    END
  END Tile_X0Y5_FrameData_O[21]
  PIN Tile_X0Y5_FrameData_O[22]
    DIRECTION OUTPUT ;
    USE SIGNAL ;
    ANTENNADIFFAREA 2.724000 ;
    PORT
      LAYER Metal3 ;
        RECT 146.960 199.300 147.360 199.700 ;
    END
  END Tile_X0Y5_FrameData_O[22]
  PIN Tile_X0Y5_FrameData_O[23]
    DIRECTION OUTPUT ;
    USE SIGNAL ;
    ANTENNADIFFAREA 2.724000 ;
    PORT
      LAYER Metal3 ;
        RECT 146.960 200.980 147.360 201.380 ;
    END
  END Tile_X0Y5_FrameData_O[23]
  PIN Tile_X0Y5_FrameData_O[24]
    DIRECTION OUTPUT ;
    USE SIGNAL ;
    ANTENNADIFFAREA 2.724000 ;
    PORT
      LAYER Metal3 ;
        RECT 146.960 202.660 147.360 203.060 ;
    END
  END Tile_X0Y5_FrameData_O[24]
  PIN Tile_X0Y5_FrameData_O[25]
    DIRECTION OUTPUT ;
    USE SIGNAL ;
    ANTENNADIFFAREA 2.724000 ;
    PORT
      LAYER Metal3 ;
        RECT 146.960 204.340 147.360 204.740 ;
    END
  END Tile_X0Y5_FrameData_O[25]
  PIN Tile_X0Y5_FrameData_O[26]
    DIRECTION OUTPUT ;
    USE SIGNAL ;
    ANTENNADIFFAREA 2.724000 ;
    PORT
      LAYER Metal3 ;
        RECT 146.960 206.020 147.360 206.420 ;
    END
  END Tile_X0Y5_FrameData_O[26]
  PIN Tile_X0Y5_FrameData_O[27]
    DIRECTION OUTPUT ;
    USE SIGNAL ;
    ANTENNADIFFAREA 2.724000 ;
    PORT
      LAYER Metal3 ;
        RECT 146.960 207.700 147.360 208.100 ;
    END
  END Tile_X0Y5_FrameData_O[27]
  PIN Tile_X0Y5_FrameData_O[28]
    DIRECTION OUTPUT ;
    USE SIGNAL ;
    ANTENNADIFFAREA 2.724000 ;
    PORT
      LAYER Metal3 ;
        RECT 146.960 209.380 147.360 209.780 ;
    END
  END Tile_X0Y5_FrameData_O[28]
  PIN Tile_X0Y5_FrameData_O[29]
    DIRECTION OUTPUT ;
    USE SIGNAL ;
    ANTENNADIFFAREA 2.724000 ;
    PORT
      LAYER Metal3 ;
        RECT 146.960 211.060 147.360 211.460 ;
    END
  END Tile_X0Y5_FrameData_O[29]
  PIN Tile_X0Y5_FrameData_O[2]
    DIRECTION OUTPUT ;
    USE SIGNAL ;
    ANTENNADIFFAREA 2.724000 ;
    PORT
      LAYER Metal3 ;
        RECT 146.960 165.700 147.360 166.100 ;
    END
  END Tile_X0Y5_FrameData_O[2]
  PIN Tile_X0Y5_FrameData_O[30]
    DIRECTION OUTPUT ;
    USE SIGNAL ;
    ANTENNADIFFAREA 2.724000 ;
    PORT
      LAYER Metal3 ;
        RECT 146.960 212.740 147.360 213.140 ;
    END
  END Tile_X0Y5_FrameData_O[30]
  PIN Tile_X0Y5_FrameData_O[31]
    DIRECTION OUTPUT ;
    USE SIGNAL ;
    ANTENNADIFFAREA 2.724000 ;
    PORT
      LAYER Metal3 ;
        RECT 146.960 214.420 147.360 214.820 ;
    END
  END Tile_X0Y5_FrameData_O[31]
  PIN Tile_X0Y5_FrameData_O[3]
    DIRECTION OUTPUT ;
    USE SIGNAL ;
    ANTENNADIFFAREA 2.724000 ;
    PORT
      LAYER Metal3 ;
        RECT 146.960 167.380 147.360 167.780 ;
    END
  END Tile_X0Y5_FrameData_O[3]
  PIN Tile_X0Y5_FrameData_O[4]
    DIRECTION OUTPUT ;
    USE SIGNAL ;
    ANTENNADIFFAREA 2.724000 ;
    PORT
      LAYER Metal3 ;
        RECT 146.960 169.060 147.360 169.460 ;
    END
  END Tile_X0Y5_FrameData_O[4]
  PIN Tile_X0Y5_FrameData_O[5]
    DIRECTION OUTPUT ;
    USE SIGNAL ;
    ANTENNADIFFAREA 2.724000 ;
    PORT
      LAYER Metal3 ;
        RECT 146.960 170.740 147.360 171.140 ;
    END
  END Tile_X0Y5_FrameData_O[5]
  PIN Tile_X0Y5_FrameData_O[6]
    DIRECTION OUTPUT ;
    USE SIGNAL ;
    ANTENNADIFFAREA 2.724000 ;
    PORT
      LAYER Metal3 ;
        RECT 146.960 172.420 147.360 172.820 ;
    END
  END Tile_X0Y5_FrameData_O[6]
  PIN Tile_X0Y5_FrameData_O[7]
    DIRECTION OUTPUT ;
    USE SIGNAL ;
    ANTENNADIFFAREA 2.724000 ;
    PORT
      LAYER Metal3 ;
        RECT 146.960 174.100 147.360 174.500 ;
    END
  END Tile_X0Y5_FrameData_O[7]
  PIN Tile_X0Y5_FrameData_O[8]
    DIRECTION OUTPUT ;
    USE SIGNAL ;
    ANTENNADIFFAREA 2.724000 ;
    PORT
      LAYER Metal3 ;
        RECT 146.960 175.780 147.360 176.180 ;
    END
  END Tile_X0Y5_FrameData_O[8]
  PIN Tile_X0Y5_FrameData_O[9]
    DIRECTION OUTPUT ;
    USE SIGNAL ;
    ANTENNADIFFAREA 2.724000 ;
    PORT
      LAYER Metal3 ;
        RECT 146.960 177.460 147.360 177.860 ;
    END
  END Tile_X0Y5_FrameData_O[9]
  PIN Tile_X0Y5_FrameStrobe[0]
    DIRECTION INPUT ;
    USE SIGNAL ;
    ANTENNAGATEAREA 39.617500 ;
    ANTENNADIFFAREA 388.972198 ;
    PORT
      LAYER Metal2 ;
        RECT 122.200 0.000 122.600 0.400 ;
    END
  END Tile_X0Y5_FrameStrobe[0]
  PIN Tile_X0Y5_FrameStrobe[10]
    DIRECTION INPUT ;
    USE SIGNAL ;
    ANTENNAGATEAREA 0.180700 ;
    ANTENNADIFFAREA 2.015400 ;
    PORT
      LAYER Metal2 ;
        RECT 131.800 0.000 132.200 0.400 ;
    END
  END Tile_X0Y5_FrameStrobe[10]
  PIN Tile_X0Y5_FrameStrobe[11]
    DIRECTION INPUT ;
    USE SIGNAL ;
    ANTENNAGATEAREA 0.180700 ;
    ANTENNADIFFAREA 2.015400 ;
    PORT
      LAYER Metal2 ;
        RECT 132.760 0.000 133.160 0.400 ;
    END
  END Tile_X0Y5_FrameStrobe[11]
  PIN Tile_X0Y5_FrameStrobe[12]
    DIRECTION INPUT ;
    USE SIGNAL ;
    ANTENNAGATEAREA 0.180700 ;
    ANTENNADIFFAREA 2.015400 ;
    PORT
      LAYER Metal2 ;
        RECT 133.720 0.000 134.120 0.400 ;
    END
  END Tile_X0Y5_FrameStrobe[12]
  PIN Tile_X0Y5_FrameStrobe[13]
    DIRECTION INPUT ;
    USE SIGNAL ;
    ANTENNAGATEAREA 0.180700 ;
    ANTENNADIFFAREA 2.015400 ;
    PORT
      LAYER Metal2 ;
        RECT 134.680 0.000 135.080 0.400 ;
    END
  END Tile_X0Y5_FrameStrobe[13]
  PIN Tile_X0Y5_FrameStrobe[14]
    DIRECTION INPUT ;
    USE SIGNAL ;
    ANTENNAGATEAREA 0.180700 ;
    ANTENNADIFFAREA 2.015400 ;
    PORT
      LAYER Metal2 ;
        RECT 135.640 0.000 136.040 0.400 ;
    END
  END Tile_X0Y5_FrameStrobe[14]
  PIN Tile_X0Y5_FrameStrobe[15]
    DIRECTION INPUT ;
    USE SIGNAL ;
    ANTENNAGATEAREA 0.180700 ;
    ANTENNADIFFAREA 2.015400 ;
    PORT
      LAYER Metal2 ;
        RECT 136.600 0.000 137.000 0.400 ;
    END
  END Tile_X0Y5_FrameStrobe[15]
  PIN Tile_X0Y5_FrameStrobe[16]
    DIRECTION INPUT ;
    USE SIGNAL ;
    ANTENNAGATEAREA 0.180700 ;
    ANTENNADIFFAREA 2.015400 ;
    PORT
      LAYER Metal2 ;
        RECT 137.560 0.000 137.960 0.400 ;
    END
  END Tile_X0Y5_FrameStrobe[16]
  PIN Tile_X0Y5_FrameStrobe[17]
    DIRECTION INPUT ;
    USE SIGNAL ;
    ANTENNAGATEAREA 0.180700 ;
    ANTENNADIFFAREA 2.015400 ;
    PORT
      LAYER Metal2 ;
        RECT 138.520 0.000 138.920 0.400 ;
    END
  END Tile_X0Y5_FrameStrobe[17]
  PIN Tile_X0Y5_FrameStrobe[18]
    DIRECTION INPUT ;
    USE SIGNAL ;
    ANTENNAGATEAREA 0.180700 ;
    ANTENNADIFFAREA 2.015400 ;
    PORT
      LAYER Metal2 ;
        RECT 139.480 0.000 139.880 0.400 ;
    END
  END Tile_X0Y5_FrameStrobe[18]
  PIN Tile_X0Y5_FrameStrobe[19]
    DIRECTION INPUT ;
    USE SIGNAL ;
    ANTENNAGATEAREA 0.180700 ;
    ANTENNADIFFAREA 2.015400 ;
    PORT
      LAYER Metal2 ;
        RECT 140.440 0.000 140.840 0.400 ;
    END
  END Tile_X0Y5_FrameStrobe[19]
  PIN Tile_X0Y5_FrameStrobe[1]
    DIRECTION INPUT ;
    USE SIGNAL ;
    ANTENNAGATEAREA 39.617500 ;
    ANTENNADIFFAREA 388.972198 ;
    PORT
      LAYER Metal2 ;
        RECT 123.160 0.000 123.560 0.400 ;
    END
  END Tile_X0Y5_FrameStrobe[1]
  PIN Tile_X0Y5_FrameStrobe[2]
    DIRECTION INPUT ;
    USE SIGNAL ;
    ANTENNAGATEAREA 39.617500 ;
    ANTENNADIFFAREA 388.972198 ;
    PORT
      LAYER Metal2 ;
        RECT 124.120 0.000 124.520 0.400 ;
    END
  END Tile_X0Y5_FrameStrobe[2]
  PIN Tile_X0Y5_FrameStrobe[3]
    DIRECTION INPUT ;
    USE SIGNAL ;
    ANTENNAGATEAREA 39.617500 ;
    ANTENNADIFFAREA 388.972198 ;
    PORT
      LAYER Metal2 ;
        RECT 125.080 0.000 125.480 0.400 ;
    END
  END Tile_X0Y5_FrameStrobe[3]
  PIN Tile_X0Y5_FrameStrobe[4]
    DIRECTION INPUT ;
    USE SIGNAL ;
    ANTENNAGATEAREA 39.617500 ;
    ANTENNADIFFAREA 388.972198 ;
    PORT
      LAYER Metal2 ;
        RECT 126.040 0.000 126.440 0.400 ;
    END
  END Tile_X0Y5_FrameStrobe[4]
  PIN Tile_X0Y5_FrameStrobe[5]
    DIRECTION INPUT ;
    USE SIGNAL ;
    ANTENNAGATEAREA 39.617500 ;
    ANTENNADIFFAREA 388.972198 ;
    PORT
      LAYER Metal2 ;
        RECT 127.000 0.000 127.400 0.400 ;
    END
  END Tile_X0Y5_FrameStrobe[5]
  PIN Tile_X0Y5_FrameStrobe[6]
    DIRECTION INPUT ;
    USE SIGNAL ;
    ANTENNAGATEAREA 39.617500 ;
    ANTENNADIFFAREA 388.972198 ;
    PORT
      LAYER Metal2 ;
        RECT 127.960 0.000 128.360 0.400 ;
    END
  END Tile_X0Y5_FrameStrobe[6]
  PIN Tile_X0Y5_FrameStrobe[7]
    DIRECTION INPUT ;
    USE SIGNAL ;
    ANTENNAGATEAREA 39.617500 ;
    ANTENNADIFFAREA 388.972198 ;
    PORT
      LAYER Metal2 ;
        RECT 128.920 0.000 129.320 0.400 ;
    END
  END Tile_X0Y5_FrameStrobe[7]
  PIN Tile_X0Y5_FrameStrobe[8]
    DIRECTION INPUT ;
    USE SIGNAL ;
    ANTENNAGATEAREA 23.185499 ;
    ANTENNADIFFAREA 227.740189 ;
    PORT
      LAYER Metal2 ;
        RECT 129.880 0.000 130.280 0.400 ;
    END
  END Tile_X0Y5_FrameStrobe[8]
  PIN Tile_X0Y5_FrameStrobe[9]
    DIRECTION INPUT ;
    USE SIGNAL ;
    ANTENNAGATEAREA 1.002300 ;
    ANTENNADIFFAREA 10.077000 ;
    PORT
      LAYER Metal2 ;
        RECT 130.840 0.000 131.240 0.400 ;
    END
  END Tile_X0Y5_FrameStrobe[9]
  PIN Tile_X0Y5_N1END[0]
    DIRECTION INPUT ;
    USE SIGNAL ;
    ANTENNAGATEAREA 1.246700 ;
    ANTENNADIFFAREA 12.092400 ;
    PORT
      LAYER Metal2 ;
        RECT 2.200 0.000 2.600 0.400 ;
    END
  END Tile_X0Y5_N1END[0]
  PIN Tile_X0Y5_N1END[1]
    DIRECTION INPUT ;
    USE SIGNAL ;
    ANTENNAGATEAREA 1.246700 ;
    ANTENNADIFFAREA 12.092400 ;
    PORT
      LAYER Metal2 ;
        RECT 3.160 0.000 3.560 0.400 ;
    END
  END Tile_X0Y5_N1END[1]
  PIN Tile_X0Y5_N1END[2]
    DIRECTION INPUT ;
    USE SIGNAL ;
    ANTENNAGATEAREA 1.246700 ;
    ANTENNADIFFAREA 12.092400 ;
    PORT
      LAYER Metal2 ;
        RECT 4.120 0.000 4.520 0.400 ;
    END
  END Tile_X0Y5_N1END[2]
  PIN Tile_X0Y5_N1END[3]
    DIRECTION INPUT ;
    USE SIGNAL ;
    ANTENNAGATEAREA 1.246700 ;
    ANTENNADIFFAREA 12.092400 ;
    PORT
      LAYER Metal2 ;
        RECT 5.080 0.000 5.480 0.400 ;
    END
  END Tile_X0Y5_N1END[3]
  PIN Tile_X0Y5_N2END[0]
    DIRECTION INPUT ;
    USE SIGNAL ;
    ANTENNAGATEAREA 0.213200 ;
    ANTENNADIFFAREA 2.015400 ;
    PORT
      LAYER Metal2 ;
        RECT 22.360 0.000 22.760 0.400 ;
    END
  END Tile_X0Y5_N2END[0]
  PIN Tile_X0Y5_N2END[1]
    DIRECTION INPUT ;
    USE SIGNAL ;
    ANTENNAGATEAREA 0.213200 ;
    ANTENNADIFFAREA 2.015400 ;
    PORT
      LAYER Metal2 ;
        RECT 23.320 0.000 23.720 0.400 ;
    END
  END Tile_X0Y5_N2END[1]
  PIN Tile_X0Y5_N2END[2]
    DIRECTION INPUT ;
    USE SIGNAL ;
    ANTENNAGATEAREA 0.213200 ;
    ANTENNADIFFAREA 2.015400 ;
    PORT
      LAYER Metal2 ;
        RECT 24.280 0.000 24.680 0.400 ;
    END
  END Tile_X0Y5_N2END[2]
  PIN Tile_X0Y5_N2END[3]
    DIRECTION INPUT ;
    USE SIGNAL ;
    ANTENNAGATEAREA 0.213200 ;
    ANTENNADIFFAREA 2.015400 ;
    PORT
      LAYER Metal2 ;
        RECT 25.240 0.000 25.640 0.400 ;
    END
  END Tile_X0Y5_N2END[3]
  PIN Tile_X0Y5_N2END[4]
    DIRECTION INPUT ;
    USE SIGNAL ;
    ANTENNAGATEAREA 0.213200 ;
    ANTENNADIFFAREA 2.015400 ;
    PORT
      LAYER Metal2 ;
        RECT 26.200 0.000 26.600 0.400 ;
    END
  END Tile_X0Y5_N2END[4]
  PIN Tile_X0Y5_N2END[5]
    DIRECTION INPUT ;
    USE SIGNAL ;
    ANTENNAGATEAREA 0.213200 ;
    ANTENNADIFFAREA 2.015400 ;
    PORT
      LAYER Metal2 ;
        RECT 27.160 0.000 27.560 0.400 ;
    END
  END Tile_X0Y5_N2END[5]
  PIN Tile_X0Y5_N2END[6]
    DIRECTION INPUT ;
    USE SIGNAL ;
    ANTENNAGATEAREA 0.213200 ;
    ANTENNADIFFAREA 2.015400 ;
    PORT
      LAYER Metal2 ;
        RECT 28.120 0.000 28.520 0.400 ;
    END
  END Tile_X0Y5_N2END[6]
  PIN Tile_X0Y5_N2END[7]
    DIRECTION INPUT ;
    USE SIGNAL ;
    ANTENNAGATEAREA 0.213200 ;
    ANTENNADIFFAREA 2.015400 ;
    PORT
      LAYER Metal2 ;
        RECT 29.080 0.000 29.480 0.400 ;
    END
  END Tile_X0Y5_N2END[7]
  PIN Tile_X0Y5_N2MID[0]
    DIRECTION INPUT ;
    USE SIGNAL ;
    ANTENNAGATEAREA 0.426400 ;
    ANTENNADIFFAREA 4.030800 ;
    PORT
      LAYER Metal2 ;
        RECT 9.880 0.000 10.280 0.400 ;
    END
  END Tile_X0Y5_N2MID[0]
  PIN Tile_X0Y5_N2MID[1]
    DIRECTION INPUT ;
    USE SIGNAL ;
    ANTENNAGATEAREA 0.426400 ;
    ANTENNADIFFAREA 4.030800 ;
    PORT
      LAYER Metal2 ;
        RECT 10.840 0.000 11.240 0.400 ;
    END
  END Tile_X0Y5_N2MID[1]
  PIN Tile_X0Y5_N2MID[2]
    DIRECTION INPUT ;
    USE SIGNAL ;
    ANTENNAGATEAREA 0.426400 ;
    ANTENNADIFFAREA 4.030800 ;
    PORT
      LAYER Metal2 ;
        RECT 11.800 0.000 12.200 0.400 ;
    END
  END Tile_X0Y5_N2MID[2]
  PIN Tile_X0Y5_N2MID[3]
    DIRECTION INPUT ;
    USE SIGNAL ;
    ANTENNAGATEAREA 0.426400 ;
    ANTENNADIFFAREA 4.030800 ;
    PORT
      LAYER Metal2 ;
        RECT 12.760 0.000 13.160 0.400 ;
    END
  END Tile_X0Y5_N2MID[3]
  PIN Tile_X0Y5_N2MID[4]
    DIRECTION INPUT ;
    USE SIGNAL ;
    ANTENNAGATEAREA 0.426400 ;
    ANTENNADIFFAREA 4.030800 ;
    PORT
      LAYER Metal2 ;
        RECT 13.720 0.000 14.120 0.400 ;
    END
  END Tile_X0Y5_N2MID[4]
  PIN Tile_X0Y5_N2MID[5]
    DIRECTION INPUT ;
    USE SIGNAL ;
    ANTENNAGATEAREA 0.426400 ;
    ANTENNADIFFAREA 4.030800 ;
    PORT
      LAYER Metal2 ;
        RECT 14.680 0.000 15.080 0.400 ;
    END
  END Tile_X0Y5_N2MID[5]
  PIN Tile_X0Y5_N2MID[6]
    DIRECTION INPUT ;
    USE SIGNAL ;
    ANTENNAGATEAREA 0.426400 ;
    ANTENNADIFFAREA 4.030800 ;
    PORT
      LAYER Metal2 ;
        RECT 15.640 0.000 16.040 0.400 ;
    END
  END Tile_X0Y5_N2MID[6]
  PIN Tile_X0Y5_N2MID[7]
    DIRECTION INPUT ;
    USE SIGNAL ;
    ANTENNAGATEAREA 0.426400 ;
    ANTENNADIFFAREA 8.061600 ;
    PORT
      LAYER Metal2 ;
        RECT 16.600 0.000 17.000 0.400 ;
    END
  END Tile_X0Y5_N2MID[7]
  PIN Tile_X0Y5_N4END[0]
    DIRECTION INPUT ;
    USE SIGNAL ;
    ANTENNAGATEAREA 1.066000 ;
    ANTENNADIFFAREA 10.077000 ;
    PORT
      LAYER Metal2 ;
        RECT 37.720 0.000 38.120 0.400 ;
    END
  END Tile_X0Y5_N4END[0]
  PIN Tile_X0Y5_N4END[10]
    DIRECTION INPUT ;
    USE SIGNAL ;
    ANTENNAGATEAREA 1.066000 ;
    ANTENNADIFFAREA 10.077000 ;
    PORT
      LAYER Metal2 ;
        RECT 47.320 0.000 47.720 0.400 ;
    END
  END Tile_X0Y5_N4END[10]
  PIN Tile_X0Y5_N4END[11]
    DIRECTION INPUT ;
    USE SIGNAL ;
    ANTENNAGATEAREA 1.066000 ;
    ANTENNADIFFAREA 10.077000 ;
    PORT
      LAYER Metal2 ;
        RECT 48.280 0.000 48.680 0.400 ;
    END
  END Tile_X0Y5_N4END[11]
  PIN Tile_X0Y5_N4END[12]
    DIRECTION INPUT ;
    USE SIGNAL ;
    ANTENNAGATEAREA 1.066000 ;
    ANTENNADIFFAREA 10.077000 ;
    PORT
      LAYER Metal2 ;
        RECT 49.240 0.000 49.640 0.400 ;
    END
  END Tile_X0Y5_N4END[12]
  PIN Tile_X0Y5_N4END[13]
    DIRECTION INPUT ;
    USE SIGNAL ;
    ANTENNAGATEAREA 1.066000 ;
    ANTENNADIFFAREA 10.077000 ;
    PORT
      LAYER Metal2 ;
        RECT 50.200 0.000 50.600 0.400 ;
    END
  END Tile_X0Y5_N4END[13]
  PIN Tile_X0Y5_N4END[14]
    DIRECTION INPUT ;
    USE SIGNAL ;
    ANTENNAGATEAREA 1.066000 ;
    ANTENNADIFFAREA 10.077000 ;
    PORT
      LAYER Metal2 ;
        RECT 51.160 0.000 51.560 0.400 ;
    END
  END Tile_X0Y5_N4END[14]
  PIN Tile_X0Y5_N4END[15]
    DIRECTION INPUT ;
    USE SIGNAL ;
    ANTENNAGATEAREA 1.066000 ;
    ANTENNADIFFAREA 10.077000 ;
    PORT
      LAYER Metal2 ;
        RECT 52.120 0.000 52.520 0.400 ;
    END
  END Tile_X0Y5_N4END[15]
  PIN Tile_X0Y5_N4END[1]
    DIRECTION INPUT ;
    USE SIGNAL ;
    ANTENNAGATEAREA 1.066000 ;
    ANTENNADIFFAREA 10.077000 ;
    PORT
      LAYER Metal2 ;
        RECT 38.680 0.000 39.080 0.400 ;
    END
  END Tile_X0Y5_N4END[1]
  PIN Tile_X0Y5_N4END[2]
    DIRECTION INPUT ;
    USE SIGNAL ;
    ANTENNAGATEAREA 1.066000 ;
    ANTENNADIFFAREA 10.077000 ;
    PORT
      LAYER Metal2 ;
        RECT 39.640 0.000 40.040 0.400 ;
    END
  END Tile_X0Y5_N4END[2]
  PIN Tile_X0Y5_N4END[3]
    DIRECTION INPUT ;
    USE SIGNAL ;
    ANTENNAGATEAREA 1.066000 ;
    ANTENNADIFFAREA 10.077000 ;
    PORT
      LAYER Metal2 ;
        RECT 40.600 0.000 41.000 0.400 ;
    END
  END Tile_X0Y5_N4END[3]
  PIN Tile_X0Y5_N4END[4]
    DIRECTION INPUT ;
    USE SIGNAL ;
    ANTENNAGATEAREA 1.066000 ;
    ANTENNADIFFAREA 10.077000 ;
    PORT
      LAYER Metal2 ;
        RECT 41.560 0.000 41.960 0.400 ;
    END
  END Tile_X0Y5_N4END[4]
  PIN Tile_X0Y5_N4END[5]
    DIRECTION INPUT ;
    USE SIGNAL ;
    ANTENNAGATEAREA 1.066000 ;
    ANTENNADIFFAREA 10.077000 ;
    PORT
      LAYER Metal2 ;
        RECT 42.520 0.000 42.920 0.400 ;
    END
  END Tile_X0Y5_N4END[5]
  PIN Tile_X0Y5_N4END[6]
    DIRECTION INPUT ;
    USE SIGNAL ;
    ANTENNAGATEAREA 1.066000 ;
    ANTENNADIFFAREA 22.169399 ;
    PORT
      LAYER Metal2 ;
        RECT 43.480 0.000 43.880 0.400 ;
    END
  END Tile_X0Y5_N4END[6]
  PIN Tile_X0Y5_N4END[7]
    DIRECTION INPUT ;
    USE SIGNAL ;
    ANTENNAGATEAREA 1.066000 ;
    ANTENNADIFFAREA 10.077000 ;
    PORT
      LAYER Metal2 ;
        RECT 44.440 0.000 44.840 0.400 ;
    END
  END Tile_X0Y5_N4END[7]
  PIN Tile_X0Y5_N4END[8]
    DIRECTION INPUT ;
    USE SIGNAL ;
    ANTENNAGATEAREA 1.066000 ;
    ANTENNADIFFAREA 10.077000 ;
    PORT
      LAYER Metal2 ;
        RECT 45.400 0.000 45.800 0.400 ;
    END
  END Tile_X0Y5_N4END[8]
  PIN Tile_X0Y5_N4END[9]
    DIRECTION INPUT ;
    USE SIGNAL ;
    ANTENNAGATEAREA 1.066000 ;
    ANTENNADIFFAREA 10.077000 ;
    PORT
      LAYER Metal2 ;
        RECT 46.360 0.000 46.760 0.400 ;
    END
  END Tile_X0Y5_N4END[9]
  PIN Tile_X0Y5_S1BEG[0]
    DIRECTION OUTPUT ;
    USE SIGNAL ;
    ANTENNADIFFAREA 2.724000 ;
    PORT
      LAYER Metal2 ;
        RECT 58.840 0.000 59.240 0.400 ;
    END
  END Tile_X0Y5_S1BEG[0]
  PIN Tile_X0Y5_S1BEG[1]
    DIRECTION OUTPUT ;
    USE SIGNAL ;
    ANTENNADIFFAREA 2.724000 ;
    PORT
      LAYER Metal2 ;
        RECT 59.800 0.000 60.200 0.400 ;
    END
  END Tile_X0Y5_S1BEG[1]
  PIN Tile_X0Y5_S1BEG[2]
    DIRECTION OUTPUT ;
    USE SIGNAL ;
    ANTENNADIFFAREA 2.724000 ;
    PORT
      LAYER Metal2 ;
        RECT 60.760 0.000 61.160 0.400 ;
    END
  END Tile_X0Y5_S1BEG[2]
  PIN Tile_X0Y5_S1BEG[3]
    DIRECTION OUTPUT ;
    USE SIGNAL ;
    ANTENNADIFFAREA 2.724000 ;
    PORT
      LAYER Metal2 ;
        RECT 61.720 0.000 62.120 0.400 ;
    END
  END Tile_X0Y5_S1BEG[3]
  PIN Tile_X0Y5_S2BEG[0]
    DIRECTION OUTPUT ;
    USE SIGNAL ;
    ANTENNADIFFAREA 2.724000 ;
    PORT
      LAYER Metal2 ;
        RECT 66.520 0.000 66.920 0.400 ;
    END
  END Tile_X0Y5_S2BEG[0]
  PIN Tile_X0Y5_S2BEG[1]
    DIRECTION OUTPUT ;
    USE SIGNAL ;
    ANTENNADIFFAREA 2.724000 ;
    PORT
      LAYER Metal2 ;
        RECT 67.480 0.000 67.880 0.400 ;
    END
  END Tile_X0Y5_S2BEG[1]
  PIN Tile_X0Y5_S2BEG[2]
    DIRECTION OUTPUT ;
    USE SIGNAL ;
    ANTENNADIFFAREA 2.724000 ;
    PORT
      LAYER Metal2 ;
        RECT 68.440 0.000 68.840 0.400 ;
    END
  END Tile_X0Y5_S2BEG[2]
  PIN Tile_X0Y5_S2BEG[3]
    DIRECTION OUTPUT ;
    USE SIGNAL ;
    ANTENNADIFFAREA 2.724000 ;
    PORT
      LAYER Metal2 ;
        RECT 69.400 0.000 69.800 0.400 ;
    END
  END Tile_X0Y5_S2BEG[3]
  PIN Tile_X0Y5_S2BEG[4]
    DIRECTION OUTPUT ;
    USE SIGNAL ;
    ANTENNADIFFAREA 2.724000 ;
    PORT
      LAYER Metal2 ;
        RECT 70.360 0.000 70.760 0.400 ;
    END
  END Tile_X0Y5_S2BEG[4]
  PIN Tile_X0Y5_S2BEG[5]
    DIRECTION OUTPUT ;
    USE SIGNAL ;
    ANTENNADIFFAREA 2.724000 ;
    PORT
      LAYER Metal2 ;
        RECT 71.320 0.000 71.720 0.400 ;
    END
  END Tile_X0Y5_S2BEG[5]
  PIN Tile_X0Y5_S2BEG[6]
    DIRECTION OUTPUT ;
    USE SIGNAL ;
    ANTENNADIFFAREA 2.724000 ;
    PORT
      LAYER Metal2 ;
        RECT 72.280 0.000 72.680 0.400 ;
    END
  END Tile_X0Y5_S2BEG[6]
  PIN Tile_X0Y5_S2BEG[7]
    DIRECTION OUTPUT ;
    USE SIGNAL ;
    ANTENNADIFFAREA 2.724000 ;
    PORT
      LAYER Metal2 ;
        RECT 73.240 0.000 73.640 0.400 ;
    END
  END Tile_X0Y5_S2BEG[7]
  PIN Tile_X0Y5_S2BEGb[0]
    DIRECTION OUTPUT ;
    USE SIGNAL ;
    ANTENNADIFFAREA 2.724000 ;
    PORT
      LAYER Metal2 ;
        RECT 79.000 0.000 79.400 0.400 ;
    END
  END Tile_X0Y5_S2BEGb[0]
  PIN Tile_X0Y5_S2BEGb[1]
    DIRECTION OUTPUT ;
    USE SIGNAL ;
    ANTENNADIFFAREA 2.724000 ;
    PORT
      LAYER Metal2 ;
        RECT 79.960 0.000 80.360 0.400 ;
    END
  END Tile_X0Y5_S2BEGb[1]
  PIN Tile_X0Y5_S2BEGb[2]
    DIRECTION OUTPUT ;
    USE SIGNAL ;
    ANTENNADIFFAREA 2.724000 ;
    PORT
      LAYER Metal2 ;
        RECT 80.920 0.000 81.320 0.400 ;
    END
  END Tile_X0Y5_S2BEGb[2]
  PIN Tile_X0Y5_S2BEGb[3]
    DIRECTION OUTPUT ;
    USE SIGNAL ;
    ANTENNADIFFAREA 2.724000 ;
    PORT
      LAYER Metal2 ;
        RECT 81.880 0.000 82.280 0.400 ;
    END
  END Tile_X0Y5_S2BEGb[3]
  PIN Tile_X0Y5_S2BEGb[4]
    DIRECTION OUTPUT ;
    USE SIGNAL ;
    ANTENNADIFFAREA 2.724000 ;
    PORT
      LAYER Metal2 ;
        RECT 82.840 0.000 83.240 0.400 ;
    END
  END Tile_X0Y5_S2BEGb[4]
  PIN Tile_X0Y5_S2BEGb[5]
    DIRECTION OUTPUT ;
    USE SIGNAL ;
    ANTENNADIFFAREA 2.724000 ;
    PORT
      LAYER Metal2 ;
        RECT 83.800 0.000 84.200 0.400 ;
    END
  END Tile_X0Y5_S2BEGb[5]
  PIN Tile_X0Y5_S2BEGb[6]
    DIRECTION OUTPUT ;
    USE SIGNAL ;
    ANTENNADIFFAREA 2.724000 ;
    PORT
      LAYER Metal2 ;
        RECT 84.760 0.000 85.160 0.400 ;
    END
  END Tile_X0Y5_S2BEGb[6]
  PIN Tile_X0Y5_S2BEGb[7]
    DIRECTION OUTPUT ;
    USE SIGNAL ;
    ANTENNADIFFAREA 2.724000 ;
    PORT
      LAYER Metal2 ;
        RECT 85.720 0.000 86.120 0.400 ;
    END
  END Tile_X0Y5_S2BEGb[7]
  PIN Tile_X0Y5_S4BEG[0]
    DIRECTION OUTPUT ;
    USE SIGNAL ;
    ANTENNADIFFAREA 2.724000 ;
    PORT
      LAYER Metal2 ;
        RECT 94.360 0.000 94.760 0.400 ;
    END
  END Tile_X0Y5_S4BEG[0]
  PIN Tile_X0Y5_S4BEG[10]
    DIRECTION OUTPUT ;
    USE SIGNAL ;
    ANTENNADIFFAREA 2.724000 ;
    PORT
      LAYER Metal2 ;
        RECT 103.960 0.000 104.360 0.400 ;
    END
  END Tile_X0Y5_S4BEG[10]
  PIN Tile_X0Y5_S4BEG[11]
    DIRECTION OUTPUT ;
    USE SIGNAL ;
    ANTENNADIFFAREA 2.724000 ;
    PORT
      LAYER Metal2 ;
        RECT 104.920 0.000 105.320 0.400 ;
    END
  END Tile_X0Y5_S4BEG[11]
  PIN Tile_X0Y5_S4BEG[12]
    DIRECTION OUTPUT ;
    USE SIGNAL ;
    ANTENNADIFFAREA 2.724000 ;
    PORT
      LAYER Metal2 ;
        RECT 105.880 0.000 106.280 0.400 ;
    END
  END Tile_X0Y5_S4BEG[12]
  PIN Tile_X0Y5_S4BEG[13]
    DIRECTION OUTPUT ;
    USE SIGNAL ;
    ANTENNADIFFAREA 2.724000 ;
    PORT
      LAYER Metal2 ;
        RECT 106.840 0.000 107.240 0.400 ;
    END
  END Tile_X0Y5_S4BEG[13]
  PIN Tile_X0Y5_S4BEG[14]
    DIRECTION OUTPUT ;
    USE SIGNAL ;
    ANTENNADIFFAREA 2.724000 ;
    PORT
      LAYER Metal2 ;
        RECT 107.800 0.000 108.200 0.400 ;
    END
  END Tile_X0Y5_S4BEG[14]
  PIN Tile_X0Y5_S4BEG[15]
    DIRECTION OUTPUT ;
    USE SIGNAL ;
    ANTENNADIFFAREA 2.724000 ;
    PORT
      LAYER Metal2 ;
        RECT 108.760 0.000 109.160 0.400 ;
    END
  END Tile_X0Y5_S4BEG[15]
  PIN Tile_X0Y5_S4BEG[1]
    DIRECTION OUTPUT ;
    USE SIGNAL ;
    ANTENNADIFFAREA 2.724000 ;
    PORT
      LAYER Metal2 ;
        RECT 95.320 0.000 95.720 0.400 ;
    END
  END Tile_X0Y5_S4BEG[1]
  PIN Tile_X0Y5_S4BEG[2]
    DIRECTION OUTPUT ;
    USE SIGNAL ;
    ANTENNADIFFAREA 2.724000 ;
    PORT
      LAYER Metal2 ;
        RECT 96.280 0.000 96.680 0.400 ;
    END
  END Tile_X0Y5_S4BEG[2]
  PIN Tile_X0Y5_S4BEG[3]
    DIRECTION OUTPUT ;
    USE SIGNAL ;
    ANTENNADIFFAREA 2.724000 ;
    PORT
      LAYER Metal2 ;
        RECT 97.240 0.000 97.640 0.400 ;
    END
  END Tile_X0Y5_S4BEG[3]
  PIN Tile_X0Y5_S4BEG[4]
    DIRECTION OUTPUT ;
    USE SIGNAL ;
    ANTENNADIFFAREA 2.724000 ;
    PORT
      LAYER Metal2 ;
        RECT 98.200 0.000 98.600 0.400 ;
    END
  END Tile_X0Y5_S4BEG[4]
  PIN Tile_X0Y5_S4BEG[5]
    DIRECTION OUTPUT ;
    USE SIGNAL ;
    ANTENNADIFFAREA 2.724000 ;
    PORT
      LAYER Metal2 ;
        RECT 99.160 0.000 99.560 0.400 ;
    END
  END Tile_X0Y5_S4BEG[5]
  PIN Tile_X0Y5_S4BEG[6]
    DIRECTION OUTPUT ;
    USE SIGNAL ;
    ANTENNADIFFAREA 2.724000 ;
    PORT
      LAYER Metal2 ;
        RECT 100.120 0.000 100.520 0.400 ;
    END
  END Tile_X0Y5_S4BEG[6]
  PIN Tile_X0Y5_S4BEG[7]
    DIRECTION OUTPUT ;
    USE SIGNAL ;
    ANTENNADIFFAREA 2.724000 ;
    PORT
      LAYER Metal2 ;
        RECT 101.080 0.000 101.480 0.400 ;
    END
  END Tile_X0Y5_S4BEG[7]
  PIN Tile_X0Y5_S4BEG[8]
    DIRECTION OUTPUT ;
    USE SIGNAL ;
    ANTENNADIFFAREA 2.724000 ;
    PORT
      LAYER Metal2 ;
        RECT 102.040 0.000 102.440 0.400 ;
    END
  END Tile_X0Y5_S4BEG[8]
  PIN Tile_X0Y5_S4BEG[9]
    DIRECTION OUTPUT ;
    USE SIGNAL ;
    ANTENNADIFFAREA 2.724000 ;
    PORT
      LAYER Metal2 ;
        RECT 103.000 0.000 103.400 0.400 ;
    END
  END Tile_X0Y5_S4BEG[9]
  PIN Tile_X0Y5_UserCLK
    DIRECTION INPUT ;
    USE SIGNAL ;
    ANTENNAGATEAREA 0.180700 ;
    ANTENNADIFFAREA 2.015400 ;
    PORT
      LAYER Metal3 ;
        RECT 0.000 1.060 0.400 1.460 ;
    END
  END Tile_X0Y5_UserCLK
  PIN Tile_X0Y5_UserCLKo
    DIRECTION OUTPUT ;
    USE SIGNAL ;
    ANTENNADIFFAREA 2.724000 ;
    PORT
      LAYER Metal3 ;
        RECT 146.960 160.660 147.360 161.060 ;
    END
  END Tile_X0Y5_UserCLKo
  PIN Tile_X0Y5_W1END[0]
    DIRECTION INPUT ;
    USE SIGNAL ;
    ANTENNAGATEAREA 1.305200 ;
    ANTENNADIFFAREA 12.092400 ;
    PORT
      LAYER Metal3 ;
        RECT 146.960 80.020 147.360 80.420 ;
    END
  END Tile_X0Y5_W1END[0]
  PIN Tile_X0Y5_W1END[1]
    DIRECTION INPUT ;
    USE SIGNAL ;
    ANTENNAGATEAREA 1.305200 ;
    ANTENNADIFFAREA 12.092400 ;
    PORT
      LAYER Metal3 ;
        RECT 146.960 81.700 147.360 82.100 ;
    END
  END Tile_X0Y5_W1END[1]
  PIN Tile_X0Y5_W1END[2]
    DIRECTION INPUT ;
    USE SIGNAL ;
    ANTENNAGATEAREA 1.305200 ;
    ANTENNADIFFAREA 12.092400 ;
    PORT
      LAYER Metal3 ;
        RECT 146.960 83.380 147.360 83.780 ;
    END
  END Tile_X0Y5_W1END[2]
  PIN Tile_X0Y5_W1END[3]
    DIRECTION INPUT ;
    USE SIGNAL ;
    ANTENNAGATEAREA 1.305200 ;
    ANTENNADIFFAREA 12.092400 ;
    PORT
      LAYER Metal3 ;
        RECT 146.960 85.060 147.360 85.460 ;
    END
  END Tile_X0Y5_W1END[3]
  PIN Tile_X0Y5_W2END[0]
    DIRECTION INPUT ;
    USE SIGNAL ;
    ANTENNAGATEAREA 0.852800 ;
    ANTENNADIFFAREA 8.061600 ;
    PORT
      LAYER Metal3 ;
        RECT 146.960 100.180 147.360 100.580 ;
    END
  END Tile_X0Y5_W2END[0]
  PIN Tile_X0Y5_W2END[1]
    DIRECTION INPUT ;
    USE SIGNAL ;
    ANTENNAGATEAREA 0.881400 ;
    ANTENNADIFFAREA 8.061600 ;
    PORT
      LAYER Metal3 ;
        RECT 146.960 101.860 147.360 102.260 ;
    END
  END Tile_X0Y5_W2END[1]
  PIN Tile_X0Y5_W2END[2]
    DIRECTION INPUT ;
    USE SIGNAL ;
    ANTENNAGATEAREA 0.852800 ;
    ANTENNADIFFAREA 8.061600 ;
    PORT
      LAYER Metal3 ;
        RECT 146.960 103.540 147.360 103.940 ;
    END
  END Tile_X0Y5_W2END[2]
  PIN Tile_X0Y5_W2END[3]
    DIRECTION INPUT ;
    USE SIGNAL ;
    ANTENNAGATEAREA 0.881400 ;
    ANTENNADIFFAREA 8.061600 ;
    PORT
      LAYER Metal3 ;
        RECT 146.960 105.220 147.360 105.620 ;
    END
  END Tile_X0Y5_W2END[3]
  PIN Tile_X0Y5_W2END[4]
    DIRECTION INPUT ;
    USE SIGNAL ;
    ANTENNAGATEAREA 0.881400 ;
    ANTENNADIFFAREA 8.061600 ;
    PORT
      LAYER Metal3 ;
        RECT 146.960 106.900 147.360 107.300 ;
    END
  END Tile_X0Y5_W2END[4]
  PIN Tile_X0Y5_W2END[5]
    DIRECTION INPUT ;
    USE SIGNAL ;
    ANTENNAGATEAREA 0.881400 ;
    ANTENNADIFFAREA 8.061600 ;
    PORT
      LAYER Metal3 ;
        RECT 146.960 108.580 147.360 108.980 ;
    END
  END Tile_X0Y5_W2END[5]
  PIN Tile_X0Y5_W2END[6]
    DIRECTION INPUT ;
    USE SIGNAL ;
    ANTENNAGATEAREA 0.881400 ;
    ANTENNADIFFAREA 8.061600 ;
    PORT
      LAYER Metal3 ;
        RECT 146.960 110.260 147.360 110.660 ;
    END
  END Tile_X0Y5_W2END[6]
  PIN Tile_X0Y5_W2END[7]
    DIRECTION INPUT ;
    USE SIGNAL ;
    ANTENNAGATEAREA 0.881400 ;
    ANTENNADIFFAREA 8.061600 ;
    PORT
      LAYER Metal3 ;
        RECT 146.960 111.940 147.360 112.340 ;
    END
  END Tile_X0Y5_W2END[7]
  PIN Tile_X0Y5_W2MID[0]
    DIRECTION INPUT ;
    USE SIGNAL ;
    ANTENNAGATEAREA 0.852800 ;
    ANTENNADIFFAREA 8.061600 ;
    PORT
      LAYER Metal3 ;
        RECT 146.960 86.740 147.360 87.140 ;
    END
  END Tile_X0Y5_W2MID[0]
  PIN Tile_X0Y5_W2MID[1]
    DIRECTION INPUT ;
    USE SIGNAL ;
    ANTENNAGATEAREA 0.881400 ;
    ANTENNADIFFAREA 8.061600 ;
    PORT
      LAYER Metal3 ;
        RECT 146.960 88.420 147.360 88.820 ;
    END
  END Tile_X0Y5_W2MID[1]
  PIN Tile_X0Y5_W2MID[2]
    DIRECTION INPUT ;
    USE SIGNAL ;
    ANTENNAGATEAREA 0.852800 ;
    ANTENNADIFFAREA 8.061600 ;
    PORT
      LAYER Metal3 ;
        RECT 146.960 90.100 147.360 90.500 ;
    END
  END Tile_X0Y5_W2MID[2]
  PIN Tile_X0Y5_W2MID[3]
    DIRECTION INPUT ;
    USE SIGNAL ;
    ANTENNAGATEAREA 0.881400 ;
    ANTENNADIFFAREA 8.061600 ;
    PORT
      LAYER Metal3 ;
        RECT 146.960 91.780 147.360 92.180 ;
    END
  END Tile_X0Y5_W2MID[3]
  PIN Tile_X0Y5_W2MID[4]
    DIRECTION INPUT ;
    USE SIGNAL ;
    ANTENNAGATEAREA 0.881400 ;
    ANTENNADIFFAREA 8.061600 ;
    PORT
      LAYER Metal3 ;
        RECT 146.960 93.460 147.360 93.860 ;
    END
  END Tile_X0Y5_W2MID[4]
  PIN Tile_X0Y5_W2MID[5]
    DIRECTION INPUT ;
    USE SIGNAL ;
    ANTENNAGATEAREA 0.881400 ;
    ANTENNADIFFAREA 8.061600 ;
    PORT
      LAYER Metal3 ;
        RECT 146.960 95.140 147.360 95.540 ;
    END
  END Tile_X0Y5_W2MID[5]
  PIN Tile_X0Y5_W2MID[6]
    DIRECTION INPUT ;
    USE SIGNAL ;
    ANTENNAGATEAREA 0.881400 ;
    ANTENNADIFFAREA 8.061600 ;
    PORT
      LAYER Metal3 ;
        RECT 146.960 96.820 147.360 97.220 ;
    END
  END Tile_X0Y5_W2MID[6]
  PIN Tile_X0Y5_W2MID[7]
    DIRECTION INPUT ;
    USE SIGNAL ;
    ANTENNAGATEAREA 0.881400 ;
    ANTENNADIFFAREA 8.061600 ;
    PORT
      LAYER Metal3 ;
        RECT 146.960 98.500 147.360 98.900 ;
    END
  END Tile_X0Y5_W2MID[7]
  PIN Tile_X0Y5_W6END[0]
    DIRECTION INPUT ;
    USE SIGNAL ;
    ANTENNAGATEAREA 0.881400 ;
    ANTENNADIFFAREA 8.061600 ;
    PORT
      LAYER Metal3 ;
        RECT 146.960 140.500 147.360 140.900 ;
    END
  END Tile_X0Y5_W6END[0]
  PIN Tile_X0Y5_W6END[10]
    DIRECTION INPUT ;
    USE SIGNAL ;
    ANTENNAGATEAREA 0.918600 ;
    ANTENNADIFFAREA 8.061600 ;
    PORT
      LAYER Metal3 ;
        RECT 146.960 157.300 147.360 157.700 ;
    END
  END Tile_X0Y5_W6END[10]
  PIN Tile_X0Y5_W6END[11]
    DIRECTION INPUT ;
    USE SIGNAL ;
    ANTENNAGATEAREA 0.918600 ;
    ANTENNADIFFAREA 8.061600 ;
    PORT
      LAYER Metal3 ;
        RECT 146.960 158.980 147.360 159.380 ;
    END
  END Tile_X0Y5_W6END[11]
  PIN Tile_X0Y5_W6END[1]
    DIRECTION INPUT ;
    USE SIGNAL ;
    ANTENNAGATEAREA 0.848900 ;
    ANTENNADIFFAREA 8.061600 ;
    PORT
      LAYER Metal3 ;
        RECT 146.960 142.180 147.360 142.580 ;
    END
  END Tile_X0Y5_W6END[1]
  PIN Tile_X0Y5_W6END[2]
    DIRECTION INPUT ;
    USE SIGNAL ;
    ANTENNAGATEAREA 0.881400 ;
    ANTENNADIFFAREA 8.061600 ;
    PORT
      LAYER Metal3 ;
        RECT 146.960 143.860 147.360 144.260 ;
    END
  END Tile_X0Y5_W6END[2]
  PIN Tile_X0Y5_W6END[3]
    DIRECTION INPUT ;
    USE SIGNAL ;
    ANTENNAGATEAREA 0.848900 ;
    ANTENNADIFFAREA 8.061600 ;
    PORT
      LAYER Metal3 ;
        RECT 146.960 145.540 147.360 145.940 ;
    END
  END Tile_X0Y5_W6END[3]
  PIN Tile_X0Y5_W6END[4]
    DIRECTION INPUT ;
    USE SIGNAL ;
    ANTENNAGATEAREA 1.099300 ;
    ANTENNADIFFAREA 10.077000 ;
    PORT
      LAYER Metal3 ;
        RECT 146.960 147.220 147.360 147.620 ;
    END
  END Tile_X0Y5_W6END[4]
  PIN Tile_X0Y5_W6END[5]
    DIRECTION INPUT ;
    USE SIGNAL ;
    ANTENNAGATEAREA 1.099300 ;
    ANTENNADIFFAREA 10.077000 ;
    PORT
      LAYER Metal3 ;
        RECT 146.960 148.900 147.360 149.300 ;
    END
  END Tile_X0Y5_W6END[5]
  PIN Tile_X0Y5_W6END[6]
    DIRECTION INPUT ;
    USE SIGNAL ;
    ANTENNAGATEAREA 1.099300 ;
    ANTENNADIFFAREA 10.077000 ;
    PORT
      LAYER Metal3 ;
        RECT 146.960 150.580 147.360 150.980 ;
    END
  END Tile_X0Y5_W6END[6]
  PIN Tile_X0Y5_W6END[7]
    DIRECTION INPUT ;
    USE SIGNAL ;
    ANTENNAGATEAREA 1.099300 ;
    ANTENNADIFFAREA 10.077000 ;
    PORT
      LAYER Metal3 ;
        RECT 146.960 152.260 147.360 152.660 ;
    END
  END Tile_X0Y5_W6END[7]
  PIN Tile_X0Y5_W6END[8]
    DIRECTION INPUT ;
    USE SIGNAL ;
    ANTENNAGATEAREA 0.918600 ;
    ANTENNADIFFAREA 8.061600 ;
    PORT
      LAYER Metal3 ;
        RECT 146.960 153.940 147.360 154.340 ;
    END
  END Tile_X0Y5_W6END[8]
  PIN Tile_X0Y5_W6END[9]
    DIRECTION INPUT ;
    USE SIGNAL ;
    ANTENNAGATEAREA 0.865800 ;
    ANTENNADIFFAREA 8.061600 ;
    PORT
      LAYER Metal3 ;
        RECT 146.960 155.620 147.360 156.020 ;
    END
  END Tile_X0Y5_W6END[9]
  PIN Tile_X0Y5_WW4END[0]
    DIRECTION INPUT ;
    USE SIGNAL ;
    ANTENNAGATEAREA 0.865800 ;
    ANTENNADIFFAREA 8.061600 ;
    PORT
      LAYER Metal3 ;
        RECT 146.960 113.620 147.360 114.020 ;
    END
  END Tile_X0Y5_WW4END[0]
  PIN Tile_X0Y5_WW4END[10]
    DIRECTION INPUT ;
    USE SIGNAL ;
    ANTENNAGATEAREA 0.639600 ;
    ANTENNADIFFAREA 6.046200 ;
    PORT
      LAYER Metal3 ;
        RECT 146.960 130.420 147.360 130.820 ;
    END
  END Tile_X0Y5_WW4END[10]
  PIN Tile_X0Y5_WW4END[11]
    DIRECTION INPUT ;
    USE SIGNAL ;
    ANTENNAGATEAREA 0.639600 ;
    ANTENNADIFFAREA 6.046200 ;
    PORT
      LAYER Metal3 ;
        RECT 146.960 132.100 147.360 132.500 ;
    END
  END Tile_X0Y5_WW4END[11]
  PIN Tile_X0Y5_WW4END[12]
    DIRECTION INPUT ;
    USE SIGNAL ;
    ANTENNAGATEAREA 0.865800 ;
    ANTENNADIFFAREA 8.061600 ;
    PORT
      LAYER Metal3 ;
        RECT 146.960 133.780 147.360 134.180 ;
    END
  END Tile_X0Y5_WW4END[12]
  PIN Tile_X0Y5_WW4END[13]
    DIRECTION INPUT ;
    USE SIGNAL ;
    ANTENNAGATEAREA 0.865800 ;
    ANTENNADIFFAREA 8.061600 ;
    PORT
      LAYER Metal3 ;
        RECT 146.960 135.460 147.360 135.860 ;
    END
  END Tile_X0Y5_WW4END[13]
  PIN Tile_X0Y5_WW4END[14]
    DIRECTION INPUT ;
    USE SIGNAL ;
    ANTENNAGATEAREA 0.865800 ;
    ANTENNADIFFAREA 8.061600 ;
    PORT
      LAYER Metal3 ;
        RECT 146.960 137.140 147.360 137.540 ;
    END
  END Tile_X0Y5_WW4END[14]
  PIN Tile_X0Y5_WW4END[15]
    DIRECTION INPUT ;
    USE SIGNAL ;
    ANTENNAGATEAREA 0.865800 ;
    ANTENNADIFFAREA 8.061600 ;
    PORT
      LAYER Metal3 ;
        RECT 146.960 138.820 147.360 139.220 ;
    END
  END Tile_X0Y5_WW4END[15]
  PIN Tile_X0Y5_WW4END[1]
    DIRECTION INPUT ;
    USE SIGNAL ;
    ANTENNAGATEAREA 0.865800 ;
    ANTENNADIFFAREA 8.061600 ;
    PORT
      LAYER Metal3 ;
        RECT 146.960 115.300 147.360 115.700 ;
    END
  END Tile_X0Y5_WW4END[1]
  PIN Tile_X0Y5_WW4END[2]
    DIRECTION INPUT ;
    USE SIGNAL ;
    ANTENNAGATEAREA 0.865800 ;
    ANTENNADIFFAREA 8.061600 ;
    PORT
      LAYER Metal3 ;
        RECT 146.960 116.980 147.360 117.380 ;
    END
  END Tile_X0Y5_WW4END[2]
  PIN Tile_X0Y5_WW4END[3]
    DIRECTION INPUT ;
    USE SIGNAL ;
    ANTENNAGATEAREA 0.865800 ;
    ANTENNADIFFAREA 8.061600 ;
    PORT
      LAYER Metal3 ;
        RECT 146.960 118.660 147.360 119.060 ;
    END
  END Tile_X0Y5_WW4END[3]
  PIN Tile_X0Y5_WW4END[4]
    DIRECTION INPUT ;
    USE SIGNAL ;
    ANTENNAGATEAREA 0.639600 ;
    ANTENNADIFFAREA 6.046200 ;
    PORT
      LAYER Metal3 ;
        RECT 146.960 120.340 147.360 120.740 ;
    END
  END Tile_X0Y5_WW4END[4]
  PIN Tile_X0Y5_WW4END[5]
    DIRECTION INPUT ;
    USE SIGNAL ;
    ANTENNAGATEAREA 0.639600 ;
    ANTENNADIFFAREA 6.046200 ;
    PORT
      LAYER Metal3 ;
        RECT 146.960 122.020 147.360 122.420 ;
    END
  END Tile_X0Y5_WW4END[5]
  PIN Tile_X0Y5_WW4END[6]
    DIRECTION INPUT ;
    USE SIGNAL ;
    ANTENNAGATEAREA 0.639600 ;
    ANTENNADIFFAREA 6.046200 ;
    PORT
      LAYER Metal3 ;
        RECT 146.960 123.700 147.360 124.100 ;
    END
  END Tile_X0Y5_WW4END[6]
  PIN Tile_X0Y5_WW4END[7]
    DIRECTION INPUT ;
    USE SIGNAL ;
    ANTENNAGATEAREA 0.639600 ;
    ANTENNADIFFAREA 6.046200 ;
    PORT
      LAYER Metal3 ;
        RECT 146.960 125.380 147.360 125.780 ;
    END
  END Tile_X0Y5_WW4END[7]
  PIN Tile_X0Y5_WW4END[8]
    DIRECTION INPUT ;
    USE SIGNAL ;
    ANTENNAGATEAREA 0.639600 ;
    ANTENNADIFFAREA 6.046200 ;
    PORT
      LAYER Metal3 ;
        RECT 146.960 127.060 147.360 127.460 ;
    END
  END Tile_X0Y5_WW4END[8]
  PIN Tile_X0Y5_WW4END[9]
    DIRECTION INPUT ;
    USE SIGNAL ;
    ANTENNAGATEAREA 0.639600 ;
    ANTENNADIFFAREA 6.046200 ;
    PORT
      LAYER Metal3 ;
        RECT 146.960 128.740 147.360 129.140 ;
    END
  END Tile_X0Y5_WW4END[9]
  PIN VGND
    DIRECTION INOUT ;
    USE GROUND ;
    PORT
      LAYER Metal4 ;
        RECT 21.580 0.000 23.780 1292.760 ;
    END
    PORT
      LAYER Metal4 ;
        RECT 97.180 0.000 99.380 1292.760 ;
    END
  END VGND
  PIN VPWR
    DIRECTION INOUT ;
    USE POWER ;
    PORT
      LAYER Metal4 ;
        RECT 15.380 0.000 17.580 1292.760 ;
    END
    PORT
      LAYER Metal4 ;
        RECT 90.980 0.000 93.180 1292.760 ;
    END
  END VPWR
  OBS
      LAYER GatPoly ;
        RECT 2.880 3.630 144.480 1289.130 ;
      LAYER Metal1 ;
        RECT 2.880 3.560 144.480 1289.200 ;
      LAYER Metal2 ;
        RECT 0.375 1292.150 1.990 1292.485 ;
        RECT 2.810 1292.150 2.950 1292.485 ;
        RECT 3.770 1292.150 3.910 1292.485 ;
        RECT 4.730 1292.150 4.870 1292.485 ;
        RECT 5.690 1292.150 9.670 1292.485 ;
        RECT 10.490 1292.150 10.630 1292.485 ;
        RECT 11.450 1292.150 11.590 1292.485 ;
        RECT 12.410 1292.150 12.550 1292.485 ;
        RECT 13.370 1292.150 13.510 1292.485 ;
        RECT 14.330 1292.150 14.470 1292.485 ;
        RECT 15.290 1292.150 15.430 1292.485 ;
        RECT 16.250 1292.150 16.390 1292.485 ;
        RECT 17.210 1292.150 22.150 1292.485 ;
        RECT 22.970 1292.150 23.110 1292.485 ;
        RECT 23.930 1292.150 24.070 1292.485 ;
        RECT 24.890 1292.150 25.030 1292.485 ;
        RECT 25.850 1292.150 25.990 1292.485 ;
        RECT 26.810 1292.150 26.950 1292.485 ;
        RECT 27.770 1292.150 27.910 1292.485 ;
        RECT 28.730 1292.150 28.870 1292.485 ;
        RECT 29.690 1292.150 37.510 1292.485 ;
        RECT 38.330 1292.150 38.470 1292.485 ;
        RECT 39.290 1292.150 39.430 1292.485 ;
        RECT 40.250 1292.150 40.390 1292.485 ;
        RECT 41.210 1292.150 41.350 1292.485 ;
        RECT 42.170 1292.150 42.310 1292.485 ;
        RECT 43.130 1292.150 43.270 1292.485 ;
        RECT 44.090 1292.150 44.230 1292.485 ;
        RECT 45.050 1292.150 45.190 1292.485 ;
        RECT 46.010 1292.150 46.150 1292.485 ;
        RECT 46.970 1292.150 47.110 1292.485 ;
        RECT 47.930 1292.150 48.070 1292.485 ;
        RECT 48.890 1292.150 49.030 1292.485 ;
        RECT 49.850 1292.150 49.990 1292.485 ;
        RECT 50.810 1292.150 50.950 1292.485 ;
        RECT 51.770 1292.150 51.910 1292.485 ;
        RECT 52.730 1292.150 58.630 1292.485 ;
        RECT 59.450 1292.150 59.590 1292.485 ;
        RECT 60.410 1292.150 60.550 1292.485 ;
        RECT 61.370 1292.150 61.510 1292.485 ;
        RECT 62.330 1292.150 66.310 1292.485 ;
        RECT 67.130 1292.150 67.270 1292.485 ;
        RECT 68.090 1292.150 68.230 1292.485 ;
        RECT 69.050 1292.150 69.190 1292.485 ;
        RECT 70.010 1292.150 70.150 1292.485 ;
        RECT 70.970 1292.150 71.110 1292.485 ;
        RECT 71.930 1292.150 72.070 1292.485 ;
        RECT 72.890 1292.150 73.030 1292.485 ;
        RECT 73.850 1292.150 78.790 1292.485 ;
        RECT 79.610 1292.150 79.750 1292.485 ;
        RECT 80.570 1292.150 80.710 1292.485 ;
        RECT 81.530 1292.150 81.670 1292.485 ;
        RECT 82.490 1292.150 82.630 1292.485 ;
        RECT 83.450 1292.150 83.590 1292.485 ;
        RECT 84.410 1292.150 84.550 1292.485 ;
        RECT 85.370 1292.150 85.510 1292.485 ;
        RECT 86.330 1292.150 94.150 1292.485 ;
        RECT 94.970 1292.150 95.110 1292.485 ;
        RECT 95.930 1292.150 96.070 1292.485 ;
        RECT 96.890 1292.150 97.030 1292.485 ;
        RECT 97.850 1292.150 97.990 1292.485 ;
        RECT 98.810 1292.150 98.950 1292.485 ;
        RECT 99.770 1292.150 99.910 1292.485 ;
        RECT 100.730 1292.150 100.870 1292.485 ;
        RECT 101.690 1292.150 101.830 1292.485 ;
        RECT 102.650 1292.150 102.790 1292.485 ;
        RECT 103.610 1292.150 103.750 1292.485 ;
        RECT 104.570 1292.150 104.710 1292.485 ;
        RECT 105.530 1292.150 105.670 1292.485 ;
        RECT 106.490 1292.150 106.630 1292.485 ;
        RECT 107.450 1292.150 107.590 1292.485 ;
        RECT 108.410 1292.150 108.550 1292.485 ;
        RECT 109.370 1292.150 121.990 1292.485 ;
        RECT 122.810 1292.150 122.950 1292.485 ;
        RECT 123.770 1292.150 123.910 1292.485 ;
        RECT 124.730 1292.150 124.870 1292.485 ;
        RECT 125.690 1292.150 125.830 1292.485 ;
        RECT 126.650 1292.150 126.790 1292.485 ;
        RECT 127.610 1292.150 127.750 1292.485 ;
        RECT 128.570 1292.150 128.710 1292.485 ;
        RECT 129.530 1292.150 129.670 1292.485 ;
        RECT 130.490 1292.150 130.630 1292.485 ;
        RECT 131.450 1292.150 131.590 1292.485 ;
        RECT 132.410 1292.150 132.550 1292.485 ;
        RECT 133.370 1292.150 133.510 1292.485 ;
        RECT 134.330 1292.150 134.470 1292.485 ;
        RECT 135.290 1292.150 135.430 1292.485 ;
        RECT 136.250 1292.150 136.390 1292.485 ;
        RECT 137.210 1292.150 137.350 1292.485 ;
        RECT 138.170 1292.150 138.310 1292.485 ;
        RECT 139.130 1292.150 139.270 1292.485 ;
        RECT 140.090 1292.150 140.230 1292.485 ;
        RECT 141.050 1292.150 146.985 1292.485 ;
        RECT 0.375 0.610 146.985 1292.150 ;
        RECT 0.375 0.275 1.990 0.610 ;
        RECT 2.810 0.275 2.950 0.610 ;
        RECT 3.770 0.275 3.910 0.610 ;
        RECT 4.730 0.275 4.870 0.610 ;
        RECT 5.690 0.275 9.670 0.610 ;
        RECT 10.490 0.275 10.630 0.610 ;
        RECT 11.450 0.275 11.590 0.610 ;
        RECT 12.410 0.275 12.550 0.610 ;
        RECT 13.370 0.275 13.510 0.610 ;
        RECT 14.330 0.275 14.470 0.610 ;
        RECT 15.290 0.275 15.430 0.610 ;
        RECT 16.250 0.275 16.390 0.610 ;
        RECT 17.210 0.275 22.150 0.610 ;
        RECT 22.970 0.275 23.110 0.610 ;
        RECT 23.930 0.275 24.070 0.610 ;
        RECT 24.890 0.275 25.030 0.610 ;
        RECT 25.850 0.275 25.990 0.610 ;
        RECT 26.810 0.275 26.950 0.610 ;
        RECT 27.770 0.275 27.910 0.610 ;
        RECT 28.730 0.275 28.870 0.610 ;
        RECT 29.690 0.275 37.510 0.610 ;
        RECT 38.330 0.275 38.470 0.610 ;
        RECT 39.290 0.275 39.430 0.610 ;
        RECT 40.250 0.275 40.390 0.610 ;
        RECT 41.210 0.275 41.350 0.610 ;
        RECT 42.170 0.275 42.310 0.610 ;
        RECT 43.130 0.275 43.270 0.610 ;
        RECT 44.090 0.275 44.230 0.610 ;
        RECT 45.050 0.275 45.190 0.610 ;
        RECT 46.010 0.275 46.150 0.610 ;
        RECT 46.970 0.275 47.110 0.610 ;
        RECT 47.930 0.275 48.070 0.610 ;
        RECT 48.890 0.275 49.030 0.610 ;
        RECT 49.850 0.275 49.990 0.610 ;
        RECT 50.810 0.275 50.950 0.610 ;
        RECT 51.770 0.275 51.910 0.610 ;
        RECT 52.730 0.275 58.630 0.610 ;
        RECT 59.450 0.275 59.590 0.610 ;
        RECT 60.410 0.275 60.550 0.610 ;
        RECT 61.370 0.275 61.510 0.610 ;
        RECT 62.330 0.275 66.310 0.610 ;
        RECT 67.130 0.275 67.270 0.610 ;
        RECT 68.090 0.275 68.230 0.610 ;
        RECT 69.050 0.275 69.190 0.610 ;
        RECT 70.010 0.275 70.150 0.610 ;
        RECT 70.970 0.275 71.110 0.610 ;
        RECT 71.930 0.275 72.070 0.610 ;
        RECT 72.890 0.275 73.030 0.610 ;
        RECT 73.850 0.275 78.790 0.610 ;
        RECT 79.610 0.275 79.750 0.610 ;
        RECT 80.570 0.275 80.710 0.610 ;
        RECT 81.530 0.275 81.670 0.610 ;
        RECT 82.490 0.275 82.630 0.610 ;
        RECT 83.450 0.275 83.590 0.610 ;
        RECT 84.410 0.275 84.550 0.610 ;
        RECT 85.370 0.275 85.510 0.610 ;
        RECT 86.330 0.275 94.150 0.610 ;
        RECT 94.970 0.275 95.110 0.610 ;
        RECT 95.930 0.275 96.070 0.610 ;
        RECT 96.890 0.275 97.030 0.610 ;
        RECT 97.850 0.275 97.990 0.610 ;
        RECT 98.810 0.275 98.950 0.610 ;
        RECT 99.770 0.275 99.910 0.610 ;
        RECT 100.730 0.275 100.870 0.610 ;
        RECT 101.690 0.275 101.830 0.610 ;
        RECT 102.650 0.275 102.790 0.610 ;
        RECT 103.610 0.275 103.750 0.610 ;
        RECT 104.570 0.275 104.710 0.610 ;
        RECT 105.530 0.275 105.670 0.610 ;
        RECT 106.490 0.275 106.630 0.610 ;
        RECT 107.450 0.275 107.590 0.610 ;
        RECT 108.410 0.275 108.550 0.610 ;
        RECT 109.370 0.275 121.990 0.610 ;
        RECT 122.810 0.275 122.950 0.610 ;
        RECT 123.770 0.275 123.910 0.610 ;
        RECT 124.730 0.275 124.870 0.610 ;
        RECT 125.690 0.275 125.830 0.610 ;
        RECT 126.650 0.275 126.790 0.610 ;
        RECT 127.610 0.275 127.750 0.610 ;
        RECT 128.570 0.275 128.710 0.610 ;
        RECT 129.530 0.275 129.670 0.610 ;
        RECT 130.490 0.275 130.630 0.610 ;
        RECT 131.450 0.275 131.590 0.610 ;
        RECT 132.410 0.275 132.550 0.610 ;
        RECT 133.370 0.275 133.510 0.610 ;
        RECT 134.330 0.275 134.470 0.610 ;
        RECT 135.290 0.275 135.430 0.610 ;
        RECT 136.250 0.275 136.390 0.610 ;
        RECT 137.210 0.275 137.350 0.610 ;
        RECT 138.170 0.275 138.310 0.610 ;
        RECT 139.130 0.275 139.270 0.610 ;
        RECT 140.090 0.275 140.230 0.610 ;
        RECT 141.050 0.275 146.985 0.610 ;
      LAYER Metal3 ;
        RECT 0.335 1292.330 147.025 1292.445 ;
        RECT 0.335 1291.510 146.750 1292.330 ;
        RECT 0.335 1290.650 147.025 1291.510 ;
        RECT 0.335 1289.830 146.750 1290.650 ;
        RECT 0.335 1288.970 147.025 1289.830 ;
        RECT 0.335 1288.150 146.750 1288.970 ;
        RECT 0.335 1287.290 147.025 1288.150 ;
        RECT 0.335 1286.470 146.750 1287.290 ;
        RECT 0.335 1285.610 147.025 1286.470 ;
        RECT 0.335 1284.790 146.750 1285.610 ;
        RECT 0.335 1283.930 147.025 1284.790 ;
        RECT 0.335 1283.110 146.750 1283.930 ;
        RECT 0.335 1282.250 147.025 1283.110 ;
        RECT 0.335 1281.430 146.750 1282.250 ;
        RECT 0.335 1280.570 147.025 1281.430 ;
        RECT 0.610 1279.750 146.750 1280.570 ;
        RECT 0.335 1278.890 147.025 1279.750 ;
        RECT 0.335 1278.070 146.750 1278.890 ;
        RECT 0.335 1277.210 147.025 1278.070 ;
        RECT 0.335 1276.390 146.750 1277.210 ;
        RECT 0.335 1275.530 147.025 1276.390 ;
        RECT 0.335 1274.710 146.750 1275.530 ;
        RECT 0.335 1274.690 147.025 1274.710 ;
        RECT 0.610 1273.870 147.025 1274.690 ;
        RECT 0.335 1273.850 147.025 1273.870 ;
        RECT 0.335 1273.030 146.750 1273.850 ;
        RECT 0.335 1272.170 147.025 1273.030 ;
        RECT 0.335 1271.350 146.750 1272.170 ;
        RECT 0.335 1270.490 147.025 1271.350 ;
        RECT 0.335 1269.670 146.750 1270.490 ;
        RECT 0.335 1268.810 147.025 1269.670 ;
        RECT 0.610 1267.990 146.750 1268.810 ;
        RECT 0.335 1267.130 147.025 1267.990 ;
        RECT 0.335 1266.310 146.750 1267.130 ;
        RECT 0.335 1265.450 147.025 1266.310 ;
        RECT 0.335 1264.630 146.750 1265.450 ;
        RECT 0.335 1263.770 147.025 1264.630 ;
        RECT 0.335 1262.950 146.750 1263.770 ;
        RECT 0.335 1262.930 147.025 1262.950 ;
        RECT 0.610 1262.110 147.025 1262.930 ;
        RECT 0.335 1262.090 147.025 1262.110 ;
        RECT 0.335 1261.270 146.750 1262.090 ;
        RECT 0.335 1260.410 147.025 1261.270 ;
        RECT 0.335 1259.590 146.750 1260.410 ;
        RECT 0.335 1258.730 147.025 1259.590 ;
        RECT 0.335 1257.910 146.750 1258.730 ;
        RECT 0.335 1257.050 147.025 1257.910 ;
        RECT 0.610 1256.230 146.750 1257.050 ;
        RECT 0.335 1255.370 147.025 1256.230 ;
        RECT 0.335 1254.550 146.750 1255.370 ;
        RECT 0.335 1253.690 147.025 1254.550 ;
        RECT 0.335 1252.870 146.750 1253.690 ;
        RECT 0.335 1252.010 147.025 1252.870 ;
        RECT 0.335 1251.190 146.750 1252.010 ;
        RECT 0.335 1251.170 147.025 1251.190 ;
        RECT 0.610 1250.350 147.025 1251.170 ;
        RECT 0.335 1250.330 147.025 1250.350 ;
        RECT 0.335 1249.510 146.750 1250.330 ;
        RECT 0.335 1248.650 147.025 1249.510 ;
        RECT 0.335 1247.830 146.750 1248.650 ;
        RECT 0.335 1246.970 147.025 1247.830 ;
        RECT 0.335 1246.150 146.750 1246.970 ;
        RECT 0.335 1245.290 147.025 1246.150 ;
        RECT 0.610 1244.470 146.750 1245.290 ;
        RECT 0.335 1243.610 147.025 1244.470 ;
        RECT 0.335 1242.790 146.750 1243.610 ;
        RECT 0.335 1241.930 147.025 1242.790 ;
        RECT 0.335 1241.110 146.750 1241.930 ;
        RECT 0.335 1240.250 147.025 1241.110 ;
        RECT 0.335 1239.430 146.750 1240.250 ;
        RECT 0.335 1239.410 147.025 1239.430 ;
        RECT 0.610 1238.590 147.025 1239.410 ;
        RECT 0.335 1238.570 147.025 1238.590 ;
        RECT 0.335 1237.750 146.750 1238.570 ;
        RECT 0.335 1236.890 147.025 1237.750 ;
        RECT 0.335 1236.070 146.750 1236.890 ;
        RECT 0.335 1235.210 147.025 1236.070 ;
        RECT 0.335 1234.390 146.750 1235.210 ;
        RECT 0.335 1233.530 147.025 1234.390 ;
        RECT 0.610 1232.710 146.750 1233.530 ;
        RECT 0.335 1231.850 147.025 1232.710 ;
        RECT 0.335 1231.030 146.750 1231.850 ;
        RECT 0.335 1230.170 147.025 1231.030 ;
        RECT 0.335 1229.350 146.750 1230.170 ;
        RECT 0.335 1228.490 147.025 1229.350 ;
        RECT 0.335 1227.670 146.750 1228.490 ;
        RECT 0.335 1227.650 147.025 1227.670 ;
        RECT 0.610 1226.830 147.025 1227.650 ;
        RECT 0.335 1226.810 147.025 1226.830 ;
        RECT 0.335 1225.990 146.750 1226.810 ;
        RECT 0.335 1225.130 147.025 1225.990 ;
        RECT 0.335 1224.310 146.750 1225.130 ;
        RECT 0.335 1223.450 147.025 1224.310 ;
        RECT 0.335 1222.630 146.750 1223.450 ;
        RECT 0.335 1221.770 147.025 1222.630 ;
        RECT 0.610 1220.950 146.750 1221.770 ;
        RECT 0.335 1220.090 147.025 1220.950 ;
        RECT 0.335 1219.270 146.750 1220.090 ;
        RECT 0.335 1218.410 147.025 1219.270 ;
        RECT 0.335 1217.590 146.750 1218.410 ;
        RECT 0.335 1216.730 147.025 1217.590 ;
        RECT 0.335 1215.910 146.750 1216.730 ;
        RECT 0.335 1215.890 147.025 1215.910 ;
        RECT 0.610 1215.070 147.025 1215.890 ;
        RECT 0.335 1215.050 147.025 1215.070 ;
        RECT 0.335 1214.230 146.750 1215.050 ;
        RECT 0.335 1213.370 147.025 1214.230 ;
        RECT 0.335 1212.550 146.750 1213.370 ;
        RECT 0.335 1211.690 147.025 1212.550 ;
        RECT 0.335 1210.870 146.750 1211.690 ;
        RECT 0.335 1210.010 147.025 1210.870 ;
        RECT 0.610 1209.190 146.750 1210.010 ;
        RECT 0.335 1208.330 147.025 1209.190 ;
        RECT 0.335 1207.510 146.750 1208.330 ;
        RECT 0.335 1206.650 147.025 1207.510 ;
        RECT 0.335 1205.830 146.750 1206.650 ;
        RECT 0.335 1204.970 147.025 1205.830 ;
        RECT 0.335 1204.150 146.750 1204.970 ;
        RECT 0.335 1204.130 147.025 1204.150 ;
        RECT 0.610 1203.310 147.025 1204.130 ;
        RECT 0.335 1203.290 147.025 1203.310 ;
        RECT 0.335 1202.470 146.750 1203.290 ;
        RECT 0.335 1201.610 147.025 1202.470 ;
        RECT 0.335 1200.790 146.750 1201.610 ;
        RECT 0.335 1199.930 147.025 1200.790 ;
        RECT 0.335 1199.110 146.750 1199.930 ;
        RECT 0.335 1198.250 147.025 1199.110 ;
        RECT 0.610 1197.430 146.750 1198.250 ;
        RECT 0.335 1196.570 147.025 1197.430 ;
        RECT 0.335 1195.750 146.750 1196.570 ;
        RECT 0.335 1194.890 147.025 1195.750 ;
        RECT 0.335 1194.070 146.750 1194.890 ;
        RECT 0.335 1193.210 147.025 1194.070 ;
        RECT 0.335 1192.390 146.750 1193.210 ;
        RECT 0.335 1192.370 147.025 1192.390 ;
        RECT 0.610 1191.550 147.025 1192.370 ;
        RECT 0.335 1191.530 147.025 1191.550 ;
        RECT 0.335 1190.710 146.750 1191.530 ;
        RECT 0.335 1189.850 147.025 1190.710 ;
        RECT 0.335 1189.030 146.750 1189.850 ;
        RECT 0.335 1188.170 147.025 1189.030 ;
        RECT 0.335 1187.350 146.750 1188.170 ;
        RECT 0.335 1186.490 147.025 1187.350 ;
        RECT 0.610 1185.670 146.750 1186.490 ;
        RECT 0.335 1184.810 147.025 1185.670 ;
        RECT 0.335 1183.990 146.750 1184.810 ;
        RECT 0.335 1183.130 147.025 1183.990 ;
        RECT 0.335 1182.310 146.750 1183.130 ;
        RECT 0.335 1181.450 147.025 1182.310 ;
        RECT 0.335 1180.630 146.750 1181.450 ;
        RECT 0.335 1180.610 147.025 1180.630 ;
        RECT 0.610 1179.790 147.025 1180.610 ;
        RECT 0.335 1179.770 147.025 1179.790 ;
        RECT 0.335 1178.950 146.750 1179.770 ;
        RECT 0.335 1178.090 147.025 1178.950 ;
        RECT 0.335 1177.270 146.750 1178.090 ;
        RECT 0.335 1176.410 147.025 1177.270 ;
        RECT 0.335 1175.590 146.750 1176.410 ;
        RECT 0.335 1174.730 147.025 1175.590 ;
        RECT 0.610 1173.910 146.750 1174.730 ;
        RECT 0.335 1173.050 147.025 1173.910 ;
        RECT 0.335 1172.230 146.750 1173.050 ;
        RECT 0.335 1171.370 147.025 1172.230 ;
        RECT 0.335 1170.550 146.750 1171.370 ;
        RECT 0.335 1169.690 147.025 1170.550 ;
        RECT 0.335 1168.870 146.750 1169.690 ;
        RECT 0.335 1168.850 147.025 1168.870 ;
        RECT 0.610 1168.030 147.025 1168.850 ;
        RECT 0.335 1168.010 147.025 1168.030 ;
        RECT 0.335 1167.190 146.750 1168.010 ;
        RECT 0.335 1166.330 147.025 1167.190 ;
        RECT 0.335 1165.510 146.750 1166.330 ;
        RECT 0.335 1164.650 147.025 1165.510 ;
        RECT 0.335 1163.830 146.750 1164.650 ;
        RECT 0.335 1162.970 147.025 1163.830 ;
        RECT 0.610 1162.150 146.750 1162.970 ;
        RECT 0.335 1161.290 147.025 1162.150 ;
        RECT 0.335 1160.470 146.750 1161.290 ;
        RECT 0.335 1159.610 147.025 1160.470 ;
        RECT 0.335 1158.790 146.750 1159.610 ;
        RECT 0.335 1157.930 147.025 1158.790 ;
        RECT 0.335 1157.110 146.750 1157.930 ;
        RECT 0.335 1157.090 147.025 1157.110 ;
        RECT 0.610 1156.270 147.025 1157.090 ;
        RECT 0.335 1156.250 147.025 1156.270 ;
        RECT 0.335 1155.430 146.750 1156.250 ;
        RECT 0.335 1154.570 147.025 1155.430 ;
        RECT 0.335 1153.750 146.750 1154.570 ;
        RECT 0.335 1152.890 147.025 1153.750 ;
        RECT 0.335 1152.070 146.750 1152.890 ;
        RECT 0.335 1151.210 147.025 1152.070 ;
        RECT 0.610 1150.390 146.750 1151.210 ;
        RECT 0.335 1149.530 147.025 1150.390 ;
        RECT 0.335 1148.710 146.750 1149.530 ;
        RECT 0.335 1147.850 147.025 1148.710 ;
        RECT 0.335 1147.030 146.750 1147.850 ;
        RECT 0.335 1146.170 147.025 1147.030 ;
        RECT 0.335 1145.350 146.750 1146.170 ;
        RECT 0.335 1145.330 147.025 1145.350 ;
        RECT 0.610 1144.510 147.025 1145.330 ;
        RECT 0.335 1144.490 147.025 1144.510 ;
        RECT 0.335 1143.670 146.750 1144.490 ;
        RECT 0.335 1142.810 147.025 1143.670 ;
        RECT 0.335 1141.990 146.750 1142.810 ;
        RECT 0.335 1141.130 147.025 1141.990 ;
        RECT 0.335 1140.310 146.750 1141.130 ;
        RECT 0.335 1139.450 147.025 1140.310 ;
        RECT 0.610 1138.630 146.750 1139.450 ;
        RECT 0.335 1137.770 147.025 1138.630 ;
        RECT 0.335 1136.950 146.750 1137.770 ;
        RECT 0.335 1133.570 147.025 1136.950 ;
        RECT 0.610 1132.750 147.025 1133.570 ;
        RECT 0.335 1130.210 147.025 1132.750 ;
        RECT 0.335 1129.390 146.750 1130.210 ;
        RECT 0.335 1129.370 147.025 1129.390 ;
        RECT 0.335 1128.550 146.750 1129.370 ;
        RECT 0.335 1128.530 147.025 1128.550 ;
        RECT 0.335 1127.710 146.750 1128.530 ;
        RECT 0.335 1127.690 147.025 1127.710 ;
        RECT 0.610 1126.870 146.750 1127.690 ;
        RECT 0.335 1126.850 147.025 1126.870 ;
        RECT 0.335 1126.030 146.750 1126.850 ;
        RECT 0.335 1126.010 147.025 1126.030 ;
        RECT 0.335 1125.190 146.750 1126.010 ;
        RECT 0.335 1125.170 147.025 1125.190 ;
        RECT 0.335 1124.350 146.750 1125.170 ;
        RECT 0.335 1124.330 147.025 1124.350 ;
        RECT 0.335 1123.510 146.750 1124.330 ;
        RECT 0.335 1123.490 147.025 1123.510 ;
        RECT 0.335 1122.670 146.750 1123.490 ;
        RECT 0.335 1122.650 147.025 1122.670 ;
        RECT 0.335 1121.830 146.750 1122.650 ;
        RECT 0.335 1121.810 147.025 1121.830 ;
        RECT 0.610 1120.990 146.750 1121.810 ;
        RECT 0.335 1120.970 147.025 1120.990 ;
        RECT 0.335 1120.150 146.750 1120.970 ;
        RECT 0.335 1120.130 147.025 1120.150 ;
        RECT 0.335 1119.310 146.750 1120.130 ;
        RECT 0.335 1119.290 147.025 1119.310 ;
        RECT 0.335 1118.470 146.750 1119.290 ;
        RECT 0.335 1118.450 147.025 1118.470 ;
        RECT 0.335 1117.630 146.750 1118.450 ;
        RECT 0.335 1117.610 147.025 1117.630 ;
        RECT 0.335 1116.790 146.750 1117.610 ;
        RECT 0.335 1115.930 147.025 1116.790 ;
        RECT 0.610 1115.110 147.025 1115.930 ;
        RECT 0.335 1110.050 147.025 1115.110 ;
        RECT 0.610 1109.230 146.750 1110.050 ;
        RECT 0.335 1108.370 147.025 1109.230 ;
        RECT 0.335 1107.550 146.750 1108.370 ;
        RECT 0.335 1106.690 147.025 1107.550 ;
        RECT 0.335 1105.870 146.750 1106.690 ;
        RECT 0.335 1105.010 147.025 1105.870 ;
        RECT 0.335 1104.190 146.750 1105.010 ;
        RECT 0.335 1104.170 147.025 1104.190 ;
        RECT 0.610 1103.350 147.025 1104.170 ;
        RECT 0.335 1103.330 147.025 1103.350 ;
        RECT 0.335 1102.510 146.750 1103.330 ;
        RECT 0.335 1101.650 147.025 1102.510 ;
        RECT 0.335 1100.830 146.750 1101.650 ;
        RECT 0.335 1099.970 147.025 1100.830 ;
        RECT 0.335 1099.150 146.750 1099.970 ;
        RECT 0.335 1098.290 147.025 1099.150 ;
        RECT 0.610 1097.470 146.750 1098.290 ;
        RECT 0.335 1094.090 147.025 1097.470 ;
        RECT 0.335 1093.270 146.750 1094.090 ;
        RECT 0.335 1093.250 147.025 1093.270 ;
        RECT 0.335 1092.430 146.750 1093.250 ;
        RECT 0.335 1092.410 147.025 1092.430 ;
        RECT 0.335 1091.590 146.750 1092.410 ;
        RECT 0.335 1091.570 147.025 1091.590 ;
        RECT 0.335 1090.750 146.750 1091.570 ;
        RECT 0.335 1090.730 147.025 1090.750 ;
        RECT 0.335 1089.910 146.750 1090.730 ;
        RECT 0.335 1089.890 147.025 1089.910 ;
        RECT 0.335 1089.070 146.750 1089.890 ;
        RECT 0.335 1089.050 147.025 1089.070 ;
        RECT 0.335 1088.230 146.750 1089.050 ;
        RECT 0.335 1088.210 147.025 1088.230 ;
        RECT 0.335 1087.390 146.750 1088.210 ;
        RECT 0.335 1084.010 147.025 1087.390 ;
        RECT 0.335 1083.190 146.750 1084.010 ;
        RECT 0.335 1082.330 147.025 1083.190 ;
        RECT 0.335 1081.510 146.750 1082.330 ;
        RECT 0.335 1081.490 147.025 1081.510 ;
        RECT 0.610 1080.670 147.025 1081.490 ;
        RECT 0.335 1080.650 147.025 1080.670 ;
        RECT 0.335 1079.830 146.750 1080.650 ;
        RECT 0.335 1078.970 147.025 1079.830 ;
        RECT 0.335 1078.150 146.750 1078.970 ;
        RECT 0.335 1076.870 147.025 1078.150 ;
        RECT 0.335 1076.050 146.750 1076.870 ;
        RECT 0.335 1075.190 147.025 1076.050 ;
        RECT 0.335 1074.370 146.750 1075.190 ;
        RECT 0.335 1073.510 147.025 1074.370 ;
        RECT 0.335 1072.690 146.750 1073.510 ;
        RECT 0.335 1071.830 147.025 1072.690 ;
        RECT 0.335 1071.010 146.750 1071.830 ;
        RECT 0.335 1070.150 147.025 1071.010 ;
        RECT 0.335 1069.330 146.750 1070.150 ;
        RECT 0.335 1068.470 147.025 1069.330 ;
        RECT 0.335 1067.650 146.750 1068.470 ;
        RECT 0.335 1066.790 147.025 1067.650 ;
        RECT 0.335 1065.970 146.750 1066.790 ;
        RECT 0.335 1065.110 147.025 1065.970 ;
        RECT 0.610 1064.290 146.750 1065.110 ;
        RECT 0.335 1063.430 147.025 1064.290 ;
        RECT 0.335 1062.610 146.750 1063.430 ;
        RECT 0.335 1061.750 147.025 1062.610 ;
        RECT 0.335 1060.930 146.750 1061.750 ;
        RECT 0.335 1060.070 147.025 1060.930 ;
        RECT 0.335 1059.250 146.750 1060.070 ;
        RECT 0.335 1059.230 147.025 1059.250 ;
        RECT 0.610 1058.410 147.025 1059.230 ;
        RECT 0.335 1058.390 147.025 1058.410 ;
        RECT 0.335 1057.570 146.750 1058.390 ;
        RECT 0.335 1056.710 147.025 1057.570 ;
        RECT 0.335 1055.890 146.750 1056.710 ;
        RECT 0.335 1055.030 147.025 1055.890 ;
        RECT 0.335 1054.210 146.750 1055.030 ;
        RECT 0.335 1053.350 147.025 1054.210 ;
        RECT 0.610 1052.530 146.750 1053.350 ;
        RECT 0.335 1051.670 147.025 1052.530 ;
        RECT 0.335 1050.850 146.750 1051.670 ;
        RECT 0.335 1049.990 147.025 1050.850 ;
        RECT 0.335 1049.170 146.750 1049.990 ;
        RECT 0.335 1048.310 147.025 1049.170 ;
        RECT 0.335 1047.490 146.750 1048.310 ;
        RECT 0.335 1047.470 147.025 1047.490 ;
        RECT 0.610 1046.650 147.025 1047.470 ;
        RECT 0.335 1046.630 147.025 1046.650 ;
        RECT 0.335 1045.810 146.750 1046.630 ;
        RECT 0.335 1044.950 147.025 1045.810 ;
        RECT 0.335 1044.130 146.750 1044.950 ;
        RECT 0.335 1043.270 147.025 1044.130 ;
        RECT 0.335 1042.450 146.750 1043.270 ;
        RECT 0.335 1041.590 147.025 1042.450 ;
        RECT 0.610 1040.770 146.750 1041.590 ;
        RECT 0.335 1039.910 147.025 1040.770 ;
        RECT 0.335 1039.090 146.750 1039.910 ;
        RECT 0.335 1038.230 147.025 1039.090 ;
        RECT 0.335 1037.410 146.750 1038.230 ;
        RECT 0.335 1036.550 147.025 1037.410 ;
        RECT 0.335 1035.730 146.750 1036.550 ;
        RECT 0.335 1035.710 147.025 1035.730 ;
        RECT 0.610 1034.890 147.025 1035.710 ;
        RECT 0.335 1034.870 147.025 1034.890 ;
        RECT 0.335 1034.050 146.750 1034.870 ;
        RECT 0.335 1033.190 147.025 1034.050 ;
        RECT 0.335 1032.370 146.750 1033.190 ;
        RECT 0.335 1031.510 147.025 1032.370 ;
        RECT 0.335 1030.690 146.750 1031.510 ;
        RECT 0.335 1029.830 147.025 1030.690 ;
        RECT 0.610 1029.010 146.750 1029.830 ;
        RECT 0.335 1028.150 147.025 1029.010 ;
        RECT 0.335 1027.330 146.750 1028.150 ;
        RECT 0.335 1026.470 147.025 1027.330 ;
        RECT 0.335 1025.650 146.750 1026.470 ;
        RECT 0.335 1024.790 147.025 1025.650 ;
        RECT 0.335 1023.970 146.750 1024.790 ;
        RECT 0.335 1023.950 147.025 1023.970 ;
        RECT 0.610 1023.130 147.025 1023.950 ;
        RECT 0.335 1023.110 147.025 1023.130 ;
        RECT 0.335 1022.290 146.750 1023.110 ;
        RECT 0.335 1021.430 147.025 1022.290 ;
        RECT 0.335 1020.610 146.750 1021.430 ;
        RECT 0.335 1019.750 147.025 1020.610 ;
        RECT 0.335 1018.930 146.750 1019.750 ;
        RECT 0.335 1018.070 147.025 1018.930 ;
        RECT 0.610 1017.250 146.750 1018.070 ;
        RECT 0.335 1016.390 147.025 1017.250 ;
        RECT 0.335 1015.570 146.750 1016.390 ;
        RECT 0.335 1014.710 147.025 1015.570 ;
        RECT 0.335 1013.890 146.750 1014.710 ;
        RECT 0.335 1013.030 147.025 1013.890 ;
        RECT 0.335 1012.210 146.750 1013.030 ;
        RECT 0.335 1012.190 147.025 1012.210 ;
        RECT 0.610 1011.370 147.025 1012.190 ;
        RECT 0.335 1011.350 147.025 1011.370 ;
        RECT 0.335 1010.530 146.750 1011.350 ;
        RECT 0.335 1009.670 147.025 1010.530 ;
        RECT 0.335 1008.850 146.750 1009.670 ;
        RECT 0.335 1007.990 147.025 1008.850 ;
        RECT 0.335 1007.170 146.750 1007.990 ;
        RECT 0.335 1006.310 147.025 1007.170 ;
        RECT 0.610 1005.490 146.750 1006.310 ;
        RECT 0.335 1004.630 147.025 1005.490 ;
        RECT 0.335 1003.810 146.750 1004.630 ;
        RECT 0.335 1002.950 147.025 1003.810 ;
        RECT 0.335 1002.130 146.750 1002.950 ;
        RECT 0.335 1001.270 147.025 1002.130 ;
        RECT 0.335 1000.450 146.750 1001.270 ;
        RECT 0.335 1000.430 147.025 1000.450 ;
        RECT 0.610 999.610 147.025 1000.430 ;
        RECT 0.335 999.590 147.025 999.610 ;
        RECT 0.335 998.770 146.750 999.590 ;
        RECT 0.335 997.910 147.025 998.770 ;
        RECT 0.335 997.090 146.750 997.910 ;
        RECT 0.335 996.230 147.025 997.090 ;
        RECT 0.335 995.410 146.750 996.230 ;
        RECT 0.335 994.550 147.025 995.410 ;
        RECT 0.610 993.730 146.750 994.550 ;
        RECT 0.335 992.870 147.025 993.730 ;
        RECT 0.335 992.050 146.750 992.870 ;
        RECT 0.335 991.190 147.025 992.050 ;
        RECT 0.335 990.370 146.750 991.190 ;
        RECT 0.335 989.510 147.025 990.370 ;
        RECT 0.335 988.690 146.750 989.510 ;
        RECT 0.335 988.670 147.025 988.690 ;
        RECT 0.610 987.850 147.025 988.670 ;
        RECT 0.335 987.830 147.025 987.850 ;
        RECT 0.335 987.010 146.750 987.830 ;
        RECT 0.335 986.150 147.025 987.010 ;
        RECT 0.335 985.330 146.750 986.150 ;
        RECT 0.335 984.470 147.025 985.330 ;
        RECT 0.335 983.650 146.750 984.470 ;
        RECT 0.335 982.790 147.025 983.650 ;
        RECT 0.610 981.970 146.750 982.790 ;
        RECT 0.335 981.110 147.025 981.970 ;
        RECT 0.335 980.290 146.750 981.110 ;
        RECT 0.335 979.430 147.025 980.290 ;
        RECT 0.335 978.610 146.750 979.430 ;
        RECT 0.335 977.750 147.025 978.610 ;
        RECT 0.335 976.930 146.750 977.750 ;
        RECT 0.335 976.910 147.025 976.930 ;
        RECT 0.610 976.090 147.025 976.910 ;
        RECT 0.335 976.070 147.025 976.090 ;
        RECT 0.335 975.250 146.750 976.070 ;
        RECT 0.335 974.390 147.025 975.250 ;
        RECT 0.335 973.570 146.750 974.390 ;
        RECT 0.335 972.710 147.025 973.570 ;
        RECT 0.335 971.890 146.750 972.710 ;
        RECT 0.335 971.030 147.025 971.890 ;
        RECT 0.610 970.210 146.750 971.030 ;
        RECT 0.335 969.350 147.025 970.210 ;
        RECT 0.335 968.530 146.750 969.350 ;
        RECT 0.335 967.670 147.025 968.530 ;
        RECT 0.335 966.850 146.750 967.670 ;
        RECT 0.335 965.990 147.025 966.850 ;
        RECT 0.335 965.170 146.750 965.990 ;
        RECT 0.335 965.150 147.025 965.170 ;
        RECT 0.610 964.330 147.025 965.150 ;
        RECT 0.335 964.310 147.025 964.330 ;
        RECT 0.335 963.490 146.750 964.310 ;
        RECT 0.335 962.630 147.025 963.490 ;
        RECT 0.335 961.810 146.750 962.630 ;
        RECT 0.335 960.950 147.025 961.810 ;
        RECT 0.335 960.130 146.750 960.950 ;
        RECT 0.335 959.270 147.025 960.130 ;
        RECT 0.610 958.450 146.750 959.270 ;
        RECT 0.335 957.590 147.025 958.450 ;
        RECT 0.335 956.770 146.750 957.590 ;
        RECT 0.335 955.910 147.025 956.770 ;
        RECT 0.335 955.090 146.750 955.910 ;
        RECT 0.335 954.230 147.025 955.090 ;
        RECT 0.335 953.410 146.750 954.230 ;
        RECT 0.335 953.390 147.025 953.410 ;
        RECT 0.610 952.570 147.025 953.390 ;
        RECT 0.335 952.550 147.025 952.570 ;
        RECT 0.335 951.730 146.750 952.550 ;
        RECT 0.335 950.870 147.025 951.730 ;
        RECT 0.335 950.050 146.750 950.870 ;
        RECT 0.335 949.190 147.025 950.050 ;
        RECT 0.335 948.370 146.750 949.190 ;
        RECT 0.335 947.510 147.025 948.370 ;
        RECT 0.610 946.690 146.750 947.510 ;
        RECT 0.335 945.830 147.025 946.690 ;
        RECT 0.335 945.010 146.750 945.830 ;
        RECT 0.335 944.150 147.025 945.010 ;
        RECT 0.335 943.330 146.750 944.150 ;
        RECT 0.335 942.470 147.025 943.330 ;
        RECT 0.335 941.650 146.750 942.470 ;
        RECT 0.335 941.630 147.025 941.650 ;
        RECT 0.610 940.810 147.025 941.630 ;
        RECT 0.335 940.790 147.025 940.810 ;
        RECT 0.335 939.970 146.750 940.790 ;
        RECT 0.335 939.110 147.025 939.970 ;
        RECT 0.335 938.290 146.750 939.110 ;
        RECT 0.335 937.430 147.025 938.290 ;
        RECT 0.335 936.610 146.750 937.430 ;
        RECT 0.335 935.750 147.025 936.610 ;
        RECT 0.610 934.930 146.750 935.750 ;
        RECT 0.335 934.070 147.025 934.930 ;
        RECT 0.335 933.250 146.750 934.070 ;
        RECT 0.335 932.390 147.025 933.250 ;
        RECT 0.335 931.570 146.750 932.390 ;
        RECT 0.335 930.710 147.025 931.570 ;
        RECT 0.335 929.890 146.750 930.710 ;
        RECT 0.335 929.870 147.025 929.890 ;
        RECT 0.610 929.050 147.025 929.870 ;
        RECT 0.335 929.030 147.025 929.050 ;
        RECT 0.335 928.210 146.750 929.030 ;
        RECT 0.335 927.350 147.025 928.210 ;
        RECT 0.335 926.530 146.750 927.350 ;
        RECT 0.335 925.670 147.025 926.530 ;
        RECT 0.335 924.850 146.750 925.670 ;
        RECT 0.335 923.990 147.025 924.850 ;
        RECT 0.610 923.170 146.750 923.990 ;
        RECT 0.335 922.310 147.025 923.170 ;
        RECT 0.335 921.490 146.750 922.310 ;
        RECT 0.335 918.110 147.025 921.490 ;
        RECT 0.610 917.290 147.025 918.110 ;
        RECT 0.335 914.750 147.025 917.290 ;
        RECT 0.335 913.930 146.750 914.750 ;
        RECT 0.335 913.910 147.025 913.930 ;
        RECT 0.335 913.090 146.750 913.910 ;
        RECT 0.335 913.070 147.025 913.090 ;
        RECT 0.335 912.250 146.750 913.070 ;
        RECT 0.335 912.230 147.025 912.250 ;
        RECT 0.610 911.410 146.750 912.230 ;
        RECT 0.335 911.390 147.025 911.410 ;
        RECT 0.335 910.570 146.750 911.390 ;
        RECT 0.335 910.550 147.025 910.570 ;
        RECT 0.335 909.730 146.750 910.550 ;
        RECT 0.335 909.710 147.025 909.730 ;
        RECT 0.335 908.890 146.750 909.710 ;
        RECT 0.335 908.870 147.025 908.890 ;
        RECT 0.335 908.050 146.750 908.870 ;
        RECT 0.335 908.030 147.025 908.050 ;
        RECT 0.335 907.210 146.750 908.030 ;
        RECT 0.335 907.190 147.025 907.210 ;
        RECT 0.335 906.370 146.750 907.190 ;
        RECT 0.335 906.350 147.025 906.370 ;
        RECT 0.610 905.530 146.750 906.350 ;
        RECT 0.335 905.510 147.025 905.530 ;
        RECT 0.335 904.690 146.750 905.510 ;
        RECT 0.335 904.670 147.025 904.690 ;
        RECT 0.335 903.850 146.750 904.670 ;
        RECT 0.335 903.830 147.025 903.850 ;
        RECT 0.335 903.010 146.750 903.830 ;
        RECT 0.335 902.990 147.025 903.010 ;
        RECT 0.335 902.170 146.750 902.990 ;
        RECT 0.335 902.150 147.025 902.170 ;
        RECT 0.335 901.330 146.750 902.150 ;
        RECT 0.335 900.470 147.025 901.330 ;
        RECT 0.610 899.650 147.025 900.470 ;
        RECT 0.335 894.590 147.025 899.650 ;
        RECT 0.610 893.770 146.750 894.590 ;
        RECT 0.335 892.910 147.025 893.770 ;
        RECT 0.335 892.090 146.750 892.910 ;
        RECT 0.335 891.230 147.025 892.090 ;
        RECT 0.335 890.410 146.750 891.230 ;
        RECT 0.335 889.550 147.025 890.410 ;
        RECT 0.335 888.730 146.750 889.550 ;
        RECT 0.335 888.710 147.025 888.730 ;
        RECT 0.610 887.890 147.025 888.710 ;
        RECT 0.335 887.870 147.025 887.890 ;
        RECT 0.335 887.050 146.750 887.870 ;
        RECT 0.335 886.190 147.025 887.050 ;
        RECT 0.335 885.370 146.750 886.190 ;
        RECT 0.335 884.510 147.025 885.370 ;
        RECT 0.335 883.690 146.750 884.510 ;
        RECT 0.335 882.830 147.025 883.690 ;
        RECT 0.610 882.010 146.750 882.830 ;
        RECT 0.335 878.630 147.025 882.010 ;
        RECT 0.335 877.810 146.750 878.630 ;
        RECT 0.335 877.790 147.025 877.810 ;
        RECT 0.335 876.970 146.750 877.790 ;
        RECT 0.335 876.950 147.025 876.970 ;
        RECT 0.335 876.130 146.750 876.950 ;
        RECT 0.335 876.110 147.025 876.130 ;
        RECT 0.335 875.290 146.750 876.110 ;
        RECT 0.335 875.270 147.025 875.290 ;
        RECT 0.335 874.450 146.750 875.270 ;
        RECT 0.335 874.430 147.025 874.450 ;
        RECT 0.335 873.610 146.750 874.430 ;
        RECT 0.335 873.590 147.025 873.610 ;
        RECT 0.335 872.770 146.750 873.590 ;
        RECT 0.335 872.750 147.025 872.770 ;
        RECT 0.335 871.930 146.750 872.750 ;
        RECT 0.335 868.550 147.025 871.930 ;
        RECT 0.335 867.730 146.750 868.550 ;
        RECT 0.335 866.870 147.025 867.730 ;
        RECT 0.335 866.050 146.750 866.870 ;
        RECT 0.335 866.030 147.025 866.050 ;
        RECT 0.610 865.210 147.025 866.030 ;
        RECT 0.335 865.190 147.025 865.210 ;
        RECT 0.335 864.370 146.750 865.190 ;
        RECT 0.335 863.510 147.025 864.370 ;
        RECT 0.335 862.690 146.750 863.510 ;
        RECT 0.335 861.410 147.025 862.690 ;
        RECT 0.335 860.590 146.750 861.410 ;
        RECT 0.335 859.730 147.025 860.590 ;
        RECT 0.335 858.910 146.750 859.730 ;
        RECT 0.335 858.050 147.025 858.910 ;
        RECT 0.335 857.230 146.750 858.050 ;
        RECT 0.335 856.370 147.025 857.230 ;
        RECT 0.335 855.550 146.750 856.370 ;
        RECT 0.335 854.690 147.025 855.550 ;
        RECT 0.335 853.870 146.750 854.690 ;
        RECT 0.335 853.010 147.025 853.870 ;
        RECT 0.335 852.190 146.750 853.010 ;
        RECT 0.335 851.330 147.025 852.190 ;
        RECT 0.335 850.510 146.750 851.330 ;
        RECT 0.335 849.650 147.025 850.510 ;
        RECT 0.610 848.830 146.750 849.650 ;
        RECT 0.335 847.970 147.025 848.830 ;
        RECT 0.335 847.150 146.750 847.970 ;
        RECT 0.335 846.290 147.025 847.150 ;
        RECT 0.335 845.470 146.750 846.290 ;
        RECT 0.335 844.610 147.025 845.470 ;
        RECT 0.335 843.790 146.750 844.610 ;
        RECT 0.335 843.770 147.025 843.790 ;
        RECT 0.610 842.950 147.025 843.770 ;
        RECT 0.335 842.930 147.025 842.950 ;
        RECT 0.335 842.110 146.750 842.930 ;
        RECT 0.335 841.250 147.025 842.110 ;
        RECT 0.335 840.430 146.750 841.250 ;
        RECT 0.335 839.570 147.025 840.430 ;
        RECT 0.335 838.750 146.750 839.570 ;
        RECT 0.335 837.890 147.025 838.750 ;
        RECT 0.610 837.070 146.750 837.890 ;
        RECT 0.335 836.210 147.025 837.070 ;
        RECT 0.335 835.390 146.750 836.210 ;
        RECT 0.335 834.530 147.025 835.390 ;
        RECT 0.335 833.710 146.750 834.530 ;
        RECT 0.335 832.850 147.025 833.710 ;
        RECT 0.335 832.030 146.750 832.850 ;
        RECT 0.335 832.010 147.025 832.030 ;
        RECT 0.610 831.190 147.025 832.010 ;
        RECT 0.335 831.170 147.025 831.190 ;
        RECT 0.335 830.350 146.750 831.170 ;
        RECT 0.335 829.490 147.025 830.350 ;
        RECT 0.335 828.670 146.750 829.490 ;
        RECT 0.335 827.810 147.025 828.670 ;
        RECT 0.335 826.990 146.750 827.810 ;
        RECT 0.335 826.130 147.025 826.990 ;
        RECT 0.610 825.310 146.750 826.130 ;
        RECT 0.335 824.450 147.025 825.310 ;
        RECT 0.335 823.630 146.750 824.450 ;
        RECT 0.335 822.770 147.025 823.630 ;
        RECT 0.335 821.950 146.750 822.770 ;
        RECT 0.335 821.090 147.025 821.950 ;
        RECT 0.335 820.270 146.750 821.090 ;
        RECT 0.335 820.250 147.025 820.270 ;
        RECT 0.610 819.430 147.025 820.250 ;
        RECT 0.335 819.410 147.025 819.430 ;
        RECT 0.335 818.590 146.750 819.410 ;
        RECT 0.335 817.730 147.025 818.590 ;
        RECT 0.335 816.910 146.750 817.730 ;
        RECT 0.335 816.050 147.025 816.910 ;
        RECT 0.335 815.230 146.750 816.050 ;
        RECT 0.335 814.370 147.025 815.230 ;
        RECT 0.610 813.550 146.750 814.370 ;
        RECT 0.335 812.690 147.025 813.550 ;
        RECT 0.335 811.870 146.750 812.690 ;
        RECT 0.335 811.010 147.025 811.870 ;
        RECT 0.335 810.190 146.750 811.010 ;
        RECT 0.335 809.330 147.025 810.190 ;
        RECT 0.335 808.510 146.750 809.330 ;
        RECT 0.335 808.490 147.025 808.510 ;
        RECT 0.610 807.670 147.025 808.490 ;
        RECT 0.335 807.650 147.025 807.670 ;
        RECT 0.335 806.830 146.750 807.650 ;
        RECT 0.335 805.970 147.025 806.830 ;
        RECT 0.335 805.150 146.750 805.970 ;
        RECT 0.335 804.290 147.025 805.150 ;
        RECT 0.335 803.470 146.750 804.290 ;
        RECT 0.335 802.610 147.025 803.470 ;
        RECT 0.610 801.790 146.750 802.610 ;
        RECT 0.335 800.930 147.025 801.790 ;
        RECT 0.335 800.110 146.750 800.930 ;
        RECT 0.335 799.250 147.025 800.110 ;
        RECT 0.335 798.430 146.750 799.250 ;
        RECT 0.335 797.570 147.025 798.430 ;
        RECT 0.335 796.750 146.750 797.570 ;
        RECT 0.335 796.730 147.025 796.750 ;
        RECT 0.610 795.910 147.025 796.730 ;
        RECT 0.335 795.890 147.025 795.910 ;
        RECT 0.335 795.070 146.750 795.890 ;
        RECT 0.335 794.210 147.025 795.070 ;
        RECT 0.335 793.390 146.750 794.210 ;
        RECT 0.335 792.530 147.025 793.390 ;
        RECT 0.335 791.710 146.750 792.530 ;
        RECT 0.335 790.850 147.025 791.710 ;
        RECT 0.610 790.030 146.750 790.850 ;
        RECT 0.335 789.170 147.025 790.030 ;
        RECT 0.335 788.350 146.750 789.170 ;
        RECT 0.335 787.490 147.025 788.350 ;
        RECT 0.335 786.670 146.750 787.490 ;
        RECT 0.335 785.810 147.025 786.670 ;
        RECT 0.335 784.990 146.750 785.810 ;
        RECT 0.335 784.970 147.025 784.990 ;
        RECT 0.610 784.150 147.025 784.970 ;
        RECT 0.335 784.130 147.025 784.150 ;
        RECT 0.335 783.310 146.750 784.130 ;
        RECT 0.335 782.450 147.025 783.310 ;
        RECT 0.335 781.630 146.750 782.450 ;
        RECT 0.335 780.770 147.025 781.630 ;
        RECT 0.335 779.950 146.750 780.770 ;
        RECT 0.335 779.090 147.025 779.950 ;
        RECT 0.610 778.270 146.750 779.090 ;
        RECT 0.335 777.410 147.025 778.270 ;
        RECT 0.335 776.590 146.750 777.410 ;
        RECT 0.335 775.730 147.025 776.590 ;
        RECT 0.335 774.910 146.750 775.730 ;
        RECT 0.335 774.050 147.025 774.910 ;
        RECT 0.335 773.230 146.750 774.050 ;
        RECT 0.335 773.210 147.025 773.230 ;
        RECT 0.610 772.390 147.025 773.210 ;
        RECT 0.335 772.370 147.025 772.390 ;
        RECT 0.335 771.550 146.750 772.370 ;
        RECT 0.335 770.690 147.025 771.550 ;
        RECT 0.335 769.870 146.750 770.690 ;
        RECT 0.335 769.010 147.025 769.870 ;
        RECT 0.335 768.190 146.750 769.010 ;
        RECT 0.335 767.330 147.025 768.190 ;
        RECT 0.610 766.510 146.750 767.330 ;
        RECT 0.335 765.650 147.025 766.510 ;
        RECT 0.335 764.830 146.750 765.650 ;
        RECT 0.335 763.970 147.025 764.830 ;
        RECT 0.335 763.150 146.750 763.970 ;
        RECT 0.335 762.290 147.025 763.150 ;
        RECT 0.335 761.470 146.750 762.290 ;
        RECT 0.335 761.450 147.025 761.470 ;
        RECT 0.610 760.630 147.025 761.450 ;
        RECT 0.335 760.610 147.025 760.630 ;
        RECT 0.335 759.790 146.750 760.610 ;
        RECT 0.335 758.930 147.025 759.790 ;
        RECT 0.335 758.110 146.750 758.930 ;
        RECT 0.335 757.250 147.025 758.110 ;
        RECT 0.335 756.430 146.750 757.250 ;
        RECT 0.335 755.570 147.025 756.430 ;
        RECT 0.610 754.750 146.750 755.570 ;
        RECT 0.335 753.890 147.025 754.750 ;
        RECT 0.335 753.070 146.750 753.890 ;
        RECT 0.335 752.210 147.025 753.070 ;
        RECT 0.335 751.390 146.750 752.210 ;
        RECT 0.335 750.530 147.025 751.390 ;
        RECT 0.335 749.710 146.750 750.530 ;
        RECT 0.335 749.690 147.025 749.710 ;
        RECT 0.610 748.870 147.025 749.690 ;
        RECT 0.335 748.850 147.025 748.870 ;
        RECT 0.335 748.030 146.750 748.850 ;
        RECT 0.335 747.170 147.025 748.030 ;
        RECT 0.335 746.350 146.750 747.170 ;
        RECT 0.335 745.490 147.025 746.350 ;
        RECT 0.335 744.670 146.750 745.490 ;
        RECT 0.335 743.810 147.025 744.670 ;
        RECT 0.610 742.990 146.750 743.810 ;
        RECT 0.335 742.130 147.025 742.990 ;
        RECT 0.335 741.310 146.750 742.130 ;
        RECT 0.335 740.450 147.025 741.310 ;
        RECT 0.335 739.630 146.750 740.450 ;
        RECT 0.335 738.770 147.025 739.630 ;
        RECT 0.335 737.950 146.750 738.770 ;
        RECT 0.335 737.930 147.025 737.950 ;
        RECT 0.610 737.110 147.025 737.930 ;
        RECT 0.335 737.090 147.025 737.110 ;
        RECT 0.335 736.270 146.750 737.090 ;
        RECT 0.335 735.410 147.025 736.270 ;
        RECT 0.335 734.590 146.750 735.410 ;
        RECT 0.335 733.730 147.025 734.590 ;
        RECT 0.335 732.910 146.750 733.730 ;
        RECT 0.335 732.050 147.025 732.910 ;
        RECT 0.610 731.230 146.750 732.050 ;
        RECT 0.335 730.370 147.025 731.230 ;
        RECT 0.335 729.550 146.750 730.370 ;
        RECT 0.335 728.690 147.025 729.550 ;
        RECT 0.335 727.870 146.750 728.690 ;
        RECT 0.335 727.010 147.025 727.870 ;
        RECT 0.335 726.190 146.750 727.010 ;
        RECT 0.335 726.170 147.025 726.190 ;
        RECT 0.610 725.350 147.025 726.170 ;
        RECT 0.335 725.330 147.025 725.350 ;
        RECT 0.335 724.510 146.750 725.330 ;
        RECT 0.335 723.650 147.025 724.510 ;
        RECT 0.335 722.830 146.750 723.650 ;
        RECT 0.335 721.970 147.025 722.830 ;
        RECT 0.335 721.150 146.750 721.970 ;
        RECT 0.335 720.290 147.025 721.150 ;
        RECT 0.610 719.470 146.750 720.290 ;
        RECT 0.335 718.610 147.025 719.470 ;
        RECT 0.335 717.790 146.750 718.610 ;
        RECT 0.335 716.930 147.025 717.790 ;
        RECT 0.335 716.110 146.750 716.930 ;
        RECT 0.335 715.250 147.025 716.110 ;
        RECT 0.335 714.430 146.750 715.250 ;
        RECT 0.335 714.410 147.025 714.430 ;
        RECT 0.610 713.590 147.025 714.410 ;
        RECT 0.335 713.570 147.025 713.590 ;
        RECT 0.335 712.750 146.750 713.570 ;
        RECT 0.335 711.890 147.025 712.750 ;
        RECT 0.335 711.070 146.750 711.890 ;
        RECT 0.335 710.210 147.025 711.070 ;
        RECT 0.335 709.390 146.750 710.210 ;
        RECT 0.335 708.530 147.025 709.390 ;
        RECT 0.610 707.710 146.750 708.530 ;
        RECT 0.335 706.850 147.025 707.710 ;
        RECT 0.335 706.030 146.750 706.850 ;
        RECT 0.335 702.650 147.025 706.030 ;
        RECT 0.610 701.830 147.025 702.650 ;
        RECT 0.335 699.290 147.025 701.830 ;
        RECT 0.335 698.470 146.750 699.290 ;
        RECT 0.335 698.450 147.025 698.470 ;
        RECT 0.335 697.630 146.750 698.450 ;
        RECT 0.335 697.610 147.025 697.630 ;
        RECT 0.335 696.790 146.750 697.610 ;
        RECT 0.335 696.770 147.025 696.790 ;
        RECT 0.610 695.950 146.750 696.770 ;
        RECT 0.335 695.930 147.025 695.950 ;
        RECT 0.335 695.110 146.750 695.930 ;
        RECT 0.335 695.090 147.025 695.110 ;
        RECT 0.335 694.270 146.750 695.090 ;
        RECT 0.335 694.250 147.025 694.270 ;
        RECT 0.335 693.430 146.750 694.250 ;
        RECT 0.335 693.410 147.025 693.430 ;
        RECT 0.335 692.590 146.750 693.410 ;
        RECT 0.335 692.570 147.025 692.590 ;
        RECT 0.335 691.750 146.750 692.570 ;
        RECT 0.335 691.730 147.025 691.750 ;
        RECT 0.335 690.910 146.750 691.730 ;
        RECT 0.335 690.890 147.025 690.910 ;
        RECT 0.610 690.070 146.750 690.890 ;
        RECT 0.335 690.050 147.025 690.070 ;
        RECT 0.335 689.230 146.750 690.050 ;
        RECT 0.335 689.210 147.025 689.230 ;
        RECT 0.335 688.390 146.750 689.210 ;
        RECT 0.335 688.370 147.025 688.390 ;
        RECT 0.335 687.550 146.750 688.370 ;
        RECT 0.335 687.530 147.025 687.550 ;
        RECT 0.335 686.710 146.750 687.530 ;
        RECT 0.335 686.690 147.025 686.710 ;
        RECT 0.335 685.870 146.750 686.690 ;
        RECT 0.335 685.010 147.025 685.870 ;
        RECT 0.610 684.190 147.025 685.010 ;
        RECT 0.335 679.130 147.025 684.190 ;
        RECT 0.610 678.310 146.750 679.130 ;
        RECT 0.335 677.450 147.025 678.310 ;
        RECT 0.335 676.630 146.750 677.450 ;
        RECT 0.335 675.770 147.025 676.630 ;
        RECT 0.335 674.950 146.750 675.770 ;
        RECT 0.335 674.090 147.025 674.950 ;
        RECT 0.335 673.270 146.750 674.090 ;
        RECT 0.335 673.250 147.025 673.270 ;
        RECT 0.610 672.430 147.025 673.250 ;
        RECT 0.335 672.410 147.025 672.430 ;
        RECT 0.335 671.590 146.750 672.410 ;
        RECT 0.335 670.730 147.025 671.590 ;
        RECT 0.335 669.910 146.750 670.730 ;
        RECT 0.335 669.050 147.025 669.910 ;
        RECT 0.335 668.230 146.750 669.050 ;
        RECT 0.335 667.370 147.025 668.230 ;
        RECT 0.610 666.550 146.750 667.370 ;
        RECT 0.335 663.170 147.025 666.550 ;
        RECT 0.335 662.350 146.750 663.170 ;
        RECT 0.335 662.330 147.025 662.350 ;
        RECT 0.335 661.510 146.750 662.330 ;
        RECT 0.335 661.490 147.025 661.510 ;
        RECT 0.335 660.670 146.750 661.490 ;
        RECT 0.335 660.650 147.025 660.670 ;
        RECT 0.335 659.830 146.750 660.650 ;
        RECT 0.335 659.810 147.025 659.830 ;
        RECT 0.335 658.990 146.750 659.810 ;
        RECT 0.335 658.970 147.025 658.990 ;
        RECT 0.335 658.150 146.750 658.970 ;
        RECT 0.335 658.130 147.025 658.150 ;
        RECT 0.335 657.310 146.750 658.130 ;
        RECT 0.335 657.290 147.025 657.310 ;
        RECT 0.335 656.470 146.750 657.290 ;
        RECT 0.335 653.090 147.025 656.470 ;
        RECT 0.335 652.270 146.750 653.090 ;
        RECT 0.335 651.410 147.025 652.270 ;
        RECT 0.335 650.590 146.750 651.410 ;
        RECT 0.335 650.570 147.025 650.590 ;
        RECT 0.610 649.750 147.025 650.570 ;
        RECT 0.335 649.730 147.025 649.750 ;
        RECT 0.335 648.910 146.750 649.730 ;
        RECT 0.335 648.050 147.025 648.910 ;
        RECT 0.335 647.230 146.750 648.050 ;
        RECT 0.335 645.950 147.025 647.230 ;
        RECT 0.335 645.130 146.750 645.950 ;
        RECT 0.335 644.270 147.025 645.130 ;
        RECT 0.335 643.450 146.750 644.270 ;
        RECT 0.335 642.590 147.025 643.450 ;
        RECT 0.335 641.770 146.750 642.590 ;
        RECT 0.335 640.910 147.025 641.770 ;
        RECT 0.335 640.090 146.750 640.910 ;
        RECT 0.335 639.230 147.025 640.090 ;
        RECT 0.335 638.410 146.750 639.230 ;
        RECT 0.335 637.550 147.025 638.410 ;
        RECT 0.335 636.730 146.750 637.550 ;
        RECT 0.335 635.870 147.025 636.730 ;
        RECT 0.335 635.050 146.750 635.870 ;
        RECT 0.335 634.190 147.025 635.050 ;
        RECT 0.610 633.370 146.750 634.190 ;
        RECT 0.335 632.510 147.025 633.370 ;
        RECT 0.335 631.690 146.750 632.510 ;
        RECT 0.335 630.830 147.025 631.690 ;
        RECT 0.335 630.010 146.750 630.830 ;
        RECT 0.335 629.150 147.025 630.010 ;
        RECT 0.335 628.330 146.750 629.150 ;
        RECT 0.335 628.310 147.025 628.330 ;
        RECT 0.610 627.490 147.025 628.310 ;
        RECT 0.335 627.470 147.025 627.490 ;
        RECT 0.335 626.650 146.750 627.470 ;
        RECT 0.335 625.790 147.025 626.650 ;
        RECT 0.335 624.970 146.750 625.790 ;
        RECT 0.335 624.110 147.025 624.970 ;
        RECT 0.335 623.290 146.750 624.110 ;
        RECT 0.335 622.430 147.025 623.290 ;
        RECT 0.610 621.610 146.750 622.430 ;
        RECT 0.335 620.750 147.025 621.610 ;
        RECT 0.335 619.930 146.750 620.750 ;
        RECT 0.335 619.070 147.025 619.930 ;
        RECT 0.335 618.250 146.750 619.070 ;
        RECT 0.335 617.390 147.025 618.250 ;
        RECT 0.335 616.570 146.750 617.390 ;
        RECT 0.335 616.550 147.025 616.570 ;
        RECT 0.610 615.730 147.025 616.550 ;
        RECT 0.335 615.710 147.025 615.730 ;
        RECT 0.335 614.890 146.750 615.710 ;
        RECT 0.335 614.030 147.025 614.890 ;
        RECT 0.335 613.210 146.750 614.030 ;
        RECT 0.335 612.350 147.025 613.210 ;
        RECT 0.335 611.530 146.750 612.350 ;
        RECT 0.335 610.670 147.025 611.530 ;
        RECT 0.610 609.850 146.750 610.670 ;
        RECT 0.335 608.990 147.025 609.850 ;
        RECT 0.335 608.170 146.750 608.990 ;
        RECT 0.335 607.310 147.025 608.170 ;
        RECT 0.335 606.490 146.750 607.310 ;
        RECT 0.335 605.630 147.025 606.490 ;
        RECT 0.335 604.810 146.750 605.630 ;
        RECT 0.335 604.790 147.025 604.810 ;
        RECT 0.610 603.970 147.025 604.790 ;
        RECT 0.335 603.950 147.025 603.970 ;
        RECT 0.335 603.130 146.750 603.950 ;
        RECT 0.335 602.270 147.025 603.130 ;
        RECT 0.335 601.450 146.750 602.270 ;
        RECT 0.335 600.590 147.025 601.450 ;
        RECT 0.335 599.770 146.750 600.590 ;
        RECT 0.335 598.910 147.025 599.770 ;
        RECT 0.610 598.090 146.750 598.910 ;
        RECT 0.335 597.230 147.025 598.090 ;
        RECT 0.335 596.410 146.750 597.230 ;
        RECT 0.335 595.550 147.025 596.410 ;
        RECT 0.335 594.730 146.750 595.550 ;
        RECT 0.335 593.870 147.025 594.730 ;
        RECT 0.335 593.050 146.750 593.870 ;
        RECT 0.335 593.030 147.025 593.050 ;
        RECT 0.610 592.210 147.025 593.030 ;
        RECT 0.335 592.190 147.025 592.210 ;
        RECT 0.335 591.370 146.750 592.190 ;
        RECT 0.335 590.510 147.025 591.370 ;
        RECT 0.335 589.690 146.750 590.510 ;
        RECT 0.335 588.830 147.025 589.690 ;
        RECT 0.335 588.010 146.750 588.830 ;
        RECT 0.335 587.150 147.025 588.010 ;
        RECT 0.610 586.330 146.750 587.150 ;
        RECT 0.335 585.470 147.025 586.330 ;
        RECT 0.335 584.650 146.750 585.470 ;
        RECT 0.335 583.790 147.025 584.650 ;
        RECT 0.335 582.970 146.750 583.790 ;
        RECT 0.335 582.110 147.025 582.970 ;
        RECT 0.335 581.290 146.750 582.110 ;
        RECT 0.335 581.270 147.025 581.290 ;
        RECT 0.610 580.450 147.025 581.270 ;
        RECT 0.335 580.430 147.025 580.450 ;
        RECT 0.335 579.610 146.750 580.430 ;
        RECT 0.335 578.750 147.025 579.610 ;
        RECT 0.335 577.930 146.750 578.750 ;
        RECT 0.335 577.070 147.025 577.930 ;
        RECT 0.335 576.250 146.750 577.070 ;
        RECT 0.335 575.390 147.025 576.250 ;
        RECT 0.610 574.570 146.750 575.390 ;
        RECT 0.335 573.710 147.025 574.570 ;
        RECT 0.335 572.890 146.750 573.710 ;
        RECT 0.335 572.030 147.025 572.890 ;
        RECT 0.335 571.210 146.750 572.030 ;
        RECT 0.335 570.350 147.025 571.210 ;
        RECT 0.335 569.530 146.750 570.350 ;
        RECT 0.335 569.510 147.025 569.530 ;
        RECT 0.610 568.690 147.025 569.510 ;
        RECT 0.335 568.670 147.025 568.690 ;
        RECT 0.335 567.850 146.750 568.670 ;
        RECT 0.335 566.990 147.025 567.850 ;
        RECT 0.335 566.170 146.750 566.990 ;
        RECT 0.335 565.310 147.025 566.170 ;
        RECT 0.335 564.490 146.750 565.310 ;
        RECT 0.335 563.630 147.025 564.490 ;
        RECT 0.610 562.810 146.750 563.630 ;
        RECT 0.335 561.950 147.025 562.810 ;
        RECT 0.335 561.130 146.750 561.950 ;
        RECT 0.335 560.270 147.025 561.130 ;
        RECT 0.335 559.450 146.750 560.270 ;
        RECT 0.335 558.590 147.025 559.450 ;
        RECT 0.335 557.770 146.750 558.590 ;
        RECT 0.335 557.750 147.025 557.770 ;
        RECT 0.610 556.930 147.025 557.750 ;
        RECT 0.335 556.910 147.025 556.930 ;
        RECT 0.335 556.090 146.750 556.910 ;
        RECT 0.335 555.230 147.025 556.090 ;
        RECT 0.335 554.410 146.750 555.230 ;
        RECT 0.335 553.550 147.025 554.410 ;
        RECT 0.335 552.730 146.750 553.550 ;
        RECT 0.335 551.870 147.025 552.730 ;
        RECT 0.610 551.050 146.750 551.870 ;
        RECT 0.335 550.190 147.025 551.050 ;
        RECT 0.335 549.370 146.750 550.190 ;
        RECT 0.335 548.510 147.025 549.370 ;
        RECT 0.335 547.690 146.750 548.510 ;
        RECT 0.335 546.830 147.025 547.690 ;
        RECT 0.335 546.010 146.750 546.830 ;
        RECT 0.335 545.990 147.025 546.010 ;
        RECT 0.610 545.170 147.025 545.990 ;
        RECT 0.335 545.150 147.025 545.170 ;
        RECT 0.335 544.330 146.750 545.150 ;
        RECT 0.335 543.470 147.025 544.330 ;
        RECT 0.335 542.650 146.750 543.470 ;
        RECT 0.335 541.790 147.025 542.650 ;
        RECT 0.335 540.970 146.750 541.790 ;
        RECT 0.335 540.110 147.025 540.970 ;
        RECT 0.610 539.290 146.750 540.110 ;
        RECT 0.335 538.430 147.025 539.290 ;
        RECT 0.335 537.610 146.750 538.430 ;
        RECT 0.335 536.750 147.025 537.610 ;
        RECT 0.335 535.930 146.750 536.750 ;
        RECT 0.335 535.070 147.025 535.930 ;
        RECT 0.335 534.250 146.750 535.070 ;
        RECT 0.335 534.230 147.025 534.250 ;
        RECT 0.610 533.410 147.025 534.230 ;
        RECT 0.335 533.390 147.025 533.410 ;
        RECT 0.335 532.570 146.750 533.390 ;
        RECT 0.335 531.710 147.025 532.570 ;
        RECT 0.335 530.890 146.750 531.710 ;
        RECT 0.335 530.030 147.025 530.890 ;
        RECT 0.335 529.210 146.750 530.030 ;
        RECT 0.335 528.350 147.025 529.210 ;
        RECT 0.610 527.530 146.750 528.350 ;
        RECT 0.335 526.670 147.025 527.530 ;
        RECT 0.335 525.850 146.750 526.670 ;
        RECT 0.335 524.990 147.025 525.850 ;
        RECT 0.335 524.170 146.750 524.990 ;
        RECT 0.335 523.310 147.025 524.170 ;
        RECT 0.335 522.490 146.750 523.310 ;
        RECT 0.335 522.470 147.025 522.490 ;
        RECT 0.610 521.650 147.025 522.470 ;
        RECT 0.335 521.630 147.025 521.650 ;
        RECT 0.335 520.810 146.750 521.630 ;
        RECT 0.335 519.950 147.025 520.810 ;
        RECT 0.335 519.130 146.750 519.950 ;
        RECT 0.335 518.270 147.025 519.130 ;
        RECT 0.335 517.450 146.750 518.270 ;
        RECT 0.335 516.590 147.025 517.450 ;
        RECT 0.610 515.770 146.750 516.590 ;
        RECT 0.335 514.910 147.025 515.770 ;
        RECT 0.335 514.090 146.750 514.910 ;
        RECT 0.335 513.230 147.025 514.090 ;
        RECT 0.335 512.410 146.750 513.230 ;
        RECT 0.335 511.550 147.025 512.410 ;
        RECT 0.335 510.730 146.750 511.550 ;
        RECT 0.335 510.710 147.025 510.730 ;
        RECT 0.610 509.890 147.025 510.710 ;
        RECT 0.335 509.870 147.025 509.890 ;
        RECT 0.335 509.050 146.750 509.870 ;
        RECT 0.335 508.190 147.025 509.050 ;
        RECT 0.335 507.370 146.750 508.190 ;
        RECT 0.335 506.510 147.025 507.370 ;
        RECT 0.335 505.690 146.750 506.510 ;
        RECT 0.335 504.830 147.025 505.690 ;
        RECT 0.610 504.010 146.750 504.830 ;
        RECT 0.335 503.150 147.025 504.010 ;
        RECT 0.335 502.330 146.750 503.150 ;
        RECT 0.335 501.470 147.025 502.330 ;
        RECT 0.335 500.650 146.750 501.470 ;
        RECT 0.335 499.790 147.025 500.650 ;
        RECT 0.335 498.970 146.750 499.790 ;
        RECT 0.335 498.950 147.025 498.970 ;
        RECT 0.610 498.130 147.025 498.950 ;
        RECT 0.335 498.110 147.025 498.130 ;
        RECT 0.335 497.290 146.750 498.110 ;
        RECT 0.335 496.430 147.025 497.290 ;
        RECT 0.335 495.610 146.750 496.430 ;
        RECT 0.335 494.750 147.025 495.610 ;
        RECT 0.335 493.930 146.750 494.750 ;
        RECT 0.335 493.070 147.025 493.930 ;
        RECT 0.610 492.250 146.750 493.070 ;
        RECT 0.335 491.390 147.025 492.250 ;
        RECT 0.335 490.570 146.750 491.390 ;
        RECT 0.335 487.190 147.025 490.570 ;
        RECT 0.610 486.370 147.025 487.190 ;
        RECT 0.335 483.830 147.025 486.370 ;
        RECT 0.335 483.010 146.750 483.830 ;
        RECT 0.335 482.990 147.025 483.010 ;
        RECT 0.335 482.170 146.750 482.990 ;
        RECT 0.335 482.150 147.025 482.170 ;
        RECT 0.335 481.330 146.750 482.150 ;
        RECT 0.335 481.310 147.025 481.330 ;
        RECT 0.610 480.490 146.750 481.310 ;
        RECT 0.335 480.470 147.025 480.490 ;
        RECT 0.335 479.650 146.750 480.470 ;
        RECT 0.335 479.630 147.025 479.650 ;
        RECT 0.335 478.810 146.750 479.630 ;
        RECT 0.335 478.790 147.025 478.810 ;
        RECT 0.335 477.970 146.750 478.790 ;
        RECT 0.335 477.950 147.025 477.970 ;
        RECT 0.335 477.130 146.750 477.950 ;
        RECT 0.335 477.110 147.025 477.130 ;
        RECT 0.335 476.290 146.750 477.110 ;
        RECT 0.335 476.270 147.025 476.290 ;
        RECT 0.335 475.450 146.750 476.270 ;
        RECT 0.335 475.430 147.025 475.450 ;
        RECT 0.610 474.610 146.750 475.430 ;
        RECT 0.335 474.590 147.025 474.610 ;
        RECT 0.335 473.770 146.750 474.590 ;
        RECT 0.335 473.750 147.025 473.770 ;
        RECT 0.335 472.930 146.750 473.750 ;
        RECT 0.335 472.910 147.025 472.930 ;
        RECT 0.335 472.090 146.750 472.910 ;
        RECT 0.335 472.070 147.025 472.090 ;
        RECT 0.335 471.250 146.750 472.070 ;
        RECT 0.335 471.230 147.025 471.250 ;
        RECT 0.335 470.410 146.750 471.230 ;
        RECT 0.335 469.550 147.025 470.410 ;
        RECT 0.610 468.730 147.025 469.550 ;
        RECT 0.335 463.670 147.025 468.730 ;
        RECT 0.610 462.850 146.750 463.670 ;
        RECT 0.335 461.990 147.025 462.850 ;
        RECT 0.335 461.170 146.750 461.990 ;
        RECT 0.335 460.310 147.025 461.170 ;
        RECT 0.335 459.490 146.750 460.310 ;
        RECT 0.335 458.630 147.025 459.490 ;
        RECT 0.335 457.810 146.750 458.630 ;
        RECT 0.335 457.790 147.025 457.810 ;
        RECT 0.610 456.970 147.025 457.790 ;
        RECT 0.335 456.950 147.025 456.970 ;
        RECT 0.335 456.130 146.750 456.950 ;
        RECT 0.335 455.270 147.025 456.130 ;
        RECT 0.335 454.450 146.750 455.270 ;
        RECT 0.335 453.590 147.025 454.450 ;
        RECT 0.335 452.770 146.750 453.590 ;
        RECT 0.335 451.910 147.025 452.770 ;
        RECT 0.610 451.090 146.750 451.910 ;
        RECT 0.335 447.710 147.025 451.090 ;
        RECT 0.335 446.890 146.750 447.710 ;
        RECT 0.335 446.870 147.025 446.890 ;
        RECT 0.335 446.050 146.750 446.870 ;
        RECT 0.335 446.030 147.025 446.050 ;
        RECT 0.335 445.210 146.750 446.030 ;
        RECT 0.335 445.190 147.025 445.210 ;
        RECT 0.335 444.370 146.750 445.190 ;
        RECT 0.335 444.350 147.025 444.370 ;
        RECT 0.335 443.530 146.750 444.350 ;
        RECT 0.335 443.510 147.025 443.530 ;
        RECT 0.335 442.690 146.750 443.510 ;
        RECT 0.335 442.670 147.025 442.690 ;
        RECT 0.335 441.850 146.750 442.670 ;
        RECT 0.335 441.830 147.025 441.850 ;
        RECT 0.335 441.010 146.750 441.830 ;
        RECT 0.335 437.630 147.025 441.010 ;
        RECT 0.335 436.810 146.750 437.630 ;
        RECT 0.335 435.950 147.025 436.810 ;
        RECT 0.335 435.130 146.750 435.950 ;
        RECT 0.335 435.110 147.025 435.130 ;
        RECT 0.610 434.290 147.025 435.110 ;
        RECT 0.335 434.270 147.025 434.290 ;
        RECT 0.335 433.450 146.750 434.270 ;
        RECT 0.335 432.590 147.025 433.450 ;
        RECT 0.335 431.770 146.750 432.590 ;
        RECT 0.335 430.490 147.025 431.770 ;
        RECT 0.335 429.670 146.750 430.490 ;
        RECT 0.335 428.810 147.025 429.670 ;
        RECT 0.335 427.990 146.750 428.810 ;
        RECT 0.335 427.130 147.025 427.990 ;
        RECT 0.335 426.310 146.750 427.130 ;
        RECT 0.335 425.450 147.025 426.310 ;
        RECT 0.335 424.630 146.750 425.450 ;
        RECT 0.335 423.770 147.025 424.630 ;
        RECT 0.335 422.950 146.750 423.770 ;
        RECT 0.335 422.090 147.025 422.950 ;
        RECT 0.335 421.270 146.750 422.090 ;
        RECT 0.335 420.410 147.025 421.270 ;
        RECT 0.335 419.590 146.750 420.410 ;
        RECT 0.335 418.730 147.025 419.590 ;
        RECT 0.610 417.910 146.750 418.730 ;
        RECT 0.335 417.050 147.025 417.910 ;
        RECT 0.335 416.230 146.750 417.050 ;
        RECT 0.335 415.370 147.025 416.230 ;
        RECT 0.335 414.550 146.750 415.370 ;
        RECT 0.335 413.690 147.025 414.550 ;
        RECT 0.335 412.870 146.750 413.690 ;
        RECT 0.335 412.850 147.025 412.870 ;
        RECT 0.610 412.030 147.025 412.850 ;
        RECT 0.335 412.010 147.025 412.030 ;
        RECT 0.335 411.190 146.750 412.010 ;
        RECT 0.335 410.330 147.025 411.190 ;
        RECT 0.335 409.510 146.750 410.330 ;
        RECT 0.335 408.650 147.025 409.510 ;
        RECT 0.335 407.830 146.750 408.650 ;
        RECT 0.335 406.970 147.025 407.830 ;
        RECT 0.610 406.150 146.750 406.970 ;
        RECT 0.335 405.290 147.025 406.150 ;
        RECT 0.335 404.470 146.750 405.290 ;
        RECT 0.335 403.610 147.025 404.470 ;
        RECT 0.335 402.790 146.750 403.610 ;
        RECT 0.335 401.930 147.025 402.790 ;
        RECT 0.335 401.110 146.750 401.930 ;
        RECT 0.335 401.090 147.025 401.110 ;
        RECT 0.610 400.270 147.025 401.090 ;
        RECT 0.335 400.250 147.025 400.270 ;
        RECT 0.335 399.430 146.750 400.250 ;
        RECT 0.335 398.570 147.025 399.430 ;
        RECT 0.335 397.750 146.750 398.570 ;
        RECT 0.335 396.890 147.025 397.750 ;
        RECT 0.335 396.070 146.750 396.890 ;
        RECT 0.335 395.210 147.025 396.070 ;
        RECT 0.610 394.390 146.750 395.210 ;
        RECT 0.335 393.530 147.025 394.390 ;
        RECT 0.335 392.710 146.750 393.530 ;
        RECT 0.335 391.850 147.025 392.710 ;
        RECT 0.335 391.030 146.750 391.850 ;
        RECT 0.335 390.170 147.025 391.030 ;
        RECT 0.335 389.350 146.750 390.170 ;
        RECT 0.335 389.330 147.025 389.350 ;
        RECT 0.610 388.510 147.025 389.330 ;
        RECT 0.335 388.490 147.025 388.510 ;
        RECT 0.335 387.670 146.750 388.490 ;
        RECT 0.335 386.810 147.025 387.670 ;
        RECT 0.335 385.990 146.750 386.810 ;
        RECT 0.335 385.130 147.025 385.990 ;
        RECT 0.335 384.310 146.750 385.130 ;
        RECT 0.335 383.450 147.025 384.310 ;
        RECT 0.610 382.630 146.750 383.450 ;
        RECT 0.335 381.770 147.025 382.630 ;
        RECT 0.335 380.950 146.750 381.770 ;
        RECT 0.335 380.090 147.025 380.950 ;
        RECT 0.335 379.270 146.750 380.090 ;
        RECT 0.335 378.410 147.025 379.270 ;
        RECT 0.335 377.590 146.750 378.410 ;
        RECT 0.335 377.570 147.025 377.590 ;
        RECT 0.610 376.750 147.025 377.570 ;
        RECT 0.335 376.730 147.025 376.750 ;
        RECT 0.335 375.910 146.750 376.730 ;
        RECT 0.335 375.050 147.025 375.910 ;
        RECT 0.335 374.230 146.750 375.050 ;
        RECT 0.335 373.370 147.025 374.230 ;
        RECT 0.335 372.550 146.750 373.370 ;
        RECT 0.335 371.690 147.025 372.550 ;
        RECT 0.610 370.870 146.750 371.690 ;
        RECT 0.335 370.010 147.025 370.870 ;
        RECT 0.335 369.190 146.750 370.010 ;
        RECT 0.335 368.330 147.025 369.190 ;
        RECT 0.335 367.510 146.750 368.330 ;
        RECT 0.335 366.650 147.025 367.510 ;
        RECT 0.335 365.830 146.750 366.650 ;
        RECT 0.335 365.810 147.025 365.830 ;
        RECT 0.610 364.990 147.025 365.810 ;
        RECT 0.335 364.970 147.025 364.990 ;
        RECT 0.335 364.150 146.750 364.970 ;
        RECT 0.335 363.290 147.025 364.150 ;
        RECT 0.335 362.470 146.750 363.290 ;
        RECT 0.335 361.610 147.025 362.470 ;
        RECT 0.335 360.790 146.750 361.610 ;
        RECT 0.335 359.930 147.025 360.790 ;
        RECT 0.610 359.110 146.750 359.930 ;
        RECT 0.335 358.250 147.025 359.110 ;
        RECT 0.335 357.430 146.750 358.250 ;
        RECT 0.335 356.570 147.025 357.430 ;
        RECT 0.335 355.750 146.750 356.570 ;
        RECT 0.335 354.890 147.025 355.750 ;
        RECT 0.335 354.070 146.750 354.890 ;
        RECT 0.335 354.050 147.025 354.070 ;
        RECT 0.610 353.230 147.025 354.050 ;
        RECT 0.335 353.210 147.025 353.230 ;
        RECT 0.335 352.390 146.750 353.210 ;
        RECT 0.335 351.530 147.025 352.390 ;
        RECT 0.335 350.710 146.750 351.530 ;
        RECT 0.335 349.850 147.025 350.710 ;
        RECT 0.335 349.030 146.750 349.850 ;
        RECT 0.335 348.170 147.025 349.030 ;
        RECT 0.610 347.350 146.750 348.170 ;
        RECT 0.335 346.490 147.025 347.350 ;
        RECT 0.335 345.670 146.750 346.490 ;
        RECT 0.335 344.810 147.025 345.670 ;
        RECT 0.335 343.990 146.750 344.810 ;
        RECT 0.335 343.130 147.025 343.990 ;
        RECT 0.335 342.310 146.750 343.130 ;
        RECT 0.335 342.290 147.025 342.310 ;
        RECT 0.610 341.470 147.025 342.290 ;
        RECT 0.335 341.450 147.025 341.470 ;
        RECT 0.335 340.630 146.750 341.450 ;
        RECT 0.335 339.770 147.025 340.630 ;
        RECT 0.335 338.950 146.750 339.770 ;
        RECT 0.335 338.090 147.025 338.950 ;
        RECT 0.335 337.270 146.750 338.090 ;
        RECT 0.335 336.410 147.025 337.270 ;
        RECT 0.610 335.590 146.750 336.410 ;
        RECT 0.335 334.730 147.025 335.590 ;
        RECT 0.335 333.910 146.750 334.730 ;
        RECT 0.335 333.050 147.025 333.910 ;
        RECT 0.335 332.230 146.750 333.050 ;
        RECT 0.335 331.370 147.025 332.230 ;
        RECT 0.335 330.550 146.750 331.370 ;
        RECT 0.335 330.530 147.025 330.550 ;
        RECT 0.610 329.710 147.025 330.530 ;
        RECT 0.335 329.690 147.025 329.710 ;
        RECT 0.335 328.870 146.750 329.690 ;
        RECT 0.335 328.010 147.025 328.870 ;
        RECT 0.335 327.190 146.750 328.010 ;
        RECT 0.335 326.330 147.025 327.190 ;
        RECT 0.335 325.510 146.750 326.330 ;
        RECT 0.335 324.650 147.025 325.510 ;
        RECT 0.610 323.830 146.750 324.650 ;
        RECT 0.335 322.970 147.025 323.830 ;
        RECT 0.335 322.150 146.750 322.970 ;
        RECT 0.335 321.290 147.025 322.150 ;
        RECT 0.335 320.470 146.750 321.290 ;
        RECT 0.335 319.610 147.025 320.470 ;
        RECT 0.335 318.790 146.750 319.610 ;
        RECT 0.335 318.770 147.025 318.790 ;
        RECT 0.610 317.950 147.025 318.770 ;
        RECT 0.335 317.930 147.025 317.950 ;
        RECT 0.335 317.110 146.750 317.930 ;
        RECT 0.335 316.250 147.025 317.110 ;
        RECT 0.335 315.430 146.750 316.250 ;
        RECT 0.335 314.570 147.025 315.430 ;
        RECT 0.335 313.750 146.750 314.570 ;
        RECT 0.335 312.890 147.025 313.750 ;
        RECT 0.610 312.070 146.750 312.890 ;
        RECT 0.335 311.210 147.025 312.070 ;
        RECT 0.335 310.390 146.750 311.210 ;
        RECT 0.335 309.530 147.025 310.390 ;
        RECT 0.335 308.710 146.750 309.530 ;
        RECT 0.335 307.850 147.025 308.710 ;
        RECT 0.335 307.030 146.750 307.850 ;
        RECT 0.335 307.010 147.025 307.030 ;
        RECT 0.610 306.190 147.025 307.010 ;
        RECT 0.335 306.170 147.025 306.190 ;
        RECT 0.335 305.350 146.750 306.170 ;
        RECT 0.335 304.490 147.025 305.350 ;
        RECT 0.335 303.670 146.750 304.490 ;
        RECT 0.335 302.810 147.025 303.670 ;
        RECT 0.335 301.990 146.750 302.810 ;
        RECT 0.335 301.130 147.025 301.990 ;
        RECT 0.610 300.310 146.750 301.130 ;
        RECT 0.335 299.450 147.025 300.310 ;
        RECT 0.335 298.630 146.750 299.450 ;
        RECT 0.335 297.770 147.025 298.630 ;
        RECT 0.335 296.950 146.750 297.770 ;
        RECT 0.335 296.090 147.025 296.950 ;
        RECT 0.335 295.270 146.750 296.090 ;
        RECT 0.335 295.250 147.025 295.270 ;
        RECT 0.610 294.430 147.025 295.250 ;
        RECT 0.335 294.410 147.025 294.430 ;
        RECT 0.335 293.590 146.750 294.410 ;
        RECT 0.335 292.730 147.025 293.590 ;
        RECT 0.335 291.910 146.750 292.730 ;
        RECT 0.335 291.050 147.025 291.910 ;
        RECT 0.335 290.230 146.750 291.050 ;
        RECT 0.335 289.370 147.025 290.230 ;
        RECT 0.610 288.550 146.750 289.370 ;
        RECT 0.335 287.690 147.025 288.550 ;
        RECT 0.335 286.870 146.750 287.690 ;
        RECT 0.335 286.010 147.025 286.870 ;
        RECT 0.335 285.190 146.750 286.010 ;
        RECT 0.335 284.330 147.025 285.190 ;
        RECT 0.335 283.510 146.750 284.330 ;
        RECT 0.335 283.490 147.025 283.510 ;
        RECT 0.610 282.670 147.025 283.490 ;
        RECT 0.335 282.650 147.025 282.670 ;
        RECT 0.335 281.830 146.750 282.650 ;
        RECT 0.335 280.970 147.025 281.830 ;
        RECT 0.335 280.150 146.750 280.970 ;
        RECT 0.335 279.290 147.025 280.150 ;
        RECT 0.335 278.470 146.750 279.290 ;
        RECT 0.335 277.610 147.025 278.470 ;
        RECT 0.610 276.790 146.750 277.610 ;
        RECT 0.335 275.930 147.025 276.790 ;
        RECT 0.335 275.110 146.750 275.930 ;
        RECT 0.335 271.730 147.025 275.110 ;
        RECT 0.610 270.910 147.025 271.730 ;
        RECT 0.335 268.370 147.025 270.910 ;
        RECT 0.335 267.550 146.750 268.370 ;
        RECT 0.335 267.530 147.025 267.550 ;
        RECT 0.335 266.710 146.750 267.530 ;
        RECT 0.335 266.690 147.025 266.710 ;
        RECT 0.335 265.870 146.750 266.690 ;
        RECT 0.335 265.850 147.025 265.870 ;
        RECT 0.610 265.030 146.750 265.850 ;
        RECT 0.335 265.010 147.025 265.030 ;
        RECT 0.335 264.190 146.750 265.010 ;
        RECT 0.335 264.170 147.025 264.190 ;
        RECT 0.335 263.350 146.750 264.170 ;
        RECT 0.335 263.330 147.025 263.350 ;
        RECT 0.335 262.510 146.750 263.330 ;
        RECT 0.335 262.490 147.025 262.510 ;
        RECT 0.335 261.670 146.750 262.490 ;
        RECT 0.335 261.650 147.025 261.670 ;
        RECT 0.335 260.830 146.750 261.650 ;
        RECT 0.335 260.810 147.025 260.830 ;
        RECT 0.335 259.990 146.750 260.810 ;
        RECT 0.335 259.970 147.025 259.990 ;
        RECT 0.610 259.150 146.750 259.970 ;
        RECT 0.335 259.130 147.025 259.150 ;
        RECT 0.335 258.310 146.750 259.130 ;
        RECT 0.335 258.290 147.025 258.310 ;
        RECT 0.335 257.470 146.750 258.290 ;
        RECT 0.335 257.450 147.025 257.470 ;
        RECT 0.335 256.630 146.750 257.450 ;
        RECT 0.335 256.610 147.025 256.630 ;
        RECT 0.335 255.790 146.750 256.610 ;
        RECT 0.335 255.770 147.025 255.790 ;
        RECT 0.335 254.950 146.750 255.770 ;
        RECT 0.335 254.090 147.025 254.950 ;
        RECT 0.610 253.270 147.025 254.090 ;
        RECT 0.335 248.210 147.025 253.270 ;
        RECT 0.610 247.390 146.750 248.210 ;
        RECT 0.335 246.530 147.025 247.390 ;
        RECT 0.335 245.710 146.750 246.530 ;
        RECT 0.335 244.850 147.025 245.710 ;
        RECT 0.335 244.030 146.750 244.850 ;
        RECT 0.335 243.170 147.025 244.030 ;
        RECT 0.335 242.350 146.750 243.170 ;
        RECT 0.335 242.330 147.025 242.350 ;
        RECT 0.610 241.510 147.025 242.330 ;
        RECT 0.335 241.490 147.025 241.510 ;
        RECT 0.335 240.670 146.750 241.490 ;
        RECT 0.335 239.810 147.025 240.670 ;
        RECT 0.335 238.990 146.750 239.810 ;
        RECT 0.335 238.130 147.025 238.990 ;
        RECT 0.335 237.310 146.750 238.130 ;
        RECT 0.335 236.450 147.025 237.310 ;
        RECT 0.610 235.630 146.750 236.450 ;
        RECT 0.335 232.250 147.025 235.630 ;
        RECT 0.335 231.430 146.750 232.250 ;
        RECT 0.335 231.410 147.025 231.430 ;
        RECT 0.335 230.590 146.750 231.410 ;
        RECT 0.335 230.570 147.025 230.590 ;
        RECT 0.335 229.750 146.750 230.570 ;
        RECT 0.335 229.730 147.025 229.750 ;
        RECT 0.335 228.910 146.750 229.730 ;
        RECT 0.335 228.890 147.025 228.910 ;
        RECT 0.335 228.070 146.750 228.890 ;
        RECT 0.335 228.050 147.025 228.070 ;
        RECT 0.335 227.230 146.750 228.050 ;
        RECT 0.335 227.210 147.025 227.230 ;
        RECT 0.335 226.390 146.750 227.210 ;
        RECT 0.335 226.370 147.025 226.390 ;
        RECT 0.335 225.550 146.750 226.370 ;
        RECT 0.335 222.170 147.025 225.550 ;
        RECT 0.335 221.350 146.750 222.170 ;
        RECT 0.335 220.490 147.025 221.350 ;
        RECT 0.335 219.670 146.750 220.490 ;
        RECT 0.335 219.650 147.025 219.670 ;
        RECT 0.610 218.830 147.025 219.650 ;
        RECT 0.335 218.810 147.025 218.830 ;
        RECT 0.335 217.990 146.750 218.810 ;
        RECT 0.335 217.130 147.025 217.990 ;
        RECT 0.335 216.310 146.750 217.130 ;
        RECT 0.335 215.030 147.025 216.310 ;
        RECT 0.335 214.210 146.750 215.030 ;
        RECT 0.335 213.350 147.025 214.210 ;
        RECT 0.335 212.530 146.750 213.350 ;
        RECT 0.335 211.670 147.025 212.530 ;
        RECT 0.335 210.850 146.750 211.670 ;
        RECT 0.335 209.990 147.025 210.850 ;
        RECT 0.335 209.170 146.750 209.990 ;
        RECT 0.335 208.310 147.025 209.170 ;
        RECT 0.335 207.490 146.750 208.310 ;
        RECT 0.335 206.630 147.025 207.490 ;
        RECT 0.335 205.810 146.750 206.630 ;
        RECT 0.335 204.950 147.025 205.810 ;
        RECT 0.335 204.130 146.750 204.950 ;
        RECT 0.335 203.270 147.025 204.130 ;
        RECT 0.335 202.450 146.750 203.270 ;
        RECT 0.335 201.590 147.025 202.450 ;
        RECT 0.335 200.770 146.750 201.590 ;
        RECT 0.335 199.910 147.025 200.770 ;
        RECT 0.335 199.090 146.750 199.910 ;
        RECT 0.335 198.230 147.025 199.090 ;
        RECT 0.610 197.410 146.750 198.230 ;
        RECT 0.335 197.390 147.025 197.410 ;
        RECT 0.610 196.570 147.025 197.390 ;
        RECT 0.335 196.550 147.025 196.570 ;
        RECT 0.610 195.730 146.750 196.550 ;
        RECT 0.335 195.710 147.025 195.730 ;
        RECT 0.610 194.890 147.025 195.710 ;
        RECT 0.335 194.870 147.025 194.890 ;
        RECT 0.610 194.050 146.750 194.870 ;
        RECT 0.335 194.030 147.025 194.050 ;
        RECT 0.610 193.210 147.025 194.030 ;
        RECT 0.335 193.190 147.025 193.210 ;
        RECT 0.610 192.370 146.750 193.190 ;
        RECT 0.335 192.350 147.025 192.370 ;
        RECT 0.610 191.530 147.025 192.350 ;
        RECT 0.335 191.510 147.025 191.530 ;
        RECT 0.610 190.690 146.750 191.510 ;
        RECT 0.335 190.670 147.025 190.690 ;
        RECT 0.610 189.850 147.025 190.670 ;
        RECT 0.335 189.830 147.025 189.850 ;
        RECT 0.610 189.010 146.750 189.830 ;
        RECT 0.335 188.990 147.025 189.010 ;
        RECT 0.610 188.170 147.025 188.990 ;
        RECT 0.335 188.150 147.025 188.170 ;
        RECT 0.610 187.330 146.750 188.150 ;
        RECT 0.335 187.310 147.025 187.330 ;
        RECT 0.610 186.490 147.025 187.310 ;
        RECT 0.335 186.470 147.025 186.490 ;
        RECT 0.610 185.650 146.750 186.470 ;
        RECT 0.335 185.630 147.025 185.650 ;
        RECT 0.610 184.810 147.025 185.630 ;
        RECT 0.335 184.790 147.025 184.810 ;
        RECT 0.610 183.970 146.750 184.790 ;
        RECT 0.335 183.950 147.025 183.970 ;
        RECT 0.610 183.130 147.025 183.950 ;
        RECT 0.335 183.110 147.025 183.130 ;
        RECT 0.610 182.290 146.750 183.110 ;
        RECT 0.335 182.270 147.025 182.290 ;
        RECT 0.610 181.450 147.025 182.270 ;
        RECT 0.335 181.430 147.025 181.450 ;
        RECT 0.610 180.610 146.750 181.430 ;
        RECT 0.335 180.590 147.025 180.610 ;
        RECT 0.610 179.770 147.025 180.590 ;
        RECT 0.335 179.750 147.025 179.770 ;
        RECT 0.610 178.930 146.750 179.750 ;
        RECT 0.335 178.910 147.025 178.930 ;
        RECT 0.610 178.090 147.025 178.910 ;
        RECT 0.335 178.070 147.025 178.090 ;
        RECT 0.610 177.250 146.750 178.070 ;
        RECT 0.335 177.230 147.025 177.250 ;
        RECT 0.610 176.410 147.025 177.230 ;
        RECT 0.335 176.390 147.025 176.410 ;
        RECT 0.610 175.570 146.750 176.390 ;
        RECT 0.335 175.550 147.025 175.570 ;
        RECT 0.610 174.730 147.025 175.550 ;
        RECT 0.335 174.710 147.025 174.730 ;
        RECT 0.610 173.890 146.750 174.710 ;
        RECT 0.335 173.870 147.025 173.890 ;
        RECT 0.610 173.050 147.025 173.870 ;
        RECT 0.335 173.030 147.025 173.050 ;
        RECT 0.610 172.210 146.750 173.030 ;
        RECT 0.335 172.190 147.025 172.210 ;
        RECT 0.610 171.370 147.025 172.190 ;
        RECT 0.335 171.350 147.025 171.370 ;
        RECT 0.610 170.530 146.750 171.350 ;
        RECT 0.335 170.510 147.025 170.530 ;
        RECT 0.610 169.690 147.025 170.510 ;
        RECT 0.335 169.670 147.025 169.690 ;
        RECT 0.610 168.850 146.750 169.670 ;
        RECT 0.335 168.830 147.025 168.850 ;
        RECT 0.610 168.010 147.025 168.830 ;
        RECT 0.335 167.990 147.025 168.010 ;
        RECT 0.610 167.170 146.750 167.990 ;
        RECT 0.335 167.150 147.025 167.170 ;
        RECT 0.610 166.330 147.025 167.150 ;
        RECT 0.335 166.310 147.025 166.330 ;
        RECT 0.610 165.490 146.750 166.310 ;
        RECT 0.335 165.470 147.025 165.490 ;
        RECT 0.610 164.650 147.025 165.470 ;
        RECT 0.335 164.630 147.025 164.650 ;
        RECT 0.610 163.810 146.750 164.630 ;
        RECT 0.335 163.790 147.025 163.810 ;
        RECT 0.610 162.970 147.025 163.790 ;
        RECT 0.335 162.950 147.025 162.970 ;
        RECT 0.610 162.130 146.750 162.950 ;
        RECT 0.335 162.110 147.025 162.130 ;
        RECT 0.610 161.290 147.025 162.110 ;
        RECT 0.335 161.270 147.025 161.290 ;
        RECT 0.610 160.450 146.750 161.270 ;
        RECT 0.335 160.430 147.025 160.450 ;
        RECT 0.610 159.610 147.025 160.430 ;
        RECT 0.335 159.590 147.025 159.610 ;
        RECT 0.610 158.770 146.750 159.590 ;
        RECT 0.335 158.750 147.025 158.770 ;
        RECT 0.610 157.930 147.025 158.750 ;
        RECT 0.335 157.910 147.025 157.930 ;
        RECT 0.610 157.090 146.750 157.910 ;
        RECT 0.335 157.070 147.025 157.090 ;
        RECT 0.610 156.250 147.025 157.070 ;
        RECT 0.335 156.230 147.025 156.250 ;
        RECT 0.610 155.410 146.750 156.230 ;
        RECT 0.335 155.390 147.025 155.410 ;
        RECT 0.610 154.570 147.025 155.390 ;
        RECT 0.335 154.550 147.025 154.570 ;
        RECT 0.610 153.730 146.750 154.550 ;
        RECT 0.335 153.710 147.025 153.730 ;
        RECT 0.610 152.890 147.025 153.710 ;
        RECT 0.335 152.870 147.025 152.890 ;
        RECT 0.610 152.050 146.750 152.870 ;
        RECT 0.335 152.030 147.025 152.050 ;
        RECT 0.610 151.210 147.025 152.030 ;
        RECT 0.335 151.190 147.025 151.210 ;
        RECT 0.610 150.370 146.750 151.190 ;
        RECT 0.335 150.350 147.025 150.370 ;
        RECT 0.610 149.530 147.025 150.350 ;
        RECT 0.335 149.510 147.025 149.530 ;
        RECT 0.610 148.690 146.750 149.510 ;
        RECT 0.335 148.670 147.025 148.690 ;
        RECT 0.610 147.850 147.025 148.670 ;
        RECT 0.335 147.830 147.025 147.850 ;
        RECT 0.610 147.010 146.750 147.830 ;
        RECT 0.335 146.990 147.025 147.010 ;
        RECT 0.610 146.170 147.025 146.990 ;
        RECT 0.335 146.150 147.025 146.170 ;
        RECT 0.610 145.330 146.750 146.150 ;
        RECT 0.335 145.310 147.025 145.330 ;
        RECT 0.610 144.490 147.025 145.310 ;
        RECT 0.335 144.470 147.025 144.490 ;
        RECT 0.610 143.650 146.750 144.470 ;
        RECT 0.335 143.630 147.025 143.650 ;
        RECT 0.610 142.810 147.025 143.630 ;
        RECT 0.335 142.790 147.025 142.810 ;
        RECT 0.610 141.970 146.750 142.790 ;
        RECT 0.335 141.950 147.025 141.970 ;
        RECT 0.610 141.130 147.025 141.950 ;
        RECT 0.335 141.110 147.025 141.130 ;
        RECT 0.610 140.290 146.750 141.110 ;
        RECT 0.335 140.270 147.025 140.290 ;
        RECT 0.610 139.450 147.025 140.270 ;
        RECT 0.335 139.430 147.025 139.450 ;
        RECT 0.610 138.610 146.750 139.430 ;
        RECT 0.335 138.590 147.025 138.610 ;
        RECT 0.610 137.770 147.025 138.590 ;
        RECT 0.335 137.750 147.025 137.770 ;
        RECT 0.610 136.930 146.750 137.750 ;
        RECT 0.335 136.910 147.025 136.930 ;
        RECT 0.610 136.090 147.025 136.910 ;
        RECT 0.335 136.070 147.025 136.090 ;
        RECT 0.610 135.250 146.750 136.070 ;
        RECT 0.335 135.230 147.025 135.250 ;
        RECT 0.610 134.410 147.025 135.230 ;
        RECT 0.335 134.390 147.025 134.410 ;
        RECT 0.610 133.570 146.750 134.390 ;
        RECT 0.335 133.550 147.025 133.570 ;
        RECT 0.610 132.730 147.025 133.550 ;
        RECT 0.335 132.710 147.025 132.730 ;
        RECT 0.610 131.890 146.750 132.710 ;
        RECT 0.335 131.870 147.025 131.890 ;
        RECT 0.610 131.050 147.025 131.870 ;
        RECT 0.335 131.030 147.025 131.050 ;
        RECT 0.610 130.210 146.750 131.030 ;
        RECT 0.335 130.190 147.025 130.210 ;
        RECT 0.610 129.370 147.025 130.190 ;
        RECT 0.335 129.350 147.025 129.370 ;
        RECT 0.610 128.530 146.750 129.350 ;
        RECT 0.335 128.510 147.025 128.530 ;
        RECT 0.610 127.690 147.025 128.510 ;
        RECT 0.335 127.670 147.025 127.690 ;
        RECT 0.610 126.850 146.750 127.670 ;
        RECT 0.335 126.830 147.025 126.850 ;
        RECT 0.610 126.010 147.025 126.830 ;
        RECT 0.335 125.990 147.025 126.010 ;
        RECT 0.610 125.170 146.750 125.990 ;
        RECT 0.335 125.150 147.025 125.170 ;
        RECT 0.610 124.330 147.025 125.150 ;
        RECT 0.335 124.310 147.025 124.330 ;
        RECT 0.610 123.490 146.750 124.310 ;
        RECT 0.335 123.470 147.025 123.490 ;
        RECT 0.610 122.650 147.025 123.470 ;
        RECT 0.335 122.630 147.025 122.650 ;
        RECT 0.610 121.810 146.750 122.630 ;
        RECT 0.335 121.790 147.025 121.810 ;
        RECT 0.610 120.970 147.025 121.790 ;
        RECT 0.335 120.950 147.025 120.970 ;
        RECT 0.610 120.130 146.750 120.950 ;
        RECT 0.335 120.110 147.025 120.130 ;
        RECT 0.610 119.290 147.025 120.110 ;
        RECT 0.335 119.270 147.025 119.290 ;
        RECT 0.610 118.450 146.750 119.270 ;
        RECT 0.335 118.430 147.025 118.450 ;
        RECT 0.610 117.610 147.025 118.430 ;
        RECT 0.335 117.590 147.025 117.610 ;
        RECT 0.610 116.770 146.750 117.590 ;
        RECT 0.335 116.750 147.025 116.770 ;
        RECT 0.610 115.930 147.025 116.750 ;
        RECT 0.335 115.910 147.025 115.930 ;
        RECT 0.610 115.090 146.750 115.910 ;
        RECT 0.335 115.070 147.025 115.090 ;
        RECT 0.610 114.250 147.025 115.070 ;
        RECT 0.335 114.230 147.025 114.250 ;
        RECT 0.610 113.410 146.750 114.230 ;
        RECT 0.335 113.390 147.025 113.410 ;
        RECT 0.610 112.570 147.025 113.390 ;
        RECT 0.335 112.550 147.025 112.570 ;
        RECT 0.610 111.730 146.750 112.550 ;
        RECT 0.335 111.710 147.025 111.730 ;
        RECT 0.610 110.890 147.025 111.710 ;
        RECT 0.335 110.870 147.025 110.890 ;
        RECT 0.610 110.050 146.750 110.870 ;
        RECT 0.335 110.030 147.025 110.050 ;
        RECT 0.610 109.210 147.025 110.030 ;
        RECT 0.335 109.190 147.025 109.210 ;
        RECT 0.610 108.370 146.750 109.190 ;
        RECT 0.335 108.350 147.025 108.370 ;
        RECT 0.610 107.530 147.025 108.350 ;
        RECT 0.335 107.510 147.025 107.530 ;
        RECT 0.610 106.690 146.750 107.510 ;
        RECT 0.335 106.670 147.025 106.690 ;
        RECT 0.610 105.850 147.025 106.670 ;
        RECT 0.335 105.830 147.025 105.850 ;
        RECT 0.610 105.010 146.750 105.830 ;
        RECT 0.335 104.990 147.025 105.010 ;
        RECT 0.610 104.170 147.025 104.990 ;
        RECT 0.335 104.150 147.025 104.170 ;
        RECT 0.610 103.330 146.750 104.150 ;
        RECT 0.335 103.310 147.025 103.330 ;
        RECT 0.610 102.490 147.025 103.310 ;
        RECT 0.335 102.470 147.025 102.490 ;
        RECT 0.610 101.650 146.750 102.470 ;
        RECT 0.335 101.630 147.025 101.650 ;
        RECT 0.610 100.810 147.025 101.630 ;
        RECT 0.335 100.790 147.025 100.810 ;
        RECT 0.610 99.970 146.750 100.790 ;
        RECT 0.335 99.950 147.025 99.970 ;
        RECT 0.610 99.130 147.025 99.950 ;
        RECT 0.335 99.110 147.025 99.130 ;
        RECT 0.610 98.290 146.750 99.110 ;
        RECT 0.335 98.270 147.025 98.290 ;
        RECT 0.610 97.450 147.025 98.270 ;
        RECT 0.335 97.430 147.025 97.450 ;
        RECT 0.610 96.610 146.750 97.430 ;
        RECT 0.335 96.590 147.025 96.610 ;
        RECT 0.610 95.770 147.025 96.590 ;
        RECT 0.335 95.750 147.025 95.770 ;
        RECT 0.610 94.930 146.750 95.750 ;
        RECT 0.335 94.910 147.025 94.930 ;
        RECT 0.610 94.090 147.025 94.910 ;
        RECT 0.335 94.070 147.025 94.090 ;
        RECT 0.610 93.250 146.750 94.070 ;
        RECT 0.335 93.230 147.025 93.250 ;
        RECT 0.610 92.410 147.025 93.230 ;
        RECT 0.335 92.390 147.025 92.410 ;
        RECT 0.610 91.570 146.750 92.390 ;
        RECT 0.335 91.550 147.025 91.570 ;
        RECT 0.610 90.730 147.025 91.550 ;
        RECT 0.335 90.710 147.025 90.730 ;
        RECT 0.610 89.890 146.750 90.710 ;
        RECT 0.335 89.870 147.025 89.890 ;
        RECT 0.610 89.050 147.025 89.870 ;
        RECT 0.335 89.030 147.025 89.050 ;
        RECT 0.610 88.210 146.750 89.030 ;
        RECT 0.335 88.190 147.025 88.210 ;
        RECT 0.610 87.370 147.025 88.190 ;
        RECT 0.335 87.350 147.025 87.370 ;
        RECT 0.610 86.530 146.750 87.350 ;
        RECT 0.335 86.510 147.025 86.530 ;
        RECT 0.610 85.690 147.025 86.510 ;
        RECT 0.335 85.670 147.025 85.690 ;
        RECT 0.610 84.850 146.750 85.670 ;
        RECT 0.335 84.830 147.025 84.850 ;
        RECT 0.610 84.010 147.025 84.830 ;
        RECT 0.335 83.990 147.025 84.010 ;
        RECT 0.610 83.170 146.750 83.990 ;
        RECT 0.335 83.150 147.025 83.170 ;
        RECT 0.610 82.330 147.025 83.150 ;
        RECT 0.335 82.310 147.025 82.330 ;
        RECT 0.610 81.490 146.750 82.310 ;
        RECT 0.335 81.470 147.025 81.490 ;
        RECT 0.610 80.650 147.025 81.470 ;
        RECT 0.335 80.630 147.025 80.650 ;
        RECT 0.610 79.810 146.750 80.630 ;
        RECT 0.335 79.790 147.025 79.810 ;
        RECT 0.610 78.970 147.025 79.790 ;
        RECT 0.335 78.950 147.025 78.970 ;
        RECT 0.610 78.130 146.750 78.950 ;
        RECT 0.335 78.110 147.025 78.130 ;
        RECT 0.610 77.290 147.025 78.110 ;
        RECT 0.335 77.270 147.025 77.290 ;
        RECT 0.610 76.450 146.750 77.270 ;
        RECT 0.335 76.430 147.025 76.450 ;
        RECT 0.610 75.610 147.025 76.430 ;
        RECT 0.335 75.590 147.025 75.610 ;
        RECT 0.610 74.770 146.750 75.590 ;
        RECT 0.335 74.750 147.025 74.770 ;
        RECT 0.610 73.930 147.025 74.750 ;
        RECT 0.335 73.910 147.025 73.930 ;
        RECT 0.610 73.090 146.750 73.910 ;
        RECT 0.335 73.070 147.025 73.090 ;
        RECT 0.610 72.250 147.025 73.070 ;
        RECT 0.335 72.230 147.025 72.250 ;
        RECT 0.610 71.410 146.750 72.230 ;
        RECT 0.335 71.390 147.025 71.410 ;
        RECT 0.610 70.570 147.025 71.390 ;
        RECT 0.335 70.550 147.025 70.570 ;
        RECT 0.610 69.730 146.750 70.550 ;
        RECT 0.335 69.710 147.025 69.730 ;
        RECT 0.610 68.890 147.025 69.710 ;
        RECT 0.335 68.870 147.025 68.890 ;
        RECT 0.610 68.050 146.750 68.870 ;
        RECT 0.335 68.030 147.025 68.050 ;
        RECT 0.610 67.210 147.025 68.030 ;
        RECT 0.335 67.190 147.025 67.210 ;
        RECT 0.610 66.370 146.750 67.190 ;
        RECT 0.335 66.350 147.025 66.370 ;
        RECT 0.610 65.530 147.025 66.350 ;
        RECT 0.335 65.510 147.025 65.530 ;
        RECT 0.610 64.690 146.750 65.510 ;
        RECT 0.335 64.670 147.025 64.690 ;
        RECT 0.610 63.850 147.025 64.670 ;
        RECT 0.335 63.830 147.025 63.850 ;
        RECT 0.610 63.010 146.750 63.830 ;
        RECT 0.335 62.990 147.025 63.010 ;
        RECT 0.610 62.170 147.025 62.990 ;
        RECT 0.335 62.150 147.025 62.170 ;
        RECT 0.610 61.330 146.750 62.150 ;
        RECT 0.335 61.310 147.025 61.330 ;
        RECT 0.610 60.490 147.025 61.310 ;
        RECT 0.335 60.470 147.025 60.490 ;
        RECT 0.610 59.650 146.750 60.470 ;
        RECT 0.335 59.630 147.025 59.650 ;
        RECT 0.610 58.810 147.025 59.630 ;
        RECT 0.335 58.790 147.025 58.810 ;
        RECT 0.610 57.970 147.025 58.790 ;
        RECT 0.335 57.950 147.025 57.970 ;
        RECT 0.610 57.130 147.025 57.950 ;
        RECT 0.335 57.110 147.025 57.130 ;
        RECT 0.610 56.290 147.025 57.110 ;
        RECT 0.335 56.270 147.025 56.290 ;
        RECT 0.610 55.450 147.025 56.270 ;
        RECT 0.335 55.430 147.025 55.450 ;
        RECT 0.610 54.610 147.025 55.430 ;
        RECT 0.335 54.590 147.025 54.610 ;
        RECT 0.610 53.770 147.025 54.590 ;
        RECT 0.335 53.750 147.025 53.770 ;
        RECT 0.610 52.930 147.025 53.750 ;
        RECT 0.335 52.910 147.025 52.930 ;
        RECT 0.610 52.090 146.750 52.910 ;
        RECT 0.335 52.070 147.025 52.090 ;
        RECT 0.335 51.250 146.750 52.070 ;
        RECT 0.335 51.230 147.025 51.250 ;
        RECT 0.335 50.410 146.750 51.230 ;
        RECT 0.335 50.390 147.025 50.410 ;
        RECT 0.335 49.570 146.750 50.390 ;
        RECT 0.335 49.550 147.025 49.570 ;
        RECT 0.335 48.730 146.750 49.550 ;
        RECT 0.335 48.710 147.025 48.730 ;
        RECT 0.335 47.890 146.750 48.710 ;
        RECT 0.335 47.870 147.025 47.890 ;
        RECT 0.335 47.050 146.750 47.870 ;
        RECT 0.335 47.030 147.025 47.050 ;
        RECT 0.335 46.210 146.750 47.030 ;
        RECT 0.335 46.190 147.025 46.210 ;
        RECT 0.335 45.370 146.750 46.190 ;
        RECT 0.335 45.350 147.025 45.370 ;
        RECT 0.335 44.530 146.750 45.350 ;
        RECT 0.335 44.510 147.025 44.530 ;
        RECT 0.335 43.690 146.750 44.510 ;
        RECT 0.335 43.670 147.025 43.690 ;
        RECT 0.335 42.850 146.750 43.670 ;
        RECT 0.335 42.830 147.025 42.850 ;
        RECT 0.335 42.010 146.750 42.830 ;
        RECT 0.335 41.990 147.025 42.010 ;
        RECT 0.335 41.170 146.750 41.990 ;
        RECT 0.335 41.150 147.025 41.170 ;
        RECT 0.335 40.330 146.750 41.150 ;
        RECT 0.335 40.310 147.025 40.330 ;
        RECT 0.335 39.490 146.750 40.310 ;
        RECT 0.335 32.750 147.025 39.490 ;
        RECT 0.335 31.930 146.750 32.750 ;
        RECT 0.335 31.910 147.025 31.930 ;
        RECT 0.610 31.090 147.025 31.910 ;
        RECT 0.335 31.070 147.025 31.090 ;
        RECT 0.610 30.250 146.750 31.070 ;
        RECT 0.335 30.230 147.025 30.250 ;
        RECT 0.610 29.410 147.025 30.230 ;
        RECT 0.335 29.390 147.025 29.410 ;
        RECT 0.610 28.570 146.750 29.390 ;
        RECT 0.335 28.550 147.025 28.570 ;
        RECT 0.610 27.730 147.025 28.550 ;
        RECT 0.335 27.710 147.025 27.730 ;
        RECT 0.610 26.890 146.750 27.710 ;
        RECT 0.335 26.870 147.025 26.890 ;
        RECT 0.610 26.050 147.025 26.870 ;
        RECT 0.335 26.030 147.025 26.050 ;
        RECT 0.610 25.210 146.750 26.030 ;
        RECT 0.335 25.190 147.025 25.210 ;
        RECT 0.610 24.370 147.025 25.190 ;
        RECT 0.335 24.350 147.025 24.370 ;
        RECT 0.610 23.530 146.750 24.350 ;
        RECT 0.335 23.510 147.025 23.530 ;
        RECT 0.610 22.690 147.025 23.510 ;
        RECT 0.335 22.670 147.025 22.690 ;
        RECT 0.610 21.850 146.750 22.670 ;
        RECT 0.335 21.830 147.025 21.850 ;
        RECT 0.610 21.010 147.025 21.830 ;
        RECT 0.335 20.990 147.025 21.010 ;
        RECT 0.610 20.170 146.750 20.990 ;
        RECT 0.335 20.150 147.025 20.170 ;
        RECT 0.610 19.330 147.025 20.150 ;
        RECT 0.335 19.310 147.025 19.330 ;
        RECT 0.610 18.490 147.025 19.310 ;
        RECT 0.335 18.470 147.025 18.490 ;
        RECT 0.610 17.650 147.025 18.470 ;
        RECT 0.335 17.630 147.025 17.650 ;
        RECT 0.610 16.810 147.025 17.630 ;
        RECT 0.335 16.790 147.025 16.810 ;
        RECT 0.610 15.970 146.750 16.790 ;
        RECT 0.335 15.950 147.025 15.970 ;
        RECT 0.610 15.130 146.750 15.950 ;
        RECT 0.335 15.110 147.025 15.130 ;
        RECT 0.610 14.290 146.750 15.110 ;
        RECT 0.335 14.270 147.025 14.290 ;
        RECT 0.610 13.450 146.750 14.270 ;
        RECT 0.335 13.430 147.025 13.450 ;
        RECT 0.610 12.610 146.750 13.430 ;
        RECT 0.335 12.590 147.025 12.610 ;
        RECT 0.610 11.770 146.750 12.590 ;
        RECT 0.335 11.750 147.025 11.770 ;
        RECT 0.610 10.930 146.750 11.750 ;
        RECT 0.335 10.910 147.025 10.930 ;
        RECT 0.610 10.090 146.750 10.910 ;
        RECT 0.335 10.070 147.025 10.090 ;
        RECT 0.610 9.250 147.025 10.070 ;
        RECT 0.335 9.230 147.025 9.250 ;
        RECT 0.610 8.410 147.025 9.230 ;
        RECT 0.335 8.390 147.025 8.410 ;
        RECT 0.610 7.570 147.025 8.390 ;
        RECT 0.335 7.550 147.025 7.570 ;
        RECT 0.610 6.730 147.025 7.550 ;
        RECT 0.335 6.710 147.025 6.730 ;
        RECT 0.610 5.890 146.750 6.710 ;
        RECT 0.335 5.870 147.025 5.890 ;
        RECT 0.610 5.050 147.025 5.870 ;
        RECT 0.335 5.030 147.025 5.050 ;
        RECT 0.335 4.210 146.750 5.030 ;
        RECT 0.335 3.350 147.025 4.210 ;
        RECT 0.335 2.530 146.750 3.350 ;
        RECT 0.335 1.670 147.025 2.530 ;
        RECT 0.610 0.850 146.750 1.670 ;
        RECT 0.335 0.315 147.025 0.850 ;
      LAYER Metal4 ;
        RECT 0.380 0.275 15.170 1292.485 ;
        RECT 17.790 0.275 21.370 1292.485 ;
        RECT 23.990 0.275 90.770 1292.485 ;
        RECT 93.390 0.275 96.970 1292.485 ;
        RECT 99.590 0.275 146.980 1292.485 ;
      LAYER TopMetal1 ;
        RECT 2.540 64.660 128.020 1204.020 ;
  END
END AXI_M_IO_W
END LIBRARY

